VERSION 5.8 ;
BUSBITCHARS "[]" ;
DIVIDERCHAR "/" ;
UNITS
    DATABASE MICRONS 1000 ;
END UNITS

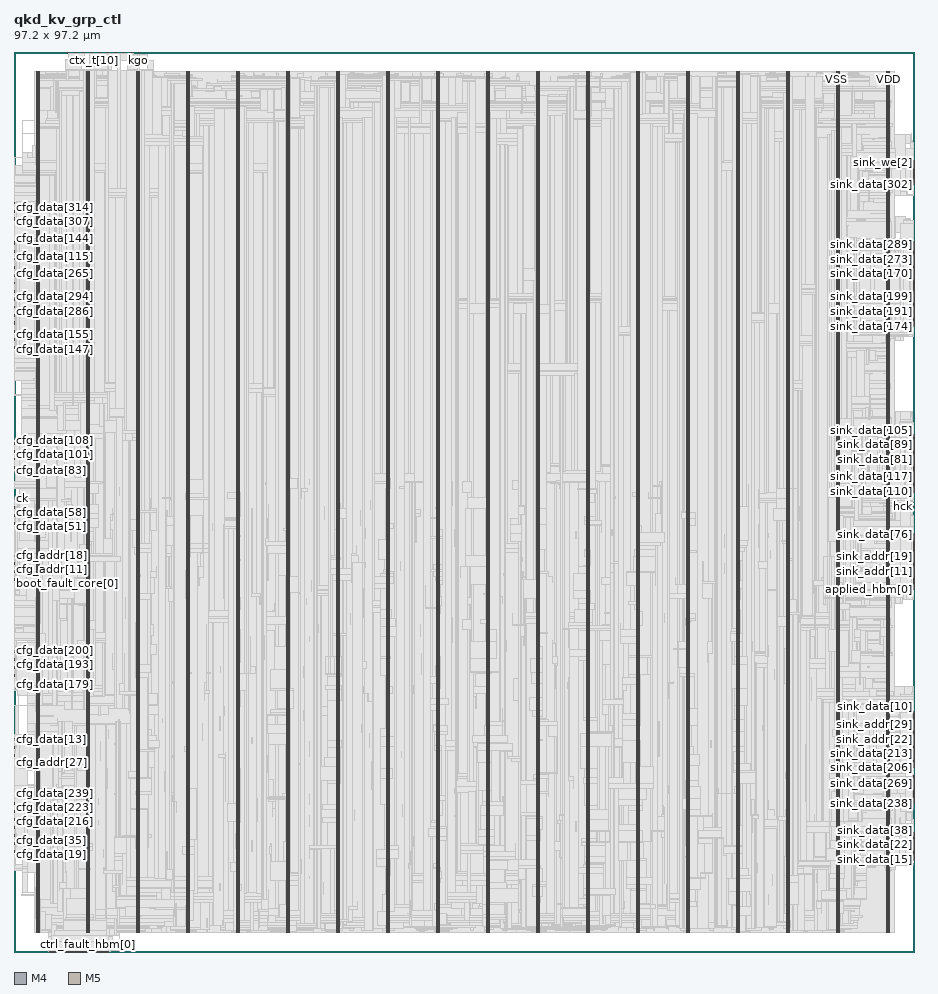
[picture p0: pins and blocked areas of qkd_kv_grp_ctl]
MACRO qkd_kv_grp_ctl
  FOREIGN qkd_kv_grp_ctl 0 0 ;
  CLASS BLOCK ;
  SIZE 97.2 BY 97.2 ;
  PIN applied_hbm[0]
    DIRECTION OUTPUT ;
    USE SIGNAL ;
    PORT
      LAYER M4 ;
        RECT  97.116 39.12 97.2 39.144 ;
    END
  END applied_hbm[0]
  PIN applied_hbm[1]
    DIRECTION OUTPUT ;
    USE SIGNAL ;
    PORT
      LAYER M4 ;
        RECT  97.116 39.216 97.2 39.24 ;
    END
  END applied_hbm[1]
  PIN applied_hbm[2]
    DIRECTION OUTPUT ;
    USE SIGNAL ;
    PORT
      LAYER M4 ;
        RECT  97.116 39.312 97.2 39.336 ;
    END
  END applied_hbm[2]
  PIN applied_hbm[3]
    DIRECTION OUTPUT ;
    USE SIGNAL ;
    PORT
      LAYER M4 ;
        RECT  97.116 39.408 97.2 39.432 ;
    END
  END applied_hbm[3]
  PIN applied_hbm[4]
    DIRECTION OUTPUT ;
    USE SIGNAL ;
    PORT
      LAYER M4 ;
        RECT  97.116 39.504 97.2 39.528 ;
    END
  END applied_hbm[4]
  PIN boot_fault_core[0]
    DIRECTION OUTPUT ;
    USE SIGNAL ;
    PORT
      LAYER M4 ;
        RECT  0 39.792 0.084 39.816 ;
    END
  END boot_fault_core[0]
  PIN boot_fault_core[1]
    DIRECTION OUTPUT ;
    USE SIGNAL ;
    PORT
      LAYER M4 ;
        RECT  0 39.888 0.084 39.912 ;
    END
  END boot_fault_core[1]
  PIN boot_fault_core[2]
    DIRECTION OUTPUT ;
    USE SIGNAL ;
    PORT
      LAYER M4 ;
        RECT  0 39.984 0.084 40.008 ;
    END
  END boot_fault_core[2]
  PIN boot_fault_core[3]
    DIRECTION OUTPUT ;
    USE SIGNAL ;
    PORT
      LAYER M4 ;
        RECT  0 40.08 0.084 40.104 ;
    END
  END boot_fault_core[3]
  PIN boot_fault_core[4]
    DIRECTION OUTPUT ;
    USE SIGNAL ;
    PORT
      LAYER M4 ;
        RECT  0 40.176 0.084 40.2 ;
    END
  END boot_fault_core[4]
  PIN boot_fault_hbm[0]
    DIRECTION OUTPUT ;
    USE SIGNAL ;
    PORT
      LAYER M4 ;
        RECT  97.116 39.6 97.2 39.624 ;
    END
  END boot_fault_hbm[0]
  PIN boot_fault_hbm[1]
    DIRECTION OUTPUT ;
    USE SIGNAL ;
    PORT
      LAYER M4 ;
        RECT  97.116 39.696 97.2 39.72 ;
    END
  END boot_fault_hbm[1]
  PIN boot_fault_hbm[2]
    DIRECTION OUTPUT ;
    USE SIGNAL ;
    PORT
      LAYER M4 ;
        RECT  97.116 39.792 97.2 39.816 ;
    END
  END boot_fault_hbm[2]
  PIN boot_fault_hbm[3]
    DIRECTION OUTPUT ;
    USE SIGNAL ;
    PORT
      LAYER M4 ;
        RECT  97.116 39.888 97.2 39.912 ;
    END
  END boot_fault_hbm[3]
  PIN boot_fault_hbm[4]
    DIRECTION OUTPUT ;
    USE SIGNAL ;
    PORT
      LAYER M4 ;
        RECT  97.116 39.984 97.2 40.008 ;
    END
  END boot_fault_hbm[4]
  PIN cfg_addr[0]
    DIRECTION INPUT ;
    USE SIGNAL ;
    PORT
      LAYER M4 ;
        RECT  0 40.272 0.084 40.296 ;
    END
  END cfg_addr[0]
  PIN cfg_addr[10]
    DIRECTION INPUT ;
    USE SIGNAL ;
    PORT
      LAYER M4 ;
        RECT  0 41.232 0.084 41.256 ;
    END
  END cfg_addr[10]
  PIN cfg_addr[11]
    DIRECTION INPUT ;
    USE SIGNAL ;
    PORT
      LAYER M4 ;
        RECT  0 41.328 0.084 41.352 ;
    END
  END cfg_addr[11]
  PIN cfg_addr[12]
    DIRECTION INPUT ;
    USE SIGNAL ;
    PORT
      LAYER M4 ;
        RECT  0 41.424 0.084 41.448 ;
    END
  END cfg_addr[12]
  PIN cfg_addr[13]
    DIRECTION INPUT ;
    USE SIGNAL ;
    PORT
      LAYER M4 ;
        RECT  0 41.52 0.084 41.544 ;
    END
  END cfg_addr[13]
  PIN cfg_addr[14]
    DIRECTION INPUT ;
    USE SIGNAL ;
    PORT
      LAYER M4 ;
        RECT  0 41.616 0.084 41.64 ;
    END
  END cfg_addr[14]
  PIN cfg_addr[15]
    DIRECTION INPUT ;
    USE SIGNAL ;
    PORT
      LAYER M4 ;
        RECT  0 41.712 0.084 41.736 ;
    END
  END cfg_addr[15]
  PIN cfg_addr[16]
    DIRECTION INPUT ;
    USE SIGNAL ;
    PORT
      LAYER M4 ;
        RECT  0 41.808 0.084 41.832 ;
    END
  END cfg_addr[16]
  PIN cfg_addr[17]
    DIRECTION INPUT ;
    USE SIGNAL ;
    PORT
      LAYER M4 ;
        RECT  0 41.904 0.084 41.928 ;
    END
  END cfg_addr[17]
  PIN cfg_addr[18]
    DIRECTION INPUT ;
    USE SIGNAL ;
    PORT
      LAYER M4 ;
        RECT  0 42 0.084 42.024 ;
    END
  END cfg_addr[18]
  PIN cfg_addr[19]
    DIRECTION INPUT ;
    USE SIGNAL ;
    PORT
      LAYER M4 ;
        RECT  0 42.096 0.084 42.12 ;
    END
  END cfg_addr[19]
  PIN cfg_addr[1]
    DIRECTION INPUT ;
    USE SIGNAL ;
    PORT
      LAYER M4 ;
        RECT  0 40.368 0.084 40.392 ;
    END
  END cfg_addr[1]
  PIN cfg_addr[20]
    DIRECTION INPUT ;
    USE SIGNAL ;
    PORT
      LAYER M4 ;
        RECT  0 42.192 0.084 42.216 ;
    END
  END cfg_addr[20]
  PIN cfg_addr[21]
    DIRECTION INPUT ;
    USE SIGNAL ;
    PORT
      LAYER M4 ;
        RECT  0 42.288 0.084 42.312 ;
    END
  END cfg_addr[21]
  PIN cfg_addr[22]
    DIRECTION INPUT ;
    USE SIGNAL ;
    PORT
      LAYER M4 ;
        RECT  0 42.384 0.084 42.408 ;
    END
  END cfg_addr[22]
  PIN cfg_addr[23]
    DIRECTION INPUT ;
    USE SIGNAL ;
    PORT
      LAYER M4 ;
        RECT  0 42.48 0.084 42.504 ;
    END
  END cfg_addr[23]
  PIN cfg_addr[24]
    DIRECTION INPUT ;
    USE SIGNAL ;
    PORT
      LAYER M4 ;
        RECT  0 42.576 0.084 42.6 ;
    END
  END cfg_addr[24]
  PIN cfg_addr[25]
    DIRECTION INPUT ;
    USE SIGNAL ;
    PORT
      LAYER M4 ;
        RECT  0 42.672 0.084 42.696 ;
    END
  END cfg_addr[25]
  PIN cfg_addr[26]
    DIRECTION INPUT ;
    USE SIGNAL ;
    PORT
      LAYER M4 ;
        RECT  0 42.768 0.084 42.792 ;
    END
  END cfg_addr[26]
  PIN cfg_addr[27]
    DIRECTION INPUT ;
    USE SIGNAL ;
    PORT
      LAYER M4 ;
        RECT  0 20.496 0.084 20.52 ;
    END
  END cfg_addr[27]
  PIN cfg_addr[28]
    DIRECTION INPUT ;
    USE SIGNAL ;
    PORT
      LAYER M4 ;
        RECT  0 20.592 0.084 20.616 ;
    END
  END cfg_addr[28]
  PIN cfg_addr[29]
    DIRECTION INPUT ;
    USE SIGNAL ;
    PORT
      LAYER M4 ;
        RECT  0 20.688 0.084 20.712 ;
    END
  END cfg_addr[29]
  PIN cfg_addr[2]
    DIRECTION INPUT ;
    USE SIGNAL ;
    PORT
      LAYER M4 ;
        RECT  0 40.464 0.084 40.488 ;
    END
  END cfg_addr[2]
  PIN cfg_addr[30]
    DIRECTION INPUT ;
    USE SIGNAL ;
    PORT
      LAYER M4 ;
        RECT  0 20.784 0.084 20.808 ;
    END
  END cfg_addr[30]
  PIN cfg_addr[31]
    DIRECTION INPUT ;
    USE SIGNAL ;
    PORT
      LAYER M4 ;
        RECT  0 20.88 0.084 20.904 ;
    END
  END cfg_addr[31]
  PIN cfg_addr[32]
    DIRECTION INPUT ;
    USE SIGNAL ;
    PORT
      LAYER M4 ;
        RECT  0 20.976 0.084 21 ;
    END
  END cfg_addr[32]
  PIN cfg_addr[33]
    DIRECTION INPUT ;
    USE SIGNAL ;
    PORT
      LAYER M4 ;
        RECT  0 21.072 0.084 21.096 ;
    END
  END cfg_addr[33]
  PIN cfg_addr[34]
    DIRECTION INPUT ;
    USE SIGNAL ;
    PORT
      LAYER M4 ;
        RECT  0 21.168 0.084 21.192 ;
    END
  END cfg_addr[34]
  PIN cfg_addr[35]
    DIRECTION INPUT ;
    USE SIGNAL ;
    PORT
      LAYER M4 ;
        RECT  0 21.264 0.084 21.288 ;
    END
  END cfg_addr[35]
  PIN cfg_addr[36]
    DIRECTION INPUT ;
    USE SIGNAL ;
    PORT
      LAYER M4 ;
        RECT  0 21.36 0.084 21.384 ;
    END
  END cfg_addr[36]
  PIN cfg_addr[37]
    DIRECTION INPUT ;
    USE SIGNAL ;
    PORT
      LAYER M4 ;
        RECT  0 21.456 0.084 21.48 ;
    END
  END cfg_addr[37]
  PIN cfg_addr[38]
    DIRECTION INPUT ;
    USE SIGNAL ;
    PORT
      LAYER M4 ;
        RECT  0 21.552 0.084 21.576 ;
    END
  END cfg_addr[38]
  PIN cfg_addr[39]
    DIRECTION INPUT ;
    USE SIGNAL ;
    PORT
      LAYER M4 ;
        RECT  0 21.648 0.084 21.672 ;
    END
  END cfg_addr[39]
  PIN cfg_addr[3]
    DIRECTION INPUT ;
    USE SIGNAL ;
    PORT
      LAYER M4 ;
        RECT  0 40.56 0.084 40.584 ;
    END
  END cfg_addr[3]
  PIN cfg_addr[4]
    DIRECTION INPUT ;
    USE SIGNAL ;
    PORT
      LAYER M4 ;
        RECT  0 40.656 0.084 40.68 ;
    END
  END cfg_addr[4]
  PIN cfg_addr[5]
    DIRECTION INPUT ;
    USE SIGNAL ;
    PORT
      LAYER M4 ;
        RECT  0 40.752 0.084 40.776 ;
    END
  END cfg_addr[5]
  PIN cfg_addr[6]
    DIRECTION INPUT ;
    USE SIGNAL ;
    PORT
      LAYER M4 ;
        RECT  0 40.848 0.084 40.872 ;
    END
  END cfg_addr[6]
  PIN cfg_addr[7]
    DIRECTION INPUT ;
    USE SIGNAL ;
    PORT
      LAYER M4 ;
        RECT  0 40.944 0.084 40.968 ;
    END
  END cfg_addr[7]
  PIN cfg_addr[8]
    DIRECTION INPUT ;
    USE SIGNAL ;
    PORT
      LAYER M4 ;
        RECT  0 41.04 0.084 41.064 ;
    END
  END cfg_addr[8]
  PIN cfg_addr[9]
    DIRECTION INPUT ;
    USE SIGNAL ;
    PORT
      LAYER M4 ;
        RECT  0 41.136 0.084 41.16 ;
    END
  END cfg_addr[9]
  PIN cfg_data[0]
    DIRECTION INPUT ;
    USE SIGNAL ;
    PORT
      LAYER M4 ;
        RECT  0 21.744 0.084 21.768 ;
    END
  END cfg_data[0]
  PIN cfg_data[100]
    DIRECTION INPUT ;
    USE SIGNAL ;
    PORT
      LAYER M4 ;
        RECT  0 53.616 0.084 53.64 ;
    END
  END cfg_data[100]
  PIN cfg_data[101]
    DIRECTION INPUT ;
    USE SIGNAL ;
    PORT
      LAYER M4 ;
        RECT  0 53.712 0.084 53.736 ;
    END
  END cfg_data[101]
  PIN cfg_data[102]
    DIRECTION INPUT ;
    USE SIGNAL ;
    PORT
      LAYER M4 ;
        RECT  0 53.808 0.084 53.832 ;
    END
  END cfg_data[102]
  PIN cfg_data[103]
    DIRECTION INPUT ;
    USE SIGNAL ;
    PORT
      LAYER M4 ;
        RECT  0 53.904 0.084 53.928 ;
    END
  END cfg_data[103]
  PIN cfg_data[104]
    DIRECTION INPUT ;
    USE SIGNAL ;
    PORT
      LAYER M4 ;
        RECT  0 54 0.084 54.024 ;
    END
  END cfg_data[104]
  PIN cfg_data[105]
    DIRECTION INPUT ;
    USE SIGNAL ;
    PORT
      LAYER M4 ;
        RECT  0 54.096 0.084 54.12 ;
    END
  END cfg_data[105]
  PIN cfg_data[106]
    DIRECTION INPUT ;
    USE SIGNAL ;
    PORT
      LAYER M4 ;
        RECT  0 54.192 0.084 54.216 ;
    END
  END cfg_data[106]
  PIN cfg_data[107]
    DIRECTION INPUT ;
    USE SIGNAL ;
    PORT
      LAYER M4 ;
        RECT  0 54.288 0.084 54.312 ;
    END
  END cfg_data[107]
  PIN cfg_data[108]
    DIRECTION INPUT ;
    USE SIGNAL ;
    PORT
      LAYER M4 ;
        RECT  0 54.384 0.084 54.408 ;
    END
  END cfg_data[108]
  PIN cfg_data[109]
    DIRECTION INPUT ;
    USE SIGNAL ;
    PORT
      LAYER M4 ;
        RECT  0 54.48 0.084 54.504 ;
    END
  END cfg_data[109]
  PIN cfg_data[10]
    DIRECTION INPUT ;
    USE SIGNAL ;
    PORT
      LAYER M4 ;
        RECT  0 22.704 0.084 22.728 ;
    END
  END cfg_data[10]
  PIN cfg_data[110]
    DIRECTION INPUT ;
    USE SIGNAL ;
    PORT
      LAYER M4 ;
        RECT  0 54.576 0.084 54.6 ;
    END
  END cfg_data[110]
  PIN cfg_data[111]
    DIRECTION INPUT ;
    USE SIGNAL ;
    PORT
      LAYER M4 ;
        RECT  0 54.672 0.084 54.696 ;
    END
  END cfg_data[111]
  PIN cfg_data[112]
    DIRECTION INPUT ;
    USE SIGNAL ;
    PORT
      LAYER M4 ;
        RECT  0 54.768 0.084 54.792 ;
    END
  END cfg_data[112]
  PIN cfg_data[113]
    DIRECTION INPUT ;
    USE SIGNAL ;
    PORT
      LAYER M4 ;
        RECT  0 54.864 0.084 54.888 ;
    END
  END cfg_data[113]
  PIN cfg_data[114]
    DIRECTION INPUT ;
    USE SIGNAL ;
    PORT
      LAYER M4 ;
        RECT  0 54.96 0.084 54.984 ;
    END
  END cfg_data[114]
  PIN cfg_data[115]
    DIRECTION INPUT ;
    USE SIGNAL ;
    PORT
      LAYER M4 ;
        RECT  0 74.256 0.084 74.28 ;
    END
  END cfg_data[115]
  PIN cfg_data[116]
    DIRECTION INPUT ;
    USE SIGNAL ;
    PORT
      LAYER M4 ;
        RECT  0 74.352 0.084 74.376 ;
    END
  END cfg_data[116]
  PIN cfg_data[117]
    DIRECTION INPUT ;
    USE SIGNAL ;
    PORT
      LAYER M4 ;
        RECT  0 74.448 0.084 74.472 ;
    END
  END cfg_data[117]
  PIN cfg_data[118]
    DIRECTION INPUT ;
    USE SIGNAL ;
    PORT
      LAYER M4 ;
        RECT  0 74.544 0.084 74.568 ;
    END
  END cfg_data[118]
  PIN cfg_data[119]
    DIRECTION INPUT ;
    USE SIGNAL ;
    PORT
      LAYER M4 ;
        RECT  0 74.64 0.084 74.664 ;
    END
  END cfg_data[119]
  PIN cfg_data[11]
    DIRECTION INPUT ;
    USE SIGNAL ;
    PORT
      LAYER M4 ;
        RECT  0 22.8 0.084 22.824 ;
    END
  END cfg_data[11]
  PIN cfg_data[120]
    DIRECTION INPUT ;
    USE SIGNAL ;
    PORT
      LAYER M4 ;
        RECT  0 74.736 0.084 74.76 ;
    END
  END cfg_data[120]
  PIN cfg_data[121]
    DIRECTION INPUT ;
    USE SIGNAL ;
    PORT
      LAYER M4 ;
        RECT  0 74.832 0.084 74.856 ;
    END
  END cfg_data[121]
  PIN cfg_data[122]
    DIRECTION INPUT ;
    USE SIGNAL ;
    PORT
      LAYER M4 ;
        RECT  0 74.928 0.084 74.952 ;
    END
  END cfg_data[122]
  PIN cfg_data[123]
    DIRECTION INPUT ;
    USE SIGNAL ;
    PORT
      LAYER M4 ;
        RECT  0 75.024 0.084 75.048 ;
    END
  END cfg_data[123]
  PIN cfg_data[124]
    DIRECTION INPUT ;
    USE SIGNAL ;
    PORT
      LAYER M4 ;
        RECT  0 75.12 0.084 75.144 ;
    END
  END cfg_data[124]
  PIN cfg_data[125]
    DIRECTION INPUT ;
    USE SIGNAL ;
    PORT
      LAYER M4 ;
        RECT  0 75.216 0.084 75.24 ;
    END
  END cfg_data[125]
  PIN cfg_data[126]
    DIRECTION INPUT ;
    USE SIGNAL ;
    PORT
      LAYER M4 ;
        RECT  0 75.312 0.084 75.336 ;
    END
  END cfg_data[126]
  PIN cfg_data[127]
    DIRECTION INPUT ;
    USE SIGNAL ;
    PORT
      LAYER M4 ;
        RECT  0 75.408 0.084 75.432 ;
    END
  END cfg_data[127]
  PIN cfg_data[128]
    DIRECTION INPUT ;
    USE SIGNAL ;
    PORT
      LAYER M4 ;
        RECT  0 75.504 0.084 75.528 ;
    END
  END cfg_data[128]
  PIN cfg_data[129]
    DIRECTION INPUT ;
    USE SIGNAL ;
    PORT
      LAYER M4 ;
        RECT  0 75.6 0.084 75.624 ;
    END
  END cfg_data[129]
  PIN cfg_data[12]
    DIRECTION INPUT ;
    USE SIGNAL ;
    PORT
      LAYER M4 ;
        RECT  0 22.896 0.084 22.92 ;
    END
  END cfg_data[12]
  PIN cfg_data[130]
    DIRECTION INPUT ;
    USE SIGNAL ;
    PORT
      LAYER M4 ;
        RECT  0 75.696 0.084 75.72 ;
    END
  END cfg_data[130]
  PIN cfg_data[131]
    DIRECTION INPUT ;
    USE SIGNAL ;
    PORT
      LAYER M4 ;
        RECT  0 75.792 0.084 75.816 ;
    END
  END cfg_data[131]
  PIN cfg_data[132]
    DIRECTION INPUT ;
    USE SIGNAL ;
    PORT
      LAYER M4 ;
        RECT  0 75.888 0.084 75.912 ;
    END
  END cfg_data[132]
  PIN cfg_data[133]
    DIRECTION INPUT ;
    USE SIGNAL ;
    PORT
      LAYER M4 ;
        RECT  0 75.984 0.084 76.008 ;
    END
  END cfg_data[133]
  PIN cfg_data[134]
    DIRECTION INPUT ;
    USE SIGNAL ;
    PORT
      LAYER M4 ;
        RECT  0 76.08 0.084 76.104 ;
    END
  END cfg_data[134]
  PIN cfg_data[135]
    DIRECTION INPUT ;
    USE SIGNAL ;
    PORT
      LAYER M4 ;
        RECT  0 76.176 0.084 76.2 ;
    END
  END cfg_data[135]
  PIN cfg_data[136]
    DIRECTION INPUT ;
    USE SIGNAL ;
    PORT
      LAYER M4 ;
        RECT  0 76.272 0.084 76.296 ;
    END
  END cfg_data[136]
  PIN cfg_data[137]
    DIRECTION INPUT ;
    USE SIGNAL ;
    PORT
      LAYER M4 ;
        RECT  0 76.368 0.084 76.392 ;
    END
  END cfg_data[137]
  PIN cfg_data[138]
    DIRECTION INPUT ;
    USE SIGNAL ;
    PORT
      LAYER M4 ;
        RECT  0 76.464 0.084 76.488 ;
    END
  END cfg_data[138]
  PIN cfg_data[139]
    DIRECTION INPUT ;
    USE SIGNAL ;
    PORT
      LAYER M4 ;
        RECT  0 76.56 0.084 76.584 ;
    END
  END cfg_data[139]
  PIN cfg_data[13]
    DIRECTION INPUT ;
    USE SIGNAL ;
    PORT
      LAYER M4 ;
        RECT  0 22.992 0.084 23.016 ;
    END
  END cfg_data[13]
  PIN cfg_data[140]
    DIRECTION INPUT ;
    USE SIGNAL ;
    PORT
      LAYER M4 ;
        RECT  0 76.656 0.084 76.68 ;
    END
  END cfg_data[140]
  PIN cfg_data[141]
    DIRECTION INPUT ;
    USE SIGNAL ;
    PORT
      LAYER M4 ;
        RECT  0 76.752 0.084 76.776 ;
    END
  END cfg_data[141]
  PIN cfg_data[142]
    DIRECTION INPUT ;
    USE SIGNAL ;
    PORT
      LAYER M4 ;
        RECT  0 76.848 0.084 76.872 ;
    END
  END cfg_data[142]
  PIN cfg_data[143]
    DIRECTION INPUT ;
    USE SIGNAL ;
    PORT
      LAYER M4 ;
        RECT  0 76.944 0.084 76.968 ;
    END
  END cfg_data[143]
  PIN cfg_data[144]
    DIRECTION INPUT ;
    USE SIGNAL ;
    PORT
      LAYER M4 ;
        RECT  0 77.04 0.084 77.064 ;
    END
  END cfg_data[144]
  PIN cfg_data[145]
    DIRECTION INPUT ;
    USE SIGNAL ;
    PORT
      LAYER M4 ;
        RECT  0 77.136 0.084 77.16 ;
    END
  END cfg_data[145]
  PIN cfg_data[146]
    DIRECTION INPUT ;
    USE SIGNAL ;
    PORT
      LAYER M4 ;
        RECT  0 77.232 0.084 77.256 ;
    END
  END cfg_data[146]
  PIN cfg_data[147]
    DIRECTION INPUT ;
    USE SIGNAL ;
    PORT
      LAYER M4 ;
        RECT  0 65.04 0.084 65.064 ;
    END
  END cfg_data[147]
  PIN cfg_data[148]
    DIRECTION INPUT ;
    USE SIGNAL ;
    PORT
      LAYER M4 ;
        RECT  0 65.136 0.084 65.16 ;
    END
  END cfg_data[148]
  PIN cfg_data[149]
    DIRECTION INPUT ;
    USE SIGNAL ;
    PORT
      LAYER M4 ;
        RECT  0 65.232 0.084 65.256 ;
    END
  END cfg_data[149]
  PIN cfg_data[14]
    DIRECTION INPUT ;
    USE SIGNAL ;
    PORT
      LAYER M4 ;
        RECT  0 23.088 0.084 23.112 ;
    END
  END cfg_data[14]
  PIN cfg_data[150]
    DIRECTION INPUT ;
    USE SIGNAL ;
    PORT
      LAYER M4 ;
        RECT  0 65.328 0.084 65.352 ;
    END
  END cfg_data[150]
  PIN cfg_data[151]
    DIRECTION INPUT ;
    USE SIGNAL ;
    PORT
      LAYER M4 ;
        RECT  0 65.424 0.084 65.448 ;
    END
  END cfg_data[151]
  PIN cfg_data[152]
    DIRECTION INPUT ;
    USE SIGNAL ;
    PORT
      LAYER M4 ;
        RECT  0 65.52 0.084 65.544 ;
    END
  END cfg_data[152]
  PIN cfg_data[153]
    DIRECTION INPUT ;
    USE SIGNAL ;
    PORT
      LAYER M4 ;
        RECT  0 65.616 0.084 65.64 ;
    END
  END cfg_data[153]
  PIN cfg_data[154]
    DIRECTION INPUT ;
    USE SIGNAL ;
    PORT
      LAYER M4 ;
        RECT  0 65.712 0.084 65.736 ;
    END
  END cfg_data[154]
  PIN cfg_data[155]
    DIRECTION INPUT ;
    USE SIGNAL ;
    PORT
      LAYER M4 ;
        RECT  0 65.808 0.084 65.832 ;
    END
  END cfg_data[155]
  PIN cfg_data[156]
    DIRECTION INPUT ;
    USE SIGNAL ;
    PORT
      LAYER M4 ;
        RECT  0 65.904 0.084 65.928 ;
    END
  END cfg_data[156]
  PIN cfg_data[157]
    DIRECTION INPUT ;
    USE SIGNAL ;
    PORT
      LAYER M4 ;
        RECT  0 66 0.084 66.024 ;
    END
  END cfg_data[157]
  PIN cfg_data[158]
    DIRECTION INPUT ;
    USE SIGNAL ;
    PORT
      LAYER M4 ;
        RECT  0 66.096 0.084 66.12 ;
    END
  END cfg_data[158]
  PIN cfg_data[159]
    DIRECTION INPUT ;
    USE SIGNAL ;
    PORT
      LAYER M4 ;
        RECT  0 66.192 0.084 66.216 ;
    END
  END cfg_data[159]
  PIN cfg_data[15]
    DIRECTION INPUT ;
    USE SIGNAL ;
    PORT
      LAYER M4 ;
        RECT  0 23.184 0.084 23.208 ;
    END
  END cfg_data[15]
  PIN cfg_data[160]
    DIRECTION INPUT ;
    USE SIGNAL ;
    PORT
      LAYER M4 ;
        RECT  0 66.288 0.084 66.312 ;
    END
  END cfg_data[160]
  PIN cfg_data[161]
    DIRECTION INPUT ;
    USE SIGNAL ;
    PORT
      LAYER M4 ;
        RECT  0 66.384 0.084 66.408 ;
    END
  END cfg_data[161]
  PIN cfg_data[162]
    DIRECTION INPUT ;
    USE SIGNAL ;
    PORT
      LAYER M4 ;
        RECT  0 66.48 0.084 66.504 ;
    END
  END cfg_data[162]
  PIN cfg_data[163]
    DIRECTION INPUT ;
    USE SIGNAL ;
    PORT
      LAYER M4 ;
        RECT  0 66.576 0.084 66.6 ;
    END
  END cfg_data[163]
  PIN cfg_data[164]
    DIRECTION INPUT ;
    USE SIGNAL ;
    PORT
      LAYER M4 ;
        RECT  0 66.672 0.084 66.696 ;
    END
  END cfg_data[164]
  PIN cfg_data[165]
    DIRECTION INPUT ;
    USE SIGNAL ;
    PORT
      LAYER M4 ;
        RECT  0 66.768 0.084 66.792 ;
    END
  END cfg_data[165]
  PIN cfg_data[166]
    DIRECTION INPUT ;
    USE SIGNAL ;
    PORT
      LAYER M4 ;
        RECT  0 66.864 0.084 66.888 ;
    END
  END cfg_data[166]
  PIN cfg_data[167]
    DIRECTION INPUT ;
    USE SIGNAL ;
    PORT
      LAYER M4 ;
        RECT  0 66.96 0.084 66.984 ;
    END
  END cfg_data[167]
  PIN cfg_data[168]
    DIRECTION INPUT ;
    USE SIGNAL ;
    PORT
      LAYER M4 ;
        RECT  0 67.056 0.084 67.08 ;
    END
  END cfg_data[168]
  PIN cfg_data[169]
    DIRECTION INPUT ;
    USE SIGNAL ;
    PORT
      LAYER M4 ;
        RECT  0 67.152 0.084 67.176 ;
    END
  END cfg_data[169]
  PIN cfg_data[16]
    DIRECTION INPUT ;
    USE SIGNAL ;
    PORT
      LAYER M4 ;
        RECT  0 23.28 0.084 23.304 ;
    END
  END cfg_data[16]
  PIN cfg_data[170]
    DIRECTION INPUT ;
    USE SIGNAL ;
    PORT
      LAYER M4 ;
        RECT  0 67.248 0.084 67.272 ;
    END
  END cfg_data[170]
  PIN cfg_data[171]
    DIRECTION INPUT ;
    USE SIGNAL ;
    PORT
      LAYER M4 ;
        RECT  0 67.344 0.084 67.368 ;
    END
  END cfg_data[171]
  PIN cfg_data[172]
    DIRECTION INPUT ;
    USE SIGNAL ;
    PORT
      LAYER M4 ;
        RECT  0 67.44 0.084 67.464 ;
    END
  END cfg_data[172]
  PIN cfg_data[173]
    DIRECTION INPUT ;
    USE SIGNAL ;
    PORT
      LAYER M4 ;
        RECT  0 67.536 0.084 67.56 ;
    END
  END cfg_data[173]
  PIN cfg_data[174]
    DIRECTION INPUT ;
    USE SIGNAL ;
    PORT
      LAYER M4 ;
        RECT  0 67.632 0.084 67.656 ;
    END
  END cfg_data[174]
  PIN cfg_data[175]
    DIRECTION INPUT ;
    USE SIGNAL ;
    PORT
      LAYER M4 ;
        RECT  0 67.728 0.084 67.752 ;
    END
  END cfg_data[175]
  PIN cfg_data[176]
    DIRECTION INPUT ;
    USE SIGNAL ;
    PORT
      LAYER M4 ;
        RECT  0 67.824 0.084 67.848 ;
    END
  END cfg_data[176]
  PIN cfg_data[177]
    DIRECTION INPUT ;
    USE SIGNAL ;
    PORT
      LAYER M4 ;
        RECT  0 67.92 0.084 67.944 ;
    END
  END cfg_data[177]
  PIN cfg_data[178]
    DIRECTION INPUT ;
    USE SIGNAL ;
    PORT
      LAYER M4 ;
        RECT  0 68.016 0.084 68.04 ;
    END
  END cfg_data[178]
  PIN cfg_data[179]
    DIRECTION INPUT ;
    USE SIGNAL ;
    PORT
      LAYER M4 ;
        RECT  0 29.712 0.084 29.736 ;
    END
  END cfg_data[179]
  PIN cfg_data[17]
    DIRECTION INPUT ;
    USE SIGNAL ;
    PORT
      LAYER M4 ;
        RECT  0 23.376 0.084 23.4 ;
    END
  END cfg_data[17]
  PIN cfg_data[180]
    DIRECTION INPUT ;
    USE SIGNAL ;
    PORT
      LAYER M4 ;
        RECT  0 29.808 0.084 29.832 ;
    END
  END cfg_data[180]
  PIN cfg_data[181]
    DIRECTION INPUT ;
    USE SIGNAL ;
    PORT
      LAYER M4 ;
        RECT  0 29.904 0.084 29.928 ;
    END
  END cfg_data[181]
  PIN cfg_data[182]
    DIRECTION INPUT ;
    USE SIGNAL ;
    PORT
      LAYER M4 ;
        RECT  0 30 0.084 30.024 ;
    END
  END cfg_data[182]
  PIN cfg_data[183]
    DIRECTION INPUT ;
    USE SIGNAL ;
    PORT
      LAYER M4 ;
        RECT  0 30.096 0.084 30.12 ;
    END
  END cfg_data[183]
  PIN cfg_data[184]
    DIRECTION INPUT ;
    USE SIGNAL ;
    PORT
      LAYER M4 ;
        RECT  0 30.192 0.084 30.216 ;
    END
  END cfg_data[184]
  PIN cfg_data[185]
    DIRECTION INPUT ;
    USE SIGNAL ;
    PORT
      LAYER M4 ;
        RECT  0 30.288 0.084 30.312 ;
    END
  END cfg_data[185]
  PIN cfg_data[186]
    DIRECTION INPUT ;
    USE SIGNAL ;
    PORT
      LAYER M4 ;
        RECT  0 30.384 0.084 30.408 ;
    END
  END cfg_data[186]
  PIN cfg_data[187]
    DIRECTION INPUT ;
    USE SIGNAL ;
    PORT
      LAYER M4 ;
        RECT  0 30.48 0.084 30.504 ;
    END
  END cfg_data[187]
  PIN cfg_data[188]
    DIRECTION INPUT ;
    USE SIGNAL ;
    PORT
      LAYER M4 ;
        RECT  0 30.576 0.084 30.6 ;
    END
  END cfg_data[188]
  PIN cfg_data[189]
    DIRECTION INPUT ;
    USE SIGNAL ;
    PORT
      LAYER M4 ;
        RECT  0 30.672 0.084 30.696 ;
    END
  END cfg_data[189]
  PIN cfg_data[18]
    DIRECTION INPUT ;
    USE SIGNAL ;
    PORT
      LAYER M4 ;
        RECT  0 23.472 0.084 23.496 ;
    END
  END cfg_data[18]
  PIN cfg_data[190]
    DIRECTION INPUT ;
    USE SIGNAL ;
    PORT
      LAYER M4 ;
        RECT  0 30.768 0.084 30.792 ;
    END
  END cfg_data[190]
  PIN cfg_data[191]
    DIRECTION INPUT ;
    USE SIGNAL ;
    PORT
      LAYER M4 ;
        RECT  0 30.864 0.084 30.888 ;
    END
  END cfg_data[191]
  PIN cfg_data[192]
    DIRECTION INPUT ;
    USE SIGNAL ;
    PORT
      LAYER M4 ;
        RECT  0 30.96 0.084 30.984 ;
    END
  END cfg_data[192]
  PIN cfg_data[193]
    DIRECTION INPUT ;
    USE SIGNAL ;
    PORT
      LAYER M4 ;
        RECT  0 31.056 0.084 31.08 ;
    END
  END cfg_data[193]
  PIN cfg_data[194]
    DIRECTION INPUT ;
    USE SIGNAL ;
    PORT
      LAYER M4 ;
        RECT  0 31.152 0.084 31.176 ;
    END
  END cfg_data[194]
  PIN cfg_data[195]
    DIRECTION INPUT ;
    USE SIGNAL ;
    PORT
      LAYER M4 ;
        RECT  0 31.248 0.084 31.272 ;
    END
  END cfg_data[195]
  PIN cfg_data[196]
    DIRECTION INPUT ;
    USE SIGNAL ;
    PORT
      LAYER M4 ;
        RECT  0 31.344 0.084 31.368 ;
    END
  END cfg_data[196]
  PIN cfg_data[197]
    DIRECTION INPUT ;
    USE SIGNAL ;
    PORT
      LAYER M4 ;
        RECT  0 31.44 0.084 31.464 ;
    END
  END cfg_data[197]
  PIN cfg_data[198]
    DIRECTION INPUT ;
    USE SIGNAL ;
    PORT
      LAYER M4 ;
        RECT  0 31.536 0.084 31.56 ;
    END
  END cfg_data[198]
  PIN cfg_data[199]
    DIRECTION INPUT ;
    USE SIGNAL ;
    PORT
      LAYER M4 ;
        RECT  0 31.632 0.084 31.656 ;
    END
  END cfg_data[199]
  PIN cfg_data[19]
    DIRECTION INPUT ;
    USE SIGNAL ;
    PORT
      LAYER M4 ;
        RECT  0 10.512 0.084 10.536 ;
    END
  END cfg_data[19]
  PIN cfg_data[1]
    DIRECTION INPUT ;
    USE SIGNAL ;
    PORT
      LAYER M4 ;
        RECT  0 21.84 0.084 21.864 ;
    END
  END cfg_data[1]
  PIN cfg_data[200]
    DIRECTION INPUT ;
    USE SIGNAL ;
    PORT
      LAYER M4 ;
        RECT  0 31.728 0.084 31.752 ;
    END
  END cfg_data[200]
  PIN cfg_data[201]
    DIRECTION INPUT ;
    USE SIGNAL ;
    PORT
      LAYER M4 ;
        RECT  0 31.824 0.084 31.848 ;
    END
  END cfg_data[201]
  PIN cfg_data[202]
    DIRECTION INPUT ;
    USE SIGNAL ;
    PORT
      LAYER M4 ;
        RECT  0 31.92 0.084 31.944 ;
    END
  END cfg_data[202]
  PIN cfg_data[203]
    DIRECTION INPUT ;
    USE SIGNAL ;
    PORT
      LAYER M4 ;
        RECT  0 32.016 0.084 32.04 ;
    END
  END cfg_data[203]
  PIN cfg_data[204]
    DIRECTION INPUT ;
    USE SIGNAL ;
    PORT
      LAYER M4 ;
        RECT  0 32.112 0.084 32.136 ;
    END
  END cfg_data[204]
  PIN cfg_data[205]
    DIRECTION INPUT ;
    USE SIGNAL ;
    PORT
      LAYER M4 ;
        RECT  0 32.208 0.084 32.232 ;
    END
  END cfg_data[205]
  PIN cfg_data[206]
    DIRECTION INPUT ;
    USE SIGNAL ;
    PORT
      LAYER M4 ;
        RECT  0 32.304 0.084 32.328 ;
    END
  END cfg_data[206]
  PIN cfg_data[207]
    DIRECTION INPUT ;
    USE SIGNAL ;
    PORT
      LAYER M4 ;
        RECT  0 32.4 0.084 32.424 ;
    END
  END cfg_data[207]
  PIN cfg_data[208]
    DIRECTION INPUT ;
    USE SIGNAL ;
    PORT
      LAYER M4 ;
        RECT  0 32.496 0.084 32.52 ;
    END
  END cfg_data[208]
  PIN cfg_data[209]
    DIRECTION INPUT ;
    USE SIGNAL ;
    PORT
      LAYER M4 ;
        RECT  0 32.592 0.084 32.616 ;
    END
  END cfg_data[209]
  PIN cfg_data[20]
    DIRECTION INPUT ;
    USE SIGNAL ;
    PORT
      LAYER M4 ;
        RECT  0 10.608 0.084 10.632 ;
    END
  END cfg_data[20]
  PIN cfg_data[210]
    DIRECTION INPUT ;
    USE SIGNAL ;
    PORT
      LAYER M4 ;
        RECT  0 32.688 0.084 32.712 ;
    END
  END cfg_data[210]
  PIN cfg_data[211]
    DIRECTION INPUT ;
    USE SIGNAL ;
    PORT
      LAYER M4 ;
        RECT  0 13.584 0.084 13.608 ;
    END
  END cfg_data[211]
  PIN cfg_data[212]
    DIRECTION INPUT ;
    USE SIGNAL ;
    PORT
      LAYER M4 ;
        RECT  0 13.68 0.084 13.704 ;
    END
  END cfg_data[212]
  PIN cfg_data[213]
    DIRECTION INPUT ;
    USE SIGNAL ;
    PORT
      LAYER M4 ;
        RECT  0 13.776 0.084 13.8 ;
    END
  END cfg_data[213]
  PIN cfg_data[214]
    DIRECTION INPUT ;
    USE SIGNAL ;
    PORT
      LAYER M4 ;
        RECT  0 13.872 0.084 13.896 ;
    END
  END cfg_data[214]
  PIN cfg_data[215]
    DIRECTION INPUT ;
    USE SIGNAL ;
    PORT
      LAYER M4 ;
        RECT  0 13.968 0.084 13.992 ;
    END
  END cfg_data[215]
  PIN cfg_data[216]
    DIRECTION INPUT ;
    USE SIGNAL ;
    PORT
      LAYER M4 ;
        RECT  0 14.064 0.084 14.088 ;
    END
  END cfg_data[216]
  PIN cfg_data[217]
    DIRECTION INPUT ;
    USE SIGNAL ;
    PORT
      LAYER M4 ;
        RECT  0 14.16 0.084 14.184 ;
    END
  END cfg_data[217]
  PIN cfg_data[218]
    DIRECTION INPUT ;
    USE SIGNAL ;
    PORT
      LAYER M4 ;
        RECT  0 14.256 0.084 14.28 ;
    END
  END cfg_data[218]
  PIN cfg_data[219]
    DIRECTION INPUT ;
    USE SIGNAL ;
    PORT
      LAYER M4 ;
        RECT  0 14.352 0.084 14.376 ;
    END
  END cfg_data[219]
  PIN cfg_data[21]
    DIRECTION INPUT ;
    USE SIGNAL ;
    PORT
      LAYER M4 ;
        RECT  0 10.704 0.084 10.728 ;
    END
  END cfg_data[21]
  PIN cfg_data[220]
    DIRECTION INPUT ;
    USE SIGNAL ;
    PORT
      LAYER M4 ;
        RECT  0 14.448 0.084 14.472 ;
    END
  END cfg_data[220]
  PIN cfg_data[221]
    DIRECTION INPUT ;
    USE SIGNAL ;
    PORT
      LAYER M4 ;
        RECT  0 14.544 0.084 14.568 ;
    END
  END cfg_data[221]
  PIN cfg_data[222]
    DIRECTION INPUT ;
    USE SIGNAL ;
    PORT
      LAYER M4 ;
        RECT  0 14.64 0.084 14.664 ;
    END
  END cfg_data[222]
  PIN cfg_data[223]
    DIRECTION INPUT ;
    USE SIGNAL ;
    PORT
      LAYER M4 ;
        RECT  0 14.736 0.084 14.76 ;
    END
  END cfg_data[223]
  PIN cfg_data[224]
    DIRECTION INPUT ;
    USE SIGNAL ;
    PORT
      LAYER M4 ;
        RECT  0 14.832 0.084 14.856 ;
    END
  END cfg_data[224]
  PIN cfg_data[225]
    DIRECTION INPUT ;
    USE SIGNAL ;
    PORT
      LAYER M4 ;
        RECT  0 14.928 0.084 14.952 ;
    END
  END cfg_data[225]
  PIN cfg_data[226]
    DIRECTION INPUT ;
    USE SIGNAL ;
    PORT
      LAYER M4 ;
        RECT  0 15.024 0.084 15.048 ;
    END
  END cfg_data[226]
  PIN cfg_data[227]
    DIRECTION INPUT ;
    USE SIGNAL ;
    PORT
      LAYER M4 ;
        RECT  0 15.12 0.084 15.144 ;
    END
  END cfg_data[227]
  PIN cfg_data[228]
    DIRECTION INPUT ;
    USE SIGNAL ;
    PORT
      LAYER M4 ;
        RECT  0 15.216 0.084 15.24 ;
    END
  END cfg_data[228]
  PIN cfg_data[229]
    DIRECTION INPUT ;
    USE SIGNAL ;
    PORT
      LAYER M4 ;
        RECT  0 15.312 0.084 15.336 ;
    END
  END cfg_data[229]
  PIN cfg_data[22]
    DIRECTION INPUT ;
    USE SIGNAL ;
    PORT
      LAYER M4 ;
        RECT  0 10.8 0.084 10.824 ;
    END
  END cfg_data[22]
  PIN cfg_data[230]
    DIRECTION INPUT ;
    USE SIGNAL ;
    PORT
      LAYER M4 ;
        RECT  0 15.408 0.084 15.432 ;
    END
  END cfg_data[230]
  PIN cfg_data[231]
    DIRECTION INPUT ;
    USE SIGNAL ;
    PORT
      LAYER M4 ;
        RECT  0 15.504 0.084 15.528 ;
    END
  END cfg_data[231]
  PIN cfg_data[232]
    DIRECTION INPUT ;
    USE SIGNAL ;
    PORT
      LAYER M4 ;
        RECT  0 15.6 0.084 15.624 ;
    END
  END cfg_data[232]
  PIN cfg_data[233]
    DIRECTION INPUT ;
    USE SIGNAL ;
    PORT
      LAYER M4 ;
        RECT  0 15.696 0.084 15.72 ;
    END
  END cfg_data[233]
  PIN cfg_data[234]
    DIRECTION INPUT ;
    USE SIGNAL ;
    PORT
      LAYER M4 ;
        RECT  0 15.792 0.084 15.816 ;
    END
  END cfg_data[234]
  PIN cfg_data[235]
    DIRECTION INPUT ;
    USE SIGNAL ;
    PORT
      LAYER M4 ;
        RECT  0 15.888 0.084 15.912 ;
    END
  END cfg_data[235]
  PIN cfg_data[236]
    DIRECTION INPUT ;
    USE SIGNAL ;
    PORT
      LAYER M4 ;
        RECT  0 15.984 0.084 16.008 ;
    END
  END cfg_data[236]
  PIN cfg_data[237]
    DIRECTION INPUT ;
    USE SIGNAL ;
    PORT
      LAYER M4 ;
        RECT  0 16.08 0.084 16.104 ;
    END
  END cfg_data[237]
  PIN cfg_data[238]
    DIRECTION INPUT ;
    USE SIGNAL ;
    PORT
      LAYER M4 ;
        RECT  0 16.176 0.084 16.2 ;
    END
  END cfg_data[238]
  PIN cfg_data[239]
    DIRECTION INPUT ;
    USE SIGNAL ;
    PORT
      LAYER M4 ;
        RECT  0 16.272 0.084 16.296 ;
    END
  END cfg_data[239]
  PIN cfg_data[23]
    DIRECTION INPUT ;
    USE SIGNAL ;
    PORT
      LAYER M4 ;
        RECT  0 10.896 0.084 10.92 ;
    END
  END cfg_data[23]
  PIN cfg_data[240]
    DIRECTION INPUT ;
    USE SIGNAL ;
    PORT
      LAYER M4 ;
        RECT  0 16.368 0.084 16.392 ;
    END
  END cfg_data[240]
  PIN cfg_data[241]
    DIRECTION INPUT ;
    USE SIGNAL ;
    PORT
      LAYER M4 ;
        RECT  0 16.464 0.084 16.488 ;
    END
  END cfg_data[241]
  PIN cfg_data[242]
    DIRECTION INPUT ;
    USE SIGNAL ;
    PORT
      LAYER M4 ;
        RECT  0 16.56 0.084 16.584 ;
    END
  END cfg_data[242]
  PIN cfg_data[243]
    DIRECTION INPUT ;
    USE SIGNAL ;
    PORT
      LAYER M4 ;
        RECT  0 71.184 0.084 71.208 ;
    END
  END cfg_data[243]
  PIN cfg_data[244]
    DIRECTION INPUT ;
    USE SIGNAL ;
    PORT
      LAYER M4 ;
        RECT  0 71.28 0.084 71.304 ;
    END
  END cfg_data[244]
  PIN cfg_data[245]
    DIRECTION INPUT ;
    USE SIGNAL ;
    PORT
      LAYER M4 ;
        RECT  0 71.376 0.084 71.4 ;
    END
  END cfg_data[245]
  PIN cfg_data[246]
    DIRECTION INPUT ;
    USE SIGNAL ;
    PORT
      LAYER M4 ;
        RECT  0 71.472 0.084 71.496 ;
    END
  END cfg_data[246]
  PIN cfg_data[247]
    DIRECTION INPUT ;
    USE SIGNAL ;
    PORT
      LAYER M4 ;
        RECT  0 71.568 0.084 71.592 ;
    END
  END cfg_data[247]
  PIN cfg_data[248]
    DIRECTION INPUT ;
    USE SIGNAL ;
    PORT
      LAYER M4 ;
        RECT  0 71.664 0.084 71.688 ;
    END
  END cfg_data[248]
  PIN cfg_data[249]
    DIRECTION INPUT ;
    USE SIGNAL ;
    PORT
      LAYER M4 ;
        RECT  0 71.76 0.084 71.784 ;
    END
  END cfg_data[249]
  PIN cfg_data[24]
    DIRECTION INPUT ;
    USE SIGNAL ;
    PORT
      LAYER M4 ;
        RECT  0 10.992 0.084 11.016 ;
    END
  END cfg_data[24]
  PIN cfg_data[250]
    DIRECTION INPUT ;
    USE SIGNAL ;
    PORT
      LAYER M4 ;
        RECT  0 71.856 0.084 71.88 ;
    END
  END cfg_data[250]
  PIN cfg_data[251]
    DIRECTION INPUT ;
    USE SIGNAL ;
    PORT
      LAYER M4 ;
        RECT  0 71.952 0.084 71.976 ;
    END
  END cfg_data[251]
  PIN cfg_data[252]
    DIRECTION INPUT ;
    USE SIGNAL ;
    PORT
      LAYER M4 ;
        RECT  0 72.048 0.084 72.072 ;
    END
  END cfg_data[252]
  PIN cfg_data[253]
    DIRECTION INPUT ;
    USE SIGNAL ;
    PORT
      LAYER M4 ;
        RECT  0 72.144 0.084 72.168 ;
    END
  END cfg_data[253]
  PIN cfg_data[254]
    DIRECTION INPUT ;
    USE SIGNAL ;
    PORT
      LAYER M4 ;
        RECT  0 72.24 0.084 72.264 ;
    END
  END cfg_data[254]
  PIN cfg_data[255]
    DIRECTION INPUT ;
    USE SIGNAL ;
    PORT
      LAYER M4 ;
        RECT  0 72.336 0.084 72.36 ;
    END
  END cfg_data[255]
  PIN cfg_data[256]
    DIRECTION INPUT ;
    USE SIGNAL ;
    PORT
      LAYER M4 ;
        RECT  0 72.432 0.084 72.456 ;
    END
  END cfg_data[256]
  PIN cfg_data[257]
    DIRECTION INPUT ;
    USE SIGNAL ;
    PORT
      LAYER M4 ;
        RECT  0 72.528 0.084 72.552 ;
    END
  END cfg_data[257]
  PIN cfg_data[258]
    DIRECTION INPUT ;
    USE SIGNAL ;
    PORT
      LAYER M4 ;
        RECT  0 72.624 0.084 72.648 ;
    END
  END cfg_data[258]
  PIN cfg_data[259]
    DIRECTION INPUT ;
    USE SIGNAL ;
    PORT
      LAYER M4 ;
        RECT  0 72.72 0.084 72.744 ;
    END
  END cfg_data[259]
  PIN cfg_data[25]
    DIRECTION INPUT ;
    USE SIGNAL ;
    PORT
      LAYER M4 ;
        RECT  0 11.088 0.084 11.112 ;
    END
  END cfg_data[25]
  PIN cfg_data[260]
    DIRECTION INPUT ;
    USE SIGNAL ;
    PORT
      LAYER M4 ;
        RECT  0 72.816 0.084 72.84 ;
    END
  END cfg_data[260]
  PIN cfg_data[261]
    DIRECTION INPUT ;
    USE SIGNAL ;
    PORT
      LAYER M4 ;
        RECT  0 72.912 0.084 72.936 ;
    END
  END cfg_data[261]
  PIN cfg_data[262]
    DIRECTION INPUT ;
    USE SIGNAL ;
    PORT
      LAYER M4 ;
        RECT  0 73.008 0.084 73.032 ;
    END
  END cfg_data[262]
  PIN cfg_data[263]
    DIRECTION INPUT ;
    USE SIGNAL ;
    PORT
      LAYER M4 ;
        RECT  0 73.104 0.084 73.128 ;
    END
  END cfg_data[263]
  PIN cfg_data[264]
    DIRECTION INPUT ;
    USE SIGNAL ;
    PORT
      LAYER M4 ;
        RECT  0 73.2 0.084 73.224 ;
    END
  END cfg_data[264]
  PIN cfg_data[265]
    DIRECTION INPUT ;
    USE SIGNAL ;
    PORT
      LAYER M4 ;
        RECT  0 73.296 0.084 73.32 ;
    END
  END cfg_data[265]
  PIN cfg_data[266]
    DIRECTION INPUT ;
    USE SIGNAL ;
    PORT
      LAYER M4 ;
        RECT  0 73.392 0.084 73.416 ;
    END
  END cfg_data[266]
  PIN cfg_data[267]
    DIRECTION INPUT ;
    USE SIGNAL ;
    PORT
      LAYER M4 ;
        RECT  0 73.488 0.084 73.512 ;
    END
  END cfg_data[267]
  PIN cfg_data[268]
    DIRECTION INPUT ;
    USE SIGNAL ;
    PORT
      LAYER M4 ;
        RECT  0 73.584 0.084 73.608 ;
    END
  END cfg_data[268]
  PIN cfg_data[269]
    DIRECTION INPUT ;
    USE SIGNAL ;
    PORT
      LAYER M4 ;
        RECT  0 73.68 0.084 73.704 ;
    END
  END cfg_data[269]
  PIN cfg_data[26]
    DIRECTION INPUT ;
    USE SIGNAL ;
    PORT
      LAYER M4 ;
        RECT  0 11.184 0.084 11.208 ;
    END
  END cfg_data[26]
  PIN cfg_data[270]
    DIRECTION INPUT ;
    USE SIGNAL ;
    PORT
      LAYER M4 ;
        RECT  0 73.776 0.084 73.8 ;
    END
  END cfg_data[270]
  PIN cfg_data[271]
    DIRECTION INPUT ;
    USE SIGNAL ;
    PORT
      LAYER M4 ;
        RECT  0 73.872 0.084 73.896 ;
    END
  END cfg_data[271]
  PIN cfg_data[272]
    DIRECTION INPUT ;
    USE SIGNAL ;
    PORT
      LAYER M4 ;
        RECT  0 73.968 0.084 73.992 ;
    END
  END cfg_data[272]
  PIN cfg_data[273]
    DIRECTION INPUT ;
    USE SIGNAL ;
    PORT
      LAYER M4 ;
        RECT  0 74.064 0.084 74.088 ;
    END
  END cfg_data[273]
  PIN cfg_data[274]
    DIRECTION INPUT ;
    USE SIGNAL ;
    PORT
      LAYER M4 ;
        RECT  0 74.16 0.084 74.184 ;
    END
  END cfg_data[274]
  PIN cfg_data[275]
    DIRECTION INPUT ;
    USE SIGNAL ;
    PORT
      LAYER M4 ;
        RECT  0 68.112 0.084 68.136 ;
    END
  END cfg_data[275]
  PIN cfg_data[276]
    DIRECTION INPUT ;
    USE SIGNAL ;
    PORT
      LAYER M4 ;
        RECT  0 68.208 0.084 68.232 ;
    END
  END cfg_data[276]
  PIN cfg_data[277]
    DIRECTION INPUT ;
    USE SIGNAL ;
    PORT
      LAYER M4 ;
        RECT  0 68.304 0.084 68.328 ;
    END
  END cfg_data[277]
  PIN cfg_data[278]
    DIRECTION INPUT ;
    USE SIGNAL ;
    PORT
      LAYER M4 ;
        RECT  0 68.4 0.084 68.424 ;
    END
  END cfg_data[278]
  PIN cfg_data[279]
    DIRECTION INPUT ;
    USE SIGNAL ;
    PORT
      LAYER M4 ;
        RECT  0 68.496 0.084 68.52 ;
    END
  END cfg_data[279]
  PIN cfg_data[27]
    DIRECTION INPUT ;
    USE SIGNAL ;
    PORT
      LAYER M4 ;
        RECT  0 11.28 0.084 11.304 ;
    END
  END cfg_data[27]
  PIN cfg_data[280]
    DIRECTION INPUT ;
    USE SIGNAL ;
    PORT
      LAYER M4 ;
        RECT  0 68.592 0.084 68.616 ;
    END
  END cfg_data[280]
  PIN cfg_data[281]
    DIRECTION INPUT ;
    USE SIGNAL ;
    PORT
      LAYER M4 ;
        RECT  0 68.688 0.084 68.712 ;
    END
  END cfg_data[281]
  PIN cfg_data[282]
    DIRECTION INPUT ;
    USE SIGNAL ;
    PORT
      LAYER M4 ;
        RECT  0 68.784 0.084 68.808 ;
    END
  END cfg_data[282]
  PIN cfg_data[283]
    DIRECTION INPUT ;
    USE SIGNAL ;
    PORT
      LAYER M4 ;
        RECT  0 68.88 0.084 68.904 ;
    END
  END cfg_data[283]
  PIN cfg_data[284]
    DIRECTION INPUT ;
    USE SIGNAL ;
    PORT
      LAYER M4 ;
        RECT  0 68.976 0.084 69 ;
    END
  END cfg_data[284]
  PIN cfg_data[285]
    DIRECTION INPUT ;
    USE SIGNAL ;
    PORT
      LAYER M4 ;
        RECT  0 69.072 0.084 69.096 ;
    END
  END cfg_data[285]
  PIN cfg_data[286]
    DIRECTION INPUT ;
    USE SIGNAL ;
    PORT
      LAYER M4 ;
        RECT  0 69.168 0.084 69.192 ;
    END
  END cfg_data[286]
  PIN cfg_data[287]
    DIRECTION INPUT ;
    USE SIGNAL ;
    PORT
      LAYER M4 ;
        RECT  0 69.264 0.084 69.288 ;
    END
  END cfg_data[287]
  PIN cfg_data[288]
    DIRECTION INPUT ;
    USE SIGNAL ;
    PORT
      LAYER M4 ;
        RECT  0 69.36 0.084 69.384 ;
    END
  END cfg_data[288]
  PIN cfg_data[289]
    DIRECTION INPUT ;
    USE SIGNAL ;
    PORT
      LAYER M4 ;
        RECT  0 69.456 0.084 69.48 ;
    END
  END cfg_data[289]
  PIN cfg_data[28]
    DIRECTION INPUT ;
    USE SIGNAL ;
    PORT
      LAYER M4 ;
        RECT  0 11.376 0.084 11.4 ;
    END
  END cfg_data[28]
  PIN cfg_data[290]
    DIRECTION INPUT ;
    USE SIGNAL ;
    PORT
      LAYER M4 ;
        RECT  0 69.552 0.084 69.576 ;
    END
  END cfg_data[290]
  PIN cfg_data[291]
    DIRECTION INPUT ;
    USE SIGNAL ;
    PORT
      LAYER M4 ;
        RECT  0 69.648 0.084 69.672 ;
    END
  END cfg_data[291]
  PIN cfg_data[292]
    DIRECTION INPUT ;
    USE SIGNAL ;
    PORT
      LAYER M4 ;
        RECT  0 69.744 0.084 69.768 ;
    END
  END cfg_data[292]
  PIN cfg_data[293]
    DIRECTION INPUT ;
    USE SIGNAL ;
    PORT
      LAYER M4 ;
        RECT  0 69.84 0.084 69.864 ;
    END
  END cfg_data[293]
  PIN cfg_data[294]
    DIRECTION INPUT ;
    USE SIGNAL ;
    PORT
      LAYER M4 ;
        RECT  0 69.936 0.084 69.96 ;
    END
  END cfg_data[294]
  PIN cfg_data[295]
    DIRECTION INPUT ;
    USE SIGNAL ;
    PORT
      LAYER M4 ;
        RECT  0 70.032 0.084 70.056 ;
    END
  END cfg_data[295]
  PIN cfg_data[296]
    DIRECTION INPUT ;
    USE SIGNAL ;
    PORT
      LAYER M4 ;
        RECT  0 70.128 0.084 70.152 ;
    END
  END cfg_data[296]
  PIN cfg_data[297]
    DIRECTION INPUT ;
    USE SIGNAL ;
    PORT
      LAYER M4 ;
        RECT  0 70.224 0.084 70.248 ;
    END
  END cfg_data[297]
  PIN cfg_data[298]
    DIRECTION INPUT ;
    USE SIGNAL ;
    PORT
      LAYER M4 ;
        RECT  0 70.32 0.084 70.344 ;
    END
  END cfg_data[298]
  PIN cfg_data[299]
    DIRECTION INPUT ;
    USE SIGNAL ;
    PORT
      LAYER M4 ;
        RECT  0 70.416 0.084 70.44 ;
    END
  END cfg_data[299]
  PIN cfg_data[29]
    DIRECTION INPUT ;
    USE SIGNAL ;
    PORT
      LAYER M4 ;
        RECT  0 11.472 0.084 11.496 ;
    END
  END cfg_data[29]
  PIN cfg_data[2]
    DIRECTION INPUT ;
    USE SIGNAL ;
    PORT
      LAYER M4 ;
        RECT  0 21.936 0.084 21.96 ;
    END
  END cfg_data[2]
  PIN cfg_data[300]
    DIRECTION INPUT ;
    USE SIGNAL ;
    PORT
      LAYER M4 ;
        RECT  0 70.512 0.084 70.536 ;
    END
  END cfg_data[300]
  PIN cfg_data[301]
    DIRECTION INPUT ;
    USE SIGNAL ;
    PORT
      LAYER M4 ;
        RECT  0 70.608 0.084 70.632 ;
    END
  END cfg_data[301]
  PIN cfg_data[302]
    DIRECTION INPUT ;
    USE SIGNAL ;
    PORT
      LAYER M4 ;
        RECT  0 70.704 0.084 70.728 ;
    END
  END cfg_data[302]
  PIN cfg_data[303]
    DIRECTION INPUT ;
    USE SIGNAL ;
    PORT
      LAYER M4 ;
        RECT  0 70.8 0.084 70.824 ;
    END
  END cfg_data[303]
  PIN cfg_data[304]
    DIRECTION INPUT ;
    USE SIGNAL ;
    PORT
      LAYER M4 ;
        RECT  0 70.896 0.084 70.92 ;
    END
  END cfg_data[304]
  PIN cfg_data[305]
    DIRECTION INPUT ;
    USE SIGNAL ;
    PORT
      LAYER M4 ;
        RECT  0 70.992 0.084 71.016 ;
    END
  END cfg_data[305]
  PIN cfg_data[306]
    DIRECTION INPUT ;
    USE SIGNAL ;
    PORT
      LAYER M4 ;
        RECT  0 71.088 0.084 71.112 ;
    END
  END cfg_data[306]
  PIN cfg_data[307]
    DIRECTION INPUT ;
    USE SIGNAL ;
    PORT
      LAYER M4 ;
        RECT  0 78.864 0.084 78.888 ;
    END
  END cfg_data[307]
  PIN cfg_data[308]
    DIRECTION INPUT ;
    USE SIGNAL ;
    PORT
      LAYER M4 ;
        RECT  0 78.96 0.084 78.984 ;
    END
  END cfg_data[308]
  PIN cfg_data[309]
    DIRECTION INPUT ;
    USE SIGNAL ;
    PORT
      LAYER M4 ;
        RECT  0 79.056 0.084 79.08 ;
    END
  END cfg_data[309]
  PIN cfg_data[30]
    DIRECTION INPUT ;
    USE SIGNAL ;
    PORT
      LAYER M4 ;
        RECT  0 11.568 0.084 11.592 ;
    END
  END cfg_data[30]
  PIN cfg_data[310]
    DIRECTION INPUT ;
    USE SIGNAL ;
    PORT
      LAYER M4 ;
        RECT  0 79.152 0.084 79.176 ;
    END
  END cfg_data[310]
  PIN cfg_data[311]
    DIRECTION INPUT ;
    USE SIGNAL ;
    PORT
      LAYER M4 ;
        RECT  0 79.248 0.084 79.272 ;
    END
  END cfg_data[311]
  PIN cfg_data[312]
    DIRECTION INPUT ;
    USE SIGNAL ;
    PORT
      LAYER M4 ;
        RECT  0 79.344 0.084 79.368 ;
    END
  END cfg_data[312]
  PIN cfg_data[313]
    DIRECTION INPUT ;
    USE SIGNAL ;
    PORT
      LAYER M4 ;
        RECT  0 79.44 0.084 79.464 ;
    END
  END cfg_data[313]
  PIN cfg_data[314]
    DIRECTION INPUT ;
    USE SIGNAL ;
    PORT
      LAYER M4 ;
        RECT  0 79.536 0.084 79.56 ;
    END
  END cfg_data[314]
  PIN cfg_data[315]
    DIRECTION INPUT ;
    USE SIGNAL ;
    PORT
      LAYER M4 ;
        RECT  0 79.632 0.084 79.656 ;
    END
  END cfg_data[315]
  PIN cfg_data[316]
    DIRECTION INPUT ;
    USE SIGNAL ;
    PORT
      LAYER M4 ;
        RECT  0 79.728 0.084 79.752 ;
    END
  END cfg_data[316]
  PIN cfg_data[317]
    DIRECTION INPUT ;
    USE SIGNAL ;
    PORT
      LAYER M4 ;
        RECT  0 79.824 0.084 79.848 ;
    END
  END cfg_data[317]
  PIN cfg_data[318]
    DIRECTION INPUT ;
    USE SIGNAL ;
    PORT
      LAYER M4 ;
        RECT  0 79.92 0.084 79.944 ;
    END
  END cfg_data[318]
  PIN cfg_data[319]
    DIRECTION INPUT ;
    USE SIGNAL ;
    PORT
      LAYER M4 ;
        RECT  0 80.016 0.084 80.04 ;
    END
  END cfg_data[319]
  PIN cfg_data[31]
    DIRECTION INPUT ;
    USE SIGNAL ;
    PORT
      LAYER M4 ;
        RECT  0 11.664 0.084 11.688 ;
    END
  END cfg_data[31]
  PIN cfg_data[32]
    DIRECTION INPUT ;
    USE SIGNAL ;
    PORT
      LAYER M4 ;
        RECT  0 11.76 0.084 11.784 ;
    END
  END cfg_data[32]
  PIN cfg_data[33]
    DIRECTION INPUT ;
    USE SIGNAL ;
    PORT
      LAYER M4 ;
        RECT  0 11.856 0.084 11.88 ;
    END
  END cfg_data[33]
  PIN cfg_data[34]
    DIRECTION INPUT ;
    USE SIGNAL ;
    PORT
      LAYER M4 ;
        RECT  0 11.952 0.084 11.976 ;
    END
  END cfg_data[34]
  PIN cfg_data[35]
    DIRECTION INPUT ;
    USE SIGNAL ;
    PORT
      LAYER M4 ;
        RECT  0 12.048 0.084 12.072 ;
    END
  END cfg_data[35]
  PIN cfg_data[36]
    DIRECTION INPUT ;
    USE SIGNAL ;
    PORT
      LAYER M4 ;
        RECT  0 12.144 0.084 12.168 ;
    END
  END cfg_data[36]
  PIN cfg_data[37]
    DIRECTION INPUT ;
    USE SIGNAL ;
    PORT
      LAYER M4 ;
        RECT  0 12.24 0.084 12.264 ;
    END
  END cfg_data[37]
  PIN cfg_data[38]
    DIRECTION INPUT ;
    USE SIGNAL ;
    PORT
      LAYER M4 ;
        RECT  0 12.336 0.084 12.36 ;
    END
  END cfg_data[38]
  PIN cfg_data[39]
    DIRECTION INPUT ;
    USE SIGNAL ;
    PORT
      LAYER M4 ;
        RECT  0 12.432 0.084 12.456 ;
    END
  END cfg_data[39]
  PIN cfg_data[3]
    DIRECTION INPUT ;
    USE SIGNAL ;
    PORT
      LAYER M4 ;
        RECT  0 22.032 0.084 22.056 ;
    END
  END cfg_data[3]
  PIN cfg_data[40]
    DIRECTION INPUT ;
    USE SIGNAL ;
    PORT
      LAYER M4 ;
        RECT  0 12.528 0.084 12.552 ;
    END
  END cfg_data[40]
  PIN cfg_data[41]
    DIRECTION INPUT ;
    USE SIGNAL ;
    PORT
      LAYER M4 ;
        RECT  0 12.624 0.084 12.648 ;
    END
  END cfg_data[41]
  PIN cfg_data[42]
    DIRECTION INPUT ;
    USE SIGNAL ;
    PORT
      LAYER M4 ;
        RECT  0 12.72 0.084 12.744 ;
    END
  END cfg_data[42]
  PIN cfg_data[43]
    DIRECTION INPUT ;
    USE SIGNAL ;
    PORT
      LAYER M4 ;
        RECT  0 12.816 0.084 12.84 ;
    END
  END cfg_data[43]
  PIN cfg_data[44]
    DIRECTION INPUT ;
    USE SIGNAL ;
    PORT
      LAYER M4 ;
        RECT  0 12.912 0.084 12.936 ;
    END
  END cfg_data[44]
  PIN cfg_data[45]
    DIRECTION INPUT ;
    USE SIGNAL ;
    PORT
      LAYER M4 ;
        RECT  0 13.008 0.084 13.032 ;
    END
  END cfg_data[45]
  PIN cfg_data[46]
    DIRECTION INPUT ;
    USE SIGNAL ;
    PORT
      LAYER M4 ;
        RECT  0 13.104 0.084 13.128 ;
    END
  END cfg_data[46]
  PIN cfg_data[47]
    DIRECTION INPUT ;
    USE SIGNAL ;
    PORT
      LAYER M4 ;
        RECT  0 13.2 0.084 13.224 ;
    END
  END cfg_data[47]
  PIN cfg_data[48]
    DIRECTION INPUT ;
    USE SIGNAL ;
    PORT
      LAYER M4 ;
        RECT  0 13.296 0.084 13.32 ;
    END
  END cfg_data[48]
  PIN cfg_data[49]
    DIRECTION INPUT ;
    USE SIGNAL ;
    PORT
      LAYER M4 ;
        RECT  0 13.392 0.084 13.416 ;
    END
  END cfg_data[49]
  PIN cfg_data[4]
    DIRECTION INPUT ;
    USE SIGNAL ;
    PORT
      LAYER M4 ;
        RECT  0 22.128 0.084 22.152 ;
    END
  END cfg_data[4]
  PIN cfg_data[50]
    DIRECTION INPUT ;
    USE SIGNAL ;
    PORT
      LAYER M4 ;
        RECT  0 13.488 0.084 13.512 ;
    END
  END cfg_data[50]
  PIN cfg_data[51]
    DIRECTION INPUT ;
    USE SIGNAL ;
    PORT
      LAYER M4 ;
        RECT  0 45.936 0.084 45.96 ;
    END
  END cfg_data[51]
  PIN cfg_data[52]
    DIRECTION INPUT ;
    USE SIGNAL ;
    PORT
      LAYER M4 ;
        RECT  0 46.032 0.084 46.056 ;
    END
  END cfg_data[52]
  PIN cfg_data[53]
    DIRECTION INPUT ;
    USE SIGNAL ;
    PORT
      LAYER M4 ;
        RECT  0 46.128 0.084 46.152 ;
    END
  END cfg_data[53]
  PIN cfg_data[54]
    DIRECTION INPUT ;
    USE SIGNAL ;
    PORT
      LAYER M4 ;
        RECT  0 46.224 0.084 46.248 ;
    END
  END cfg_data[54]
  PIN cfg_data[55]
    DIRECTION INPUT ;
    USE SIGNAL ;
    PORT
      LAYER M4 ;
        RECT  0 46.32 0.084 46.344 ;
    END
  END cfg_data[55]
  PIN cfg_data[56]
    DIRECTION INPUT ;
    USE SIGNAL ;
    PORT
      LAYER M4 ;
        RECT  0 46.416 0.084 46.44 ;
    END
  END cfg_data[56]
  PIN cfg_data[57]
    DIRECTION INPUT ;
    USE SIGNAL ;
    PORT
      LAYER M4 ;
        RECT  0 46.512 0.084 46.536 ;
    END
  END cfg_data[57]
  PIN cfg_data[58]
    DIRECTION INPUT ;
    USE SIGNAL ;
    PORT
      LAYER M4 ;
        RECT  0 46.608 0.084 46.632 ;
    END
  END cfg_data[58]
  PIN cfg_data[59]
    DIRECTION INPUT ;
    USE SIGNAL ;
    PORT
      LAYER M4 ;
        RECT  0 46.704 0.084 46.728 ;
    END
  END cfg_data[59]
  PIN cfg_data[5]
    DIRECTION INPUT ;
    USE SIGNAL ;
    PORT
      LAYER M4 ;
        RECT  0 22.224 0.084 22.248 ;
    END
  END cfg_data[5]
  PIN cfg_data[60]
    DIRECTION INPUT ;
    USE SIGNAL ;
    PORT
      LAYER M4 ;
        RECT  0 46.8 0.084 46.824 ;
    END
  END cfg_data[60]
  PIN cfg_data[61]
    DIRECTION INPUT ;
    USE SIGNAL ;
    PORT
      LAYER M4 ;
        RECT  0 46.896 0.084 46.92 ;
    END
  END cfg_data[61]
  PIN cfg_data[62]
    DIRECTION INPUT ;
    USE SIGNAL ;
    PORT
      LAYER M4 ;
        RECT  0 46.992 0.084 47.016 ;
    END
  END cfg_data[62]
  PIN cfg_data[63]
    DIRECTION INPUT ;
    USE SIGNAL ;
    PORT
      LAYER M4 ;
        RECT  0 47.088 0.084 47.112 ;
    END
  END cfg_data[63]
  PIN cfg_data[64]
    DIRECTION INPUT ;
    USE SIGNAL ;
    PORT
      LAYER M4 ;
        RECT  0 47.184 0.084 47.208 ;
    END
  END cfg_data[64]
  PIN cfg_data[65]
    DIRECTION INPUT ;
    USE SIGNAL ;
    PORT
      LAYER M4 ;
        RECT  0 47.28 0.084 47.304 ;
    END
  END cfg_data[65]
  PIN cfg_data[66]
    DIRECTION INPUT ;
    USE SIGNAL ;
    PORT
      LAYER M4 ;
        RECT  0 47.376 0.084 47.4 ;
    END
  END cfg_data[66]
  PIN cfg_data[67]
    DIRECTION INPUT ;
    USE SIGNAL ;
    PORT
      LAYER M4 ;
        RECT  0 47.472 0.084 47.496 ;
    END
  END cfg_data[67]
  PIN cfg_data[68]
    DIRECTION INPUT ;
    USE SIGNAL ;
    PORT
      LAYER M4 ;
        RECT  0 47.568 0.084 47.592 ;
    END
  END cfg_data[68]
  PIN cfg_data[69]
    DIRECTION INPUT ;
    USE SIGNAL ;
    PORT
      LAYER M4 ;
        RECT  0 47.664 0.084 47.688 ;
    END
  END cfg_data[69]
  PIN cfg_data[6]
    DIRECTION INPUT ;
    USE SIGNAL ;
    PORT
      LAYER M4 ;
        RECT  0 22.32 0.084 22.344 ;
    END
  END cfg_data[6]
  PIN cfg_data[70]
    DIRECTION INPUT ;
    USE SIGNAL ;
    PORT
      LAYER M4 ;
        RECT  0 47.76 0.084 47.784 ;
    END
  END cfg_data[70]
  PIN cfg_data[71]
    DIRECTION INPUT ;
    USE SIGNAL ;
    PORT
      LAYER M4 ;
        RECT  0 47.856 0.084 47.88 ;
    END
  END cfg_data[71]
  PIN cfg_data[72]
    DIRECTION INPUT ;
    USE SIGNAL ;
    PORT
      LAYER M4 ;
        RECT  0 47.952 0.084 47.976 ;
    END
  END cfg_data[72]
  PIN cfg_data[73]
    DIRECTION INPUT ;
    USE SIGNAL ;
    PORT
      LAYER M4 ;
        RECT  0 48.048 0.084 48.072 ;
    END
  END cfg_data[73]
  PIN cfg_data[74]
    DIRECTION INPUT ;
    USE SIGNAL ;
    PORT
      LAYER M4 ;
        RECT  0 48.144 0.084 48.168 ;
    END
  END cfg_data[74]
  PIN cfg_data[75]
    DIRECTION INPUT ;
    USE SIGNAL ;
    PORT
      LAYER M4 ;
        RECT  0 48.24 0.084 48.264 ;
    END
  END cfg_data[75]
  PIN cfg_data[76]
    DIRECTION INPUT ;
    USE SIGNAL ;
    PORT
      LAYER M4 ;
        RECT  0 48.336 0.084 48.36 ;
    END
  END cfg_data[76]
  PIN cfg_data[77]
    DIRECTION INPUT ;
    USE SIGNAL ;
    PORT
      LAYER M4 ;
        RECT  0 48.432 0.084 48.456 ;
    END
  END cfg_data[77]
  PIN cfg_data[78]
    DIRECTION INPUT ;
    USE SIGNAL ;
    PORT
      LAYER M4 ;
        RECT  0 48.528 0.084 48.552 ;
    END
  END cfg_data[78]
  PIN cfg_data[79]
    DIRECTION INPUT ;
    USE SIGNAL ;
    PORT
      LAYER M4 ;
        RECT  0 48.624 0.084 48.648 ;
    END
  END cfg_data[79]
  PIN cfg_data[7]
    DIRECTION INPUT ;
    USE SIGNAL ;
    PORT
      LAYER M4 ;
        RECT  0 22.416 0.084 22.44 ;
    END
  END cfg_data[7]
  PIN cfg_data[80]
    DIRECTION INPUT ;
    USE SIGNAL ;
    PORT
      LAYER M4 ;
        RECT  0 48.72 0.084 48.744 ;
    END
  END cfg_data[80]
  PIN cfg_data[81]
    DIRECTION INPUT ;
    USE SIGNAL ;
    PORT
      LAYER M4 ;
        RECT  0 48.816 0.084 48.84 ;
    END
  END cfg_data[81]
  PIN cfg_data[82]
    DIRECTION INPUT ;
    USE SIGNAL ;
    PORT
      LAYER M4 ;
        RECT  0 48.912 0.084 48.936 ;
    END
  END cfg_data[82]
  PIN cfg_data[83]
    DIRECTION INPUT ;
    USE SIGNAL ;
    PORT
      LAYER M4 ;
        RECT  0 51.984 0.084 52.008 ;
    END
  END cfg_data[83]
  PIN cfg_data[84]
    DIRECTION INPUT ;
    USE SIGNAL ;
    PORT
      LAYER M4 ;
        RECT  0 52.08 0.084 52.104 ;
    END
  END cfg_data[84]
  PIN cfg_data[85]
    DIRECTION INPUT ;
    USE SIGNAL ;
    PORT
      LAYER M4 ;
        RECT  0 52.176 0.084 52.2 ;
    END
  END cfg_data[85]
  PIN cfg_data[86]
    DIRECTION INPUT ;
    USE SIGNAL ;
    PORT
      LAYER M4 ;
        RECT  0 52.272 0.084 52.296 ;
    END
  END cfg_data[86]
  PIN cfg_data[87]
    DIRECTION INPUT ;
    USE SIGNAL ;
    PORT
      LAYER M4 ;
        RECT  0 52.368 0.084 52.392 ;
    END
  END cfg_data[87]
  PIN cfg_data[88]
    DIRECTION INPUT ;
    USE SIGNAL ;
    PORT
      LAYER M4 ;
        RECT  0 52.464 0.084 52.488 ;
    END
  END cfg_data[88]
  PIN cfg_data[89]
    DIRECTION INPUT ;
    USE SIGNAL ;
    PORT
      LAYER M4 ;
        RECT  0 52.56 0.084 52.584 ;
    END
  END cfg_data[89]
  PIN cfg_data[8]
    DIRECTION INPUT ;
    USE SIGNAL ;
    PORT
      LAYER M4 ;
        RECT  0 22.512 0.084 22.536 ;
    END
  END cfg_data[8]
  PIN cfg_data[90]
    DIRECTION INPUT ;
    USE SIGNAL ;
    PORT
      LAYER M4 ;
        RECT  0 52.656 0.084 52.68 ;
    END
  END cfg_data[90]
  PIN cfg_data[91]
    DIRECTION INPUT ;
    USE SIGNAL ;
    PORT
      LAYER M4 ;
        RECT  0 52.752 0.084 52.776 ;
    END
  END cfg_data[91]
  PIN cfg_data[92]
    DIRECTION INPUT ;
    USE SIGNAL ;
    PORT
      LAYER M4 ;
        RECT  0 52.848 0.084 52.872 ;
    END
  END cfg_data[92]
  PIN cfg_data[93]
    DIRECTION INPUT ;
    USE SIGNAL ;
    PORT
      LAYER M4 ;
        RECT  0 52.944 0.084 52.968 ;
    END
  END cfg_data[93]
  PIN cfg_data[94]
    DIRECTION INPUT ;
    USE SIGNAL ;
    PORT
      LAYER M4 ;
        RECT  0 53.04 0.084 53.064 ;
    END
  END cfg_data[94]
  PIN cfg_data[95]
    DIRECTION INPUT ;
    USE SIGNAL ;
    PORT
      LAYER M4 ;
        RECT  0 53.136 0.084 53.16 ;
    END
  END cfg_data[95]
  PIN cfg_data[96]
    DIRECTION INPUT ;
    USE SIGNAL ;
    PORT
      LAYER M4 ;
        RECT  0 53.232 0.084 53.256 ;
    END
  END cfg_data[96]
  PIN cfg_data[97]
    DIRECTION INPUT ;
    USE SIGNAL ;
    PORT
      LAYER M4 ;
        RECT  0 53.328 0.084 53.352 ;
    END
  END cfg_data[97]
  PIN cfg_data[98]
    DIRECTION INPUT ;
    USE SIGNAL ;
    PORT
      LAYER M4 ;
        RECT  0 53.424 0.084 53.448 ;
    END
  END cfg_data[98]
  PIN cfg_data[99]
    DIRECTION INPUT ;
    USE SIGNAL ;
    PORT
      LAYER M4 ;
        RECT  0 53.52 0.084 53.544 ;
    END
  END cfg_data[99]
  PIN cfg_data[9]
    DIRECTION INPUT ;
    USE SIGNAL ;
    PORT
      LAYER M4 ;
        RECT  0 22.608 0.084 22.632 ;
    END
  END cfg_data[9]
  PIN cfg_last[0]
    DIRECTION INPUT ;
    USE SIGNAL ;
    PORT
      LAYER M4 ;
        RECT  0 80.112 0.084 80.136 ;
    END
  END cfg_last[0]
  PIN cfg_last[1]
    DIRECTION INPUT ;
    USE SIGNAL ;
    PORT
      LAYER M4 ;
        RECT  0 80.208 0.084 80.232 ;
    END
  END cfg_last[1]
  PIN cfg_last[2]
    DIRECTION INPUT ;
    USE SIGNAL ;
    PORT
      LAYER M4 ;
        RECT  0 80.304 0.084 80.328 ;
    END
  END cfg_last[2]
  PIN cfg_last[3]
    DIRECTION INPUT ;
    USE SIGNAL ;
    PORT
      LAYER M4 ;
        RECT  0 80.4 0.084 80.424 ;
    END
  END cfg_last[3]
  PIN cfg_last[4]
    DIRECTION INPUT ;
    USE SIGNAL ;
    PORT
      LAYER M4 ;
        RECT  0 80.496 0.084 80.52 ;
    END
  END cfg_last[4]
  PIN cfg_we[0]
    DIRECTION INPUT ;
    USE SIGNAL ;
    PORT
      LAYER M4 ;
        RECT  0 80.592 0.084 80.616 ;
    END
  END cfg_we[0]
  PIN cfg_we[1]
    DIRECTION INPUT ;
    USE SIGNAL ;
    PORT
      LAYER M4 ;
        RECT  0 80.688 0.084 80.712 ;
    END
  END cfg_we[1]
  PIN cfg_we[2]
    DIRECTION INPUT ;
    USE SIGNAL ;
    PORT
      LAYER M4 ;
        RECT  0 80.784 0.084 80.808 ;
    END
  END cfg_we[2]
  PIN cfg_we[3]
    DIRECTION INPUT ;
    USE SIGNAL ;
    PORT
      LAYER M4 ;
        RECT  0 80.88 0.084 80.904 ;
    END
  END cfg_we[3]
  PIN cfg_we[4]
    DIRECTION INPUT ;
    USE SIGNAL ;
    PORT
      LAYER M4 ;
        RECT  0 80.976 0.084 81 ;
    END
  END cfg_we[4]
  PIN ck
    DIRECTION INPUT ;
    USE SIGNAL ;
    PORT
      LAYER M4 ;
        RECT  0 49.008 0.084 49.032 ;
    END
  END ck
  PIN ctrl_calendar_fault_hbm[0]
    DIRECTION INPUT ;
    USE SIGNAL ;
    PORT
      LAYER M5 ;
        RECT  6.864 0 6.888 0.084 ;
    END
  END ctrl_calendar_fault_hbm[0]
  PIN ctrl_calendar_fault_hbm[1]
    DIRECTION INPUT ;
    USE SIGNAL ;
    PORT
      LAYER M5 ;
        RECT  6.96 0 6.984 0.084 ;
    END
  END ctrl_calendar_fault_hbm[1]
  PIN ctrl_calendar_fault_hbm[2]
    DIRECTION INPUT ;
    USE SIGNAL ;
    PORT
      LAYER M5 ;
        RECT  7.056 0 7.08 0.084 ;
    END
  END ctrl_calendar_fault_hbm[2]
  PIN ctrl_calendar_fault_hbm[3]
    DIRECTION INPUT ;
    USE SIGNAL ;
    PORT
      LAYER M5 ;
        RECT  7.152 0 7.176 0.084 ;
    END
  END ctrl_calendar_fault_hbm[3]
  PIN ctrl_completion_fault_core[0]
    DIRECTION INPUT ;
    USE SIGNAL ;
    PORT
      LAYER M5 ;
        RECT  7.248 0 7.272 0.084 ;
    END
  END ctrl_completion_fault_core[0]
  PIN ctrl_completion_fault_core[1]
    DIRECTION INPUT ;
    USE SIGNAL ;
    PORT
      LAYER M5 ;
        RECT  7.344 0 7.368 0.084 ;
    END
  END ctrl_completion_fault_core[1]
  PIN ctrl_completion_fault_core[2]
    DIRECTION INPUT ;
    USE SIGNAL ;
    PORT
      LAYER M5 ;
        RECT  7.44 0 7.464 0.084 ;
    END
  END ctrl_completion_fault_core[2]
  PIN ctrl_completion_fault_core[3]
    DIRECTION INPUT ;
    USE SIGNAL ;
    PORT
      LAYER M5 ;
        RECT  7.536 0 7.56 0.084 ;
    END
  END ctrl_completion_fault_core[3]
  PIN ctrl_fault_core[0]
    DIRECTION INPUT ;
    USE SIGNAL ;
    PORT
      LAYER M5 ;
        RECT  7.632 0 7.656 0.084 ;
    END
  END ctrl_fault_core[0]
  PIN ctrl_fault_core[1]
    DIRECTION INPUT ;
    USE SIGNAL ;
    PORT
      LAYER M5 ;
        RECT  7.728 0 7.752 0.084 ;
    END
  END ctrl_fault_core[1]
  PIN ctrl_fault_core[2]
    DIRECTION INPUT ;
    USE SIGNAL ;
    PORT
      LAYER M5 ;
        RECT  7.824 0 7.848 0.084 ;
    END
  END ctrl_fault_core[2]
  PIN ctrl_fault_core[3]
    DIRECTION INPUT ;
    USE SIGNAL ;
    PORT
      LAYER M5 ;
        RECT  7.92 0 7.944 0.084 ;
    END
  END ctrl_fault_core[3]
  PIN ctrl_fault_hbm[0]
    DIRECTION INPUT ;
    USE SIGNAL ;
    PORT
      LAYER M5 ;
        RECT  8.016 0 8.04 0.084 ;
    END
  END ctrl_fault_hbm[0]
  PIN ctrl_fault_hbm[1]
    DIRECTION INPUT ;
    USE SIGNAL ;
    PORT
      LAYER M5 ;
        RECT  8.112 0 8.136 0.084 ;
    END
  END ctrl_fault_hbm[1]
  PIN ctrl_fault_hbm[2]
    DIRECTION INPUT ;
    USE SIGNAL ;
    PORT
      LAYER M5 ;
        RECT  8.208 0 8.232 0.084 ;
    END
  END ctrl_fault_hbm[2]
  PIN ctrl_fault_hbm[3]
    DIRECTION INPUT ;
    USE SIGNAL ;
    PORT
      LAYER M5 ;
        RECT  8.304 0 8.328 0.084 ;
    END
  END ctrl_fault_hbm[3]
  PIN ctrl_go
    DIRECTION INPUT ;
    USE SIGNAL ;
    PORT
      LAYER M5 ;
        RECT  7.44 97.116 7.464 97.2 ;
    END
  END ctrl_go
  PIN ctrl_go_h
    DIRECTION OUTPUT ;
    USE SIGNAL ;
    PORT
      LAYER M5 ;
        RECT  7.536 97.116 7.56 97.2 ;
    END
  END ctrl_go_h
  PIN ctrl_idle_core[0]
    DIRECTION INPUT ;
    USE SIGNAL ;
    PORT
      LAYER M5 ;
        RECT  8.4 0 8.424 0.084 ;
    END
  END ctrl_idle_core[0]
  PIN ctrl_idle_core[1]
    DIRECTION INPUT ;
    USE SIGNAL ;
    PORT
      LAYER M5 ;
        RECT  8.496 0 8.52 0.084 ;
    END
  END ctrl_idle_core[1]
  PIN ctrl_idle_core[2]
    DIRECTION INPUT ;
    USE SIGNAL ;
    PORT
      LAYER M5 ;
        RECT  8.592 0 8.616 0.084 ;
    END
  END ctrl_idle_core[2]
  PIN ctrl_idle_core[3]
    DIRECTION INPUT ;
    USE SIGNAL ;
    PORT
      LAYER M5 ;
        RECT  8.688 0 8.712 0.084 ;
    END
  END ctrl_idle_core[3]
  PIN ctrl_idle_hbm[0]
    DIRECTION INPUT ;
    USE SIGNAL ;
    PORT
      LAYER M5 ;
        RECT  8.784 0 8.808 0.084 ;
    END
  END ctrl_idle_hbm[0]
  PIN ctrl_idle_hbm[1]
    DIRECTION INPUT ;
    USE SIGNAL ;
    PORT
      LAYER M5 ;
        RECT  8.88 0 8.904 0.084 ;
    END
  END ctrl_idle_hbm[1]
  PIN ctrl_idle_hbm[2]
    DIRECTION INPUT ;
    USE SIGNAL ;
    PORT
      LAYER M5 ;
        RECT  8.976 0 9 0.084 ;
    END
  END ctrl_idle_hbm[2]
  PIN ctrl_idle_hbm[3]
    DIRECTION INPUT ;
    USE SIGNAL ;
    PORT
      LAYER M5 ;
        RECT  9.072 0 9.096 0.084 ;
    END
  END ctrl_idle_hbm[3]
  PIN ctrl_intake_fault_core[0]
    DIRECTION INPUT ;
    USE SIGNAL ;
    PORT
      LAYER M5 ;
        RECT  9.168 0 9.192 0.084 ;
    END
  END ctrl_intake_fault_core[0]
  PIN ctrl_intake_fault_core[1]
    DIRECTION INPUT ;
    USE SIGNAL ;
    PORT
      LAYER M5 ;
        RECT  9.264 0 9.288 0.084 ;
    END
  END ctrl_intake_fault_core[1]
  PIN ctrl_intake_fault_core[2]
    DIRECTION INPUT ;
    USE SIGNAL ;
    PORT
      LAYER M5 ;
        RECT  9.36 0 9.384 0.084 ;
    END
  END ctrl_intake_fault_core[2]
  PIN ctrl_intake_fault_core[3]
    DIRECTION INPUT ;
    USE SIGNAL ;
    PORT
      LAYER M5 ;
        RECT  9.456 0 9.48 0.084 ;
    END
  END ctrl_intake_fault_core[3]
  PIN ctrl_output_fault_hbm[0]
    DIRECTION INPUT ;
    USE SIGNAL ;
    PORT
      LAYER M5 ;
        RECT  9.552 0 9.576 0.084 ;
    END
  END ctrl_output_fault_hbm[0]
  PIN ctrl_output_fault_hbm[1]
    DIRECTION INPUT ;
    USE SIGNAL ;
    PORT
      LAYER M5 ;
        RECT  9.648 0 9.672 0.084 ;
    END
  END ctrl_output_fault_hbm[1]
  PIN ctrl_output_fault_hbm[2]
    DIRECTION INPUT ;
    USE SIGNAL ;
    PORT
      LAYER M5 ;
        RECT  9.744 0 9.768 0.084 ;
    END
  END ctrl_output_fault_hbm[2]
  PIN ctrl_output_fault_hbm[3]
    DIRECTION INPUT ;
    USE SIGNAL ;
    PORT
      LAYER M5 ;
        RECT  9.84 0 9.864 0.084 ;
    END
  END ctrl_output_fault_hbm[3]
  PIN ctx_t[0]
    DIRECTION INPUT ;
    USE SIGNAL ;
    PORT
      LAYER M5 ;
        RECT  7.632 97.116 7.656 97.2 ;
    END
  END ctx_t[0]
  PIN ctx_t[10]
    DIRECTION INPUT ;
    USE SIGNAL ;
    PORT
      LAYER M5 ;
        RECT  8.592 97.116 8.616 97.2 ;
    END
  END ctx_t[10]
  PIN ctx_t[11]
    DIRECTION INPUT ;
    USE SIGNAL ;
    PORT
      LAYER M5 ;
        RECT  8.688 97.116 8.712 97.2 ;
    END
  END ctx_t[11]
  PIN ctx_t[12]
    DIRECTION INPUT ;
    USE SIGNAL ;
    PORT
      LAYER M5 ;
        RECT  8.784 97.116 8.808 97.2 ;
    END
  END ctx_t[12]
  PIN ctx_t[13]
    DIRECTION INPUT ;
    USE SIGNAL ;
    PORT
      LAYER M5 ;
        RECT  8.88 97.116 8.904 97.2 ;
    END
  END ctx_t[13]
  PIN ctx_t[1]
    DIRECTION INPUT ;
    USE SIGNAL ;
    PORT
      LAYER M5 ;
        RECT  7.728 97.116 7.752 97.2 ;
    END
  END ctx_t[1]
  PIN ctx_t[2]
    DIRECTION INPUT ;
    USE SIGNAL ;
    PORT
      LAYER M5 ;
        RECT  7.824 97.116 7.848 97.2 ;
    END
  END ctx_t[2]
  PIN ctx_t[3]
    DIRECTION INPUT ;
    USE SIGNAL ;
    PORT
      LAYER M5 ;
        RECT  7.92 97.116 7.944 97.2 ;
    END
  END ctx_t[3]
  PIN ctx_t[4]
    DIRECTION INPUT ;
    USE SIGNAL ;
    PORT
      LAYER M5 ;
        RECT  8.016 97.116 8.04 97.2 ;
    END
  END ctx_t[4]
  PIN ctx_t[5]
    DIRECTION INPUT ;
    USE SIGNAL ;
    PORT
      LAYER M5 ;
        RECT  8.112 97.116 8.136 97.2 ;
    END
  END ctx_t[5]
  PIN ctx_t[6]
    DIRECTION INPUT ;
    USE SIGNAL ;
    PORT
      LAYER M5 ;
        RECT  8.208 97.116 8.232 97.2 ;
    END
  END ctx_t[6]
  PIN ctx_t[7]
    DIRECTION INPUT ;
    USE SIGNAL ;
    PORT
      LAYER M5 ;
        RECT  8.304 97.116 8.328 97.2 ;
    END
  END ctx_t[7]
  PIN ctx_t[8]
    DIRECTION INPUT ;
    USE SIGNAL ;
    PORT
      LAYER M5 ;
        RECT  8.4 97.116 8.424 97.2 ;
    END
  END ctx_t[8]
  PIN ctx_t[9]
    DIRECTION INPUT ;
    USE SIGNAL ;
    PORT
      LAYER M5 ;
        RECT  8.496 97.116 8.52 97.2 ;
    END
  END ctx_t[9]
  PIN ctx_t_h[0]
    DIRECTION OUTPUT ;
    USE SIGNAL ;
    PORT
      LAYER M5 ;
        RECT  8.976 97.116 9 97.2 ;
    END
  END ctx_t_h[0]
  PIN ctx_t_h[10]
    DIRECTION OUTPUT ;
    USE SIGNAL ;
    PORT
      LAYER M5 ;
        RECT  9.936 97.116 9.96 97.2 ;
    END
  END ctx_t_h[10]
  PIN ctx_t_h[11]
    DIRECTION OUTPUT ;
    USE SIGNAL ;
    PORT
      LAYER M5 ;
        RECT  10.032 97.116 10.056 97.2 ;
    END
  END ctx_t_h[11]
  PIN ctx_t_h[12]
    DIRECTION OUTPUT ;
    USE SIGNAL ;
    PORT
      LAYER M5 ;
        RECT  10.128 97.116 10.152 97.2 ;
    END
  END ctx_t_h[12]
  PIN ctx_t_h[13]
    DIRECTION OUTPUT ;
    USE SIGNAL ;
    PORT
      LAYER M5 ;
        RECT  10.224 97.116 10.248 97.2 ;
    END
  END ctx_t_h[13]
  PIN ctx_t_h[1]
    DIRECTION OUTPUT ;
    USE SIGNAL ;
    PORT
      LAYER M5 ;
        RECT  9.072 97.116 9.096 97.2 ;
    END
  END ctx_t_h[1]
  PIN ctx_t_h[2]
    DIRECTION OUTPUT ;
    USE SIGNAL ;
    PORT
      LAYER M5 ;
        RECT  9.168 97.116 9.192 97.2 ;
    END
  END ctx_t_h[2]
  PIN ctx_t_h[3]
    DIRECTION OUTPUT ;
    USE SIGNAL ;
    PORT
      LAYER M5 ;
        RECT  9.264 97.116 9.288 97.2 ;
    END
  END ctx_t_h[3]
  PIN ctx_t_h[4]
    DIRECTION OUTPUT ;
    USE SIGNAL ;
    PORT
      LAYER M5 ;
        RECT  9.36 97.116 9.384 97.2 ;
    END
  END ctx_t_h[4]
  PIN ctx_t_h[5]
    DIRECTION OUTPUT ;
    USE SIGNAL ;
    PORT
      LAYER M5 ;
        RECT  9.456 97.116 9.48 97.2 ;
    END
  END ctx_t_h[5]
  PIN ctx_t_h[6]
    DIRECTION OUTPUT ;
    USE SIGNAL ;
    PORT
      LAYER M5 ;
        RECT  9.552 97.116 9.576 97.2 ;
    END
  END ctx_t_h[6]
  PIN ctx_t_h[7]
    DIRECTION OUTPUT ;
    USE SIGNAL ;
    PORT
      LAYER M5 ;
        RECT  9.648 97.116 9.672 97.2 ;
    END
  END ctx_t_h[7]
  PIN ctx_t_h[8]
    DIRECTION OUTPUT ;
    USE SIGNAL ;
    PORT
      LAYER M5 ;
        RECT  9.744 97.116 9.768 97.2 ;
    END
  END ctx_t_h[8]
  PIN ctx_t_h[9]
    DIRECTION OUTPUT ;
    USE SIGNAL ;
    PORT
      LAYER M5 ;
        RECT  9.84 97.116 9.864 97.2 ;
    END
  END ctx_t_h[9]
  PIN drain_fault
    DIRECTION OUTPUT ;
    USE SIGNAL ;
    PORT
      LAYER M5 ;
        RECT  3.792 0 3.816 0.084 ;
    END
  END drain_fault
  PIN drained
    DIRECTION OUTPUT ;
    USE SIGNAL ;
    PORT
      LAYER M5 ;
        RECT  3.888 0 3.912 0.084 ;
    END
  END drained
  PIN epoch[0]
    DIRECTION INPUT ;
    USE SIGNAL ;
    PORT
      LAYER M5 ;
        RECT  10.32 97.116 10.344 97.2 ;
    END
  END epoch[0]
  PIN epoch[10]
    DIRECTION INPUT ;
    USE SIGNAL ;
    PORT
      LAYER M5 ;
        RECT  11.28 97.116 11.304 97.2 ;
    END
  END epoch[10]
  PIN epoch[11]
    DIRECTION INPUT ;
    USE SIGNAL ;
    PORT
      LAYER M5 ;
        RECT  11.376 97.116 11.4 97.2 ;
    END
  END epoch[11]
  PIN epoch[12]
    DIRECTION INPUT ;
    USE SIGNAL ;
    PORT
      LAYER M5 ;
        RECT  11.472 97.116 11.496 97.2 ;
    END
  END epoch[12]
  PIN epoch[13]
    DIRECTION INPUT ;
    USE SIGNAL ;
    PORT
      LAYER M5 ;
        RECT  11.568 97.116 11.592 97.2 ;
    END
  END epoch[13]
  PIN epoch[14]
    DIRECTION INPUT ;
    USE SIGNAL ;
    PORT
      LAYER M5 ;
        RECT  11.664 97.116 11.688 97.2 ;
    END
  END epoch[14]
  PIN epoch[15]
    DIRECTION INPUT ;
    USE SIGNAL ;
    PORT
      LAYER M5 ;
        RECT  11.76 97.116 11.784 97.2 ;
    END
  END epoch[15]
  PIN epoch[1]
    DIRECTION INPUT ;
    USE SIGNAL ;
    PORT
      LAYER M5 ;
        RECT  10.416 97.116 10.44 97.2 ;
    END
  END epoch[1]
  PIN epoch[2]
    DIRECTION INPUT ;
    USE SIGNAL ;
    PORT
      LAYER M5 ;
        RECT  10.512 97.116 10.536 97.2 ;
    END
  END epoch[2]
  PIN epoch[3]
    DIRECTION INPUT ;
    USE SIGNAL ;
    PORT
      LAYER M5 ;
        RECT  10.608 97.116 10.632 97.2 ;
    END
  END epoch[3]
  PIN epoch[4]
    DIRECTION INPUT ;
    USE SIGNAL ;
    PORT
      LAYER M5 ;
        RECT  10.704 97.116 10.728 97.2 ;
    END
  END epoch[4]
  PIN epoch[5]
    DIRECTION INPUT ;
    USE SIGNAL ;
    PORT
      LAYER M5 ;
        RECT  10.8 97.116 10.824 97.2 ;
    END
  END epoch[5]
  PIN epoch[6]
    DIRECTION INPUT ;
    USE SIGNAL ;
    PORT
      LAYER M5 ;
        RECT  10.896 97.116 10.92 97.2 ;
    END
  END epoch[6]
  PIN epoch[7]
    DIRECTION INPUT ;
    USE SIGNAL ;
    PORT
      LAYER M5 ;
        RECT  10.992 97.116 11.016 97.2 ;
    END
  END epoch[7]
  PIN epoch[8]
    DIRECTION INPUT ;
    USE SIGNAL ;
    PORT
      LAYER M5 ;
        RECT  11.088 97.116 11.112 97.2 ;
    END
  END epoch[8]
  PIN epoch[9]
    DIRECTION INPUT ;
    USE SIGNAL ;
    PORT
      LAYER M5 ;
        RECT  11.184 97.116 11.208 97.2 ;
    END
  END epoch[9]
  PIN epoch_h[0]
    DIRECTION OUTPUT ;
    USE SIGNAL ;
    PORT
      LAYER M5 ;
        RECT  11.856 97.116 11.88 97.2 ;
    END
  END epoch_h[0]
  PIN epoch_h[10]
    DIRECTION OUTPUT ;
    USE SIGNAL ;
    PORT
      LAYER M5 ;
        RECT  12.816 97.116 12.84 97.2 ;
    END
  END epoch_h[10]
  PIN epoch_h[11]
    DIRECTION OUTPUT ;
    USE SIGNAL ;
    PORT
      LAYER M5 ;
        RECT  12.912 97.116 12.936 97.2 ;
    END
  END epoch_h[11]
  PIN epoch_h[12]
    DIRECTION OUTPUT ;
    USE SIGNAL ;
    PORT
      LAYER M5 ;
        RECT  13.008 97.116 13.032 97.2 ;
    END
  END epoch_h[12]
  PIN epoch_h[13]
    DIRECTION OUTPUT ;
    USE SIGNAL ;
    PORT
      LAYER M5 ;
        RECT  13.104 97.116 13.128 97.2 ;
    END
  END epoch_h[13]
  PIN epoch_h[14]
    DIRECTION OUTPUT ;
    USE SIGNAL ;
    PORT
      LAYER M5 ;
        RECT  13.2 97.116 13.224 97.2 ;
    END
  END epoch_h[14]
  PIN epoch_h[15]
    DIRECTION OUTPUT ;
    USE SIGNAL ;
    PORT
      LAYER M5 ;
        RECT  13.296 97.116 13.32 97.2 ;
    END
  END epoch_h[15]
  PIN epoch_h[1]
    DIRECTION OUTPUT ;
    USE SIGNAL ;
    PORT
      LAYER M5 ;
        RECT  11.952 97.116 11.976 97.2 ;
    END
  END epoch_h[1]
  PIN epoch_h[2]
    DIRECTION OUTPUT ;
    USE SIGNAL ;
    PORT
      LAYER M5 ;
        RECT  12.048 97.116 12.072 97.2 ;
    END
  END epoch_h[2]
  PIN epoch_h[3]
    DIRECTION OUTPUT ;
    USE SIGNAL ;
    PORT
      LAYER M5 ;
        RECT  12.144 97.116 12.168 97.2 ;
    END
  END epoch_h[3]
  PIN epoch_h[4]
    DIRECTION OUTPUT ;
    USE SIGNAL ;
    PORT
      LAYER M5 ;
        RECT  12.24 97.116 12.264 97.2 ;
    END
  END epoch_h[4]
  PIN epoch_h[5]
    DIRECTION OUTPUT ;
    USE SIGNAL ;
    PORT
      LAYER M5 ;
        RECT  12.336 97.116 12.36 97.2 ;
    END
  END epoch_h[5]
  PIN epoch_h[6]
    DIRECTION OUTPUT ;
    USE SIGNAL ;
    PORT
      LAYER M5 ;
        RECT  12.432 97.116 12.456 97.2 ;
    END
  END epoch_h[6]
  PIN epoch_h[7]
    DIRECTION OUTPUT ;
    USE SIGNAL ;
    PORT
      LAYER M5 ;
        RECT  12.528 97.116 12.552 97.2 ;
    END
  END epoch_h[7]
  PIN epoch_h[8]
    DIRECTION OUTPUT ;
    USE SIGNAL ;
    PORT
      LAYER M5 ;
        RECT  12.624 97.116 12.648 97.2 ;
    END
  END epoch_h[8]
  PIN epoch_h[9]
    DIRECTION OUTPUT ;
    USE SIGNAL ;
    PORT
      LAYER M5 ;
        RECT  12.72 97.116 12.744 97.2 ;
    END
  END epoch_h[9]
  PIN front_fault_go_hbm[0]
    DIRECTION INPUT ;
    USE SIGNAL ;
    PORT
      LAYER M5 ;
        RECT  3.984 0 4.008 0.084 ;
    END
  END front_fault_go_hbm[0]
  PIN front_fault_go_hbm[1]
    DIRECTION INPUT ;
    USE SIGNAL ;
    PORT
      LAYER M5 ;
        RECT  4.08 0 4.104 0.084 ;
    END
  END front_fault_go_hbm[1]
  PIN front_fault_go_hbm[2]
    DIRECTION INPUT ;
    USE SIGNAL ;
    PORT
      LAYER M5 ;
        RECT  4.176 0 4.2 0.084 ;
    END
  END front_fault_go_hbm[2]
  PIN front_fault_go_hbm[3]
    DIRECTION INPUT ;
    USE SIGNAL ;
    PORT
      LAYER M5 ;
        RECT  4.272 0 4.296 0.084 ;
    END
  END front_fault_go_hbm[3]
  PIN front_fault_overflow_hbm[0]
    DIRECTION INPUT ;
    USE SIGNAL ;
    PORT
      LAYER M5 ;
        RECT  4.368 0 4.392 0.084 ;
    END
  END front_fault_overflow_hbm[0]
  PIN front_fault_overflow_hbm[1]
    DIRECTION INPUT ;
    USE SIGNAL ;
    PORT
      LAYER M5 ;
        RECT  4.464 0 4.488 0.084 ;
    END
  END front_fault_overflow_hbm[1]
  PIN front_fault_overflow_hbm[2]
    DIRECTION INPUT ;
    USE SIGNAL ;
    PORT
      LAYER M5 ;
        RECT  4.56 0 4.584 0.084 ;
    END
  END front_fault_overflow_hbm[2]
  PIN front_fault_overflow_hbm[3]
    DIRECTION INPUT ;
    USE SIGNAL ;
    PORT
      LAYER M5 ;
        RECT  4.656 0 4.68 0.084 ;
    END
  END front_fault_overflow_hbm[3]
  PIN front_hold_hbm[0]
    DIRECTION INPUT ;
    USE SIGNAL ;
    PORT
      LAYER M5 ;
        RECT  4.752 0 4.776 0.084 ;
    END
  END front_hold_hbm[0]
  PIN front_hold_hbm[1]
    DIRECTION INPUT ;
    USE SIGNAL ;
    PORT
      LAYER M5 ;
        RECT  4.848 0 4.872 0.084 ;
    END
  END front_hold_hbm[1]
  PIN front_hold_hbm[2]
    DIRECTION INPUT ;
    USE SIGNAL ;
    PORT
      LAYER M5 ;
        RECT  4.944 0 4.968 0.084 ;
    END
  END front_hold_hbm[2]
  PIN front_hold_hbm[3]
    DIRECTION INPUT ;
    USE SIGNAL ;
    PORT
      LAYER M5 ;
        RECT  5.04 0 5.064 0.084 ;
    END
  END front_hold_hbm[3]
  PIN front_idle_hbm[0]
    DIRECTION INPUT ;
    USE SIGNAL ;
    PORT
      LAYER M5 ;
        RECT  5.136 0 5.16 0.084 ;
    END
  END front_idle_hbm[0]
  PIN front_idle_hbm[1]
    DIRECTION INPUT ;
    USE SIGNAL ;
    PORT
      LAYER M5 ;
        RECT  5.232 0 5.256 0.084 ;
    END
  END front_idle_hbm[1]
  PIN front_idle_hbm[2]
    DIRECTION INPUT ;
    USE SIGNAL ;
    PORT
      LAYER M5 ;
        RECT  5.328 0 5.352 0.084 ;
    END
  END front_idle_hbm[2]
  PIN front_idle_hbm[3]
    DIRECTION INPUT ;
    USE SIGNAL ;
    PORT
      LAYER M5 ;
        RECT  5.424 0 5.448 0.084 ;
    END
  END front_idle_hbm[3]
  PIN hck
    DIRECTION INPUT ;
    USE SIGNAL ;
    PORT
      LAYER M4 ;
        RECT  97.116 48.144 97.2 48.168 ;
    END
  END hck
  PIN hrst_n
    DIRECTION INPUT ;
    USE SIGNAL ;
    PORT
      LAYER M4 ;
        RECT  97.116 49.68 97.2 49.704 ;
    END
  END hrst_n
  PIN kgo
    DIRECTION INPUT ;
    USE SIGNAL ;
    PORT
      LAYER M5 ;
        RECT  13.392 97.116 13.416 97.2 ;
    END
  END kgo
  PIN kgo_h
    DIRECTION OUTPUT ;
    USE SIGNAL ;
    PORT
      LAYER M5 ;
        RECT  13.488 97.116 13.512 97.2 ;
    END
  END kgo_h
  PIN layer[0]
    DIRECTION INPUT ;
    USE SIGNAL ;
    PORT
      LAYER M5 ;
        RECT  5.712 97.116 5.736 97.2 ;
    END
  END layer[0]
  PIN layer[1]
    DIRECTION INPUT ;
    USE SIGNAL ;
    PORT
      LAYER M5 ;
        RECT  5.808 97.116 5.832 97.2 ;
    END
  END layer[1]
  PIN layer[2]
    DIRECTION INPUT ;
    USE SIGNAL ;
    PORT
      LAYER M5 ;
        RECT  5.904 97.116 5.928 97.2 ;
    END
  END layer[2]
  PIN layer[3]
    DIRECTION INPUT ;
    USE SIGNAL ;
    PORT
      LAYER M5 ;
        RECT  6 97.116 6.024 97.2 ;
    END
  END layer[3]
  PIN layer[4]
    DIRECTION INPUT ;
    USE SIGNAL ;
    PORT
      LAYER M5 ;
        RECT  6.096 97.116 6.12 97.2 ;
    END
  END layer[4]
  PIN layer[5]
    DIRECTION INPUT ;
    USE SIGNAL ;
    PORT
      LAYER M5 ;
        RECT  6.192 97.116 6.216 97.2 ;
    END
  END layer[5]
  PIN layer_h[0]
    DIRECTION OUTPUT ;
    USE SIGNAL ;
    PORT
      LAYER M5 ;
        RECT  6.288 97.116 6.312 97.2 ;
    END
  END layer_h[0]
  PIN layer_h[1]
    DIRECTION OUTPUT ;
    USE SIGNAL ;
    PORT
      LAYER M5 ;
        RECT  6.384 97.116 6.408 97.2 ;
    END
  END layer_h[1]
  PIN layer_h[2]
    DIRECTION OUTPUT ;
    USE SIGNAL ;
    PORT
      LAYER M5 ;
        RECT  6.48 97.116 6.504 97.2 ;
    END
  END layer_h[2]
  PIN layer_h[3]
    DIRECTION OUTPUT ;
    USE SIGNAL ;
    PORT
      LAYER M5 ;
        RECT  6.576 97.116 6.6 97.2 ;
    END
  END layer_h[3]
  PIN layer_h[4]
    DIRECTION OUTPUT ;
    USE SIGNAL ;
    PORT
      LAYER M5 ;
        RECT  6.672 97.116 6.696 97.2 ;
    END
  END layer_h[4]
  PIN layer_h[5]
    DIRECTION OUTPUT ;
    USE SIGNAL ;
    PORT
      LAYER M5 ;
        RECT  6.768 97.116 6.792 97.2 ;
    END
  END layer_h[5]
  PIN ph_fault_core
    DIRECTION OUTPUT ;
    USE SIGNAL ;
    PORT
      LAYER M5 ;
        RECT  6.864 97.116 6.888 97.2 ;
    END
  END ph_fault_core
  PIN ph_fault_hbm
    DIRECTION OUTPUT ;
    USE SIGNAL ;
    PORT
      LAYER M5 ;
        RECT  6.96 97.116 6.984 97.2 ;
    END
  END ph_fault_hbm
  PIN ph_idle_core
    DIRECTION OUTPUT ;
    USE SIGNAL ;
    PORT
      LAYER M5 ;
        RECT  7.056 97.116 7.08 97.2 ;
    END
  END ph_idle_core
  PIN ph_idle_hbm
    DIRECTION OUTPUT ;
    USE SIGNAL ;
    PORT
      LAYER M5 ;
        RECT  7.152 97.116 7.176 97.2 ;
    END
  END ph_idle_hbm
  PIN ring_fault_core[0]
    DIRECTION INPUT ;
    USE SIGNAL ;
    PORT
      LAYER M5 ;
        RECT  5.52 0 5.544 0.084 ;
    END
  END ring_fault_core[0]
  PIN ring_fault_core[1]
    DIRECTION INPUT ;
    USE SIGNAL ;
    PORT
      LAYER M5 ;
        RECT  5.616 0 5.64 0.084 ;
    END
  END ring_fault_core[1]
  PIN ring_fault_core[2]
    DIRECTION INPUT ;
    USE SIGNAL ;
    PORT
      LAYER M5 ;
        RECT  5.712 0 5.736 0.084 ;
    END
  END ring_fault_core[2]
  PIN ring_fault_core[3]
    DIRECTION INPUT ;
    USE SIGNAL ;
    PORT
      LAYER M5 ;
        RECT  5.808 0 5.832 0.084 ;
    END
  END ring_fault_core[3]
  PIN ring_fault_hbm[0]
    DIRECTION INPUT ;
    USE SIGNAL ;
    PORT
      LAYER M5 ;
        RECT  5.904 0 5.928 0.084 ;
    END
  END ring_fault_hbm[0]
  PIN ring_fault_hbm[1]
    DIRECTION INPUT ;
    USE SIGNAL ;
    PORT
      LAYER M5 ;
        RECT  6 0 6.024 0.084 ;
    END
  END ring_fault_hbm[1]
  PIN ring_fault_hbm[2]
    DIRECTION INPUT ;
    USE SIGNAL ;
    PORT
      LAYER M5 ;
        RECT  6.096 0 6.12 0.084 ;
    END
  END ring_fault_hbm[2]
  PIN ring_fault_hbm[3]
    DIRECTION INPUT ;
    USE SIGNAL ;
    PORT
      LAYER M5 ;
        RECT  6.192 0 6.216 0.084 ;
    END
  END ring_fault_hbm[3]
  PIN ring_idle_core[0]
    DIRECTION INPUT ;
    USE SIGNAL ;
    PORT
      LAYER M5 ;
        RECT  6.288 0 6.312 0.084 ;
    END
  END ring_idle_core[0]
  PIN ring_idle_core[1]
    DIRECTION INPUT ;
    USE SIGNAL ;
    PORT
      LAYER M5 ;
        RECT  6.384 0 6.408 0.084 ;
    END
  END ring_idle_core[1]
  PIN ring_idle_core[2]
    DIRECTION INPUT ;
    USE SIGNAL ;
    PORT
      LAYER M5 ;
        RECT  6.48 0 6.504 0.084 ;
    END
  END ring_idle_core[2]
  PIN ring_idle_core[3]
    DIRECTION INPUT ;
    USE SIGNAL ;
    PORT
      LAYER M5 ;
        RECT  6.576 0 6.6 0.084 ;
    END
  END ring_idle_core[3]
  PIN ring_idle_hbm[0]
    DIRECTION INPUT ;
    USE SIGNAL ;
    PORT
      LAYER M5 ;
        RECT  6.672 0 6.696 0.084 ;
    END
  END ring_idle_hbm[0]
  PIN ring_idle_hbm[1]
    DIRECTION INPUT ;
    USE SIGNAL ;
    PORT
      LAYER M5 ;
        RECT  6.768 0 6.792 0.084 ;
    END
  END ring_idle_hbm[1]
  PIN ring_idle_hbm[2]
    DIRECTION INPUT ;
    USE SIGNAL ;
    PORT
      LAYER M5 ;
        RECT  9.936 0 9.96 0.084 ;
    END
  END ring_idle_hbm[2]
  PIN ring_idle_hbm[3]
    DIRECTION INPUT ;
    USE SIGNAL ;
    PORT
      LAYER M5 ;
        RECT  10.032 0 10.056 0.084 ;
    END
  END ring_idle_hbm[3]
  PIN rst_n
    DIRECTION INPUT ;
    USE SIGNAL ;
    PORT
      LAYER M4 ;
        RECT  0 50.352 0.084 50.376 ;
    END
  END rst_n
  PIN sink_addr[0]
    DIRECTION OUTPUT ;
    USE SIGNAL ;
    PORT
      LAYER M4 ;
        RECT  97.116 40.08 97.2 40.104 ;
    END
  END sink_addr[0]
  PIN sink_addr[10]
    DIRECTION OUTPUT ;
    USE SIGNAL ;
    PORT
      LAYER M4 ;
        RECT  97.116 41.04 97.2 41.064 ;
    END
  END sink_addr[10]
  PIN sink_addr[11]
    DIRECTION OUTPUT ;
    USE SIGNAL ;
    PORT
      LAYER M4 ;
        RECT  97.116 41.136 97.2 41.16 ;
    END
  END sink_addr[11]
  PIN sink_addr[12]
    DIRECTION OUTPUT ;
    USE SIGNAL ;
    PORT
      LAYER M4 ;
        RECT  97.116 41.232 97.2 41.256 ;
    END
  END sink_addr[12]
  PIN sink_addr[13]
    DIRECTION OUTPUT ;
    USE SIGNAL ;
    PORT
      LAYER M4 ;
        RECT  97.116 41.328 97.2 41.352 ;
    END
  END sink_addr[13]
  PIN sink_addr[14]
    DIRECTION OUTPUT ;
    USE SIGNAL ;
    PORT
      LAYER M4 ;
        RECT  97.116 41.424 97.2 41.448 ;
    END
  END sink_addr[14]
  PIN sink_addr[15]
    DIRECTION OUTPUT ;
    USE SIGNAL ;
    PORT
      LAYER M4 ;
        RECT  97.116 41.52 97.2 41.544 ;
    END
  END sink_addr[15]
  PIN sink_addr[16]
    DIRECTION OUTPUT ;
    USE SIGNAL ;
    PORT
      LAYER M4 ;
        RECT  97.116 41.616 97.2 41.64 ;
    END
  END sink_addr[16]
  PIN sink_addr[17]
    DIRECTION OUTPUT ;
    USE SIGNAL ;
    PORT
      LAYER M4 ;
        RECT  97.116 41.712 97.2 41.736 ;
    END
  END sink_addr[17]
  PIN sink_addr[18]
    DIRECTION OUTPUT ;
    USE SIGNAL ;
    PORT
      LAYER M4 ;
        RECT  97.116 41.808 97.2 41.832 ;
    END
  END sink_addr[18]
  PIN sink_addr[19]
    DIRECTION OUTPUT ;
    USE SIGNAL ;
    PORT
      LAYER M4 ;
        RECT  97.116 41.904 97.2 41.928 ;
    END
  END sink_addr[19]
  PIN sink_addr[1]
    DIRECTION OUTPUT ;
    USE SIGNAL ;
    PORT
      LAYER M4 ;
        RECT  97.116 40.176 97.2 40.2 ;
    END
  END sink_addr[1]
  PIN sink_addr[20]
    DIRECTION OUTPUT ;
    USE SIGNAL ;
    PORT
      LAYER M4 ;
        RECT  97.116 42 97.2 42.024 ;
    END
  END sink_addr[20]
  PIN sink_addr[21]
    DIRECTION OUTPUT ;
    USE SIGNAL ;
    PORT
      LAYER M4 ;
        RECT  97.116 42.096 97.2 42.12 ;
    END
  END sink_addr[21]
  PIN sink_addr[22]
    DIRECTION OUTPUT ;
    USE SIGNAL ;
    PORT
      LAYER M4 ;
        RECT  97.116 22.992 97.2 23.016 ;
    END
  END sink_addr[22]
  PIN sink_addr[23]
    DIRECTION OUTPUT ;
    USE SIGNAL ;
    PORT
      LAYER M4 ;
        RECT  97.116 23.088 97.2 23.112 ;
    END
  END sink_addr[23]
  PIN sink_addr[24]
    DIRECTION OUTPUT ;
    USE SIGNAL ;
    PORT
      LAYER M4 ;
        RECT  97.116 23.184 97.2 23.208 ;
    END
  END sink_addr[24]
  PIN sink_addr[25]
    DIRECTION OUTPUT ;
    USE SIGNAL ;
    PORT
      LAYER M4 ;
        RECT  97.116 23.28 97.2 23.304 ;
    END
  END sink_addr[25]
  PIN sink_addr[26]
    DIRECTION OUTPUT ;
    USE SIGNAL ;
    PORT
      LAYER M4 ;
        RECT  97.116 23.376 97.2 23.4 ;
    END
  END sink_addr[26]
  PIN sink_addr[27]
    DIRECTION OUTPUT ;
    USE SIGNAL ;
    PORT
      LAYER M4 ;
        RECT  97.116 23.472 97.2 23.496 ;
    END
  END sink_addr[27]
  PIN sink_addr[28]
    DIRECTION OUTPUT ;
    USE SIGNAL ;
    PORT
      LAYER M4 ;
        RECT  97.116 23.568 97.2 23.592 ;
    END
  END sink_addr[28]
  PIN sink_addr[29]
    DIRECTION OUTPUT ;
    USE SIGNAL ;
    PORT
      LAYER M4 ;
        RECT  97.116 23.664 97.2 23.688 ;
    END
  END sink_addr[29]
  PIN sink_addr[2]
    DIRECTION OUTPUT ;
    USE SIGNAL ;
    PORT
      LAYER M4 ;
        RECT  97.116 40.272 97.2 40.296 ;
    END
  END sink_addr[2]
  PIN sink_addr[30]
    DIRECTION OUTPUT ;
    USE SIGNAL ;
    PORT
      LAYER M4 ;
        RECT  97.116 23.76 97.2 23.784 ;
    END
  END sink_addr[30]
  PIN sink_addr[31]
    DIRECTION OUTPUT ;
    USE SIGNAL ;
    PORT
      LAYER M4 ;
        RECT  97.116 23.856 97.2 23.88 ;
    END
  END sink_addr[31]
  PIN sink_addr[32]
    DIRECTION OUTPUT ;
    USE SIGNAL ;
    PORT
      LAYER M4 ;
        RECT  97.116 23.952 97.2 23.976 ;
    END
  END sink_addr[32]
  PIN sink_addr[33]
    DIRECTION OUTPUT ;
    USE SIGNAL ;
    PORT
      LAYER M4 ;
        RECT  97.116 24.048 97.2 24.072 ;
    END
  END sink_addr[33]
  PIN sink_addr[34]
    DIRECTION OUTPUT ;
    USE SIGNAL ;
    PORT
      LAYER M4 ;
        RECT  97.116 24.144 97.2 24.168 ;
    END
  END sink_addr[34]
  PIN sink_addr[35]
    DIRECTION OUTPUT ;
    USE SIGNAL ;
    PORT
      LAYER M4 ;
        RECT  97.116 24.24 97.2 24.264 ;
    END
  END sink_addr[35]
  PIN sink_addr[36]
    DIRECTION OUTPUT ;
    USE SIGNAL ;
    PORT
      LAYER M4 ;
        RECT  97.116 24.336 97.2 24.36 ;
    END
  END sink_addr[36]
  PIN sink_addr[37]
    DIRECTION OUTPUT ;
    USE SIGNAL ;
    PORT
      LAYER M4 ;
        RECT  97.116 24.432 97.2 24.456 ;
    END
  END sink_addr[37]
  PIN sink_addr[38]
    DIRECTION OUTPUT ;
    USE SIGNAL ;
    PORT
      LAYER M4 ;
        RECT  97.116 24.528 97.2 24.552 ;
    END
  END sink_addr[38]
  PIN sink_addr[39]
    DIRECTION OUTPUT ;
    USE SIGNAL ;
    PORT
      LAYER M4 ;
        RECT  97.116 24.624 97.2 24.648 ;
    END
  END sink_addr[39]
  PIN sink_addr[3]
    DIRECTION OUTPUT ;
    USE SIGNAL ;
    PORT
      LAYER M4 ;
        RECT  97.116 40.368 97.2 40.392 ;
    END
  END sink_addr[3]
  PIN sink_addr[4]
    DIRECTION OUTPUT ;
    USE SIGNAL ;
    PORT
      LAYER M4 ;
        RECT  97.116 40.464 97.2 40.488 ;
    END
  END sink_addr[4]
  PIN sink_addr[5]
    DIRECTION OUTPUT ;
    USE SIGNAL ;
    PORT
      LAYER M4 ;
        RECT  97.116 40.56 97.2 40.584 ;
    END
  END sink_addr[5]
  PIN sink_addr[6]
    DIRECTION OUTPUT ;
    USE SIGNAL ;
    PORT
      LAYER M4 ;
        RECT  97.116 40.656 97.2 40.68 ;
    END
  END sink_addr[6]
  PIN sink_addr[7]
    DIRECTION OUTPUT ;
    USE SIGNAL ;
    PORT
      LAYER M4 ;
        RECT  97.116 40.752 97.2 40.776 ;
    END
  END sink_addr[7]
  PIN sink_addr[8]
    DIRECTION OUTPUT ;
    USE SIGNAL ;
    PORT
      LAYER M4 ;
        RECT  97.116 40.848 97.2 40.872 ;
    END
  END sink_addr[8]
  PIN sink_addr[9]
    DIRECTION OUTPUT ;
    USE SIGNAL ;
    PORT
      LAYER M4 ;
        RECT  97.116 40.944 97.2 40.968 ;
    END
  END sink_addr[9]
  PIN sink_data[0]
    DIRECTION OUTPUT ;
    USE SIGNAL ;
    PORT
      LAYER M4 ;
        RECT  97.116 24.72 97.2 24.744 ;
    END
  END sink_data[0]
  PIN sink_data[100]
    DIRECTION OUTPUT ;
    USE SIGNAL ;
    PORT
      LAYER M4 ;
        RECT  97.116 54.96 97.2 54.984 ;
    END
  END sink_data[100]
  PIN sink_data[101]
    DIRECTION OUTPUT ;
    USE SIGNAL ;
    PORT
      LAYER M4 ;
        RECT  97.116 55.056 97.2 55.08 ;
    END
  END sink_data[101]
  PIN sink_data[102]
    DIRECTION OUTPUT ;
    USE SIGNAL ;
    PORT
      LAYER M4 ;
        RECT  97.116 55.152 97.2 55.176 ;
    END
  END sink_data[102]
  PIN sink_data[103]
    DIRECTION OUTPUT ;
    USE SIGNAL ;
    PORT
      LAYER M4 ;
        RECT  97.116 55.248 97.2 55.272 ;
    END
  END sink_data[103]
  PIN sink_data[104]
    DIRECTION OUTPUT ;
    USE SIGNAL ;
    PORT
      LAYER M4 ;
        RECT  97.116 55.344 97.2 55.368 ;
    END
  END sink_data[104]
  PIN sink_data[105]
    DIRECTION OUTPUT ;
    USE SIGNAL ;
    PORT
      LAYER M4 ;
        RECT  97.116 55.44 97.2 55.464 ;
    END
  END sink_data[105]
  PIN sink_data[106]
    DIRECTION OUTPUT ;
    USE SIGNAL ;
    PORT
      LAYER M4 ;
        RECT  97.116 55.536 97.2 55.56 ;
    END
  END sink_data[106]
  PIN sink_data[107]
    DIRECTION OUTPUT ;
    USE SIGNAL ;
    PORT
      LAYER M4 ;
        RECT  97.116 55.632 97.2 55.656 ;
    END
  END sink_data[107]
  PIN sink_data[108]
    DIRECTION OUTPUT ;
    USE SIGNAL ;
    PORT
      LAYER M4 ;
        RECT  97.116 55.728 97.2 55.752 ;
    END
  END sink_data[108]
  PIN sink_data[109]
    DIRECTION OUTPUT ;
    USE SIGNAL ;
    PORT
      LAYER M4 ;
        RECT  97.116 55.824 97.2 55.848 ;
    END
  END sink_data[109]
  PIN sink_data[10]
    DIRECTION OUTPUT ;
    USE SIGNAL ;
    PORT
      LAYER M4 ;
        RECT  97.116 25.68 97.2 25.704 ;
    END
  END sink_data[10]
  PIN sink_data[110]
    DIRECTION OUTPUT ;
    USE SIGNAL ;
    PORT
      LAYER M4 ;
        RECT  97.116 49.776 97.2 49.8 ;
    END
  END sink_data[110]
  PIN sink_data[111]
    DIRECTION OUTPUT ;
    USE SIGNAL ;
    PORT
      LAYER M4 ;
        RECT  97.116 49.872 97.2 49.896 ;
    END
  END sink_data[111]
  PIN sink_data[112]
    DIRECTION OUTPUT ;
    USE SIGNAL ;
    PORT
      LAYER M4 ;
        RECT  97.116 49.968 97.2 49.992 ;
    END
  END sink_data[112]
  PIN sink_data[113]
    DIRECTION OUTPUT ;
    USE SIGNAL ;
    PORT
      LAYER M4 ;
        RECT  97.116 50.064 97.2 50.088 ;
    END
  END sink_data[113]
  PIN sink_data[114]
    DIRECTION OUTPUT ;
    USE SIGNAL ;
    PORT
      LAYER M4 ;
        RECT  97.116 50.16 97.2 50.184 ;
    END
  END sink_data[114]
  PIN sink_data[115]
    DIRECTION OUTPUT ;
    USE SIGNAL ;
    PORT
      LAYER M4 ;
        RECT  97.116 50.256 97.2 50.28 ;
    END
  END sink_data[115]
  PIN sink_data[116]
    DIRECTION OUTPUT ;
    USE SIGNAL ;
    PORT
      LAYER M4 ;
        RECT  97.116 50.352 97.2 50.376 ;
    END
  END sink_data[116]
  PIN sink_data[117]
    DIRECTION OUTPUT ;
    USE SIGNAL ;
    PORT
      LAYER M4 ;
        RECT  97.116 50.448 97.2 50.472 ;
    END
  END sink_data[117]
  PIN sink_data[118]
    DIRECTION OUTPUT ;
    USE SIGNAL ;
    PORT
      LAYER M4 ;
        RECT  97.116 50.544 97.2 50.568 ;
    END
  END sink_data[118]
  PIN sink_data[119]
    DIRECTION OUTPUT ;
    USE SIGNAL ;
    PORT
      LAYER M4 ;
        RECT  97.116 50.64 97.2 50.664 ;
    END
  END sink_data[119]
  PIN sink_data[11]
    DIRECTION OUTPUT ;
    USE SIGNAL ;
    PORT
      LAYER M4 ;
        RECT  97.116 25.776 97.2 25.8 ;
    END
  END sink_data[11]
  PIN sink_data[120]
    DIRECTION OUTPUT ;
    USE SIGNAL ;
    PORT
      LAYER M4 ;
        RECT  97.116 50.736 97.2 50.76 ;
    END
  END sink_data[120]
  PIN sink_data[121]
    DIRECTION OUTPUT ;
    USE SIGNAL ;
    PORT
      LAYER M4 ;
        RECT  97.116 50.832 97.2 50.856 ;
    END
  END sink_data[121]
  PIN sink_data[122]
    DIRECTION OUTPUT ;
    USE SIGNAL ;
    PORT
      LAYER M4 ;
        RECT  97.116 50.928 97.2 50.952 ;
    END
  END sink_data[122]
  PIN sink_data[123]
    DIRECTION OUTPUT ;
    USE SIGNAL ;
    PORT
      LAYER M4 ;
        RECT  97.116 51.024 97.2 51.048 ;
    END
  END sink_data[123]
  PIN sink_data[124]
    DIRECTION OUTPUT ;
    USE SIGNAL ;
    PORT
      LAYER M4 ;
        RECT  97.116 51.12 97.2 51.144 ;
    END
  END sink_data[124]
  PIN sink_data[125]
    DIRECTION OUTPUT ;
    USE SIGNAL ;
    PORT
      LAYER M4 ;
        RECT  97.116 51.216 97.2 51.24 ;
    END
  END sink_data[125]
  PIN sink_data[126]
    DIRECTION OUTPUT ;
    USE SIGNAL ;
    PORT
      LAYER M4 ;
        RECT  97.116 51.312 97.2 51.336 ;
    END
  END sink_data[126]
  PIN sink_data[127]
    DIRECTION OUTPUT ;
    USE SIGNAL ;
    PORT
      LAYER M4 ;
        RECT  97.116 51.408 97.2 51.432 ;
    END
  END sink_data[127]
  PIN sink_data[128]
    DIRECTION OUTPUT ;
    USE SIGNAL ;
    PORT
      LAYER M4 ;
        RECT  97.116 51.504 97.2 51.528 ;
    END
  END sink_data[128]
  PIN sink_data[129]
    DIRECTION OUTPUT ;
    USE SIGNAL ;
    PORT
      LAYER M4 ;
        RECT  97.116 51.6 97.2 51.624 ;
    END
  END sink_data[129]
  PIN sink_data[12]
    DIRECTION OUTPUT ;
    USE SIGNAL ;
    PORT
      LAYER M4 ;
        RECT  97.116 25.872 97.2 25.896 ;
    END
  END sink_data[12]
  PIN sink_data[130]
    DIRECTION OUTPUT ;
    USE SIGNAL ;
    PORT
      LAYER M4 ;
        RECT  97.116 51.696 97.2 51.72 ;
    END
  END sink_data[130]
  PIN sink_data[131]
    DIRECTION OUTPUT ;
    USE SIGNAL ;
    PORT
      LAYER M4 ;
        RECT  97.116 51.792 97.2 51.816 ;
    END
  END sink_data[131]
  PIN sink_data[132]
    DIRECTION OUTPUT ;
    USE SIGNAL ;
    PORT
      LAYER M4 ;
        RECT  97.116 51.888 97.2 51.912 ;
    END
  END sink_data[132]
  PIN sink_data[133]
    DIRECTION OUTPUT ;
    USE SIGNAL ;
    PORT
      LAYER M4 ;
        RECT  97.116 51.984 97.2 52.008 ;
    END
  END sink_data[133]
  PIN sink_data[134]
    DIRECTION OUTPUT ;
    USE SIGNAL ;
    PORT
      LAYER M4 ;
        RECT  97.116 52.08 97.2 52.104 ;
    END
  END sink_data[134]
  PIN sink_data[135]
    DIRECTION OUTPUT ;
    USE SIGNAL ;
    PORT
      LAYER M4 ;
        RECT  97.116 52.176 97.2 52.2 ;
    END
  END sink_data[135]
  PIN sink_data[136]
    DIRECTION OUTPUT ;
    USE SIGNAL ;
    PORT
      LAYER M4 ;
        RECT  97.116 52.272 97.2 52.296 ;
    END
  END sink_data[136]
  PIN sink_data[137]
    DIRECTION OUTPUT ;
    USE SIGNAL ;
    PORT
      LAYER M4 ;
        RECT  97.116 52.368 97.2 52.392 ;
    END
  END sink_data[137]
  PIN sink_data[138]
    DIRECTION OUTPUT ;
    USE SIGNAL ;
    PORT
      LAYER M4 ;
        RECT  97.116 52.464 97.2 52.488 ;
    END
  END sink_data[138]
  PIN sink_data[139]
    DIRECTION OUTPUT ;
    USE SIGNAL ;
    PORT
      LAYER M4 ;
        RECT  97.116 52.56 97.2 52.584 ;
    END
  END sink_data[139]
  PIN sink_data[13]
    DIRECTION OUTPUT ;
    USE SIGNAL ;
    PORT
      LAYER M4 ;
        RECT  97.116 25.968 97.2 25.992 ;
    END
  END sink_data[13]
  PIN sink_data[140]
    DIRECTION OUTPUT ;
    USE SIGNAL ;
    PORT
      LAYER M4 ;
        RECT  97.116 52.656 97.2 52.68 ;
    END
  END sink_data[140]
  PIN sink_data[141]
    DIRECTION OUTPUT ;
    USE SIGNAL ;
    PORT
      LAYER M4 ;
        RECT  97.116 52.752 97.2 52.776 ;
    END
  END sink_data[141]
  PIN sink_data[142]
    DIRECTION OUTPUT ;
    USE SIGNAL ;
    PORT
      LAYER M4 ;
        RECT  97.116 70.608 97.2 70.632 ;
    END
  END sink_data[142]
  PIN sink_data[143]
    DIRECTION OUTPUT ;
    USE SIGNAL ;
    PORT
      LAYER M4 ;
        RECT  97.116 70.704 97.2 70.728 ;
    END
  END sink_data[143]
  PIN sink_data[144]
    DIRECTION OUTPUT ;
    USE SIGNAL ;
    PORT
      LAYER M4 ;
        RECT  97.116 70.8 97.2 70.824 ;
    END
  END sink_data[144]
  PIN sink_data[145]
    DIRECTION OUTPUT ;
    USE SIGNAL ;
    PORT
      LAYER M4 ;
        RECT  97.116 70.896 97.2 70.92 ;
    END
  END sink_data[145]
  PIN sink_data[146]
    DIRECTION OUTPUT ;
    USE SIGNAL ;
    PORT
      LAYER M4 ;
        RECT  97.116 70.992 97.2 71.016 ;
    END
  END sink_data[146]
  PIN sink_data[147]
    DIRECTION OUTPUT ;
    USE SIGNAL ;
    PORT
      LAYER M4 ;
        RECT  97.116 71.088 97.2 71.112 ;
    END
  END sink_data[147]
  PIN sink_data[148]
    DIRECTION OUTPUT ;
    USE SIGNAL ;
    PORT
      LAYER M4 ;
        RECT  97.116 71.184 97.2 71.208 ;
    END
  END sink_data[148]
  PIN sink_data[149]
    DIRECTION OUTPUT ;
    USE SIGNAL ;
    PORT
      LAYER M4 ;
        RECT  97.116 71.28 97.2 71.304 ;
    END
  END sink_data[149]
  PIN sink_data[14]
    DIRECTION OUTPUT ;
    USE SIGNAL ;
    PORT
      LAYER M4 ;
        RECT  97.116 9.936 97.2 9.96 ;
    END
  END sink_data[14]
  PIN sink_data[150]
    DIRECTION OUTPUT ;
    USE SIGNAL ;
    PORT
      LAYER M4 ;
        RECT  97.116 71.376 97.2 71.4 ;
    END
  END sink_data[150]
  PIN sink_data[151]
    DIRECTION OUTPUT ;
    USE SIGNAL ;
    PORT
      LAYER M4 ;
        RECT  97.116 71.472 97.2 71.496 ;
    END
  END sink_data[151]
  PIN sink_data[152]
    DIRECTION OUTPUT ;
    USE SIGNAL ;
    PORT
      LAYER M4 ;
        RECT  97.116 71.568 97.2 71.592 ;
    END
  END sink_data[152]
  PIN sink_data[153]
    DIRECTION OUTPUT ;
    USE SIGNAL ;
    PORT
      LAYER M4 ;
        RECT  97.116 71.664 97.2 71.688 ;
    END
  END sink_data[153]
  PIN sink_data[154]
    DIRECTION OUTPUT ;
    USE SIGNAL ;
    PORT
      LAYER M4 ;
        RECT  97.116 71.76 97.2 71.784 ;
    END
  END sink_data[154]
  PIN sink_data[155]
    DIRECTION OUTPUT ;
    USE SIGNAL ;
    PORT
      LAYER M4 ;
        RECT  97.116 71.856 97.2 71.88 ;
    END
  END sink_data[155]
  PIN sink_data[156]
    DIRECTION OUTPUT ;
    USE SIGNAL ;
    PORT
      LAYER M4 ;
        RECT  97.116 71.952 97.2 71.976 ;
    END
  END sink_data[156]
  PIN sink_data[157]
    DIRECTION OUTPUT ;
    USE SIGNAL ;
    PORT
      LAYER M4 ;
        RECT  97.116 72.048 97.2 72.072 ;
    END
  END sink_data[157]
  PIN sink_data[158]
    DIRECTION OUTPUT ;
    USE SIGNAL ;
    PORT
      LAYER M4 ;
        RECT  97.116 72.144 97.2 72.168 ;
    END
  END sink_data[158]
  PIN sink_data[159]
    DIRECTION OUTPUT ;
    USE SIGNAL ;
    PORT
      LAYER M4 ;
        RECT  97.116 72.24 97.2 72.264 ;
    END
  END sink_data[159]
  PIN sink_data[15]
    DIRECTION OUTPUT ;
    USE SIGNAL ;
    PORT
      LAYER M4 ;
        RECT  97.116 10.032 97.2 10.056 ;
    END
  END sink_data[15]
  PIN sink_data[160]
    DIRECTION OUTPUT ;
    USE SIGNAL ;
    PORT
      LAYER M4 ;
        RECT  97.116 72.336 97.2 72.36 ;
    END
  END sink_data[160]
  PIN sink_data[161]
    DIRECTION OUTPUT ;
    USE SIGNAL ;
    PORT
      LAYER M4 ;
        RECT  97.116 72.432 97.2 72.456 ;
    END
  END sink_data[161]
  PIN sink_data[162]
    DIRECTION OUTPUT ;
    USE SIGNAL ;
    PORT
      LAYER M4 ;
        RECT  97.116 72.528 97.2 72.552 ;
    END
  END sink_data[162]
  PIN sink_data[163]
    DIRECTION OUTPUT ;
    USE SIGNAL ;
    PORT
      LAYER M4 ;
        RECT  97.116 72.624 97.2 72.648 ;
    END
  END sink_data[163]
  PIN sink_data[164]
    DIRECTION OUTPUT ;
    USE SIGNAL ;
    PORT
      LAYER M4 ;
        RECT  97.116 72.72 97.2 72.744 ;
    END
  END sink_data[164]
  PIN sink_data[165]
    DIRECTION OUTPUT ;
    USE SIGNAL ;
    PORT
      LAYER M4 ;
        RECT  97.116 72.816 97.2 72.84 ;
    END
  END sink_data[165]
  PIN sink_data[166]
    DIRECTION OUTPUT ;
    USE SIGNAL ;
    PORT
      LAYER M4 ;
        RECT  97.116 72.912 97.2 72.936 ;
    END
  END sink_data[166]
  PIN sink_data[167]
    DIRECTION OUTPUT ;
    USE SIGNAL ;
    PORT
      LAYER M4 ;
        RECT  97.116 73.008 97.2 73.032 ;
    END
  END sink_data[167]
  PIN sink_data[168]
    DIRECTION OUTPUT ;
    USE SIGNAL ;
    PORT
      LAYER M4 ;
        RECT  97.116 73.104 97.2 73.128 ;
    END
  END sink_data[168]
  PIN sink_data[169]
    DIRECTION OUTPUT ;
    USE SIGNAL ;
    PORT
      LAYER M4 ;
        RECT  97.116 73.2 97.2 73.224 ;
    END
  END sink_data[169]
  PIN sink_data[16]
    DIRECTION OUTPUT ;
    USE SIGNAL ;
    PORT
      LAYER M4 ;
        RECT  97.116 10.128 97.2 10.152 ;
    END
  END sink_data[16]
  PIN sink_data[170]
    DIRECTION OUTPUT ;
    USE SIGNAL ;
    PORT
      LAYER M4 ;
        RECT  97.116 73.296 97.2 73.32 ;
    END
  END sink_data[170]
  PIN sink_data[171]
    DIRECTION OUTPUT ;
    USE SIGNAL ;
    PORT
      LAYER M4 ;
        RECT  97.116 73.392 97.2 73.416 ;
    END
  END sink_data[171]
  PIN sink_data[172]
    DIRECTION OUTPUT ;
    USE SIGNAL ;
    PORT
      LAYER M4 ;
        RECT  97.116 73.488 97.2 73.512 ;
    END
  END sink_data[172]
  PIN sink_data[173]
    DIRECTION OUTPUT ;
    USE SIGNAL ;
    PORT
      LAYER M4 ;
        RECT  97.116 73.584 97.2 73.608 ;
    END
  END sink_data[173]
  PIN sink_data[174]
    DIRECTION OUTPUT ;
    USE SIGNAL ;
    PORT
      LAYER M4 ;
        RECT  97.116 67.536 97.2 67.56 ;
    END
  END sink_data[174]
  PIN sink_data[175]
    DIRECTION OUTPUT ;
    USE SIGNAL ;
    PORT
      LAYER M4 ;
        RECT  97.116 67.632 97.2 67.656 ;
    END
  END sink_data[175]
  PIN sink_data[176]
    DIRECTION OUTPUT ;
    USE SIGNAL ;
    PORT
      LAYER M4 ;
        RECT  97.116 67.728 97.2 67.752 ;
    END
  END sink_data[176]
  PIN sink_data[177]
    DIRECTION OUTPUT ;
    USE SIGNAL ;
    PORT
      LAYER M4 ;
        RECT  97.116 67.824 97.2 67.848 ;
    END
  END sink_data[177]
  PIN sink_data[178]
    DIRECTION OUTPUT ;
    USE SIGNAL ;
    PORT
      LAYER M4 ;
        RECT  97.116 67.92 97.2 67.944 ;
    END
  END sink_data[178]
  PIN sink_data[179]
    DIRECTION OUTPUT ;
    USE SIGNAL ;
    PORT
      LAYER M4 ;
        RECT  97.116 68.016 97.2 68.04 ;
    END
  END sink_data[179]
  PIN sink_data[17]
    DIRECTION OUTPUT ;
    USE SIGNAL ;
    PORT
      LAYER M4 ;
        RECT  97.116 10.224 97.2 10.248 ;
    END
  END sink_data[17]
  PIN sink_data[180]
    DIRECTION OUTPUT ;
    USE SIGNAL ;
    PORT
      LAYER M4 ;
        RECT  97.116 68.112 97.2 68.136 ;
    END
  END sink_data[180]
  PIN sink_data[181]
    DIRECTION OUTPUT ;
    USE SIGNAL ;
    PORT
      LAYER M4 ;
        RECT  97.116 68.208 97.2 68.232 ;
    END
  END sink_data[181]
  PIN sink_data[182]
    DIRECTION OUTPUT ;
    USE SIGNAL ;
    PORT
      LAYER M4 ;
        RECT  97.116 68.304 97.2 68.328 ;
    END
  END sink_data[182]
  PIN sink_data[183]
    DIRECTION OUTPUT ;
    USE SIGNAL ;
    PORT
      LAYER M4 ;
        RECT  97.116 68.4 97.2 68.424 ;
    END
  END sink_data[183]
  PIN sink_data[184]
    DIRECTION OUTPUT ;
    USE SIGNAL ;
    PORT
      LAYER M4 ;
        RECT  97.116 68.496 97.2 68.52 ;
    END
  END sink_data[184]
  PIN sink_data[185]
    DIRECTION OUTPUT ;
    USE SIGNAL ;
    PORT
      LAYER M4 ;
        RECT  97.116 68.592 97.2 68.616 ;
    END
  END sink_data[185]
  PIN sink_data[186]
    DIRECTION OUTPUT ;
    USE SIGNAL ;
    PORT
      LAYER M4 ;
        RECT  97.116 68.688 97.2 68.712 ;
    END
  END sink_data[186]
  PIN sink_data[187]
    DIRECTION OUTPUT ;
    USE SIGNAL ;
    PORT
      LAYER M4 ;
        RECT  97.116 68.784 97.2 68.808 ;
    END
  END sink_data[187]
  PIN sink_data[188]
    DIRECTION OUTPUT ;
    USE SIGNAL ;
    PORT
      LAYER M4 ;
        RECT  97.116 68.88 97.2 68.904 ;
    END
  END sink_data[188]
  PIN sink_data[189]
    DIRECTION OUTPUT ;
    USE SIGNAL ;
    PORT
      LAYER M4 ;
        RECT  97.116 68.976 97.2 69 ;
    END
  END sink_data[189]
  PIN sink_data[18]
    DIRECTION OUTPUT ;
    USE SIGNAL ;
    PORT
      LAYER M4 ;
        RECT  97.116 10.32 97.2 10.344 ;
    END
  END sink_data[18]
  PIN sink_data[190]
    DIRECTION OUTPUT ;
    USE SIGNAL ;
    PORT
      LAYER M4 ;
        RECT  97.116 69.072 97.2 69.096 ;
    END
  END sink_data[190]
  PIN sink_data[191]
    DIRECTION OUTPUT ;
    USE SIGNAL ;
    PORT
      LAYER M4 ;
        RECT  97.116 69.168 97.2 69.192 ;
    END
  END sink_data[191]
  PIN sink_data[192]
    DIRECTION OUTPUT ;
    USE SIGNAL ;
    PORT
      LAYER M4 ;
        RECT  97.116 69.264 97.2 69.288 ;
    END
  END sink_data[192]
  PIN sink_data[193]
    DIRECTION OUTPUT ;
    USE SIGNAL ;
    PORT
      LAYER M4 ;
        RECT  97.116 69.36 97.2 69.384 ;
    END
  END sink_data[193]
  PIN sink_data[194]
    DIRECTION OUTPUT ;
    USE SIGNAL ;
    PORT
      LAYER M4 ;
        RECT  97.116 69.456 97.2 69.48 ;
    END
  END sink_data[194]
  PIN sink_data[195]
    DIRECTION OUTPUT ;
    USE SIGNAL ;
    PORT
      LAYER M4 ;
        RECT  97.116 69.552 97.2 69.576 ;
    END
  END sink_data[195]
  PIN sink_data[196]
    DIRECTION OUTPUT ;
    USE SIGNAL ;
    PORT
      LAYER M4 ;
        RECT  97.116 69.648 97.2 69.672 ;
    END
  END sink_data[196]
  PIN sink_data[197]
    DIRECTION OUTPUT ;
    USE SIGNAL ;
    PORT
      LAYER M4 ;
        RECT  97.116 69.744 97.2 69.768 ;
    END
  END sink_data[197]
  PIN sink_data[198]
    DIRECTION OUTPUT ;
    USE SIGNAL ;
    PORT
      LAYER M4 ;
        RECT  97.116 69.84 97.2 69.864 ;
    END
  END sink_data[198]
  PIN sink_data[199]
    DIRECTION OUTPUT ;
    USE SIGNAL ;
    PORT
      LAYER M4 ;
        RECT  97.116 69.936 97.2 69.96 ;
    END
  END sink_data[199]
  PIN sink_data[19]
    DIRECTION OUTPUT ;
    USE SIGNAL ;
    PORT
      LAYER M4 ;
        RECT  97.116 10.416 97.2 10.44 ;
    END
  END sink_data[19]
  PIN sink_data[1]
    DIRECTION OUTPUT ;
    USE SIGNAL ;
    PORT
      LAYER M4 ;
        RECT  97.116 24.816 97.2 24.84 ;
    END
  END sink_data[1]
  PIN sink_data[200]
    DIRECTION OUTPUT ;
    USE SIGNAL ;
    PORT
      LAYER M4 ;
        RECT  97.116 70.032 97.2 70.056 ;
    END
  END sink_data[200]
  PIN sink_data[201]
    DIRECTION OUTPUT ;
    USE SIGNAL ;
    PORT
      LAYER M4 ;
        RECT  97.116 70.128 97.2 70.152 ;
    END
  END sink_data[201]
  PIN sink_data[202]
    DIRECTION OUTPUT ;
    USE SIGNAL ;
    PORT
      LAYER M4 ;
        RECT  97.116 70.224 97.2 70.248 ;
    END
  END sink_data[202]
  PIN sink_data[203]
    DIRECTION OUTPUT ;
    USE SIGNAL ;
    PORT
      LAYER M4 ;
        RECT  97.116 70.32 97.2 70.344 ;
    END
  END sink_data[203]
  PIN sink_data[204]
    DIRECTION OUTPUT ;
    USE SIGNAL ;
    PORT
      LAYER M4 ;
        RECT  97.116 70.416 97.2 70.44 ;
    END
  END sink_data[204]
  PIN sink_data[205]
    DIRECTION OUTPUT ;
    USE SIGNAL ;
    PORT
      LAYER M4 ;
        RECT  97.116 70.512 97.2 70.536 ;
    END
  END sink_data[205]
  PIN sink_data[206]
    DIRECTION OUTPUT ;
    USE SIGNAL ;
    PORT
      LAYER M4 ;
        RECT  97.116 19.92 97.2 19.944 ;
    END
  END sink_data[206]
  PIN sink_data[207]
    DIRECTION OUTPUT ;
    USE SIGNAL ;
    PORT
      LAYER M4 ;
        RECT  97.116 20.016 97.2 20.04 ;
    END
  END sink_data[207]
  PIN sink_data[208]
    DIRECTION OUTPUT ;
    USE SIGNAL ;
    PORT
      LAYER M4 ;
        RECT  97.116 20.112 97.2 20.136 ;
    END
  END sink_data[208]
  PIN sink_data[209]
    DIRECTION OUTPUT ;
    USE SIGNAL ;
    PORT
      LAYER M4 ;
        RECT  97.116 20.208 97.2 20.232 ;
    END
  END sink_data[209]
  PIN sink_data[20]
    DIRECTION OUTPUT ;
    USE SIGNAL ;
    PORT
      LAYER M4 ;
        RECT  97.116 10.512 97.2 10.536 ;
    END
  END sink_data[20]
  PIN sink_data[210]
    DIRECTION OUTPUT ;
    USE SIGNAL ;
    PORT
      LAYER M4 ;
        RECT  97.116 20.304 97.2 20.328 ;
    END
  END sink_data[210]
  PIN sink_data[211]
    DIRECTION OUTPUT ;
    USE SIGNAL ;
    PORT
      LAYER M4 ;
        RECT  97.116 20.4 97.2 20.424 ;
    END
  END sink_data[211]
  PIN sink_data[212]
    DIRECTION OUTPUT ;
    USE SIGNAL ;
    PORT
      LAYER M4 ;
        RECT  97.116 20.496 97.2 20.52 ;
    END
  END sink_data[212]
  PIN sink_data[213]
    DIRECTION OUTPUT ;
    USE SIGNAL ;
    PORT
      LAYER M4 ;
        RECT  97.116 20.592 97.2 20.616 ;
    END
  END sink_data[213]
  PIN sink_data[214]
    DIRECTION OUTPUT ;
    USE SIGNAL ;
    PORT
      LAYER M4 ;
        RECT  97.116 20.688 97.2 20.712 ;
    END
  END sink_data[214]
  PIN sink_data[215]
    DIRECTION OUTPUT ;
    USE SIGNAL ;
    PORT
      LAYER M4 ;
        RECT  97.116 20.784 97.2 20.808 ;
    END
  END sink_data[215]
  PIN sink_data[216]
    DIRECTION OUTPUT ;
    USE SIGNAL ;
    PORT
      LAYER M4 ;
        RECT  97.116 20.88 97.2 20.904 ;
    END
  END sink_data[216]
  PIN sink_data[217]
    DIRECTION OUTPUT ;
    USE SIGNAL ;
    PORT
      LAYER M4 ;
        RECT  97.116 20.976 97.2 21 ;
    END
  END sink_data[217]
  PIN sink_data[218]
    DIRECTION OUTPUT ;
    USE SIGNAL ;
    PORT
      LAYER M4 ;
        RECT  97.116 21.072 97.2 21.096 ;
    END
  END sink_data[218]
  PIN sink_data[219]
    DIRECTION OUTPUT ;
    USE SIGNAL ;
    PORT
      LAYER M4 ;
        RECT  97.116 21.168 97.2 21.192 ;
    END
  END sink_data[219]
  PIN sink_data[21]
    DIRECTION OUTPUT ;
    USE SIGNAL ;
    PORT
      LAYER M4 ;
        RECT  97.116 10.608 97.2 10.632 ;
    END
  END sink_data[21]
  PIN sink_data[220]
    DIRECTION OUTPUT ;
    USE SIGNAL ;
    PORT
      LAYER M4 ;
        RECT  97.116 21.264 97.2 21.288 ;
    END
  END sink_data[220]
  PIN sink_data[221]
    DIRECTION OUTPUT ;
    USE SIGNAL ;
    PORT
      LAYER M4 ;
        RECT  97.116 21.36 97.2 21.384 ;
    END
  END sink_data[221]
  PIN sink_data[222]
    DIRECTION OUTPUT ;
    USE SIGNAL ;
    PORT
      LAYER M4 ;
        RECT  97.116 21.456 97.2 21.48 ;
    END
  END sink_data[222]
  PIN sink_data[223]
    DIRECTION OUTPUT ;
    USE SIGNAL ;
    PORT
      LAYER M4 ;
        RECT  97.116 21.552 97.2 21.576 ;
    END
  END sink_data[223]
  PIN sink_data[224]
    DIRECTION OUTPUT ;
    USE SIGNAL ;
    PORT
      LAYER M4 ;
        RECT  97.116 21.648 97.2 21.672 ;
    END
  END sink_data[224]
  PIN sink_data[225]
    DIRECTION OUTPUT ;
    USE SIGNAL ;
    PORT
      LAYER M4 ;
        RECT  97.116 21.744 97.2 21.768 ;
    END
  END sink_data[225]
  PIN sink_data[226]
    DIRECTION OUTPUT ;
    USE SIGNAL ;
    PORT
      LAYER M4 ;
        RECT  97.116 21.84 97.2 21.864 ;
    END
  END sink_data[226]
  PIN sink_data[227]
    DIRECTION OUTPUT ;
    USE SIGNAL ;
    PORT
      LAYER M4 ;
        RECT  97.116 21.936 97.2 21.96 ;
    END
  END sink_data[227]
  PIN sink_data[228]
    DIRECTION OUTPUT ;
    USE SIGNAL ;
    PORT
      LAYER M4 ;
        RECT  97.116 22.032 97.2 22.056 ;
    END
  END sink_data[228]
  PIN sink_data[229]
    DIRECTION OUTPUT ;
    USE SIGNAL ;
    PORT
      LAYER M4 ;
        RECT  97.116 22.128 97.2 22.152 ;
    END
  END sink_data[229]
  PIN sink_data[22]
    DIRECTION OUTPUT ;
    USE SIGNAL ;
    PORT
      LAYER M4 ;
        RECT  97.116 10.704 97.2 10.728 ;
    END
  END sink_data[22]
  PIN sink_data[230]
    DIRECTION OUTPUT ;
    USE SIGNAL ;
    PORT
      LAYER M4 ;
        RECT  97.116 22.224 97.2 22.248 ;
    END
  END sink_data[230]
  PIN sink_data[231]
    DIRECTION OUTPUT ;
    USE SIGNAL ;
    PORT
      LAYER M4 ;
        RECT  97.116 22.32 97.2 22.344 ;
    END
  END sink_data[231]
  PIN sink_data[232]
    DIRECTION OUTPUT ;
    USE SIGNAL ;
    PORT
      LAYER M4 ;
        RECT  97.116 22.416 97.2 22.44 ;
    END
  END sink_data[232]
  PIN sink_data[233]
    DIRECTION OUTPUT ;
    USE SIGNAL ;
    PORT
      LAYER M4 ;
        RECT  97.116 22.512 97.2 22.536 ;
    END
  END sink_data[233]
  PIN sink_data[234]
    DIRECTION OUTPUT ;
    USE SIGNAL ;
    PORT
      LAYER M4 ;
        RECT  97.116 22.608 97.2 22.632 ;
    END
  END sink_data[234]
  PIN sink_data[235]
    DIRECTION OUTPUT ;
    USE SIGNAL ;
    PORT
      LAYER M4 ;
        RECT  97.116 22.704 97.2 22.728 ;
    END
  END sink_data[235]
  PIN sink_data[236]
    DIRECTION OUTPUT ;
    USE SIGNAL ;
    PORT
      LAYER M4 ;
        RECT  97.116 22.8 97.2 22.824 ;
    END
  END sink_data[236]
  PIN sink_data[237]
    DIRECTION OUTPUT ;
    USE SIGNAL ;
    PORT
      LAYER M4 ;
        RECT  97.116 22.896 97.2 22.92 ;
    END
  END sink_data[237]
  PIN sink_data[238]
    DIRECTION OUTPUT ;
    USE SIGNAL ;
    PORT
      LAYER M4 ;
        RECT  97.116 16.08 97.2 16.104 ;
    END
  END sink_data[238]
  PIN sink_data[239]
    DIRECTION OUTPUT ;
    USE SIGNAL ;
    PORT
      LAYER M4 ;
        RECT  97.116 16.176 97.2 16.2 ;
    END
  END sink_data[239]
  PIN sink_data[23]
    DIRECTION OUTPUT ;
    USE SIGNAL ;
    PORT
      LAYER M4 ;
        RECT  97.116 10.8 97.2 10.824 ;
    END
  END sink_data[23]
  PIN sink_data[240]
    DIRECTION OUTPUT ;
    USE SIGNAL ;
    PORT
      LAYER M4 ;
        RECT  97.116 16.272 97.2 16.296 ;
    END
  END sink_data[240]
  PIN sink_data[241]
    DIRECTION OUTPUT ;
    USE SIGNAL ;
    PORT
      LAYER M4 ;
        RECT  97.116 16.368 97.2 16.392 ;
    END
  END sink_data[241]
  PIN sink_data[242]
    DIRECTION OUTPUT ;
    USE SIGNAL ;
    PORT
      LAYER M4 ;
        RECT  97.116 16.464 97.2 16.488 ;
    END
  END sink_data[242]
  PIN sink_data[243]
    DIRECTION OUTPUT ;
    USE SIGNAL ;
    PORT
      LAYER M4 ;
        RECT  97.116 16.56 97.2 16.584 ;
    END
  END sink_data[243]
  PIN sink_data[244]
    DIRECTION OUTPUT ;
    USE SIGNAL ;
    PORT
      LAYER M4 ;
        RECT  97.116 16.656 97.2 16.68 ;
    END
  END sink_data[244]
  PIN sink_data[245]
    DIRECTION OUTPUT ;
    USE SIGNAL ;
    PORT
      LAYER M4 ;
        RECT  97.116 16.752 97.2 16.776 ;
    END
  END sink_data[245]
  PIN sink_data[246]
    DIRECTION OUTPUT ;
    USE SIGNAL ;
    PORT
      LAYER M4 ;
        RECT  97.116 16.848 97.2 16.872 ;
    END
  END sink_data[246]
  PIN sink_data[247]
    DIRECTION OUTPUT ;
    USE SIGNAL ;
    PORT
      LAYER M4 ;
        RECT  97.116 16.944 97.2 16.968 ;
    END
  END sink_data[247]
  PIN sink_data[248]
    DIRECTION OUTPUT ;
    USE SIGNAL ;
    PORT
      LAYER M4 ;
        RECT  97.116 17.04 97.2 17.064 ;
    END
  END sink_data[248]
  PIN sink_data[249]
    DIRECTION OUTPUT ;
    USE SIGNAL ;
    PORT
      LAYER M4 ;
        RECT  97.116 17.136 97.2 17.16 ;
    END
  END sink_data[249]
  PIN sink_data[24]
    DIRECTION OUTPUT ;
    USE SIGNAL ;
    PORT
      LAYER M4 ;
        RECT  97.116 10.896 97.2 10.92 ;
    END
  END sink_data[24]
  PIN sink_data[250]
    DIRECTION OUTPUT ;
    USE SIGNAL ;
    PORT
      LAYER M4 ;
        RECT  97.116 17.232 97.2 17.256 ;
    END
  END sink_data[250]
  PIN sink_data[251]
    DIRECTION OUTPUT ;
    USE SIGNAL ;
    PORT
      LAYER M4 ;
        RECT  97.116 17.328 97.2 17.352 ;
    END
  END sink_data[251]
  PIN sink_data[252]
    DIRECTION OUTPUT ;
    USE SIGNAL ;
    PORT
      LAYER M4 ;
        RECT  97.116 17.424 97.2 17.448 ;
    END
  END sink_data[252]
  PIN sink_data[253]
    DIRECTION OUTPUT ;
    USE SIGNAL ;
    PORT
      LAYER M4 ;
        RECT  97.116 17.52 97.2 17.544 ;
    END
  END sink_data[253]
  PIN sink_data[254]
    DIRECTION OUTPUT ;
    USE SIGNAL ;
    PORT
      LAYER M4 ;
        RECT  97.116 17.616 97.2 17.64 ;
    END
  END sink_data[254]
  PIN sink_data[255]
    DIRECTION OUTPUT ;
    USE SIGNAL ;
    PORT
      LAYER M4 ;
        RECT  97.116 17.712 97.2 17.736 ;
    END
  END sink_data[255]
  PIN sink_data[256]
    DIRECTION OUTPUT ;
    USE SIGNAL ;
    PORT
      LAYER M4 ;
        RECT  97.116 17.808 97.2 17.832 ;
    END
  END sink_data[256]
  PIN sink_data[257]
    DIRECTION OUTPUT ;
    USE SIGNAL ;
    PORT
      LAYER M4 ;
        RECT  97.116 17.904 97.2 17.928 ;
    END
  END sink_data[257]
  PIN sink_data[258]
    DIRECTION OUTPUT ;
    USE SIGNAL ;
    PORT
      LAYER M4 ;
        RECT  97.116 18 97.2 18.024 ;
    END
  END sink_data[258]
  PIN sink_data[259]
    DIRECTION OUTPUT ;
    USE SIGNAL ;
    PORT
      LAYER M4 ;
        RECT  97.116 18.096 97.2 18.12 ;
    END
  END sink_data[259]
  PIN sink_data[25]
    DIRECTION OUTPUT ;
    USE SIGNAL ;
    PORT
      LAYER M4 ;
        RECT  97.116 10.992 97.2 11.016 ;
    END
  END sink_data[25]
  PIN sink_data[260]
    DIRECTION OUTPUT ;
    USE SIGNAL ;
    PORT
      LAYER M4 ;
        RECT  97.116 18.192 97.2 18.216 ;
    END
  END sink_data[260]
  PIN sink_data[261]
    DIRECTION OUTPUT ;
    USE SIGNAL ;
    PORT
      LAYER M4 ;
        RECT  97.116 18.288 97.2 18.312 ;
    END
  END sink_data[261]
  PIN sink_data[262]
    DIRECTION OUTPUT ;
    USE SIGNAL ;
    PORT
      LAYER M4 ;
        RECT  97.116 18.384 97.2 18.408 ;
    END
  END sink_data[262]
  PIN sink_data[263]
    DIRECTION OUTPUT ;
    USE SIGNAL ;
    PORT
      LAYER M4 ;
        RECT  97.116 18.48 97.2 18.504 ;
    END
  END sink_data[263]
  PIN sink_data[264]
    DIRECTION OUTPUT ;
    USE SIGNAL ;
    PORT
      LAYER M4 ;
        RECT  97.116 18.576 97.2 18.6 ;
    END
  END sink_data[264]
  PIN sink_data[265]
    DIRECTION OUTPUT ;
    USE SIGNAL ;
    PORT
      LAYER M4 ;
        RECT  97.116 18.672 97.2 18.696 ;
    END
  END sink_data[265]
  PIN sink_data[266]
    DIRECTION OUTPUT ;
    USE SIGNAL ;
    PORT
      LAYER M4 ;
        RECT  97.116 18.768 97.2 18.792 ;
    END
  END sink_data[266]
  PIN sink_data[267]
    DIRECTION OUTPUT ;
    USE SIGNAL ;
    PORT
      LAYER M4 ;
        RECT  97.116 18.864 97.2 18.888 ;
    END
  END sink_data[267]
  PIN sink_data[268]
    DIRECTION OUTPUT ;
    USE SIGNAL ;
    PORT
      LAYER M4 ;
        RECT  97.116 18.96 97.2 18.984 ;
    END
  END sink_data[268]
  PIN sink_data[269]
    DIRECTION OUTPUT ;
    USE SIGNAL ;
    PORT
      LAYER M4 ;
        RECT  97.116 19.056 97.2 19.08 ;
    END
  END sink_data[269]
  PIN sink_data[26]
    DIRECTION OUTPUT ;
    USE SIGNAL ;
    PORT
      LAYER M4 ;
        RECT  97.116 11.088 97.2 11.112 ;
    END
  END sink_data[26]
  PIN sink_data[270]
    DIRECTION OUTPUT ;
    USE SIGNAL ;
    PORT
      LAYER M4 ;
        RECT  97.116 73.68 97.2 73.704 ;
    END
  END sink_data[270]
  PIN sink_data[271]
    DIRECTION OUTPUT ;
    USE SIGNAL ;
    PORT
      LAYER M4 ;
        RECT  97.116 73.776 97.2 73.8 ;
    END
  END sink_data[271]
  PIN sink_data[272]
    DIRECTION OUTPUT ;
    USE SIGNAL ;
    PORT
      LAYER M4 ;
        RECT  97.116 73.872 97.2 73.896 ;
    END
  END sink_data[272]
  PIN sink_data[273]
    DIRECTION OUTPUT ;
    USE SIGNAL ;
    PORT
      LAYER M4 ;
        RECT  97.116 73.968 97.2 73.992 ;
    END
  END sink_data[273]
  PIN sink_data[274]
    DIRECTION OUTPUT ;
    USE SIGNAL ;
    PORT
      LAYER M4 ;
        RECT  97.116 74.064 97.2 74.088 ;
    END
  END sink_data[274]
  PIN sink_data[275]
    DIRECTION OUTPUT ;
    USE SIGNAL ;
    PORT
      LAYER M4 ;
        RECT  97.116 74.16 97.2 74.184 ;
    END
  END sink_data[275]
  PIN sink_data[276]
    DIRECTION OUTPUT ;
    USE SIGNAL ;
    PORT
      LAYER M4 ;
        RECT  97.116 74.256 97.2 74.28 ;
    END
  END sink_data[276]
  PIN sink_data[277]
    DIRECTION OUTPUT ;
    USE SIGNAL ;
    PORT
      LAYER M4 ;
        RECT  97.116 74.352 97.2 74.376 ;
    END
  END sink_data[277]
  PIN sink_data[278]
    DIRECTION OUTPUT ;
    USE SIGNAL ;
    PORT
      LAYER M4 ;
        RECT  97.116 74.448 97.2 74.472 ;
    END
  END sink_data[278]
  PIN sink_data[279]
    DIRECTION OUTPUT ;
    USE SIGNAL ;
    PORT
      LAYER M4 ;
        RECT  97.116 74.544 97.2 74.568 ;
    END
  END sink_data[279]
  PIN sink_data[27]
    DIRECTION OUTPUT ;
    USE SIGNAL ;
    PORT
      LAYER M4 ;
        RECT  97.116 11.184 97.2 11.208 ;
    END
  END sink_data[27]
  PIN sink_data[280]
    DIRECTION OUTPUT ;
    USE SIGNAL ;
    PORT
      LAYER M4 ;
        RECT  97.116 74.64 97.2 74.664 ;
    END
  END sink_data[280]
  PIN sink_data[281]
    DIRECTION OUTPUT ;
    USE SIGNAL ;
    PORT
      LAYER M4 ;
        RECT  97.116 74.736 97.2 74.76 ;
    END
  END sink_data[281]
  PIN sink_data[282]
    DIRECTION OUTPUT ;
    USE SIGNAL ;
    PORT
      LAYER M4 ;
        RECT  97.116 74.832 97.2 74.856 ;
    END
  END sink_data[282]
  PIN sink_data[283]
    DIRECTION OUTPUT ;
    USE SIGNAL ;
    PORT
      LAYER M4 ;
        RECT  97.116 74.928 97.2 74.952 ;
    END
  END sink_data[283]
  PIN sink_data[284]
    DIRECTION OUTPUT ;
    USE SIGNAL ;
    PORT
      LAYER M4 ;
        RECT  97.116 75.024 97.2 75.048 ;
    END
  END sink_data[284]
  PIN sink_data[285]
    DIRECTION OUTPUT ;
    USE SIGNAL ;
    PORT
      LAYER M4 ;
        RECT  97.116 75.12 97.2 75.144 ;
    END
  END sink_data[285]
  PIN sink_data[286]
    DIRECTION OUTPUT ;
    USE SIGNAL ;
    PORT
      LAYER M4 ;
        RECT  97.116 75.216 97.2 75.24 ;
    END
  END sink_data[286]
  PIN sink_data[287]
    DIRECTION OUTPUT ;
    USE SIGNAL ;
    PORT
      LAYER M4 ;
        RECT  97.116 75.312 97.2 75.336 ;
    END
  END sink_data[287]
  PIN sink_data[288]
    DIRECTION OUTPUT ;
    USE SIGNAL ;
    PORT
      LAYER M4 ;
        RECT  97.116 75.408 97.2 75.432 ;
    END
  END sink_data[288]
  PIN sink_data[289]
    DIRECTION OUTPUT ;
    USE SIGNAL ;
    PORT
      LAYER M4 ;
        RECT  97.116 75.504 97.2 75.528 ;
    END
  END sink_data[289]
  PIN sink_data[28]
    DIRECTION OUTPUT ;
    USE SIGNAL ;
    PORT
      LAYER M4 ;
        RECT  97.116 11.28 97.2 11.304 ;
    END
  END sink_data[28]
  PIN sink_data[290]
    DIRECTION OUTPUT ;
    USE SIGNAL ;
    PORT
      LAYER M4 ;
        RECT  97.116 75.6 97.2 75.624 ;
    END
  END sink_data[290]
  PIN sink_data[291]
    DIRECTION OUTPUT ;
    USE SIGNAL ;
    PORT
      LAYER M4 ;
        RECT  97.116 75.696 97.2 75.72 ;
    END
  END sink_data[291]
  PIN sink_data[292]
    DIRECTION OUTPUT ;
    USE SIGNAL ;
    PORT
      LAYER M4 ;
        RECT  97.116 75.792 97.2 75.816 ;
    END
  END sink_data[292]
  PIN sink_data[293]
    DIRECTION OUTPUT ;
    USE SIGNAL ;
    PORT
      LAYER M4 ;
        RECT  97.116 75.888 97.2 75.912 ;
    END
  END sink_data[293]
  PIN sink_data[294]
    DIRECTION OUTPUT ;
    USE SIGNAL ;
    PORT
      LAYER M4 ;
        RECT  97.116 75.984 97.2 76.008 ;
    END
  END sink_data[294]
  PIN sink_data[295]
    DIRECTION OUTPUT ;
    USE SIGNAL ;
    PORT
      LAYER M4 ;
        RECT  97.116 76.08 97.2 76.104 ;
    END
  END sink_data[295]
  PIN sink_data[296]
    DIRECTION OUTPUT ;
    USE SIGNAL ;
    PORT
      LAYER M4 ;
        RECT  97.116 76.176 97.2 76.2 ;
    END
  END sink_data[296]
  PIN sink_data[297]
    DIRECTION OUTPUT ;
    USE SIGNAL ;
    PORT
      LAYER M4 ;
        RECT  97.116 76.272 97.2 76.296 ;
    END
  END sink_data[297]
  PIN sink_data[298]
    DIRECTION OUTPUT ;
    USE SIGNAL ;
    PORT
      LAYER M4 ;
        RECT  97.116 76.368 97.2 76.392 ;
    END
  END sink_data[298]
  PIN sink_data[299]
    DIRECTION OUTPUT ;
    USE SIGNAL ;
    PORT
      LAYER M4 ;
        RECT  97.116 76.464 97.2 76.488 ;
    END
  END sink_data[299]
  PIN sink_data[29]
    DIRECTION OUTPUT ;
    USE SIGNAL ;
    PORT
      LAYER M4 ;
        RECT  97.116 11.376 97.2 11.4 ;
    END
  END sink_data[29]
  PIN sink_data[2]
    DIRECTION OUTPUT ;
    USE SIGNAL ;
    PORT
      LAYER M4 ;
        RECT  97.116 24.912 97.2 24.936 ;
    END
  END sink_data[2]
  PIN sink_data[300]
    DIRECTION OUTPUT ;
    USE SIGNAL ;
    PORT
      LAYER M4 ;
        RECT  97.116 76.56 97.2 76.584 ;
    END
  END sink_data[300]
  PIN sink_data[301]
    DIRECTION OUTPUT ;
    USE SIGNAL ;
    PORT
      LAYER M4 ;
        RECT  97.116 76.656 97.2 76.68 ;
    END
  END sink_data[301]
  PIN sink_data[302]
    DIRECTION OUTPUT ;
    USE SIGNAL ;
    PORT
      LAYER M4 ;
        RECT  97.116 82.896 97.2 82.92 ;
    END
  END sink_data[302]
  PIN sink_data[303]
    DIRECTION OUTPUT ;
    USE SIGNAL ;
    PORT
      LAYER M4 ;
        RECT  97.116 82.992 97.2 83.016 ;
    END
  END sink_data[303]
  PIN sink_data[304]
    DIRECTION OUTPUT ;
    USE SIGNAL ;
    PORT
      LAYER M4 ;
        RECT  97.116 83.088 97.2 83.112 ;
    END
  END sink_data[304]
  PIN sink_data[305]
    DIRECTION OUTPUT ;
    USE SIGNAL ;
    PORT
      LAYER M4 ;
        RECT  97.116 83.184 97.2 83.208 ;
    END
  END sink_data[305]
  PIN sink_data[306]
    DIRECTION OUTPUT ;
    USE SIGNAL ;
    PORT
      LAYER M4 ;
        RECT  97.116 83.28 97.2 83.304 ;
    END
  END sink_data[306]
  PIN sink_data[307]
    DIRECTION OUTPUT ;
    USE SIGNAL ;
    PORT
      LAYER M4 ;
        RECT  97.116 83.376 97.2 83.4 ;
    END
  END sink_data[307]
  PIN sink_data[308]
    DIRECTION OUTPUT ;
    USE SIGNAL ;
    PORT
      LAYER M4 ;
        RECT  97.116 83.472 97.2 83.496 ;
    END
  END sink_data[308]
  PIN sink_data[309]
    DIRECTION OUTPUT ;
    USE SIGNAL ;
    PORT
      LAYER M4 ;
        RECT  97.116 83.568 97.2 83.592 ;
    END
  END sink_data[309]
  PIN sink_data[30]
    DIRECTION OUTPUT ;
    USE SIGNAL ;
    PORT
      LAYER M4 ;
        RECT  97.116 11.472 97.2 11.496 ;
    END
  END sink_data[30]
  PIN sink_data[310]
    DIRECTION OUTPUT ;
    USE SIGNAL ;
    PORT
      LAYER M4 ;
        RECT  97.116 83.664 97.2 83.688 ;
    END
  END sink_data[310]
  PIN sink_data[311]
    DIRECTION OUTPUT ;
    USE SIGNAL ;
    PORT
      LAYER M4 ;
        RECT  97.116 83.76 97.2 83.784 ;
    END
  END sink_data[311]
  PIN sink_data[312]
    DIRECTION OUTPUT ;
    USE SIGNAL ;
    PORT
      LAYER M4 ;
        RECT  97.116 83.856 97.2 83.88 ;
    END
  END sink_data[312]
  PIN sink_data[313]
    DIRECTION OUTPUT ;
    USE SIGNAL ;
    PORT
      LAYER M4 ;
        RECT  97.116 83.952 97.2 83.976 ;
    END
  END sink_data[313]
  PIN sink_data[314]
    DIRECTION OUTPUT ;
    USE SIGNAL ;
    PORT
      LAYER M4 ;
        RECT  97.116 84.048 97.2 84.072 ;
    END
  END sink_data[314]
  PIN sink_data[315]
    DIRECTION OUTPUT ;
    USE SIGNAL ;
    PORT
      LAYER M4 ;
        RECT  97.116 84.144 97.2 84.168 ;
    END
  END sink_data[315]
  PIN sink_data[316]
    DIRECTION OUTPUT ;
    USE SIGNAL ;
    PORT
      LAYER M4 ;
        RECT  97.116 84.24 97.2 84.264 ;
    END
  END sink_data[316]
  PIN sink_data[317]
    DIRECTION OUTPUT ;
    USE SIGNAL ;
    PORT
      LAYER M4 ;
        RECT  97.116 84.336 97.2 84.36 ;
    END
  END sink_data[317]
  PIN sink_data[318]
    DIRECTION OUTPUT ;
    USE SIGNAL ;
    PORT
      LAYER M4 ;
        RECT  97.116 84.432 97.2 84.456 ;
    END
  END sink_data[318]
  PIN sink_data[319]
    DIRECTION OUTPUT ;
    USE SIGNAL ;
    PORT
      LAYER M4 ;
        RECT  97.116 84.528 97.2 84.552 ;
    END
  END sink_data[319]
  PIN sink_data[31]
    DIRECTION OUTPUT ;
    USE SIGNAL ;
    PORT
      LAYER M4 ;
        RECT  97.116 11.568 97.2 11.592 ;
    END
  END sink_data[31]
  PIN sink_data[32]
    DIRECTION OUTPUT ;
    USE SIGNAL ;
    PORT
      LAYER M4 ;
        RECT  97.116 11.664 97.2 11.688 ;
    END
  END sink_data[32]
  PIN sink_data[33]
    DIRECTION OUTPUT ;
    USE SIGNAL ;
    PORT
      LAYER M4 ;
        RECT  97.116 11.76 97.2 11.784 ;
    END
  END sink_data[33]
  PIN sink_data[34]
    DIRECTION OUTPUT ;
    USE SIGNAL ;
    PORT
      LAYER M4 ;
        RECT  97.116 11.856 97.2 11.88 ;
    END
  END sink_data[34]
  PIN sink_data[35]
    DIRECTION OUTPUT ;
    USE SIGNAL ;
    PORT
      LAYER M4 ;
        RECT  97.116 11.952 97.2 11.976 ;
    END
  END sink_data[35]
  PIN sink_data[36]
    DIRECTION OUTPUT ;
    USE SIGNAL ;
    PORT
      LAYER M4 ;
        RECT  97.116 12.048 97.2 12.072 ;
    END
  END sink_data[36]
  PIN sink_data[37]
    DIRECTION OUTPUT ;
    USE SIGNAL ;
    PORT
      LAYER M4 ;
        RECT  97.116 12.144 97.2 12.168 ;
    END
  END sink_data[37]
  PIN sink_data[38]
    DIRECTION OUTPUT ;
    USE SIGNAL ;
    PORT
      LAYER M4 ;
        RECT  97.116 12.24 97.2 12.264 ;
    END
  END sink_data[38]
  PIN sink_data[39]
    DIRECTION OUTPUT ;
    USE SIGNAL ;
    PORT
      LAYER M4 ;
        RECT  97.116 12.336 97.2 12.36 ;
    END
  END sink_data[39]
  PIN sink_data[3]
    DIRECTION OUTPUT ;
    USE SIGNAL ;
    PORT
      LAYER M4 ;
        RECT  97.116 25.008 97.2 25.032 ;
    END
  END sink_data[3]
  PIN sink_data[40]
    DIRECTION OUTPUT ;
    USE SIGNAL ;
    PORT
      LAYER M4 ;
        RECT  97.116 12.432 97.2 12.456 ;
    END
  END sink_data[40]
  PIN sink_data[41]
    DIRECTION OUTPUT ;
    USE SIGNAL ;
    PORT
      LAYER M4 ;
        RECT  97.116 12.528 97.2 12.552 ;
    END
  END sink_data[41]
  PIN sink_data[42]
    DIRECTION OUTPUT ;
    USE SIGNAL ;
    PORT
      LAYER M4 ;
        RECT  97.116 12.624 97.2 12.648 ;
    END
  END sink_data[42]
  PIN sink_data[43]
    DIRECTION OUTPUT ;
    USE SIGNAL ;
    PORT
      LAYER M4 ;
        RECT  97.116 12.72 97.2 12.744 ;
    END
  END sink_data[43]
  PIN sink_data[44]
    DIRECTION OUTPUT ;
    USE SIGNAL ;
    PORT
      LAYER M4 ;
        RECT  97.116 12.816 97.2 12.84 ;
    END
  END sink_data[44]
  PIN sink_data[45]
    DIRECTION OUTPUT ;
    USE SIGNAL ;
    PORT
      LAYER M4 ;
        RECT  97.116 12.912 97.2 12.936 ;
    END
  END sink_data[45]
  PIN sink_data[46]
    DIRECTION OUTPUT ;
    USE SIGNAL ;
    PORT
      LAYER M4 ;
        RECT  97.116 42.192 97.2 42.216 ;
    END
  END sink_data[46]
  PIN sink_data[47]
    DIRECTION OUTPUT ;
    USE SIGNAL ;
    PORT
      LAYER M4 ;
        RECT  97.116 42.288 97.2 42.312 ;
    END
  END sink_data[47]
  PIN sink_data[48]
    DIRECTION OUTPUT ;
    USE SIGNAL ;
    PORT
      LAYER M4 ;
        RECT  97.116 42.384 97.2 42.408 ;
    END
  END sink_data[48]
  PIN sink_data[49]
    DIRECTION OUTPUT ;
    USE SIGNAL ;
    PORT
      LAYER M4 ;
        RECT  97.116 42.48 97.2 42.504 ;
    END
  END sink_data[49]
  PIN sink_data[4]
    DIRECTION OUTPUT ;
    USE SIGNAL ;
    PORT
      LAYER M4 ;
        RECT  97.116 25.104 97.2 25.128 ;
    END
  END sink_data[4]
  PIN sink_data[50]
    DIRECTION OUTPUT ;
    USE SIGNAL ;
    PORT
      LAYER M4 ;
        RECT  97.116 42.576 97.2 42.6 ;
    END
  END sink_data[50]
  PIN sink_data[51]
    DIRECTION OUTPUT ;
    USE SIGNAL ;
    PORT
      LAYER M4 ;
        RECT  97.116 42.672 97.2 42.696 ;
    END
  END sink_data[51]
  PIN sink_data[52]
    DIRECTION OUTPUT ;
    USE SIGNAL ;
    PORT
      LAYER M4 ;
        RECT  97.116 42.768 97.2 42.792 ;
    END
  END sink_data[52]
  PIN sink_data[53]
    DIRECTION OUTPUT ;
    USE SIGNAL ;
    PORT
      LAYER M4 ;
        RECT  97.116 42.864 97.2 42.888 ;
    END
  END sink_data[53]
  PIN sink_data[54]
    DIRECTION OUTPUT ;
    USE SIGNAL ;
    PORT
      LAYER M4 ;
        RECT  97.116 42.96 97.2 42.984 ;
    END
  END sink_data[54]
  PIN sink_data[55]
    DIRECTION OUTPUT ;
    USE SIGNAL ;
    PORT
      LAYER M4 ;
        RECT  97.116 43.056 97.2 43.08 ;
    END
  END sink_data[55]
  PIN sink_data[56]
    DIRECTION OUTPUT ;
    USE SIGNAL ;
    PORT
      LAYER M4 ;
        RECT  97.116 43.152 97.2 43.176 ;
    END
  END sink_data[56]
  PIN sink_data[57]
    DIRECTION OUTPUT ;
    USE SIGNAL ;
    PORT
      LAYER M4 ;
        RECT  97.116 43.248 97.2 43.272 ;
    END
  END sink_data[57]
  PIN sink_data[58]
    DIRECTION OUTPUT ;
    USE SIGNAL ;
    PORT
      LAYER M4 ;
        RECT  97.116 43.344 97.2 43.368 ;
    END
  END sink_data[58]
  PIN sink_data[59]
    DIRECTION OUTPUT ;
    USE SIGNAL ;
    PORT
      LAYER M4 ;
        RECT  97.116 43.44 97.2 43.464 ;
    END
  END sink_data[59]
  PIN sink_data[5]
    DIRECTION OUTPUT ;
    USE SIGNAL ;
    PORT
      LAYER M4 ;
        RECT  97.116 25.2 97.2 25.224 ;
    END
  END sink_data[5]
  PIN sink_data[60]
    DIRECTION OUTPUT ;
    USE SIGNAL ;
    PORT
      LAYER M4 ;
        RECT  97.116 43.536 97.2 43.56 ;
    END
  END sink_data[60]
  PIN sink_data[61]
    DIRECTION OUTPUT ;
    USE SIGNAL ;
    PORT
      LAYER M4 ;
        RECT  97.116 43.632 97.2 43.656 ;
    END
  END sink_data[61]
  PIN sink_data[62]
    DIRECTION OUTPUT ;
    USE SIGNAL ;
    PORT
      LAYER M4 ;
        RECT  97.116 43.728 97.2 43.752 ;
    END
  END sink_data[62]
  PIN sink_data[63]
    DIRECTION OUTPUT ;
    USE SIGNAL ;
    PORT
      LAYER M4 ;
        RECT  97.116 43.824 97.2 43.848 ;
    END
  END sink_data[63]
  PIN sink_data[64]
    DIRECTION OUTPUT ;
    USE SIGNAL ;
    PORT
      LAYER M4 ;
        RECT  97.116 43.92 97.2 43.944 ;
    END
  END sink_data[64]
  PIN sink_data[65]
    DIRECTION OUTPUT ;
    USE SIGNAL ;
    PORT
      LAYER M4 ;
        RECT  97.116 44.016 97.2 44.04 ;
    END
  END sink_data[65]
  PIN sink_data[66]
    DIRECTION OUTPUT ;
    USE SIGNAL ;
    PORT
      LAYER M4 ;
        RECT  97.116 44.112 97.2 44.136 ;
    END
  END sink_data[66]
  PIN sink_data[67]
    DIRECTION OUTPUT ;
    USE SIGNAL ;
    PORT
      LAYER M4 ;
        RECT  97.116 44.208 97.2 44.232 ;
    END
  END sink_data[67]
  PIN sink_data[68]
    DIRECTION OUTPUT ;
    USE SIGNAL ;
    PORT
      LAYER M4 ;
        RECT  97.116 44.304 97.2 44.328 ;
    END
  END sink_data[68]
  PIN sink_data[69]
    DIRECTION OUTPUT ;
    USE SIGNAL ;
    PORT
      LAYER M4 ;
        RECT  97.116 44.4 97.2 44.424 ;
    END
  END sink_data[69]
  PIN sink_data[6]
    DIRECTION OUTPUT ;
    USE SIGNAL ;
    PORT
      LAYER M4 ;
        RECT  97.116 25.296 97.2 25.32 ;
    END
  END sink_data[6]
  PIN sink_data[70]
    DIRECTION OUTPUT ;
    USE SIGNAL ;
    PORT
      LAYER M4 ;
        RECT  97.116 44.496 97.2 44.52 ;
    END
  END sink_data[70]
  PIN sink_data[71]
    DIRECTION OUTPUT ;
    USE SIGNAL ;
    PORT
      LAYER M4 ;
        RECT  97.116 44.592 97.2 44.616 ;
    END
  END sink_data[71]
  PIN sink_data[72]
    DIRECTION OUTPUT ;
    USE SIGNAL ;
    PORT
      LAYER M4 ;
        RECT  97.116 44.688 97.2 44.712 ;
    END
  END sink_data[72]
  PIN sink_data[73]
    DIRECTION OUTPUT ;
    USE SIGNAL ;
    PORT
      LAYER M4 ;
        RECT  97.116 44.784 97.2 44.808 ;
    END
  END sink_data[73]
  PIN sink_data[74]
    DIRECTION OUTPUT ;
    USE SIGNAL ;
    PORT
      LAYER M4 ;
        RECT  97.116 44.88 97.2 44.904 ;
    END
  END sink_data[74]
  PIN sink_data[75]
    DIRECTION OUTPUT ;
    USE SIGNAL ;
    PORT
      LAYER M4 ;
        RECT  97.116 44.976 97.2 45 ;
    END
  END sink_data[75]
  PIN sink_data[76]
    DIRECTION OUTPUT ;
    USE SIGNAL ;
    PORT
      LAYER M4 ;
        RECT  97.116 45.072 97.2 45.096 ;
    END
  END sink_data[76]
  PIN sink_data[77]
    DIRECTION OUTPUT ;
    USE SIGNAL ;
    PORT
      LAYER M4 ;
        RECT  97.116 45.168 97.2 45.192 ;
    END
  END sink_data[77]
  PIN sink_data[78]
    DIRECTION OUTPUT ;
    USE SIGNAL ;
    PORT
      LAYER M4 ;
        RECT  97.116 52.848 97.2 52.872 ;
    END
  END sink_data[78]
  PIN sink_data[79]
    DIRECTION OUTPUT ;
    USE SIGNAL ;
    PORT
      LAYER M4 ;
        RECT  97.116 52.944 97.2 52.968 ;
    END
  END sink_data[79]
  PIN sink_data[7]
    DIRECTION OUTPUT ;
    USE SIGNAL ;
    PORT
      LAYER M4 ;
        RECT  97.116 25.392 97.2 25.416 ;
    END
  END sink_data[7]
  PIN sink_data[80]
    DIRECTION OUTPUT ;
    USE SIGNAL ;
    PORT
      LAYER M4 ;
        RECT  97.116 53.04 97.2 53.064 ;
    END
  END sink_data[80]
  PIN sink_data[81]
    DIRECTION OUTPUT ;
    USE SIGNAL ;
    PORT
      LAYER M4 ;
        RECT  97.116 53.136 97.2 53.16 ;
    END
  END sink_data[81]
  PIN sink_data[82]
    DIRECTION OUTPUT ;
    USE SIGNAL ;
    PORT
      LAYER M4 ;
        RECT  97.116 53.232 97.2 53.256 ;
    END
  END sink_data[82]
  PIN sink_data[83]
    DIRECTION OUTPUT ;
    USE SIGNAL ;
    PORT
      LAYER M4 ;
        RECT  97.116 53.328 97.2 53.352 ;
    END
  END sink_data[83]
  PIN sink_data[84]
    DIRECTION OUTPUT ;
    USE SIGNAL ;
    PORT
      LAYER M4 ;
        RECT  97.116 53.424 97.2 53.448 ;
    END
  END sink_data[84]
  PIN sink_data[85]
    DIRECTION OUTPUT ;
    USE SIGNAL ;
    PORT
      LAYER M4 ;
        RECT  97.116 53.52 97.2 53.544 ;
    END
  END sink_data[85]
  PIN sink_data[86]
    DIRECTION OUTPUT ;
    USE SIGNAL ;
    PORT
      LAYER M4 ;
        RECT  97.116 53.616 97.2 53.64 ;
    END
  END sink_data[86]
  PIN sink_data[87]
    DIRECTION OUTPUT ;
    USE SIGNAL ;
    PORT
      LAYER M4 ;
        RECT  97.116 53.712 97.2 53.736 ;
    END
  END sink_data[87]
  PIN sink_data[88]
    DIRECTION OUTPUT ;
    USE SIGNAL ;
    PORT
      LAYER M4 ;
        RECT  97.116 53.808 97.2 53.832 ;
    END
  END sink_data[88]
  PIN sink_data[89]
    DIRECTION OUTPUT ;
    USE SIGNAL ;
    PORT
      LAYER M4 ;
        RECT  97.116 53.904 97.2 53.928 ;
    END
  END sink_data[89]
  PIN sink_data[8]
    DIRECTION OUTPUT ;
    USE SIGNAL ;
    PORT
      LAYER M4 ;
        RECT  97.116 25.488 97.2 25.512 ;
    END
  END sink_data[8]
  PIN sink_data[90]
    DIRECTION OUTPUT ;
    USE SIGNAL ;
    PORT
      LAYER M4 ;
        RECT  97.116 54 97.2 54.024 ;
    END
  END sink_data[90]
  PIN sink_data[91]
    DIRECTION OUTPUT ;
    USE SIGNAL ;
    PORT
      LAYER M4 ;
        RECT  97.116 54.096 97.2 54.12 ;
    END
  END sink_data[91]
  PIN sink_data[92]
    DIRECTION OUTPUT ;
    USE SIGNAL ;
    PORT
      LAYER M4 ;
        RECT  97.116 54.192 97.2 54.216 ;
    END
  END sink_data[92]
  PIN sink_data[93]
    DIRECTION OUTPUT ;
    USE SIGNAL ;
    PORT
      LAYER M4 ;
        RECT  97.116 54.288 97.2 54.312 ;
    END
  END sink_data[93]
  PIN sink_data[94]
    DIRECTION OUTPUT ;
    USE SIGNAL ;
    PORT
      LAYER M4 ;
        RECT  97.116 54.384 97.2 54.408 ;
    END
  END sink_data[94]
  PIN sink_data[95]
    DIRECTION OUTPUT ;
    USE SIGNAL ;
    PORT
      LAYER M4 ;
        RECT  97.116 54.48 97.2 54.504 ;
    END
  END sink_data[95]
  PIN sink_data[96]
    DIRECTION OUTPUT ;
    USE SIGNAL ;
    PORT
      LAYER M4 ;
        RECT  97.116 54.576 97.2 54.6 ;
    END
  END sink_data[96]
  PIN sink_data[97]
    DIRECTION OUTPUT ;
    USE SIGNAL ;
    PORT
      LAYER M4 ;
        RECT  97.116 54.672 97.2 54.696 ;
    END
  END sink_data[97]
  PIN sink_data[98]
    DIRECTION OUTPUT ;
    USE SIGNAL ;
    PORT
      LAYER M4 ;
        RECT  97.116 54.768 97.2 54.792 ;
    END
  END sink_data[98]
  PIN sink_data[99]
    DIRECTION OUTPUT ;
    USE SIGNAL ;
    PORT
      LAYER M4 ;
        RECT  97.116 54.864 97.2 54.888 ;
    END
  END sink_data[99]
  PIN sink_data[9]
    DIRECTION OUTPUT ;
    USE SIGNAL ;
    PORT
      LAYER M4 ;
        RECT  97.116 25.584 97.2 25.608 ;
    END
  END sink_data[9]
  PIN sink_seal[0]
    DIRECTION OUTPUT ;
    USE SIGNAL ;
    PORT
      LAYER M4 ;
        RECT  97.116 84.624 97.2 84.648 ;
    END
  END sink_seal[0]
  PIN sink_seal[1]
    DIRECTION OUTPUT ;
    USE SIGNAL ;
    PORT
      LAYER M4 ;
        RECT  97.116 84.72 97.2 84.744 ;
    END
  END sink_seal[1]
  PIN sink_seal[2]
    DIRECTION OUTPUT ;
    USE SIGNAL ;
    PORT
      LAYER M4 ;
        RECT  97.116 84.816 97.2 84.84 ;
    END
  END sink_seal[2]
  PIN sink_seal[3]
    DIRECTION OUTPUT ;
    USE SIGNAL ;
    PORT
      LAYER M4 ;
        RECT  97.116 84.912 97.2 84.936 ;
    END
  END sink_seal[3]
  PIN sink_seal[4]
    DIRECTION OUTPUT ;
    USE SIGNAL ;
    PORT
      LAYER M4 ;
        RECT  97.116 85.008 97.2 85.032 ;
    END
  END sink_seal[4]
  PIN sink_we[0]
    DIRECTION OUTPUT ;
    USE SIGNAL ;
    PORT
      LAYER M4 ;
        RECT  97.116 85.104 97.2 85.128 ;
    END
  END sink_we[0]
  PIN sink_we[1]
    DIRECTION OUTPUT ;
    USE SIGNAL ;
    PORT
      LAYER M4 ;
        RECT  97.116 85.2 97.2 85.224 ;
    END
  END sink_we[1]
  PIN sink_we[2]
    DIRECTION OUTPUT ;
    USE SIGNAL ;
    PORT
      LAYER M4 ;
        RECT  97.116 85.296 97.2 85.32 ;
    END
  END sink_we[2]
  PIN sink_we[3]
    DIRECTION OUTPUT ;
    USE SIGNAL ;
    PORT
      LAYER M4 ;
        RECT  97.116 85.392 97.2 85.416 ;
    END
  END sink_we[3]
  PIN sink_we[4]
    DIRECTION OUTPUT ;
    USE SIGNAL ;
    PORT
      LAYER M4 ;
        RECT  97.116 85.488 97.2 85.512 ;
    END
  END sink_we[4]
  PIN upstream_fault
    DIRECTION INPUT ;
    USE SIGNAL ;
    PORT
      LAYER M5 ;
        RECT  10.128 0 10.152 0.084 ;
    END
  END upstream_fault
  PIN upstream_quiet
    DIRECTION INPUT ;
    USE SIGNAL ;
    PORT
      LAYER M5 ;
        RECT  10.224 0 10.248 0.084 ;
    END
  END upstream_quiet
  PIN vgo
    DIRECTION INPUT ;
    USE SIGNAL ;
    PORT
      LAYER M5 ;
        RECT  7.248 97.116 7.272 97.2 ;
    END
  END vgo
  PIN vgo_h
    DIRECTION OUTPUT ;
    USE SIGNAL ;
    PORT
      LAYER M5 ;
        RECT  7.344 97.116 7.368 97.2 ;
    END
  END vgo_h
  PIN VDD
    DIRECTION INOUT ;
    USE POWER ;
    PORT
      LAYER M5 ;
        RECT  94.392 2.151 94.512 95.049 ;
        RECT  88.992 2.151 89.112 95.049 ;
        RECT  83.592 2.151 83.712 95.049 ;
        RECT  78.192 2.151 78.312 95.049 ;
        RECT  72.792 2.151 72.912 95.049 ;
        RECT  67.392 2.151 67.512 95.049 ;
        RECT  61.992 2.151 62.112 95.049 ;
        RECT  56.592 2.151 56.712 95.049 ;
        RECT  51.192 2.151 51.312 95.049 ;
        RECT  45.792 2.151 45.912 95.049 ;
        RECT  40.392 2.151 40.512 95.049 ;
        RECT  34.992 2.151 35.112 95.049 ;
        RECT  29.592 2.151 29.712 95.049 ;
        RECT  24.192 2.151 24.312 95.049 ;
        RECT  18.792 2.151 18.912 95.049 ;
        RECT  13.392 2.151 13.512 95.049 ;
        RECT  7.992 2.151 8.112 95.049 ;
        RECT  2.592 2.151 2.712 95.049 ;
    END
  END VDD
  PIN VSS
    DIRECTION INOUT ;
    USE GROUND ;
    PORT
      LAYER M5 ;
        RECT  94.2 2.137 94.32 95.063 ;
        RECT  88.8 2.137 88.92 95.063 ;
        RECT  83.4 2.137 83.52 95.063 ;
        RECT  78 2.137 78.12 95.063 ;
        RECT  72.6 2.137 72.72 95.063 ;
        RECT  67.2 2.137 67.32 95.063 ;
        RECT  61.8 2.137 61.92 95.063 ;
        RECT  56.4 2.137 56.52 95.063 ;
        RECT  51 2.137 51.12 95.063 ;
        RECT  45.6 2.137 45.72 95.063 ;
        RECT  40.2 2.137 40.32 95.063 ;
        RECT  34.8 2.137 34.92 95.063 ;
        RECT  29.4 2.137 29.52 95.063 ;
        RECT  24 2.137 24.12 95.063 ;
        RECT  18.6 2.137 18.72 95.063 ;
        RECT  13.2 2.137 13.32 95.063 ;
        RECT  7.8 2.137 7.92 95.063 ;
        RECT  2.4 2.137 2.52 95.063 ;
    END
  END VSS
  OBS
    LAYER RVTN ;
     RECT  2.16 2.16 95.04 2.295 ;
     RECT  2.16 2.565 95.04 2.835 ;
     RECT  2.16 3.105 95.04 3.375 ;
     RECT  2.16 3.645 95.04 3.915 ;
     RECT  2.16 4.185 95.04 4.455 ;
     RECT  2.16 4.725 95.04 4.995 ;
     RECT  2.16 5.265 95.04 5.535 ;
     RECT  2.16 5.805 95.04 6.075 ;
     RECT  2.16 6.345 95.04 6.615 ;
     RECT  2.16 6.885 95.04 7.155 ;
     RECT  2.16 7.425 95.04 7.695 ;
     RECT  2.16 7.965 95.04 8.235 ;
     RECT  2.16 8.505 95.04 8.775 ;
     RECT  2.16 9.045 95.04 9.315 ;
     RECT  2.16 9.585 95.04 9.855 ;
     RECT  2.16 10.125 95.04 10.395 ;
     RECT  2.16 10.665 95.04 10.935 ;
     RECT  2.16 11.205 95.04 11.475 ;
     RECT  2.16 11.745 95.04 12.015 ;
     RECT  2.16 12.285 95.04 12.555 ;
     RECT  2.16 12.825 95.04 13.095 ;
     RECT  2.16 13.365 95.04 13.635 ;
     RECT  2.16 13.905 95.04 14.175 ;
     RECT  2.16 14.445 95.04 14.715 ;
     RECT  2.16 14.985 95.04 15.255 ;
     RECT  2.16 15.525 95.04 15.795 ;
     RECT  2.16 16.065 95.04 16.335 ;
     RECT  2.16 16.605 95.04 16.875 ;
     RECT  2.16 17.145 95.04 17.415 ;
     RECT  2.16 17.685 95.04 17.955 ;
     RECT  2.16 18.225 95.04 18.495 ;
     RECT  2.16 18.765 95.04 19.035 ;
     RECT  2.16 19.305 95.04 19.575 ;
     RECT  2.16 19.845 95.04 20.115 ;
     RECT  2.16 20.385 95.04 20.655 ;
     RECT  2.16 20.925 95.04 21.195 ;
     RECT  2.16 21.465 95.04 21.735 ;
     RECT  2.16 22.005 95.04 22.275 ;
     RECT  2.16 22.545 95.04 22.815 ;
     RECT  2.16 23.085 95.04 23.355 ;
     RECT  2.16 23.625 95.04 23.895 ;
     RECT  2.16 24.165 95.04 24.435 ;
     RECT  2.16 24.705 95.04 24.975 ;
     RECT  2.16 25.245 95.04 25.515 ;
     RECT  2.16 25.785 95.04 26.055 ;
     RECT  2.16 26.325 95.04 26.595 ;
     RECT  2.16 26.865 95.04 27.135 ;
     RECT  2.16 27.405 95.04 27.675 ;
     RECT  2.16 27.945 95.04 28.215 ;
     RECT  2.16 28.485 95.04 28.755 ;
     RECT  2.16 29.025 95.04 29.295 ;
     RECT  2.16 29.565 95.04 29.835 ;
     RECT  2.16 30.105 95.04 30.375 ;
     RECT  2.16 30.645 95.04 30.915 ;
     RECT  2.16 31.185 95.04 31.455 ;
     RECT  2.16 31.725 95.04 31.995 ;
     RECT  2.16 32.265 95.04 32.535 ;
     RECT  2.16 32.805 95.04 33.075 ;
     RECT  2.16 33.345 95.04 33.615 ;
     RECT  2.16 33.885 95.04 34.155 ;
     RECT  2.16 34.425 95.04 34.695 ;
     RECT  2.16 34.965 95.04 35.235 ;
     RECT  2.16 35.505 95.04 35.775 ;
     RECT  2.16 36.045 95.04 36.315 ;
     RECT  2.16 36.585 95.04 36.855 ;
     RECT  2.16 37.125 95.04 37.395 ;
     RECT  2.16 37.665 95.04 37.935 ;
     RECT  2.16 38.205 95.04 38.475 ;
     RECT  2.16 38.745 95.04 39.015 ;
     RECT  2.16 39.285 95.04 39.555 ;
     RECT  2.16 39.825 95.04 40.095 ;
     RECT  2.16 40.365 95.04 40.635 ;
     RECT  2.16 40.905 95.04 41.175 ;
     RECT  2.16 41.445 95.04 41.715 ;
     RECT  2.16 41.985 95.04 42.255 ;
     RECT  2.16 42.525 95.04 42.795 ;
     RECT  2.16 43.065 95.04 43.335 ;
     RECT  2.16 43.605 95.04 43.875 ;
     RECT  2.16 44.145 95.04 44.415 ;
     RECT  2.16 44.685 95.04 44.955 ;
     RECT  2.16 45.225 95.04 45.495 ;
     RECT  2.16 45.765 95.04 46.035 ;
     RECT  2.16 46.305 95.04 46.575 ;
     RECT  2.16 46.845 95.04 47.115 ;
     RECT  2.16 47.385 95.04 47.655 ;
     RECT  2.16 47.925 95.04 48.195 ;
     RECT  2.16 48.465 95.04 48.735 ;
     RECT  2.16 49.005 95.04 49.275 ;
     RECT  2.16 49.545 95.04 49.815 ;
     RECT  2.16 50.085 95.04 50.355 ;
     RECT  2.16 50.625 95.04 50.895 ;
     RECT  2.16 51.165 95.04 51.435 ;
     RECT  2.16 51.705 95.04 51.975 ;
     RECT  2.16 52.245 95.04 52.515 ;
     RECT  2.16 52.785 95.04 53.055 ;
     RECT  2.16 53.325 95.04 53.595 ;
     RECT  2.16 53.865 95.04 54.135 ;
     RECT  2.16 54.405 95.04 54.675 ;
     RECT  2.16 54.945 95.04 55.215 ;
     RECT  2.16 55.485 95.04 55.755 ;
     RECT  2.16 56.025 95.04 56.295 ;
     RECT  2.16 56.565 95.04 56.835 ;
     RECT  2.16 57.105 95.04 57.375 ;
     RECT  2.16 57.645 95.04 57.915 ;
     RECT  2.16 58.185 95.04 58.455 ;
     RECT  2.16 58.725 95.04 58.995 ;
     RECT  2.16 59.265 95.04 59.535 ;
     RECT  2.16 59.805 95.04 60.075 ;
     RECT  2.16 60.345 95.04 60.615 ;
     RECT  2.16 60.885 95.04 61.155 ;
     RECT  2.16 61.425 95.04 61.695 ;
     RECT  2.16 61.965 95.04 62.235 ;
     RECT  2.16 62.505 95.04 62.775 ;
     RECT  2.16 63.045 95.04 63.315 ;
     RECT  2.16 63.585 95.04 63.855 ;
     RECT  2.16 64.125 95.04 64.395 ;
     RECT  2.16 64.665 95.04 64.935 ;
     RECT  2.16 65.205 95.04 65.475 ;
     RECT  2.16 65.745 95.04 66.015 ;
     RECT  2.16 66.285 95.04 66.555 ;
     RECT  2.16 66.825 95.04 67.095 ;
     RECT  2.16 67.365 95.04 67.635 ;
     RECT  2.16 67.905 95.04 68.175 ;
     RECT  2.16 68.445 95.04 68.715 ;
     RECT  2.16 68.985 95.04 69.255 ;
     RECT  2.16 69.525 95.04 69.795 ;
     RECT  2.16 70.065 95.04 70.335 ;
     RECT  2.16 70.605 95.04 70.875 ;
     RECT  2.16 71.145 95.04 71.415 ;
     RECT  2.16 71.685 95.04 71.955 ;
     RECT  2.16 72.225 95.04 72.495 ;
     RECT  2.16 72.765 95.04 73.035 ;
     RECT  2.16 73.305 95.04 73.575 ;
     RECT  2.16 73.845 95.04 74.115 ;
     RECT  2.16 74.385 95.04 74.655 ;
     RECT  2.16 74.925 95.04 75.195 ;
     RECT  2.16 75.465 95.04 75.735 ;
     RECT  2.16 76.005 95.04 76.275 ;
     RECT  2.16 76.545 95.04 76.815 ;
     RECT  2.16 77.085 95.04 77.355 ;
     RECT  2.16 77.625 95.04 77.895 ;
     RECT  2.16 78.165 95.04 78.435 ;
     RECT  2.16 78.705 95.04 78.975 ;
     RECT  2.16 79.245 95.04 79.515 ;
     RECT  2.16 79.785 95.04 80.055 ;
     RECT  2.16 80.325 95.04 80.595 ;
     RECT  2.16 80.865 95.04 81.135 ;
     RECT  2.16 81.405 95.04 81.675 ;
     RECT  2.16 81.945 95.04 82.215 ;
     RECT  2.16 82.485 95.04 82.755 ;
     RECT  2.16 83.025 95.04 83.295 ;
     RECT  2.16 83.565 95.04 83.835 ;
     RECT  2.16 84.105 95.04 84.375 ;
     RECT  2.16 84.645 95.04 84.915 ;
     RECT  2.16 85.185 95.04 85.455 ;
     RECT  2.16 85.725 95.04 85.995 ;
     RECT  2.16 86.265 95.04 86.535 ;
     RECT  2.16 86.805 95.04 87.075 ;
     RECT  2.16 87.345 95.04 87.615 ;
     RECT  2.16 87.885 95.04 88.155 ;
     RECT  2.16 88.425 95.04 88.695 ;
     RECT  2.16 88.965 95.04 89.235 ;
     RECT  2.16 89.505 95.04 89.775 ;
     RECT  2.16 90.045 95.04 90.315 ;
     RECT  2.16 90.585 95.04 90.855 ;
     RECT  2.16 91.125 95.04 91.395 ;
     RECT  2.16 91.665 95.04 91.935 ;
     RECT  2.16 92.205 95.04 92.475 ;
     RECT  2.16 92.745 95.04 93.015 ;
     RECT  2.16 93.285 95.04 93.555 ;
     RECT  2.16 93.825 95.04 94.095 ;
     RECT  2.16 94.365 95.04 94.635 ;
     RECT  2.16 94.905 95.04 95.04 ;
    LAYER RVTP ;
     RECT  2.16 2.295 95.04 2.565 ;
     RECT  2.16 2.835 95.04 3.105 ;
     RECT  2.16 3.375 95.04 3.645 ;
     RECT  2.16 3.915 95.04 4.185 ;
     RECT  2.16 4.455 95.04 4.725 ;
     RECT  2.16 4.995 95.04 5.265 ;
     RECT  2.16 5.535 95.04 5.805 ;
     RECT  2.16 6.075 95.04 6.345 ;
     RECT  2.16 6.615 95.04 6.885 ;
     RECT  2.16 7.155 95.04 7.425 ;
     RECT  2.16 7.695 95.04 7.965 ;
     RECT  2.16 8.235 95.04 8.505 ;
     RECT  2.16 8.775 95.04 9.045 ;
     RECT  2.16 9.315 95.04 9.585 ;
     RECT  2.16 9.855 95.04 10.125 ;
     RECT  2.16 10.395 95.04 10.665 ;
     RECT  2.16 10.935 95.04 11.205 ;
     RECT  2.16 11.475 95.04 11.745 ;
     RECT  2.16 12.015 95.04 12.285 ;
     RECT  2.16 12.555 95.04 12.825 ;
     RECT  2.16 13.095 95.04 13.365 ;
     RECT  2.16 13.635 95.04 13.905 ;
     RECT  2.16 14.175 95.04 14.445 ;
     RECT  2.16 14.715 95.04 14.985 ;
     RECT  2.16 15.255 95.04 15.525 ;
     RECT  2.16 15.795 95.04 16.065 ;
     RECT  2.16 16.335 95.04 16.605 ;
     RECT  2.16 16.875 95.04 17.145 ;
     RECT  2.16 17.415 95.04 17.685 ;
     RECT  2.16 17.955 95.04 18.225 ;
     RECT  2.16 18.495 95.04 18.765 ;
     RECT  2.16 19.035 95.04 19.305 ;
     RECT  2.16 19.575 95.04 19.845 ;
     RECT  2.16 20.115 95.04 20.385 ;
     RECT  2.16 20.655 95.04 20.925 ;
     RECT  2.16 21.195 95.04 21.465 ;
     RECT  2.16 21.735 95.04 22.005 ;
     RECT  2.16 22.275 95.04 22.545 ;
     RECT  2.16 22.815 95.04 23.085 ;
     RECT  2.16 23.355 95.04 23.625 ;
     RECT  2.16 23.895 95.04 24.165 ;
     RECT  2.16 24.435 95.04 24.705 ;
     RECT  2.16 24.975 95.04 25.245 ;
     RECT  2.16 25.515 95.04 25.785 ;
     RECT  2.16 26.055 95.04 26.325 ;
     RECT  2.16 26.595 95.04 26.865 ;
     RECT  2.16 27.135 95.04 27.405 ;
     RECT  2.16 27.675 95.04 27.945 ;
     RECT  2.16 28.215 95.04 28.485 ;
     RECT  2.16 28.755 95.04 29.025 ;
     RECT  2.16 29.295 95.04 29.565 ;
     RECT  2.16 29.835 95.04 30.105 ;
     RECT  2.16 30.375 95.04 30.645 ;
     RECT  2.16 30.915 95.04 31.185 ;
     RECT  2.16 31.455 95.04 31.725 ;
     RECT  2.16 31.995 95.04 32.265 ;
     RECT  2.16 32.535 95.04 32.805 ;
     RECT  2.16 33.075 95.04 33.345 ;
     RECT  2.16 33.615 95.04 33.885 ;
     RECT  2.16 34.155 95.04 34.425 ;
     RECT  2.16 34.695 95.04 34.965 ;
     RECT  2.16 35.235 95.04 35.505 ;
     RECT  2.16 35.775 95.04 36.045 ;
     RECT  2.16 36.315 95.04 36.585 ;
     RECT  2.16 36.855 95.04 37.125 ;
     RECT  2.16 37.395 95.04 37.665 ;
     RECT  2.16 37.935 95.04 38.205 ;
     RECT  2.16 38.475 95.04 38.745 ;
     RECT  2.16 39.015 95.04 39.285 ;
     RECT  2.16 39.555 95.04 39.825 ;
     RECT  2.16 40.095 95.04 40.365 ;
     RECT  2.16 40.635 95.04 40.905 ;
     RECT  2.16 41.175 95.04 41.445 ;
     RECT  2.16 41.715 95.04 41.985 ;
     RECT  2.16 42.255 95.04 42.525 ;
     RECT  2.16 42.795 95.04 43.065 ;
     RECT  2.16 43.335 95.04 43.605 ;
     RECT  2.16 43.875 95.04 44.145 ;
     RECT  2.16 44.415 95.04 44.685 ;
     RECT  2.16 44.955 95.04 45.225 ;
     RECT  2.16 45.495 95.04 45.765 ;
     RECT  2.16 46.035 95.04 46.305 ;
     RECT  2.16 46.575 95.04 46.845 ;
     RECT  2.16 47.115 95.04 47.385 ;
     RECT  2.16 47.655 95.04 47.925 ;
     RECT  2.16 48.195 95.04 48.465 ;
     RECT  2.16 48.735 95.04 49.005 ;
     RECT  2.16 49.275 95.04 49.545 ;
     RECT  2.16 49.815 95.04 50.085 ;
     RECT  2.16 50.355 95.04 50.625 ;
     RECT  2.16 50.895 95.04 51.165 ;
     RECT  2.16 51.435 95.04 51.705 ;
     RECT  2.16 51.975 95.04 52.245 ;
     RECT  2.16 52.515 95.04 52.785 ;
     RECT  2.16 53.055 95.04 53.325 ;
     RECT  2.16 53.595 95.04 53.865 ;
     RECT  2.16 54.135 95.04 54.405 ;
     RECT  2.16 54.675 95.04 54.945 ;
     RECT  2.16 55.215 95.04 55.485 ;
     RECT  2.16 55.755 95.04 56.025 ;
     RECT  2.16 56.295 95.04 56.565 ;
     RECT  2.16 56.835 95.04 57.105 ;
     RECT  2.16 57.375 95.04 57.645 ;
     RECT  2.16 57.915 95.04 58.185 ;
     RECT  2.16 58.455 95.04 58.725 ;
     RECT  2.16 58.995 95.04 59.265 ;
     RECT  2.16 59.535 95.04 59.805 ;
     RECT  2.16 60.075 95.04 60.345 ;
     RECT  2.16 60.615 95.04 60.885 ;
     RECT  2.16 61.155 95.04 61.425 ;
     RECT  2.16 61.695 95.04 61.965 ;
     RECT  2.16 62.235 95.04 62.505 ;
     RECT  2.16 62.775 95.04 63.045 ;
     RECT  2.16 63.315 95.04 63.585 ;
     RECT  2.16 63.855 95.04 64.125 ;
     RECT  2.16 64.395 95.04 64.665 ;
     RECT  2.16 64.935 95.04 65.205 ;
     RECT  2.16 65.475 95.04 65.745 ;
     RECT  2.16 66.015 95.04 66.285 ;
     RECT  2.16 66.555 95.04 66.825 ;
     RECT  2.16 67.095 95.04 67.365 ;
     RECT  2.16 67.635 95.04 67.905 ;
     RECT  2.16 68.175 95.04 68.445 ;
     RECT  2.16 68.715 95.04 68.985 ;
     RECT  2.16 69.255 95.04 69.525 ;
     RECT  2.16 69.795 95.04 70.065 ;
     RECT  2.16 70.335 95.04 70.605 ;
     RECT  2.16 70.875 95.04 71.145 ;
     RECT  2.16 71.415 95.04 71.685 ;
     RECT  2.16 71.955 95.04 72.225 ;
     RECT  2.16 72.495 95.04 72.765 ;
     RECT  2.16 73.035 95.04 73.305 ;
     RECT  2.16 73.575 95.04 73.845 ;
     RECT  2.16 74.115 95.04 74.385 ;
     RECT  2.16 74.655 95.04 74.925 ;
     RECT  2.16 75.195 95.04 75.465 ;
     RECT  2.16 75.735 95.04 76.005 ;
     RECT  2.16 76.275 95.04 76.545 ;
     RECT  2.16 76.815 95.04 77.085 ;
     RECT  2.16 77.355 95.04 77.625 ;
     RECT  2.16 77.895 95.04 78.165 ;
     RECT  2.16 78.435 95.04 78.705 ;
     RECT  2.16 78.975 95.04 79.245 ;
     RECT  2.16 79.515 95.04 79.785 ;
     RECT  2.16 80.055 95.04 80.325 ;
     RECT  2.16 80.595 95.04 80.865 ;
     RECT  2.16 81.135 95.04 81.405 ;
     RECT  2.16 81.675 95.04 81.945 ;
     RECT  2.16 82.215 95.04 82.485 ;
     RECT  2.16 82.755 95.04 83.025 ;
     RECT  2.16 83.295 95.04 83.565 ;
     RECT  2.16 83.835 95.04 84.105 ;
     RECT  2.16 84.375 95.04 84.645 ;
     RECT  2.16 84.915 95.04 85.185 ;
     RECT  2.16 85.455 95.04 85.725 ;
     RECT  2.16 85.995 95.04 86.265 ;
     RECT  2.16 86.535 95.04 86.805 ;
     RECT  2.16 87.075 95.04 87.345 ;
     RECT  2.16 87.615 95.04 87.885 ;
     RECT  2.16 88.155 95.04 88.425 ;
     RECT  2.16 88.695 95.04 88.965 ;
     RECT  2.16 89.235 95.04 89.505 ;
     RECT  2.16 89.775 95.04 90.045 ;
     RECT  2.16 90.315 95.04 90.585 ;
     RECT  2.16 90.855 95.04 91.125 ;
     RECT  2.16 91.395 95.04 91.665 ;
     RECT  2.16 91.935 95.04 92.205 ;
     RECT  2.16 92.475 95.04 92.745 ;
     RECT  2.16 93.015 95.04 93.285 ;
     RECT  2.16 93.555 95.04 93.825 ;
     RECT  2.16 94.095 95.04 94.365 ;
     RECT  2.16 94.635 95.04 94.905 ;
    LAYER M1 ;
     RECT  2.16 2.151 95.04 95.049 ;
    LAYER M2 ;
     RECT  0.031 16.236 0.067 16.254 ;
     RECT  0.031 30.186 0.067 30.204 ;
     RECT  0.031 35.316 0.067 35.334 ;
     RECT  0.067 8.856 0.103 8.874 ;
     RECT  0.067 16.236 0.103 16.398 ;
     RECT  0.031 68.571 0.103 69.084 ;
     RECT  0.067 71.928 0.103 71.946 ;
     RECT  0.031 41.076 0.131 41.094 ;
     RECT  0.031 50.751 0.131 50.769 ;
     RECT  0.031 72.81 0.131 72.909 ;
     RECT  0.103 15.336 0.139 15.354 ;
     RECT  0.103 16.146 0.139 16.398 ;
     RECT  0.103 38.646 0.139 38.664 ;
     RECT  0.031 62.784 0.139 62.802 ;
     RECT  0.103 75.708 0.139 75.798 ;
     RECT  0.103 84.924 0.139 84.942 ;
     RECT  0.067 30.006 0.167 30.204 ;
     RECT  0.067 46.701 0.167 46.719 ;
     RECT  0.103 71.226 0.167 71.946 ;
     RECT  0.139 22.212 0.175 22.23 ;
     RECT  0.103 67.266 0.175 67.284 ;
     RECT  0.103 74.556 0.175 74.574 ;
     RECT  0.139 75.708 0.175 76.5 ;
     RECT  0.139 84.456 0.175 84.942 ;
     RECT  0.139 15.336 0.203 16.398 ;
     RECT  0.103 65.916 0.203 66.006 ;
     RECT  0.175 21.816 0.211 22.23 ;
     RECT  0.103 32.931 0.211 32.949 ;
     RECT  0.175 74.556 0.211 74.646 ;
     RECT  0.175 75.636 0.211 76.5 ;
     RECT  0.067 23.364 0.239 23.382 ;
     RECT  0.175 67.266 0.239 67.32 ;
     RECT  0.103 68.148 0.239 69.282 ;
     RECT  0.167 71.226 0.239 71.784 ;
     RECT  0.211 14.841 0.247 14.859 ;
     RECT  0.211 21.438 0.275 22.23 ;
     RECT  0.167 30.186 0.283 30.204 ;
     RECT  0.247 14.148 0.311 14.859 ;
     RECT  0.103 18.81 0.311 18.828 ;
     RECT  0.275 21.438 0.311 21.456 ;
     RECT  0.211 32.931 0.311 33.03 ;
     RECT  0.139 62.712 0.311 62.802 ;
     RECT  0.211 75.636 0.311 76.77 ;
     RECT  0.283 30.186 0.347 30.87 ;
     RECT  0.311 62.712 0.347 62.73 ;
     RECT  0.139 42.498 0.355 42.516 ;
     RECT  0.139 78.174 0.355 78.192 ;
     RECT  0.347 30.852 0.383 30.87 ;
     RECT  0.067 73.782 0.391 73.8 ;
     RECT  0.211 74.556 0.391 74.754 ;
     RECT  0.211 81.486 0.391 81.504 ;
     RECT  0.311 75.636 0.419 76.5 ;
     RECT  0.031 28.296 0.427 28.314 ;
     RECT  0.355 77.634 0.427 78.192 ;
     RECT  0.139 79.29 0.427 79.308 ;
     RECT  0.239 68.22 0.455 69.012 ;
     RECT  0.067 12.906 0.463 12.924 ;
     RECT  0.391 69.768 0.491 69.786 ;
     RECT  0.463 12.906 0.499 13.194 ;
     RECT  0.419 75.636 0.527 76.194 ;
     RECT  0.499 11.178 0.535 11.196 ;
     RECT  0.131 72.846 0.535 72.909 ;
     RECT  0.391 73.782 0.535 74.754 ;
     RECT  0.527 75.636 0.535 75.924 ;
     RECT  0.355 42.498 0.607 42.894 ;
     RECT  0.607 42.03 0.707 42.894 ;
     RECT  0.139 38.646 0.859 39.312 ;
     RECT  0.823 33.696 0.931 33.714 ;
     RECT  0.859 45.774 0.931 45.792 ;
     RECT  0.103 18.036 0.967 18.054 ;
     RECT  0.067 60.156 1.003 60.174 ;
     RECT  0.239 71.766 1.039 71.784 ;
     RECT  0.535 72.846 1.039 75.924 ;
     RECT  0.535 10.17 1.075 11.196 ;
     RECT  0.239 67.302 1.075 67.32 ;
     RECT  0.391 81.45 1.075 81.504 ;
     RECT  0.931 45.774 1.111 45.864 ;
     RECT  0.535 46.656 1.111 46.674 ;
     RECT  0.499 50.904 1.111 51.462 ;
     RECT  0.535 52.758 1.111 52.776 ;
     RECT  1.039 71.766 1.139 75.924 ;
     RECT  1.111 50.904 1.211 52.776 ;
     RECT  1.003 60.156 1.435 60.714 ;
     RECT  0.031 61.74 1.435 61.758 ;
     RECT  1.003 57.996 1.471 58.014 ;
     RECT  0.427 27.756 1.507 28.314 ;
     RECT  0.067 35.316 1.543 36.414 ;
     RECT  1.471 57.69 1.543 58.014 ;
     RECT  0.499 44.496 1.651 44.514 ;
     RECT  1.111 45.774 1.651 46.674 ;
     RECT  0.823 43.65 1.687 43.668 ;
     RECT  1.651 44.496 1.687 46.674 ;
     RECT  0.203 65.916 1.687 65.934 ;
     RECT  1.075 10.17 1.723 11.466 ;
     RECT  0.499 12.33 1.723 13.194 ;
     RECT  0.275 22.212 1.723 22.23 ;
     RECT  1.039 59.274 1.975 59.292 ;
     RECT  0.859 6.156 2.16 6.174 ;
     RECT  0.103 8.856 2.16 9.414 ;
     RECT  1.723 10.17 2.16 13.194 ;
     RECT  0.311 14.148 2.16 14.166 ;
     RECT  0.203 16.074 2.16 16.398 ;
     RECT  0.967 17.766 2.16 18.054 ;
     RECT  0.211 19.656 2.16 19.674 ;
     RECT  1.723 21.51 2.16 22.23 ;
     RECT  1.507 27.612 2.16 28.314 ;
     RECT  2.047 29.106 2.16 29.124 ;
     RECT  0.535 30.996 2.16 31.014 ;
     RECT  0.535 32.274 2.16 32.292 ;
     RECT  0.931 33.696 2.16 34.254 ;
     RECT  1.543 35.316 2.16 37.116 ;
     RECT  0.859 38.556 2.16 39.312 ;
     RECT  1.039 41.49 2.16 41.544 ;
     RECT  0.707 42.498 2.16 42.894 ;
     RECT  1.687 43.65 2.16 46.674 ;
     RECT  0.103 48.006 2.16 48.024 ;
     RECT  2.047 49.896 2.16 49.914 ;
     RECT  1.211 50.904 2.16 51.534 ;
     RECT  1.211 52.596 2.16 52.776 ;
     RECT  0.571 54.216 2.16 54.234 ;
     RECT  2.083 56.34 2.16 56.358 ;
     RECT  1.543 57.15 2.16 58.014 ;
     RECT  1.975 59.076 2.16 59.292 ;
     RECT  1.435 60.156 2.16 61.758 ;
     RECT  0.967 62.586 2.16 62.604 ;
     RECT  1.615 63.396 2.16 63.414 ;
     RECT  1.687 65.916 2.16 66.114 ;
     RECT  1.075 67.176 2.16 67.32 ;
     RECT  0.455 68.22 2.16 68.67 ;
     RECT  1.139 71.766 2.16 71.784 ;
     RECT  1.139 72.846 2.16 75.924 ;
     RECT  1.651 76.824 2.16 76.842 ;
     RECT  0.427 77.634 2.16 79.308 ;
     RECT  0.283 80.406 2.16 80.424 ;
     RECT  1.075 81.45 2.16 81.594 ;
     RECT  0.247 82.764 2.16 82.782 ;
     RECT  0.175 83.916 2.16 84.942 ;
     RECT  0.067 85.806 2.16 85.824 ;
     RECT  0.895 89.784 2.16 89.802 ;
     RECT  2.16 2.151 4.675 95.049 ;
     RECT  4.675 2.151 5.351 95.094 ;
     RECT  5.827 1.152 6.331 1.17 ;
     RECT  6.331 1.152 6.431 1.242 ;
     RECT  6.431 1.152 6.647 1.17 ;
     RECT  5.351 2.151 7.627 95.049 ;
     RECT  7.627 2.151 7.871 95.13 ;
     RECT  7.871 2.151 7.987 95.049 ;
     RECT  7.987 1.728 8.735 95.049 ;
     RECT  8.735 2.151 10.579 95.049 ;
     RECT  10.579 2.106 11.399 95.049 ;
     RECT  11.399 2.151 14.863 95.049 ;
     RECT  14.863 2.151 16.439 95.094 ;
     RECT  16.439 2.151 95.04 95.049 ;
     RECT  95.04 8.946 95.171 11.034 ;
     RECT  95.04 66.096 95.171 79.434 ;
     RECT  95.171 8.946 95.207 10.422 ;
     RECT  95.04 12.456 95.243 18.018 ;
     RECT  95.04 37.602 95.243 58.374 ;
     RECT  95.243 40.878 95.747 58.374 ;
     RECT  95.243 37.602 95.783 40.122 ;
     RECT  95.747 40.878 95.783 44.244 ;
     RECT  95.747 45.036 95.783 54.324 ;
     RECT  95.171 66.096 95.783 76.77 ;
     RECT  95.207 9.396 95.891 10.422 ;
     RECT  95.783 37.602 95.927 39.816 ;
     RECT  95.783 41.796 95.963 44.244 ;
     RECT  95.783 66.096 96.035 69.786 ;
     RECT  96.035 66.186 96.107 69.786 ;
     RECT  95.04 23.364 96.143 28.674 ;
     RECT  95.04 84.042 96.251 88.344 ;
     RECT  95.243 12.456 96.287 17.946 ;
     RECT  95.963 41.796 96.287 43.362 ;
     RECT  95.783 70.542 96.287 76.77 ;
     RECT  96.251 85.536 96.287 88.344 ;
     RECT  96.287 12.996 96.323 13.284 ;
     RECT  95.04 18.936 96.323 21.528 ;
     RECT  96.143 23.364 96.323 26.586 ;
     RECT  96.287 41.796 96.323 42.984 ;
     RECT  95.783 48.402 96.323 54.324 ;
     RECT  96.287 72.396 96.323 76.77 ;
     RECT  95.171 77.706 96.323 79.434 ;
     RECT  96.251 84.042 96.323 84.564 ;
     RECT  96.287 85.536 96.323 86.454 ;
     RECT  96.287 14.256 96.359 17.946 ;
     RECT  96.323 19.512 96.359 21.528 ;
     RECT  96.323 41.796 96.359 42.624 ;
     RECT  96.323 48.438 96.359 51.966 ;
     RECT  96.323 53.064 96.359 53.388 ;
     RECT  96.107 66.456 96.359 69.786 ;
     RECT  96.323 73.278 96.359 76.77 ;
     RECT  96.359 14.256 96.395 17.406 ;
     RECT  96.359 20.934 96.395 21.528 ;
     RECT  96.359 48.438 96.395 51.696 ;
     RECT  95.927 38.106 96.431 39.816 ;
     RECT  95.04 81.756 96.431 83.124 ;
     RECT  96.395 48.636 96.467 50.994 ;
     RECT  96.359 66.456 96.467 69.516 ;
     RECT  96.431 81.756 96.467 82.206 ;
     RECT  95.891 9.396 96.539 10.224 ;
     RECT  96.467 66.456 96.539 68.976 ;
     RECT  96.539 66.456 96.611 67.356 ;
     RECT  96.539 68.184 96.647 68.976 ;
     RECT  95.783 45.036 96.827 47.646 ;
     RECT  96.359 75.438 96.827 76.77 ;
     RECT  96.323 77.706 96.827 79.164 ;
     RECT  96.287 87.354 96.827 88.344 ;
     RECT  95.747 55.224 96.835 58.374 ;
     RECT  96.323 85.536 96.863 86.256 ;
     RECT  96.827 87.426 96.899 88.344 ;
     RECT  96.323 13.104 96.935 13.284 ;
     RECT  96.827 75.438 96.935 76.608 ;
     RECT  96.323 25.02 96.971 26.586 ;
     RECT  96.827 45.036 96.971 47.574 ;
     RECT  96.835 54.612 96.971 58.374 ;
     RECT  96.647 68.382 96.971 68.976 ;
     RECT  96.359 73.278 96.971 74.646 ;
     RECT  96.935 75.438 96.971 76.464 ;
     RECT  96.899 87.426 96.971 88.074 ;
     RECT  96.143 27.414 97.007 28.674 ;
     RECT  96.971 46.62 97.007 47.574 ;
     RECT  96.971 56.538 97.007 58.374 ;
     RECT  96.971 74.466 97.007 74.646 ;
     RECT  96.935 13.266 97.043 13.284 ;
     RECT  96.395 14.256 97.043 17.1 ;
     RECT  96.323 23.364 97.043 24.264 ;
     RECT  96.971 25.02 97.043 25.776 ;
     RECT  97.007 27.414 97.043 27.432 ;
     RECT  95.963 44.226 97.043 44.244 ;
     RECT  97.007 46.62 97.043 47.214 ;
     RECT  96.467 49.788 97.043 50.994 ;
     RECT  96.359 53.37 97.043 53.388 ;
     RECT  97.007 58.086 97.043 58.374 ;
     RECT  96.971 75.438 97.043 75.654 ;
     RECT  96.971 87.426 97.043 87.642 ;
     RECT  97.043 23.598 97.051 24.264 ;
     RECT  97.043 25.02 97.051 25.038 ;
     RECT  96.431 39.636 97.051 39.816 ;
     RECT  95.783 40.878 97.051 40.896 ;
     RECT  96.539 9.396 97.079 9.684 ;
     RECT  97.043 14.256 97.079 14.976 ;
     RECT  97.043 16.074 97.079 17.1 ;
     RECT  96.359 19.512 97.079 19.944 ;
     RECT  97.051 23.598 97.079 25.038 ;
     RECT  96.431 38.106 97.079 38.574 ;
     RECT  96.971 45.126 97.079 45.594 ;
     RECT  97.043 46.62 97.079 47.178 ;
     RECT  96.971 54.612 97.079 55.548 ;
     RECT  97.043 58.356 97.079 58.374 ;
     RECT  96.611 66.456 97.079 67.194 ;
     RECT  96.971 73.278 97.079 73.638 ;
     RECT  97.007 74.466 97.079 74.484 ;
     RECT  96.827 77.706 97.079 79.002 ;
     RECT  96.863 86.238 97.079 86.256 ;
     RECT  97.051 39.636 97.087 40.896 ;
     RECT  96.287 70.542 97.087 71.406 ;
     RECT  97.079 9.666 97.115 9.684 ;
     RECT  97.079 14.256 97.115 14.274 ;
     RECT  97.079 16.416 97.115 16.866 ;
     RECT  97.079 19.548 97.115 19.944 ;
     RECT  96.395 20.934 97.115 21.456 ;
     RECT  95.04 22.554 97.115 22.572 ;
     RECT  97.079 24.642 97.115 25.038 ;
     RECT  96.971 26.568 97.115 26.586 ;
     RECT  97.087 39.636 97.115 41.13 ;
     RECT  96.359 42.606 97.115 42.624 ;
     RECT  97.079 45.576 97.115 45.594 ;
     RECT  96.467 48.636 97.115 48.834 ;
     RECT  97.043 50.526 97.115 50.994 ;
     RECT  97.079 54.612 97.115 55.314 ;
     RECT  97.007 56.538 97.115 57.204 ;
     RECT  97.087 70.542 97.115 71.874 ;
     RECT  97.043 75.636 97.115 75.654 ;
     RECT  97.079 77.904 97.115 79.002 ;
     RECT  96.431 83.106 97.115 83.124 ;
     RECT  97.043 87.426 97.115 87.444 ;
     RECT  97.007 28.386 97.151 28.674 ;
     RECT  97.079 38.106 97.151 38.394 ;
     RECT  97.115 40.176 97.151 40.194 ;
     RECT  97.115 50.526 97.151 50.814 ;
     RECT  97.115 24.642 97.187 24.66 ;
     RECT  97.151 28.386 97.187 28.404 ;
     RECT  97.151 38.106 97.187 38.124 ;
     RECT  97.115 41.112 97.187 41.13 ;
     RECT  97.051 43.542 97.187 43.56 ;
     RECT  97.079 47.16 97.187 47.178 ;
     RECT  97.115 48.636 97.187 48.654 ;
     RECT  97.087 52.146 97.187 52.164 ;
     RECT  97.115 54.612 97.187 54.63 ;
     RECT  97.115 57.186 97.187 57.204 ;
     RECT  97.079 66.456 97.187 66.474 ;
     RECT  96.971 68.382 97.187 68.4 ;
     RECT  97.115 70.542 97.187 70.56 ;
     RECT  97.115 71.856 97.187 71.874 ;
     RECT  97.079 73.512 97.187 73.53 ;
     RECT  96.971 76.446 97.187 76.464 ;
     RECT  96.467 81.756 97.187 81.774 ;
     RECT  97.087 83.916 97.187 83.934 ;
    LAYER M3 ;
     RECT  5.364 0.091 5.382 0.139 ;
     RECT  6.552 0.091 6.57 0.139 ;
     RECT  8.208 0.091 8.694 0.139 ;
     RECT  10.404 0.091 10.422 0.139 ;
     RECT  10.26 0.139 10.422 0.235 ;
     RECT  10.26 0.235 10.674 0.523 ;
     RECT  5.148 0.139 5.382 0.571 ;
     RECT  6.336 0.139 6.57 0.571 ;
     RECT  5.148 0.571 6.858 0.619 ;
     RECT  3.744 0.091 4.158 1.723 ;
     RECT  5.148 0.619 6.966 1.723 ;
     RECT  7.992 0.139 8.91 1.723 ;
     RECT  9.792 0.523 10.674 1.723 ;
     RECT  7.992 1.723 10.674 1.771 ;
     RECT  11.412 0.187 11.43 1.771 ;
     RECT  3.744 1.723 7.218 2.143 ;
     RECT  7.956 1.771 11.43 2.143 ;
     RECT  2.415 2.143 2.505 2.191 ;
     RECT  3.744 2.143 11.43 2.191 ;
     RECT  13.215 2.143 13.305 2.191 ;
     RECT  18.615 2.143 18.705 2.191 ;
     RECT  51.015 2.143 51.105 2.191 ;
     RECT  78.015 2.143 78.105 2.191 ;
     RECT  20.736 2.191 20.754 2.227 ;
     RECT  24.015 2.143 24.105 2.227 ;
     RECT  28.224 2.191 28.242 2.227 ;
     RECT  46.8 2.191 46.818 2.227 ;
     RECT  56.415 2.143 56.505 2.227 ;
     RECT  85.644 2.191 85.662 2.227 ;
     RECT  88.815 2.143 88.905 2.227 ;
     RECT  27.684 2.227 28.242 2.251 ;
     RECT  29.415 2.143 29.505 2.251 ;
     RECT  79.488 2.191 79.506 2.251 ;
     RECT  3.744 2.191 11.718 2.263 ;
     RECT  13.215 2.191 14.238 2.263 ;
     RECT  17.46 2.227 17.478 2.263 ;
     RECT  18.216 2.191 18.705 2.263 ;
     RECT  19.728 2.227 19.746 2.263 ;
     RECT  33.624 2.227 33.642 2.263 ;
     RECT  34.815 2.143 34.905 2.263 ;
     RECT  44.352 2.251 44.37 2.263 ;
     RECT  45.615 2.143 45.705 2.263 ;
     RECT  46.8 2.227 46.854 2.263 ;
     RECT  53.028 2.227 53.046 2.263 ;
     RECT  72.615 2.143 72.705 2.263 ;
     RECT  88.815 2.227 89.514 2.263 ;
     RECT  23.436 2.227 24.105 2.293 ;
     RECT  2.415 2.191 2.826 2.299 ;
     RECT  3.744 2.263 14.238 2.299 ;
     RECT  23.184 2.293 24.105 2.299 ;
     RECT  27.684 2.251 29.505 2.299 ;
     RECT  33.624 2.263 34.905 2.299 ;
     RECT  40.215 2.143 40.305 2.299 ;
     RECT  43.74 2.263 44.37 2.299 ;
     RECT  53.028 2.263 53.118 2.299 ;
     RECT  55.872 2.227 57.546 2.299 ;
     RECT  59.94 2.227 59.958 2.299 ;
     RECT  72.144 2.263 72.705 2.299 ;
     RECT  79.02 2.251 79.506 2.299 ;
     RECT  87.264 2.191 87.282 2.299 ;
     RECT  32.292 2.263 32.31 2.335 ;
     RECT  33.156 2.299 34.974 2.335 ;
     RECT  40.176 2.299 40.734 2.335 ;
     RECT  45.36 2.263 46.998 2.335 ;
     RECT  50.832 2.191 51.105 2.335 ;
     RECT  52.704 2.299 53.118 2.335 ;
     RECT  59.688 2.299 60.318 2.335 ;
     RECT  61.815 2.143 61.905 2.335 ;
     RECT  67.215 2.143 67.305 2.335 ;
     RECT  68.256 2.191 68.274 2.335 ;
     RECT  72.072 2.299 72.705 2.335 ;
     RECT  85.284 2.227 85.662 2.335 ;
     RECT  37.548 2.299 37.566 2.347 ;
     RECT  85.032 2.335 85.662 2.347 ;
     RECT  87.264 2.299 87.714 2.347 ;
     RECT  17.46 2.263 19.746 2.371 ;
     RECT  22.248 2.299 24.105 2.371 ;
     RECT  25.092 2.227 25.578 2.371 ;
     RECT  30.276 2.227 30.294 2.371 ;
     RECT  31.248 2.299 31.266 2.371 ;
     RECT  32.292 2.335 32.382 2.371 ;
     RECT  37.548 2.347 37.602 2.371 ;
     RECT  38.772 2.335 38.862 2.371 ;
     RECT  39.744 2.335 40.734 2.371 ;
     RECT  43.416 2.299 44.37 2.371 ;
     RECT  49.284 2.299 49.302 2.371 ;
     RECT  59.436 2.335 61.905 2.371 ;
     RECT  63.684 2.299 63.702 2.371 ;
     RECT  69.048 2.299 69.066 2.371 ;
     RECT  72.072 2.335 73.098 2.371 ;
     RECT  75.528 2.227 75.546 2.371 ;
     RECT  79.02 2.299 80.118 2.371 ;
     RECT  84.348 2.347 85.662 2.371 ;
     RECT  87.264 2.347 87.75 2.371 ;
     RECT  88.815 2.263 89.658 2.371 ;
     RECT  27.252 2.299 29.505 2.413 ;
     RECT  30.276 2.371 32.382 2.413 ;
     RECT  77.904 2.191 78.105 2.413 ;
     RECT  83.415 2.143 83.505 2.413 ;
     RECT  84.348 2.371 86.346 2.413 ;
     RECT  94.215 2.143 94.305 2.413 ;
     RECT  16.92 2.371 19.746 2.443 ;
     RECT  20.736 2.227 20.862 2.443 ;
     RECT  22.248 2.371 26.19 2.461 ;
     RECT  43.416 2.371 44.622 2.461 ;
     RECT  45.36 2.335 47.034 2.461 ;
     RECT  50.832 2.335 51.39 2.461 ;
     RECT  52.704 2.335 53.298 2.461 ;
     RECT  54.216 2.371 54.234 2.461 ;
     RECT  55.296 2.299 57.546 2.461 ;
     RECT  58.464 2.371 62.622 2.461 ;
     RECT  63.432 2.371 63.882 2.461 ;
     RECT  77.904 2.413 78.297 2.461 ;
     RECT  81.576 2.371 81.594 2.461 ;
     RECT  87.264 2.371 89.658 2.461 ;
     RECT  27.252 2.413 32.382 2.491 ;
     RECT  33.156 2.335 35.514 2.491 ;
     RECT  36.252 2.371 36.702 2.491 ;
     RECT  52.704 2.461 64.098 2.491 ;
     RECT  87.264 2.461 90.486 2.491 ;
     RECT  2.415 2.299 14.238 2.497 ;
     RECT  43.416 2.461 47.322 2.497 ;
     RECT  75.06 2.371 75.546 2.497 ;
     RECT  81.576 2.461 82.026 2.497 ;
     RECT  87.192 2.491 90.486 2.497 ;
     RECT  70.632 2.371 70.65 2.533 ;
     RECT  83.415 2.413 86.346 2.533 ;
     RECT  87.192 2.497 91.062 2.533 ;
     RECT  27.252 2.491 36.702 2.569 ;
     RECT  67.215 2.335 68.274 2.569 ;
     RECT  69.048 2.371 69.21 2.569 ;
     RECT  71.964 2.371 73.098 2.569 ;
     RECT  81.504 2.497 82.026 2.569 ;
     RECT  2.415 2.497 14.886 2.582 ;
     RECT  15.948 2.371 15.966 2.582 ;
     RECT  37.548 2.371 38.862 2.582 ;
     RECT  39.744 2.371 41.058 2.582 ;
     RECT  67.215 2.569 69.21 2.587 ;
     RECT  71.964 2.569 73.314 2.587 ;
     RECT  22.248 2.461 26.442 2.605 ;
     RECT  27.252 2.569 36.738 2.605 ;
     RECT  49.284 2.371 49.662 2.605 ;
     RECT  50.832 2.461 51.75 2.605 ;
     RECT  52.524 2.491 64.098 2.605 ;
     RECT  66.096 2.371 66.114 2.605 ;
     RECT  70.488 2.533 70.65 2.605 ;
     RECT  71.892 2.587 73.314 2.605 ;
     RECT  79.02 2.371 80.73 2.605 ;
     RECT  81.504 2.569 82.062 2.605 ;
     RECT  22.248 2.605 36.738 2.635 ;
     RECT  37.548 2.582 41.058 2.635 ;
     RECT  2.415 2.582 15.966 2.641 ;
     RECT  22.248 2.635 41.058 2.641 ;
     RECT  42.084 2.488 42.102 2.641 ;
     RECT  43.236 2.497 47.862 2.641 ;
     RECT  49.284 2.605 49.842 2.641 ;
     RECT  65.232 2.335 65.25 2.641 ;
     RECT  66.06 2.605 66.114 2.641 ;
     RECT  66.96 2.587 69.21 2.641 ;
     RECT  70.2 2.605 70.65 2.641 ;
     RECT  71.532 2.605 73.422 2.641 ;
     RECT  74.988 2.497 75.69 2.641 ;
     RECT  76.5 2.497 76.518 2.641 ;
     RECT  77.472 2.461 78.297 2.641 ;
     RECT  50.796 2.605 64.386 2.725 ;
     RECT  65.232 2.641 70.65 2.725 ;
     RECT  16.92 2.443 21.114 2.731 ;
     RECT  50.796 2.725 70.65 2.731 ;
     RECT  71.532 2.641 73.926 2.731 ;
     RECT  74.988 2.641 78.297 2.731 ;
     RECT  79.02 2.605 82.386 2.731 ;
     RECT  2.415 2.641 16.074 2.758 ;
     RECT  16.812 2.731 21.114 2.758 ;
     RECT  50.796 2.731 73.926 2.767 ;
     RECT  50.58 2.767 73.926 2.803 ;
     RECT  22.248 2.641 49.842 2.827 ;
     RECT  50.58 2.803 73.998 2.827 ;
     RECT  74.988 2.731 82.386 2.827 ;
     RECT  22.248 2.827 82.386 2.875 ;
     RECT  83.124 2.533 91.062 2.875 ;
     RECT  2.415 2.758 21.114 2.911 ;
     RECT  21.852 2.875 91.062 2.911 ;
     RECT  2.415 2.911 91.062 3.173 ;
     RECT  28.188 3.173 91.062 3.415 ;
     RECT  2.415 3.173 27.378 3.649 ;
     RECT  28.188 3.415 91.242 3.721 ;
     RECT  2.34 3.649 27.378 3.919 ;
     RECT  28.188 3.721 91.602 3.919 ;
     RECT  2.34 3.919 91.602 3.965 ;
     RECT  49.212 3.965 91.602 3.983 ;
     RECT  49.212 3.983 91.278 4.691 ;
     RECT  2.34 3.965 48.33 4.801 ;
     RECT  49.212 4.691 49.23 4.801 ;
     RECT  50.184 4.691 91.278 4.891 ;
     RECT  50.184 4.891 91.422 4.955 ;
     RECT  60.516 4.955 91.422 5.027 ;
     RECT  2.34 4.801 49.23 5.701 ;
     RECT  50.22 4.955 59.778 5.701 ;
     RECT  60.588 5.027 91.422 5.701 ;
     RECT  60.588 5.701 92.07 5.741 ;
     RECT  2.34 5.701 59.778 5.995 ;
     RECT  0.864 6.151 0.882 6.379 ;
     RECT  2.34 5.995 59.85 6.845 ;
     RECT  2.34 6.845 48.474 6.917 ;
     RECT  49.212 6.845 59.85 6.961 ;
     RECT  60.66 5.741 92.07 6.961 ;
     RECT  2.376 6.917 48.474 7.675 ;
     RECT  49.212 6.961 92.07 7.675 ;
     RECT  2.376 7.675 92.07 8.267 ;
     RECT  2.415 8.267 92.07 8.435 ;
     RECT  94.215 2.413 94.497 8.671 ;
     RECT  94.215 8.671 94.626 8.815 ;
     RECT  94.068 8.815 94.626 8.851 ;
     RECT  94.068 8.851 94.806 8.941 ;
     RECT  0.072 8.851 0.09 9.019 ;
     RECT  0.864 6.379 1.422 9.067 ;
     RECT  2.415 8.435 85.266 9.067 ;
     RECT  86.184 8.435 92.07 9.085 ;
     RECT  94.068 8.941 95.202 9.085 ;
     RECT  86.184 9.085 92.646 9.121 ;
     RECT  0.864 9.067 85.266 9.211 ;
     RECT  86.184 9.121 93.006 9.211 ;
     RECT  0.864 9.211 93.006 9.239 ;
     RECT  3.852 9.239 93.006 9.355 ;
     RECT  94.032 9.085 95.202 9.355 ;
     RECT  0.036 9.019 0.09 9.391 ;
     RECT  97.056 9.391 97.074 9.661 ;
     RECT  3.852 9.355 95.202 9.751 ;
     RECT  3.852 9.751 95.778 9.851 ;
     RECT  3.996 9.851 95.778 9.895 ;
     RECT  97.056 9.661 97.11 9.895 ;
     RECT  0.036 9.391 0.126 10.165 ;
     RECT  0.864 9.239 2.934 10.165 ;
     RECT  3.996 9.895 97.11 10.253 ;
     RECT  3.996 10.253 97.074 10.445 ;
     RECT  0.036 10.165 2.934 11.011 ;
     RECT  3.996 10.445 96.534 11.011 ;
     RECT  0.036 11.011 96.534 11.501 ;
     RECT  0.036 11.501 96.318 11.789 ;
     RECT  0.036 11.789 94.806 11.939 ;
     RECT  97.092 12.139 97.11 12.235 ;
     RECT  95.688 11.789 96.318 12.331 ;
     RECT  97.056 12.235 97.11 12.331 ;
     RECT  95.688 12.331 97.11 12.523 ;
     RECT  0.036 11.939 94.734 12.749 ;
     RECT  0.036 12.749 94.698 13.531 ;
     RECT  95.652 12.523 97.11 13.829 ;
     RECT  96.948 13.829 97.11 14.279 ;
     RECT  95.652 13.829 95.742 14.369 ;
     RECT  0.036 13.531 94.734 14.405 ;
     RECT  95.724 14.369 95.742 14.477 ;
     RECT  96.948 14.279 97.074 14.981 ;
     RECT  96.948 14.981 97.038 15.061 ;
     RECT  96.336 15.061 97.038 15.223 ;
     RECT  0.036 14.405 94.698 15.295 ;
     RECT  0.036 15.295 94.842 15.533 ;
     RECT  2.376 15.533 94.842 15.601 ;
     RECT  0.036 15.533 1.458 15.629 ;
     RECT  2.376 15.601 94.914 15.719 ;
     RECT  0.036 15.629 1.134 15.725 ;
     RECT  95.76 15.223 97.038 16.069 ;
     RECT  2.415 15.719 94.914 16.141 ;
     RECT  95.76 16.069 97.074 16.141 ;
     RECT  0.036 15.725 0.99 16.259 ;
     RECT  2.415 16.141 97.074 16.411 ;
     RECT  2.415 16.411 97.11 16.973 ;
     RECT  96.264 16.973 97.11 17.453 ;
     RECT  2.415 16.973 95.454 17.879 ;
     RECT  96.264 17.453 97.074 17.933 ;
     RECT  0.072 16.259 0.99 17.995 ;
     RECT  96.3 17.933 97.074 18.571 ;
     RECT  2.415 17.879 40.59 18.697 ;
     RECT  41.328 17.879 95.454 18.697 ;
     RECT  96.3 18.571 97.11 18.859 ;
     RECT  96.264 18.859 97.11 18.959 ;
     RECT  2.415 18.697 95.454 19.003 ;
     RECT  96.264 18.959 96.282 19.003 ;
     RECT  2.415 19.003 96.282 19.229 ;
     RECT  2.415 19.229 95.814 20.011 ;
     RECT  97.02 18.959 97.11 20.011 ;
     RECT  2.415 20.011 97.11 20.093 ;
     RECT  2.415 20.093 96.354 20.429 ;
     RECT  2.415 20.429 95.202 20.461 ;
     RECT  96.3 20.429 96.354 21.115 ;
     RECT  97.092 20.093 97.11 21.115 ;
     RECT  0.072 17.995 1.422 21.163 ;
     RECT  2.304 20.461 95.202 21.355 ;
     RECT  96.3 21.115 97.11 21.355 ;
     RECT  2.304 21.355 97.11 21.461 ;
     RECT  0.072 21.163 1.458 21.505 ;
     RECT  2.304 21.461 95.454 21.505 ;
     RECT  96.336 21.461 97.11 21.773 ;
     RECT  96.372 21.773 97.11 22.157 ;
     RECT  0.072 21.505 95.454 22.199 ;
     RECT  96.912 22.157 97.11 22.577 ;
     RECT  95.436 22.199 95.454 22.987 ;
     RECT  0.072 22.199 94.698 23.021 ;
     RECT  0.072 23.021 85.086 23.117 ;
     RECT  85.86 23.021 94.698 23.161 ;
     RECT  95.436 22.987 95.742 23.161 ;
     RECT  85.86 23.161 95.742 23.179 ;
     RECT  96.912 22.577 97.074 23.179 ;
     RECT  1.404 23.117 85.086 23.213 ;
     RECT  0.072 23.117 0.45 23.387 ;
     RECT  85.86 23.179 97.074 23.755 ;
     RECT  1.44 23.213 85.086 23.863 ;
     RECT  85.86 23.755 97.11 23.863 ;
     RECT  1.44 23.863 97.11 24.637 ;
     RECT  0.108 23.387 0.45 26.621 ;
     RECT  1.44 24.637 97.182 26.825 ;
     RECT  42.444 26.825 97.182 27.293 ;
     RECT  48.456 27.293 97.182 27.599 ;
     RECT  93.096 27.599 94.95 27.671 ;
     RECT  1.44 26.825 41.526 27.679 ;
     RECT  1.44 27.679 41.67 27.751 ;
     RECT  42.444 27.293 47.718 27.751 ;
     RECT  0.432 26.621 0.45 27.779 ;
     RECT  95.688 27.599 97.182 27.779 ;
     RECT  95.688 27.779 95.706 27.869 ;
     RECT  96.912 27.779 97.182 28.013 ;
     RECT  96.984 28.013 97.182 28.049 ;
     RECT  93.132 27.671 94.95 28.139 ;
     RECT  1.44 27.751 47.718 28.183 ;
     RECT  48.456 27.599 92.358 28.183 ;
     RECT  93.132 28.139 94.59 28.211 ;
     RECT  97.128 28.049 97.182 28.409 ;
     RECT  1.44 28.183 92.358 28.411 ;
     RECT  93.132 28.211 94.554 28.411 ;
     RECT  97.128 28.409 97.146 28.679 ;
     RECT  0.036 28.291 0.054 28.747 ;
     RECT  1.44 28.411 94.554 29.065 ;
     RECT  1.44 29.065 94.59 29.219 ;
     RECT  0.036 28.747 0.306 29.563 ;
     RECT  0.036 29.563 0.45 30.209 ;
     RECT  1.44 29.219 94.497 30.283 ;
     RECT  0.072 30.209 0.45 30.991 ;
     RECT  1.404 30.283 94.497 31.189 ;
     RECT  0.072 30.991 0.558 31.435 ;
     RECT  0.072 31.435 0.666 31.565 ;
     RECT  1.404 31.189 94.554 32.071 ;
     RECT  1.404 32.071 94.914 32.261 ;
     RECT  50.04 32.261 94.914 32.297 ;
     RECT  50.076 32.297 94.914 32.333 ;
     RECT  50.076 32.333 94.626 32.477 ;
     RECT  0.072 31.565 0.594 32.525 ;
     RECT  0.072 32.525 0.558 32.717 ;
     RECT  1.404 32.261 49.266 32.765 ;
     RECT  43.92 32.765 49.266 33.277 ;
     RECT  43.92 33.277 49.41 33.313 ;
     RECT  50.184 32.477 94.626 33.313 ;
     RECT  1.404 32.765 43.182 33.655 ;
     RECT  43.92 33.313 94.626 33.655 ;
     RECT  0.072 32.717 0.306 33.691 ;
     RECT  1.404 33.655 94.626 33.691 ;
     RECT  0.072 33.691 94.626 33.809 ;
     RECT  54.504 33.809 94.626 34.231 ;
     RECT  0.072 33.809 53.766 34.771 ;
     RECT  54.504 34.231 94.662 34.771 ;
     RECT  0.072 34.771 94.662 35.041 ;
     RECT  0.072 35.041 94.914 35.231 ;
     RECT  0.072 35.231 94.626 35.311 ;
     RECT  0.036 35.311 94.626 35.339 ;
     RECT  7.815 35.339 94.626 35.969 ;
     RECT  7.815 35.969 94.59 36.211 ;
     RECT  0.036 35.339 7.038 36.283 ;
     RECT  7.776 36.211 94.59 36.283 ;
     RECT  0.036 36.283 94.59 37.201 ;
     RECT  0.036 37.201 94.734 37.373 ;
     RECT  92.34 37.373 94.734 37.975 ;
     RECT  0.036 37.373 91.53 38.003 ;
     RECT  7.452 38.003 91.53 38.107 ;
     RECT  92.34 37.975 94.806 38.107 ;
     RECT  7.452 38.107 94.806 38.129 ;
     RECT  95.904 37.597 95.922 38.173 ;
     RECT  7.524 38.129 94.806 38.281 ;
     RECT  95.904 38.173 96.066 38.281 ;
     RECT  97.164 38.101 97.182 38.371 ;
     RECT  97.128 38.371 97.182 38.551 ;
     RECT  7.524 38.281 96.066 38.713 ;
     RECT  97.056 38.551 97.182 38.713 ;
     RECT  0.036 38.003 6.714 39.091 ;
     RECT  7.524 38.713 97.182 39.091 ;
     RECT  0.036 39.091 97.182 39.119 ;
     RECT  0.036 39.119 56.79 39.865 ;
     RECT  57.708 39.119 97.182 39.865 ;
     RECT  0.036 39.865 97.182 41.099 ;
     RECT  0.072 41.099 97.182 41.135 ;
     RECT  0.072 41.135 97.11 41.165 ;
     RECT  0.072 41.165 96.39 41.357 ;
     RECT  0.072 41.357 96.354 41.453 ;
     RECT  0.072 41.453 95.166 41.549 ;
     RECT  0.072 41.549 94.77 42.029 ;
     RECT  96.228 41.453 96.354 42.475 ;
     RECT  96.012 42.475 96.354 42.571 ;
     RECT  97.092 42.187 97.11 42.629 ;
     RECT  0.072 42.029 94.734 43.051 ;
     RECT  95.472 42.571 96.354 43.051 ;
     RECT  0.072 43.051 96.354 43.528 ;
     RECT  97.092 43.435 97.11 43.528 ;
     RECT  0.072 43.528 97.11 43.537 ;
     RECT  0.072 43.537 97.182 45.959 ;
     RECT  0.072 45.959 95.742 46.571 ;
     RECT  0.072 46.571 95.202 46.679 ;
     RECT  0.072 46.679 94.914 46.732 ;
     RECT  0.108 46.732 94.914 46.829 ;
     RECT  0.18 46.829 94.914 47.039 ;
     RECT  96.804 45.959 97.182 47.183 ;
     RECT  96.804 47.183 97.038 47.219 ;
     RECT  0.18 47.039 94.878 47.309 ;
     RECT  0.18 47.309 94.77 47.489 ;
     RECT  0.18 47.489 94.626 47.579 ;
     RECT  96.804 47.219 97.002 47.579 ;
     RECT  96.804 47.579 96.822 47.651 ;
     RECT  0.18 47.579 92.502 47.851 ;
     RECT  0.108 47.851 92.502 48.029 ;
     RECT  93.924 47.579 94.626 48.235 ;
     RECT  93.924 48.235 94.734 48.271 ;
     RECT  95.76 48.163 95.778 48.271 ;
     RECT  93.924 48.271 95.778 48.397 ;
     RECT  93.456 48.397 96.318 48.433 ;
     RECT  0.36 48.029 92.502 48.541 ;
     RECT  93.456 48.433 96.39 48.541 ;
     RECT  0.36 48.541 96.39 48.763 ;
     RECT  0.144 48.763 96.39 48.811 ;
     RECT  97.164 48.631 97.182 48.811 ;
     RECT  0.144 48.811 97.182 48.941 ;
     RECT  0.576 48.941 97.182 50.107 ;
     RECT  0.036 50.107 97.182 50.774 ;
     RECT  0.108 50.774 97.182 51.665 ;
     RECT  64.368 51.665 97.182 51.917 ;
     RECT  64.368 51.917 95.454 52.013 ;
     RECT  96.3 51.917 97.182 52.169 ;
     RECT  96.3 52.169 97.11 52.205 ;
     RECT  0.108 51.665 63.558 52.483 ;
     RECT  64.368 52.013 94.95 52.483 ;
     RECT  0.108 52.483 94.95 52.493 ;
     RECT  96.3 52.205 97.074 52.843 ;
     RECT  96.264 52.843 97.074 52.861 ;
     RECT  0.144 52.493 94.95 52.889 ;
     RECT  96.228 52.861 97.074 53.035 ;
     RECT  0.144 52.889 60.174 53.117 ;
     RECT  95.724 53.035 97.074 53.131 ;
     RECT  0.18 53.117 60.174 53.405 ;
     RECT  60.948 52.889 94.95 53.699 ;
     RECT  60.948 53.699 94.806 53.789 ;
     RECT  0.54 53.405 60.174 54.031 ;
     RECT  60.948 53.789 94.59 54.031 ;
     RECT  0.54 54.031 94.59 54.139 ;
     RECT  95.724 53.131 97.11 54.607 ;
     RECT  0.144 54.139 94.59 54.763 ;
     RECT  0.108 54.763 94.59 54.905 ;
     RECT  12.816 54.905 94.59 55.021 ;
     RECT  95.724 54.607 97.182 55.243 ;
     RECT  0.108 54.905 12.042 55.277 ;
     RECT  95.688 55.243 97.182 55.339 ;
     RECT  12.816 55.021 94.77 55.525 ;
     RECT  95.652 55.339 97.182 55.531 ;
     RECT  0.828 55.277 12.042 55.957 ;
     RECT  12.816 55.525 94.806 55.957 ;
     RECT  95.616 55.531 97.182 56.939 ;
     RECT  95.652 56.939 97.182 57.209 ;
     RECT  95.652 57.209 97.074 57.299 ;
     RECT  95.724 57.299 97.074 57.479 ;
     RECT  0.828 55.957 94.806 57.569 ;
     RECT  95.724 57.479 95.742 57.569 ;
     RECT  0.828 57.569 94.77 57.749 ;
     RECT  96.804 57.479 97.074 57.839 ;
     RECT  0.828 57.749 94.698 57.875 ;
     RECT  97.02 57.839 97.074 58.109 ;
     RECT  97.056 58.109 97.074 58.379 ;
     RECT  0.828 57.875 94.497 58.649 ;
     RECT  0.828 58.649 8.586 58.685 ;
     RECT  9.36 58.649 94.497 59.099 ;
     RECT  9.504 59.099 94.497 59.189 ;
     RECT  0.828 58.685 8.097 59.611 ;
     RECT  0.828 59.611 8.73 59.881 ;
     RECT  9.504 59.189 58.698 59.881 ;
     RECT  0.828 59.881 58.698 60.241 ;
     RECT  59.508 59.189 94.497 60.241 ;
     RECT  0.828 60.241 94.497 60.889 ;
     RECT  0.828 60.889 94.662 61.349 ;
     RECT  0.072 60.151 0.09 61.723 ;
     RECT  0.828 61.349 94.554 61.723 ;
     RECT  0.072 61.723 94.554 61.735 ;
     RECT  0.036 61.735 94.554 62.699 ;
     RECT  0.036 62.699 94.497 62.807 ;
     RECT  0.072 62.807 94.497 63.661 ;
     RECT  0.072 63.661 94.554 64.049 ;
     RECT  0.072 64.049 94.497 64.867 ;
     RECT  0.072 64.867 94.554 65.201 ;
     RECT  49.968 65.201 94.554 65.273 ;
     RECT  49.968 65.273 94.497 65.705 ;
     RECT  49.968 65.705 92.79 65.741 ;
     RECT  93.564 65.705 94.497 65.741 ;
     RECT  93.636 65.741 94.497 65.813 ;
     RECT  49.968 65.741 92.718 65.939 ;
     RECT  0.072 65.201 49.122 65.983 ;
     RECT  49.968 65.939 52.182 65.983 ;
     RECT  94.068 65.813 94.497 66.055 ;
     RECT  96.012 66.091 96.03 66.181 ;
     RECT  94.068 66.055 94.698 66.253 ;
     RECT  94.068 66.253 94.986 66.523 ;
     RECT  96.012 66.181 96.102 66.523 ;
     RECT  52.956 65.939 92.718 66.631 ;
     RECT  94.068 66.523 96.102 66.631 ;
     RECT  52.956 66.631 96.354 66.721 ;
     RECT  97.164 66.451 97.182 66.721 ;
     RECT  0.072 65.983 52.182 66.865 ;
     RECT  52.956 66.721 97.182 66.865 ;
     RECT  0.072 66.865 97.182 67.949 ;
     RECT  96.084 67.949 97.182 68.141 ;
     RECT  0.072 67.949 95.238 68.243 ;
     RECT  96.336 68.141 97.182 68.405 ;
     RECT  96.336 68.405 97.11 68.429 ;
     RECT  0.072 68.243 53.946 68.566 ;
     RECT  96.336 68.429 97.038 68.621 ;
     RECT  0.036 68.566 53.946 68.989 ;
     RECT  54.72 68.243 95.238 68.989 ;
     RECT  0.036 68.989 95.238 70.027 ;
     RECT  96.336 68.621 96.966 70.027 ;
     RECT  0.036 70.027 96.966 70.315 ;
     RECT  0.036 70.315 97.002 70.411 ;
     RECT  0.036 70.411 97.038 70.507 ;
     RECT  0.036 70.507 97.074 70.537 ;
     RECT  0.036 70.537 97.182 70.829 ;
     RECT  0.036 70.829 95.202 71.213 ;
     RECT  96.3 70.829 97.182 71.357 ;
     RECT  0.036 71.213 94.914 71.597 ;
     RECT  0.036 71.597 94.734 71.609 ;
     RECT  96.3 71.357 96.318 71.659 ;
     RECT  96.264 71.659 96.318 71.755 ;
     RECT  97.092 71.357 97.182 71.879 ;
     RECT  96.228 71.755 96.318 71.887 ;
     RECT  0.036 71.609 94.698 72.427 ;
     RECT  95.796 71.887 96.318 72.427 ;
     RECT  95.724 72.427 96.318 72.811 ;
     RECT  97.092 71.879 97.11 72.811 ;
     RECT  95.724 72.811 97.11 73.387 ;
     RECT  95.652 73.387 97.11 73.507 ;
     RECT  95.652 73.507 97.182 73.867 ;
     RECT  0.036 72.427 94.734 73.885 ;
     RECT  0.036 73.885 94.77 74.309 ;
     RECT  95.58 73.867 97.182 74.347 ;
     RECT  0.036 74.309 94.734 74.621 ;
     RECT  0.036 74.621 94.698 75.775 ;
     RECT  95.472 74.347 97.182 75.775 ;
     RECT  0.036 75.775 97.182 75.929 ;
     RECT  95.688 75.929 97.182 76.469 ;
     RECT  0.036 75.929 94.842 76.651 ;
     RECT  95.688 76.469 97.11 76.651 ;
     RECT  0.036 76.651 97.11 77.081 ;
     RECT  95.688 77.081 97.11 78.629 ;
     RECT  0.036 77.081 94.734 78.935 ;
     RECT  96.012 78.629 97.11 79.007 ;
     RECT  96.012 79.007 96.822 79.079 ;
     RECT  96.3 79.079 96.822 79.169 ;
     RECT  0.036 78.935 94.698 79.205 ;
     RECT  96.3 79.169 96.318 79.439 ;
     RECT  0.036 79.205 94.497 80.093 ;
     RECT  0.072 80.093 94.497 81.751 ;
     RECT  0.072 81.751 94.662 81.985 ;
     RECT  0.072 81.985 94.734 82.021 ;
     RECT  95.76 81.841 95.778 82.111 ;
     RECT  95.76 82.111 95.814 82.147 ;
     RECT  95.76 82.147 95.886 82.183 ;
     RECT  97.164 81.751 97.182 82.183 ;
     RECT  0.072 82.021 94.914 82.715 ;
     RECT  0.072 82.715 11.61 82.787 ;
     RECT  95.76 82.183 97.182 82.925 ;
     RECT  12.384 82.715 94.914 83.021 ;
     RECT  0.072 82.787 11.502 83.129 ;
     RECT  95.796 82.925 97.182 83.309 ;
     RECT  95.832 83.309 97.182 83.597 ;
     RECT  95.832 83.597 96.318 83.789 ;
     RECT  0.072 83.129 11.43 83.875 ;
     RECT  0.072 83.875 11.502 83.911 ;
     RECT  12.384 83.021 94.842 83.911 ;
     RECT  0.072 83.911 94.842 83.939 ;
     RECT  97.092 83.597 97.182 83.939 ;
     RECT  0.9 83.939 94.842 84.139 ;
     RECT  0.9 84.139 95.202 84.371 ;
     RECT  0.072 83.939 0.162 84.479 ;
     RECT  91.98 84.371 95.202 84.613 ;
     RECT  91.98 84.613 95.238 84.653 ;
     RECT  97.092 83.939 97.11 84.715 ;
     RECT  96.228 83.789 96.318 84.811 ;
     RECT  97.056 84.715 97.11 84.811 ;
     RECT  0.072 84.479 0.126 84.947 ;
     RECT  96.228 84.811 97.11 85.109 ;
     RECT  0.9 84.371 91.242 85.261 ;
     RECT  91.98 84.653 95.202 85.261 ;
     RECT  0.072 84.947 0.09 85.829 ;
     RECT  0.9 85.261 95.202 86.333 ;
     RECT  96.264 85.109 97.11 86.765 ;
     RECT  1.98 86.333 95.202 86.801 ;
     RECT  1.98 86.801 94.734 87.149 ;
     RECT  96.804 86.765 97.11 87.377 ;
     RECT  96.876 87.377 97.11 87.449 ;
     RECT  2.412 87.149 94.734 87.575 ;
     RECT  96.876 87.449 97.038 87.647 ;
     RECT  2.412 87.575 94.662 87.869 ;
     RECT  96.876 87.647 96.966 88.079 ;
     RECT  96.876 88.079 96.894 88.349 ;
     RECT  0.9 86.333 0.954 88.445 ;
     RECT  2.415 87.869 94.662 89.005 ;
     RECT  2.415 89.005 94.698 89.131 ;
     RECT  2.415 89.131 94.842 89.429 ;
     RECT  3.42 89.429 94.698 89.465 ;
     RECT  0.9 88.445 0.918 89.807 ;
     RECT  3.42 89.465 94.497 89.843 ;
     RECT  3.492 89.843 94.497 90.005 ;
     RECT  3.6 90.005 94.497 90.895 ;
     RECT  3.42 90.895 94.497 91.201 ;
     RECT  2.415 89.429 2.697 91.471 ;
     RECT  3.42 91.201 94.662 91.471 ;
     RECT  2.415 91.471 94.662 91.597 ;
     RECT  2.376 91.597 94.662 91.741 ;
     RECT  2.376 91.741 94.77 91.895 ;
     RECT  56.268 91.895 94.77 91.967 ;
     RECT  2.376 91.895 55.35 92.129 ;
     RECT  56.268 91.967 94.497 93.019 ;
     RECT  2.376 92.129 55.278 93.047 ;
     RECT  2.415 93.047 55.278 93.209 ;
     RECT  56.196 93.019 94.497 93.245 ;
     RECT  2.415 93.209 19.854 93.353 ;
     RECT  56.196 93.245 93.042 93.479 ;
     RECT  56.196 93.479 92.43 93.515 ;
     RECT  20.808 93.209 55.278 93.589 ;
     RECT  20.808 93.589 55.638 93.749 ;
     RECT  20.808 93.749 21.078 93.893 ;
     RECT  21.96 93.749 55.638 94.019 ;
     RECT  56.376 93.515 92.43 94.019 ;
     RECT  21.96 94.019 55.278 94.055 ;
     RECT  56.376 94.019 57.186 94.055 ;
     RECT  58.716 94.019 92.43 94.061 ;
     RECT  73.692 94.061 92.43 94.091 ;
     RECT  23.472 94.055 54.594 94.163 ;
     RECT  2.415 93.353 19.818 94.171 ;
     RECT  21.96 94.055 21.978 94.199 ;
     RECT  2.415 94.171 20.394 94.289 ;
     RECT  2.415 94.289 19.818 94.325 ;
     RECT  32.904 94.163 53.55 94.325 ;
     RECT  58.716 94.061 72.897 94.349 ;
     RECT  23.472 94.163 32.13 94.397 ;
     RECT  52.524 94.325 53.55 94.433 ;
     RECT  64.368 94.349 72.897 94.433 ;
     RECT  73.692 94.091 92.394 94.445 ;
     RECT  2.415 94.325 19.674 94.469 ;
     RECT  30.6 94.397 32.13 94.469 ;
     RECT  32.904 94.325 51.714 94.469 ;
     RECT  52.524 94.433 53.118 94.469 ;
     RECT  58.716 94.349 63.594 94.493 ;
     RECT  2.415 94.469 19.314 94.559 ;
     RECT  23.472 94.397 29.862 94.559 ;
     RECT  32.004 94.469 32.13 94.559 ;
     RECT  33.084 94.469 51.714 94.559 ;
     RECT  52.704 94.469 53.118 94.559 ;
     RECT  54.288 94.163 54.594 94.559 ;
     RECT  57.96 94.019 57.978 94.559 ;
     RECT  58.716 94.493 63.522 94.559 ;
     RECT  64.548 94.433 72.897 94.559 ;
     RECT  73.728 94.445 92.394 94.559 ;
     RECT  69.408 94.559 72.897 94.589 ;
     RECT  85.032 94.559 92.286 94.589 ;
     RECT  29.415 94.559 29.79 94.595 ;
     RECT  32.004 94.559 32.022 94.595 ;
     RECT  34.815 94.559 37.926 94.595 ;
     RECT  38.7 94.559 42.03 94.595 ;
     RECT  42.984 94.559 43.146 94.595 ;
     RECT  44.784 94.559 49.374 94.595 ;
     RECT  59.832 94.559 63.522 94.595 ;
     RECT  64.548 94.559 68.454 94.595 ;
     RECT  69.444 94.589 72.897 94.595 ;
     RECT  73.728 94.559 74.682 94.595 ;
     RECT  75.924 94.559 83.97 94.595 ;
     RECT  85.032 94.589 85.842 94.595 ;
     RECT  86.616 94.589 92.286 94.595 ;
     RECT  2.415 94.559 15.354 94.631 ;
     RECT  16.236 94.559 19.314 94.631 ;
     RECT  23.472 94.559 25.074 94.631 ;
     RECT  25.848 94.559 27.018 94.631 ;
     RECT  47.808 94.595 49.374 94.631 ;
     RECT  54.288 94.559 54.486 94.631 ;
     RECT  59.832 94.595 62.406 94.631 ;
     RECT  65.052 94.595 68.382 94.631 ;
     RECT  73.764 94.595 73.782 94.631 ;
     RECT  75.924 94.595 83.826 94.631 ;
     RECT  23.472 94.631 24.93 94.637 ;
     RECT  38.7 94.595 41.526 94.637 ;
     RECT  88.308 94.595 91.89 94.667 ;
     RECT  60.408 94.631 62.406 94.685 ;
     RECT  78.015 94.631 83.697 94.685 ;
     RECT  75.924 94.631 77.166 94.703 ;
     RECT  34.815 94.595 35.19 94.733 ;
     RECT  36.108 94.595 37.926 94.733 ;
     RECT  18.612 94.631 19.314 94.739 ;
     RECT  26.82 94.631 27.018 94.739 ;
     RECT  65.772 94.631 68.382 94.739 ;
     RECT  88.308 94.667 91.314 94.781 ;
     RECT  2.415 94.631 15.174 94.787 ;
     RECT  18.612 94.739 18.897 94.787 ;
     RECT  34.815 94.733 35.097 94.787 ;
     RECT  38.772 94.637 41.526 94.787 ;
     RECT  56.415 94.055 56.697 94.787 ;
     RECT  65.772 94.739 68.238 94.787 ;
     RECT  70.236 94.595 72.897 94.787 ;
     RECT  81.18 94.685 83.697 94.787 ;
     RECT  88.308 94.781 89.097 94.787 ;
     RECT  94.215 93.245 94.497 94.787 ;
     RECT  16.236 94.631 17.874 94.829 ;
     RECT  18.612 94.787 18.705 94.829 ;
     RECT  24.015 94.637 24.93 94.829 ;
     RECT  26.856 94.739 27.018 94.829 ;
     RECT  30.6 94.469 31.23 94.829 ;
     RECT  36.108 94.733 37.782 94.829 ;
     RECT  38.772 94.787 40.305 94.829 ;
     RECT  41.076 94.787 41.526 94.829 ;
     RECT  42.984 94.595 43.074 94.829 ;
     RECT  47.808 94.631 48.582 94.829 ;
     RECT  49.356 94.631 49.374 94.829 ;
     RECT  50.76 94.559 51.714 94.829 ;
     RECT  54.36 94.631 54.486 94.829 ;
     RECT  60.408 94.685 61.002 94.829 ;
     RECT  63.324 94.595 63.522 94.829 ;
     RECT  65.772 94.787 67.305 94.829 ;
     RECT  69.444 94.595 69.462 94.829 ;
     RECT  70.236 94.787 72.705 94.829 ;
     RECT  78.015 94.685 80.406 94.829 ;
     RECT  81.18 94.787 83.505 94.829 ;
     RECT  85.68 94.595 85.842 94.829 ;
     RECT  86.616 94.595 87.462 94.829 ;
     RECT  88.308 94.787 88.974 94.829 ;
     RECT  90.144 94.781 91.314 94.829 ;
     RECT  3.384 94.787 15.174 94.865 ;
     RECT  17.604 94.829 17.874 94.865 ;
     RECT  24.015 94.829 24.39 94.865 ;
     RECT  25.848 94.631 26.01 94.865 ;
     RECT  26.856 94.829 26.874 94.865 ;
     RECT  28.368 94.559 28.602 94.865 ;
     RECT  29.415 94.595 29.754 94.865 ;
     RECT  33.66 94.559 33.858 94.865 ;
     RECT  36.108 94.829 36.81 94.865 ;
     RECT  43.884 94.559 44.046 94.865 ;
     RECT  45.36 94.595 46.422 94.865 ;
     RECT  47.808 94.829 48.222 94.865 ;
     RECT  50.76 94.829 51.105 94.865 ;
     RECT  53.028 94.559 53.118 94.865 ;
     RECT  54.36 94.829 54.378 94.865 ;
     RECT  60.408 94.829 60.426 94.865 ;
     RECT  63.324 94.829 63.342 94.865 ;
     RECT  81.54 94.829 83.505 94.865 ;
     RECT  85.68 94.829 85.698 94.865 ;
     RECT  17.604 94.865 17.622 94.901 ;
     RECT  37.764 94.829 37.782 94.901 ;
     RECT  38.844 94.829 40.305 94.901 ;
     RECT  43.056 94.829 43.074 94.901 ;
     RECT  75.924 94.703 76.986 94.901 ;
     RECT  86.652 94.829 87.462 94.901 ;
     RECT  25.848 94.865 25.866 94.937 ;
     RECT  28.368 94.865 28.386 94.937 ;
     RECT  33.66 94.865 33.678 94.937 ;
     RECT  43.884 94.865 43.902 94.937 ;
     RECT  53.028 94.865 53.046 94.937 ;
     RECT  75.924 94.901 76.95 94.937 ;
     RECT  81.54 94.865 82.278 94.937 ;
     RECT  90.144 94.829 91.242 94.937 ;
     RECT  31.212 94.829 31.23 94.973 ;
     RECT  36.324 94.865 36.81 94.973 ;
     RECT  39.348 94.901 40.305 94.973 ;
     RECT  48.204 94.865 48.222 94.973 ;
     RECT  61.815 94.685 62.406 94.973 ;
     RECT  68.184 94.787 68.238 94.973 ;
     RECT  81.54 94.937 81.558 94.973 ;
     RECT  86.652 94.901 87.354 94.973 ;
     RECT  88.308 94.829 88.905 94.973 ;
     RECT  90.144 94.937 90.666 94.973 ;
     RECT  3.384 94.865 3.402 95.009 ;
     RECT  45.615 94.865 46.206 95.009 ;
     RECT  66.528 94.829 67.305 95.009 ;
     RECT  68.22 94.973 68.238 95.009 ;
     RECT  75.924 94.937 75.942 95.009 ;
     RECT  86.652 94.973 86.67 95.009 ;
     RECT  90.144 94.973 90.162 95.009 ;
     RECT  2.415 94.787 2.505 95.057 ;
     RECT  18.615 94.829 18.705 95.057 ;
     RECT  24.015 94.865 24.105 95.057 ;
     RECT  29.415 94.865 29.505 95.057 ;
     RECT  34.815 94.787 34.905 95.057 ;
     RECT  40.215 94.973 40.305 95.057 ;
     RECT  45.615 95.009 45.705 95.057 ;
     RECT  51.015 94.865 51.105 95.057 ;
     RECT  56.415 94.787 56.505 95.057 ;
     RECT  61.815 94.973 61.905 95.057 ;
     RECT  67.215 95.009 67.305 95.057 ;
     RECT  72.615 94.829 72.705 95.057 ;
     RECT  78.015 94.829 78.105 95.057 ;
     RECT  83.415 94.865 83.505 95.057 ;
     RECT  88.815 94.973 88.905 95.057 ;
     RECT  94.215 94.787 94.305 95.057 ;
     RECT  4.68 94.865 15.102 95.099 ;
     RECT  16.416 94.829 16.434 95.099 ;
     RECT  5.58 95.099 15.102 95.165 ;
     RECT  5.58 95.165 10.494 95.261 ;
     RECT  12.24 95.165 15.102 95.309 ;
     RECT  12.24 95.309 13.59 95.741 ;
     RECT  11.232 95.165 11.466 95.789 ;
     RECT  12.24 95.741 13.014 96.317 ;
     RECT  14.4 95.309 15.102 96.317 ;
     RECT  5.58 95.261 7.29 96.365 ;
     RECT  11.268 95.789 11.466 96.365 ;
     RECT  12.24 96.317 12.834 96.365 ;
     RECT  14.4 96.317 14.418 96.941 ;
     RECT  5.94 96.365 7.29 96.989 ;
     RECT  12.384 96.365 12.834 96.989 ;
     RECT  8.136 95.261 10.494 97.037 ;
     RECT  5.94 96.989 7.254 97.085 ;
     RECT  8.136 97.037 10.062 97.085 ;
     RECT  11.448 96.365 11.466 97.085 ;
     RECT  12.384 96.989 12.402 97.085 ;
    LAYER M4 ;
     RECT  0.025 50.112 0.06 50.136 ;
     RECT  0.025 80.064 0.06 80.088 ;
     RECT  0.06 29.712 0.097 32.712 ;
     RECT  0.06 50.112 0.097 50.376 ;
     RECT  0.06 51.984 0.097 54.984 ;
     RECT  0.097 34.944 0.169 34.968 ;
     RECT  0.06 65.04 0.172 77.256 ;
     RECT  0.172 64.992 0.173 77.256 ;
     RECT  0.097 29.712 0.205 32.856 ;
     RECT  0.173 64.992 0.209 77.064 ;
     RECT  0.06 39.792 0.229 42.792 ;
     RECT  0.205 29.712 0.241 33.144 ;
     RECT  0.241 29.712 0.277 33.384 ;
     RECT  0.06 78.864 0.277 81 ;
     RECT  0.277 78.864 0.313 81.096 ;
     RECT  0.209 64.992 0.317 76.968 ;
     RECT  0.06 45.936 0.515 49.032 ;
     RECT  0.06 20.496 0.565 23.496 ;
     RECT  0.133 38.544 0.565 38.568 ;
     RECT  0.229 39.792 0.565 43.08 ;
     RECT  0.097 51.984 0.565 55.272 ;
     RECT  0.317 64.992 0.565 76.872 ;
     RECT  0.515 45.936 0.601 48.84 ;
     RECT  0.601 44.976 0.605 48.84 ;
     RECT  0.605 44.976 0.637 48.792 ;
     RECT  0.025 9.024 0.889 9.048 ;
     RECT  0.169 34.464 0.997 34.968 ;
     RECT  0.06 10.512 1.141 16.584 ;
     RECT  0.565 38.544 1.393 43.08 ;
     RECT  0.889 8.544 1.429 9.048 ;
     RECT  1.141 10.416 1.429 16.584 ;
     RECT  1.429 85.776 1.501 85.8 ;
     RECT  1.501 85.776 1.969 86.328 ;
     RECT  0.133 61.728 2.149 61.752 ;
     RECT  0.565 64.608 2.221 76.872 ;
     RECT  0.637 44.448 2.252 48.792 ;
     RECT  0.097 26.592 2.293 26.616 ;
     RECT  2.149 61.728 2.293 61.992 ;
     RECT  0.241 63.072 2.293 63.096 ;
     RECT  0.313 83.04 2.293 83.064 ;
     RECT  1.969 85.776 2.293 87.144 ;
     RECT  1.393 6.384 2.329 6.408 ;
     RECT  0.313 78.672 2.365 81.096 ;
     RECT  2.293 85.104 2.401 87.144 ;
     RECT  0.925 88.416 2.401 88.44 ;
     RECT  2.329 6 2.408 6.408 ;
     RECT  1.429 8.544 2.408 16.584 ;
     RECT  1.393 18 2.408 18.024 ;
     RECT  0.565 19.872 2.408 23.496 ;
     RECT  2.293 24.624 2.408 24.648 ;
     RECT  2.293 26.016 2.408 26.616 ;
     RECT  2.293 27.696 2.408 27.72 ;
     RECT  0.277 28.752 2.408 33.384 ;
     RECT  0.997 34.464 2.408 35.208 ;
     RECT  2.329 36.24 2.408 36.264 ;
     RECT  1.393 37.968 2.408 43.08 ;
     RECT  2.252 44.352 2.408 48.792 ;
     RECT  0.097 50.112 2.408 50.472 ;
     RECT  0.565 51.696 2.408 55.272 ;
     RECT  1.573 58.992 2.408 59.016 ;
     RECT  2.293 60.864 2.408 63.096 ;
     RECT  2.221 64.368 2.408 76.872 ;
     RECT  2.365 78.672 2.408 81.144 ;
     RECT  2.293 83.04 2.408 83.784 ;
     RECT  2.401 85.104 2.408 88.44 ;
     RECT  2.408 2.148 2.512 95.052 ;
     RECT  2.512 2.256 2.704 94.782 ;
     RECT  2.704 2.256 2.819 4.392 ;
     RECT  2.704 26.592 3.089 43.08 ;
     RECT  2.819 2.448 3.413 4.392 ;
     RECT  2.704 50.016 3.485 55.272 ;
     RECT  3.089 27.888 3.769 43.08 ;
     RECT  2.704 44.4 3.769 48.792 ;
     RECT  2.704 58.992 3.805 83.832 ;
     RECT  3.769 1.152 3.853 1.176 ;
     RECT  2.704 90.912 3.913 93.24 ;
     RECT  2.704 5.664 3.949 16.584 ;
     RECT  3.413 2.448 4.025 4.008 ;
     RECT  4.025 2.448 4.069 2.952 ;
     RECT  3.089 26.592 4.165 26.76 ;
     RECT  3.769 27.888 4.165 48.792 ;
     RECT  4.025 3.984 4.169 4.008 ;
     RECT  3.949 5.232 4.172 16.584 ;
     RECT  2.704 17.664 4.172 23.352 ;
     RECT  3.913 90.912 4.213 93.48 ;
     RECT  4.172 5.232 4.259 23.352 ;
     RECT  4.213 90.912 4.3 94.296 ;
     RECT  2.704 25.488 4.313 25.512 ;
     RECT  3.805 58.512 4.385 83.832 ;
     RECT  4.385 60.432 4.453 83.832 ;
     RECT  4.3 90.912 4.489 94.104 ;
     RECT  4.453 60.432 4.561 84.408 ;
     RECT  2.704 85.44 4.561 88.92 ;
     RECT  4.069 1.728 4.565 2.952 ;
     RECT  4.165 26.592 4.601 48.792 ;
     RECT  4.601 39.312 4.633 48.792 ;
     RECT  3.485 50.112 4.633 55.272 ;
     RECT  4.385 58.512 4.633 59.016 ;
     RECT  4.489 90.672 4.633 94.104 ;
     RECT  3.913 24.48 4.652 24.504 ;
     RECT  4.633 58.128 4.693 59.016 ;
     RECT  4.693 56.4 4.705 59.016 ;
     RECT  4.601 26.592 4.709 38.136 ;
     RECT  4.652 24.48 4.739 25.176 ;
     RECT  4.259 5.232 4.741 16.584 ;
     RECT  4.633 90.624 4.741 94.104 ;
     RECT  4.633 39.312 4.745 55.272 ;
     RECT  4.259 17.76 4.813 23.352 ;
     RECT  4.739 24.48 4.813 24.936 ;
     RECT  4.741 90.048 4.817 94.104 ;
     RECT  4.565 1.728 4.883 2.28 ;
     RECT  4.561 60.432 4.921 88.92 ;
     RECT  4.817 90.048 4.921 93.048 ;
     RECT  4.883 1.728 5.075 1.848 ;
     RECT  3.733 0.096 5.093 0.12 ;
     RECT  4.921 60.432 5.105 93.048 ;
     RECT  4.813 17.76 5.123 24.936 ;
     RECT  5.123 19.152 5.249 24.936 ;
     RECT  4.741 4.368 5.269 16.584 ;
     RECT  5.269 4.368 5.281 16.632 ;
     RECT  5.123 17.76 5.281 18.024 ;
     RECT  5.281 4.368 5.317 18.024 ;
     RECT  4.705 56.352 5.389 59.016 ;
     RECT  5.249 19.44 5.429 24.936 ;
     RECT  4.745 39.36 5.429 55.272 ;
     RECT  4.709 26.592 5.497 27.096 ;
     RECT  5.389 56.352 5.573 59.352 ;
     RECT  5.573 56.352 5.603 58.008 ;
     RECT  5.093 0.096 5.605 0.168 ;
     RECT  5.429 51.696 5.641 55.272 ;
     RECT  5.603 56.352 5.641 56.376 ;
     RECT  5.105 60.432 5.653 92.52 ;
     RECT  5.075 1.728 5.681 1.752 ;
     RECT  4.817 94.08 5.713 94.104 ;
     RECT  5.701 95.136 5.713 95.16 ;
     RECT  4.709 28.128 5.821 38.136 ;
     RECT  5.569 96.336 5.885 96.36 ;
     RECT  5.713 94.08 5.897 95.16 ;
     RECT  5.497 26.208 6.188 27.096 ;
     RECT  5.821 28.128 6.188 38.184 ;
     RECT  6.188 26.208 6.275 38.184 ;
     RECT  5.429 19.632 6.329 24.936 ;
     RECT  5.573 58.992 6.332 59.352 ;
     RECT  5.653 60.384 6.332 92.52 ;
     RECT  6.332 58.992 6.419 92.52 ;
     RECT  6.275 28.08 6.473 38.184 ;
     RECT  5.605 0.096 6.565 0.6 ;
     RECT  5.641 51.696 6.565 56.376 ;
     RECT  5.317 3.408 6.577 18.024 ;
     RECT  6.329 19.632 6.577 24.504 ;
     RECT  6.565 0.096 6.581 0.696 ;
     RECT  6.577 3.408 6.757 24.504 ;
     RECT  6.757 2.928 6.797 24.504 ;
     RECT  5.429 39.36 6.853 50.136 ;
     RECT  6.581 0.576 6.913 0.696 ;
     RECT  5.603 57.36 7.009 58.008 ;
     RECT  6.419 58.992 7.009 59.352 ;
     RECT  6.913 0.576 7.021 0.648 ;
     RECT  6.797 2.928 7.045 3.48 ;
     RECT  6.419 60.384 7.081 92.52 ;
     RECT  5.897 94.512 7.117 95.16 ;
     RECT  6.565 51.216 7.225 56.376 ;
     RECT  7.009 57.36 7.225 59.352 ;
     RECT  6.853 39.072 7.513 50.136 ;
     RECT  7.081 60.384 7.525 92.952 ;
     RECT  7.117 94.08 7.525 95.16 ;
     RECT  6.275 26.208 7.549 27.096 ;
     RECT  6.473 28.08 7.549 37.992 ;
     RECT  7.549 26.208 7.585 37.992 ;
     RECT  7.513 38.976 7.585 50.136 ;
     RECT  5.885 96.336 7.667 97.08 ;
     RECT  7.525 60.384 7.765 95.16 ;
     RECT  7.045 1.728 7.808 1.752 ;
     RECT  7.045 2.736 7.808 3.48 ;
     RECT  6.797 4.512 7.808 24.504 ;
     RECT  7.585 26.208 7.808 50.136 ;
     RECT  7.225 51.216 7.808 59.352 ;
     RECT  7.765 60.384 7.808 95.256 ;
     RECT  7.808 1.728 7.955 95.256 ;
     RECT  7.955 1.728 7.985 95.208 ;
     RECT  7.717 0.096 8.101 0.168 ;
     RECT  7.985 1.728 8.104 95.16 ;
     RECT  8.101 0.096 8.243 0.312 ;
     RECT  8.243 0.096 8.339 0.216 ;
     RECT  8.104 27.648 8.597 55.464 ;
     RECT  8.104 60.384 8.705 95.16 ;
     RECT  7.667 97.056 8.732 97.08 ;
     RECT  8.705 85.2 8.741 95.16 ;
     RECT  8.104 1.728 8.813 24.552 ;
     RECT  8.597 28.752 8.849 55.464 ;
     RECT  8.741 92.304 8.921 95.16 ;
     RECT  8.104 25.68 9.097 26.616 ;
     RECT  8.104 57.024 9.241 59.208 ;
     RECT  9.097 25.584 9.389 26.616 ;
     RECT  8.921 94.656 9.529 95.16 ;
     RECT  8.597 27.648 9.601 27.672 ;
     RECT  8.849 28.752 9.601 33.384 ;
     RECT  8.813 1.728 9.605 3.432 ;
     RECT  8.849 34.464 9.637 55.464 ;
     RECT  9.241 56.784 9.637 59.208 ;
     RECT  9.601 27.648 9.749 33.384 ;
     RECT  9.637 34.464 9.779 59.208 ;
     RECT  8.339 0.096 9.781 0.168 ;
     RECT  8.705 60.384 9.785 84.216 ;
     RECT  9.779 34.464 9.821 56.28 ;
     RECT  9.749 27.84 9.836 33.384 ;
     RECT  9.821 34.464 9.836 56.136 ;
     RECT  9.781 0.096 9.875 0.552 ;
     RECT  9.785 61.488 9.889 84.216 ;
     RECT  8.741 85.2 9.889 91.176 ;
     RECT  8.813 4.56 9.925 24.552 ;
     RECT  9.925 3.6 10.009 24.552 ;
     RECT  8.732 96.336 10.073 97.08 ;
     RECT  9.529 94.656 10.117 95.208 ;
     RECT  10.073 96.336 10.117 97.032 ;
     RECT  9.779 57.456 10.124 59.208 ;
     RECT  9.785 60.384 10.124 60.504 ;
     RECT  8.921 92.304 10.133 93.624 ;
     RECT  10.117 94.656 10.133 97.032 ;
     RECT  9.889 61.488 10.177 91.176 ;
     RECT  10.133 92.304 10.177 97.032 ;
     RECT  9.389 25.68 10.217 26.616 ;
     RECT  10.177 61.488 10.217 97.032 ;
     RECT  10.217 61.488 10.253 95.208 ;
     RECT  9.605 1.728 10.297 2.52 ;
     RECT  10.124 57.456 10.325 60.504 ;
     RECT  9.875 0.096 10.433 0.264 ;
     RECT  10.433 0.192 10.685 0.264 ;
     RECT  10.217 26.256 10.825 26.616 ;
     RECT  9.836 27.84 10.825 56.136 ;
     RECT  10.297 1.776 10.897 2.52 ;
     RECT  10.009 3.6 10.897 3.624 ;
     RECT  10.325 58.752 10.933 60.504 ;
     RECT  10.253 61.488 10.933 81.48 ;
     RECT  10.009 4.656 10.969 24.552 ;
     RECT  10.825 26.256 11.029 56.136 ;
     RECT  10.325 57.456 11.029 57.768 ;
     RECT  10.969 4.656 11.045 24.936 ;
     RECT  10.897 1.776 11.117 3.624 ;
     RECT  10.217 96.336 11.173 97.032 ;
     RECT  11.117 2.496 11.221 3.624 ;
     RECT  11.045 4.656 11.221 4.68 ;
     RECT  10.253 82.464 11.221 95.208 ;
     RECT  11.173 96.336 11.221 97.08 ;
     RECT  11.045 5.952 11.293 24.936 ;
     RECT  11.221 2.496 11.341 4.68 ;
     RECT  11.293 5.952 11.405 25.08 ;
     RECT  10.685 0.192 11.441 0.216 ;
     RECT  11.405 5.952 11.477 24.936 ;
     RECT  11.221 82.464 11.507 97.08 ;
     RECT  11.477 5.952 11.513 24.696 ;
     RECT  11.029 26.256 11.729 57.768 ;
     RECT  11.729 56.352 11.977 57.768 ;
     RECT  10.933 58.752 11.977 81.48 ;
     RECT  11.341 3.84 12.049 4.68 ;
     RECT  11.513 6.096 12.125 24.696 ;
     RECT  11.977 56.352 12.157 81.48 ;
     RECT  11.507 82.464 12.157 95.16 ;
     RECT  11.729 26.256 12.409 55.272 ;
     RECT  11.507 96.336 12.413 97.08 ;
     RECT  12.409 26.112 12.445 55.272 ;
     RECT  12.413 96.336 12.517 97.032 ;
     RECT  12.125 8.064 12.553 24.696 ;
     RECT  12.445 25.776 12.553 55.272 ;
     RECT  12.517 96.288 12.947 97.032 ;
     RECT  12.157 56.352 13.189 95.16 ;
     RECT  11.341 2.496 13.208 2.52 ;
     RECT  12.049 3.84 13.208 4.872 ;
     RECT  12.125 6.096 13.208 7.08 ;
     RECT  12.553 8.064 13.208 55.272 ;
     RECT  13.189 56.352 13.208 95.208 ;
     RECT  13.208 2.148 13.285 95.208 ;
     RECT  12.947 96.288 13.285 96.936 ;
     RECT  13.285 2.148 13.312 96.936 ;
     RECT  13.312 2.418 13.504 96.936 ;
     RECT  13.504 44.16 13.601 96.936 ;
     RECT  13.504 3.84 13.745 3.864 ;
     RECT  13.601 44.16 13.745 95.304 ;
     RECT  13.745 44.16 14.069 95.208 ;
     RECT  13.504 8.016 14.393 43.128 ;
     RECT  13.601 96.288 14.429 96.936 ;
     RECT  14.069 44.16 14.609 87.144 ;
     RECT  13.504 2.832 14.677 2.856 ;
     RECT  14.393 26.592 14.857 43.128 ;
     RECT  14.609 44.16 14.857 81.48 ;
     RECT  14.069 88.32 14.969 95.208 ;
     RECT  14.429 96.288 15.113 96.312 ;
     RECT  14.677 4.704 15.217 4.728 ;
     RECT  14.393 8.016 15.217 25.608 ;
     RECT  15.217 4.56 15.257 4.728 ;
     RECT  13.504 6.096 15.361 6.408 ;
     RECT  14.677 2.592 15.473 2.856 ;
     RECT  15.217 7.968 15.613 25.608 ;
     RECT  14.857 26.592 15.613 81.48 ;
     RECT  15.613 7.968 15.649 81.48 ;
     RECT  14.609 82.464 15.649 87.144 ;
     RECT  15.361 5.712 15.973 6.408 ;
     RECT  14.969 88.32 15.977 94.488 ;
     RECT  15.977 88.32 16.009 90.312 ;
     RECT  15.473 2.784 16.261 2.856 ;
     RECT  15.649 7.968 16.369 87.144 ;
     RECT  15.977 91.296 16.553 94.488 ;
     RECT  16.369 7.824 16.801 87.144 ;
     RECT  16.009 88.224 16.801 90.312 ;
     RECT  16.553 91.296 16.913 94.104 ;
     RECT  15.973 5.712 16.949 6.84 ;
     RECT  16.949 6.384 17.017 6.84 ;
     RECT  16.801 7.824 17.017 90.312 ;
     RECT  17.017 6.384 17.053 90.312 ;
     RECT  16.913 91.296 17.053 93.816 ;
     RECT  17.053 6.384 17.237 93.816 ;
     RECT  16.261 2.784 17.276 3.288 ;
     RECT  15.257 4.56 17.276 4.584 ;
     RECT  17.237 88.224 17.309 93.816 ;
     RECT  17.237 6.384 17.363 87.144 ;
     RECT  17.276 2.784 17.449 4.584 ;
     RECT  17.449 2.784 17.561 5.256 ;
     RECT  17.309 88.224 18.205 88.776 ;
     RECT  17.561 2.784 18.529 4.584 ;
     RECT  18.529 2.784 18.608 5.064 ;
     RECT  17.363 6.384 18.608 6.888 ;
     RECT  17.363 8.208 18.608 87.144 ;
     RECT  18.205 88.128 18.608 88.776 ;
     RECT  17.309 89.856 18.608 93.816 ;
     RECT  18.608 2.148 18.712 95.052 ;
     RECT  18.712 2.418 18.904 94.782 ;
     RECT  18.904 2.64 18.965 43.176 ;
     RECT  18.904 44.16 18.965 87.144 ;
     RECT  18.904 92.4 19.132 94.104 ;
     RECT  19.132 92.4 19.325 93.528 ;
     RECT  19.325 92.4 19.433 92.424 ;
     RECT  18.904 88.128 19.469 91.32 ;
     RECT  19.325 93.504 19.613 93.528 ;
     RECT  19.469 88.128 19.667 90.6 ;
     RECT  18.965 6.288 19.829 43.176 ;
     RECT  19.667 88.128 20.081 90.552 ;
     RECT  18.965 2.64 20.149 5.304 ;
     RECT  18.965 44.16 20.401 84.12 ;
     RECT  18.965 85.2 20.401 87.144 ;
     RECT  20.401 44.16 20.473 87.144 ;
     RECT  20.081 88.128 20.473 89.304 ;
     RECT  19.829 8.112 21.049 43.176 ;
     RECT  20.473 44.16 21.049 89.304 ;
     RECT  21.049 8.112 21.053 89.304 ;
     RECT  19.829 6.384 21.121 6.84 ;
     RECT  20.149 2.448 21.125 5.304 ;
     RECT  21.053 36.768 21.125 89.304 ;
     RECT  21.125 2.832 21.445 5.304 ;
     RECT  21.121 6.384 21.481 6.888 ;
     RECT  21.053 8.112 21.481 35.592 ;
     RECT  21.445 2.832 21.589 5.4 ;
     RECT  21.481 6.384 21.589 35.592 ;
     RECT  20.725 92.928 21.589 92.952 ;
     RECT  21.125 36.912 21.625 89.304 ;
     RECT  20.081 90.528 21.625 90.552 ;
     RECT  20.041 91.728 21.635 91.752 ;
     RECT  21.589 92.928 21.673 93.48 ;
     RECT  21.625 36.912 21.697 90.552 ;
     RECT  21.673 93.024 22.421 93.48 ;
     RECT  21.589 2.832 22.637 35.592 ;
     RECT  21.697 36.912 22.691 91.128 ;
     RECT  22.421 93.024 22.849 93.048 ;
     RECT  22.637 2.832 22.885 3.192 ;
     RECT  22.849 92.448 22.993 93.048 ;
     RECT  22.637 4.464 23.209 35.592 ;
     RECT  22.691 36.912 23.209 45.72 ;
     RECT  22.885 2.304 23.677 3.192 ;
     RECT  23.209 4.464 23.677 45.72 ;
     RECT  23.677 2.304 24.008 45.72 ;
     RECT  22.691 46.896 24.008 91.128 ;
     RECT  22.993 92.112 24.008 93.048 ;
     RECT  23.461 94.608 24.008 94.632 ;
     RECT  24.008 2.148 24.112 95.052 ;
     RECT  24.112 2.304 24.304 94.782 ;
     RECT  24.304 94.32 24.401 94.632 ;
     RECT  24.304 92.448 24.653 92.472 ;
     RECT  24.304 3.408 24.941 91.368 ;
     RECT  24.941 6.336 25.085 91.368 ;
     RECT  25.085 6.336 25.157 89.544 ;
     RECT  25.085 90.912 25.157 91.368 ;
     RECT  25.157 6.384 25.337 89.544 ;
     RECT  24.304 2.304 25.549 2.328 ;
     RECT  24.941 3.408 25.549 5.304 ;
     RECT  25.513 92.928 25.621 92.952 ;
     RECT  25.549 2.304 25.877 5.304 ;
     RECT  25.337 61.44 25.913 89.544 ;
     RECT  25.337 6.384 26.161 60.408 ;
     RECT  25.877 4.416 26.341 5.304 ;
     RECT  25.877 2.304 26.381 3.432 ;
     RECT  25.621 92.304 26.521 92.952 ;
     RECT  25.157 90.912 26.665 91.128 ;
     RECT  26.521 92.304 26.665 93.096 ;
     RECT  26.341 4.416 26.725 5.352 ;
     RECT  26.161 6.336 26.725 60.408 ;
     RECT  26.725 4.416 26.881 60.408 ;
     RECT  25.913 61.44 26.881 84.168 ;
     RECT  26.881 4.416 26.921 84.168 ;
     RECT  26.921 4.416 27.317 59.976 ;
     RECT  26.381 2.304 27.349 2.856 ;
     RECT  26.921 60.96 27.349 84.168 ;
     RECT  25.913 85.2 27.349 89.544 ;
     RECT  27.349 2.304 27.389 3.432 ;
     RECT  26.665 90.912 27.421 93.096 ;
     RECT  27.389 3.408 27.539 3.432 ;
     RECT  27.349 60.96 28.076 89.544 ;
     RECT  27.421 90.624 28.076 93.096 ;
     RECT  28.076 60.96 28.163 93.096 ;
     RECT  27.317 4.656 28.213 59.976 ;
     RECT  28.163 60.96 28.213 89.736 ;
     RECT  28.213 4.656 28.604 89.736 ;
     RECT  28.163 91.008 28.861 93.096 ;
     RECT  28.604 3.696 29.365 89.736 ;
     RECT  28.861 91.008 29.365 93.336 ;
     RECT  27.673 2.256 29.408 2.28 ;
     RECT  29.365 3.696 29.408 93.336 ;
     RECT  24.401 94.32 29.408 94.344 ;
     RECT  29.408 2.148 29.512 95.052 ;
     RECT  29.512 2.256 29.704 94.782 ;
     RECT  29.704 8.544 29.837 94.68 ;
     RECT  29.837 90.144 29.843 94.68 ;
     RECT  29.704 2.256 30.515 3.432 ;
     RECT  29.704 4.512 30.769 7.224 ;
     RECT  29.837 8.544 30.769 88.92 ;
     RECT  29.843 90.144 30.881 94.392 ;
     RECT  30.881 91.44 30.917 94.392 ;
     RECT  30.917 91.44 30.953 94.2 ;
     RECT  30.515 3.072 30.985 3.432 ;
     RECT  30.769 4.512 30.985 88.92 ;
     RECT  30.881 90.144 30.985 90.36 ;
     RECT  30.953 91.44 31.313 91.704 ;
     RECT  30.985 3.072 31.345 88.92 ;
     RECT  30.985 90.048 31.345 90.36 ;
     RECT  30.953 92.928 31.385 94.2 ;
     RECT  31.385 92.928 31.997 94.104 ;
     RECT  31.345 3.072 32.389 90.36 ;
     RECT  31.313 91.44 32.461 91.656 ;
     RECT  31.997 92.928 32.461 93.624 ;
     RECT  32.389 3.072 32.497 90.456 ;
     RECT  32.461 91.44 32.497 93.624 ;
     RECT  32.497 3.072 32.641 93.624 ;
     RECT  32.641 2.496 32.825 93.624 ;
     RECT  32.825 39.552 32.969 93.624 ;
     RECT  32.825 2.496 33.113 38.52 ;
     RECT  33.113 4.128 33.257 38.52 ;
     RECT  33.113 2.496 33.541 3.096 ;
     RECT  33.541 2.4 33.589 3.096 ;
     RECT  33.589 2.256 33.676 3.096 ;
     RECT  33.257 26.544 34.009 38.52 ;
     RECT  32.969 39.552 34.009 93.336 ;
     RECT  33.257 4.128 34.225 25.56 ;
     RECT  34.009 26.544 34.225 93.336 ;
     RECT  34.225 4.128 34.657 93.336 ;
     RECT  33.676 2.4 34.808 3.096 ;
     RECT  34.657 4.128 34.808 94.056 ;
     RECT  34.808 2.148 34.912 95.052 ;
     RECT  34.912 2.418 35.104 94.782 ;
     RECT  35.104 2.496 35.453 90.12 ;
     RECT  35.453 2.496 35.633 89.64 ;
     RECT  35.104 91.2 35.777 94.728 ;
     RECT  35.633 2.976 35.921 89.64 ;
     RECT  35.777 93.216 36.029 94.728 ;
     RECT  36.029 93.216 36.101 93.384 ;
     RECT  35.777 91.2 36.281 92.184 ;
     RECT  36.281 91.2 36.385 91.704 ;
     RECT  35.921 3.312 36.569 89.64 ;
     RECT  36.385 91.152 36.677 91.704 ;
     RECT  36.677 91.2 37.249 91.704 ;
     RECT  36.101 93.264 37.537 93.384 ;
     RECT  37.249 2.64 37.573 2.664 ;
     RECT  36.569 3.696 37.609 89.64 ;
     RECT  37.573 2.352 37.861 2.664 ;
     RECT  37.609 3.696 37.861 90.168 ;
     RECT  37.537 93.264 37.901 93.48 ;
     RECT  36.029 94.704 38.684 94.728 ;
     RECT  37.861 2.352 38.693 90.168 ;
     RECT  38.693 37.92 38.725 90.168 ;
     RECT  37.249 91.2 38.725 91.752 ;
     RECT  38.684 94.512 38.771 94.728 ;
     RECT  38.771 94.608 38.837 94.632 ;
     RECT  38.693 2.352 38.873 36.648 ;
     RECT  38.725 37.92 38.981 91.752 ;
     RECT  37.901 93.312 39.193 93.48 ;
     RECT  38.981 51.648 39.589 91.752 ;
     RECT  39.193 92.928 39.589 93.48 ;
     RECT  39.589 51.648 39.805 93.48 ;
     RECT  39.797 94.656 39.805 94.68 ;
     RECT  38.873 2.592 40.093 36.648 ;
     RECT  40.093 2.592 40.208 36.888 ;
     RECT  38.981 37.92 40.208 50.616 ;
     RECT  39.805 51.648 40.208 94.68 ;
     RECT  40.208 2.148 40.312 95.052 ;
     RECT  40.312 2.418 40.504 94.782 ;
     RECT  40.504 4.416 41.141 94.104 ;
     RECT  41.141 5.184 41.357 90.12 ;
     RECT  41.141 91.104 41.753 94.104 ;
     RECT  41.753 91.824 41.825 94.104 ;
     RECT  40.504 2.496 42.113 3.144 ;
     RECT  41.357 5.184 42.185 88.44 ;
     RECT  42.185 51.696 42.577 88.44 ;
     RECT  41.357 89.664 42.577 90.12 ;
     RECT  42.113 2.736 42.721 3.144 ;
     RECT  42.541 4.128 42.721 4.152 ;
     RECT  42.721 2.736 42.757 4.152 ;
     RECT  42.185 5.184 42.757 50.664 ;
     RECT  41.825 91.824 42.757 93.864 ;
     RECT  42.577 51.696 42.833 90.12 ;
     RECT  42.757 91.728 42.833 93.864 ;
     RECT  42.757 2.736 42.905 50.664 ;
     RECT  42.905 4.512 43.085 50.664 ;
     RECT  43.085 8.496 43.225 50.664 ;
     RECT  42.833 51.696 43.225 88.44 ;
     RECT  42.833 89.424 43.801 90.12 ;
     RECT  42.833 91.728 43.801 93.528 ;
     RECT  43.801 89.424 43.837 93.528 ;
     RECT  43.837 89.424 44.057 94.344 ;
     RECT  44.057 91.92 44.129 94.344 ;
     RECT  43.085 4.512 44.269 7.464 ;
     RECT  43.225 8.496 44.269 88.44 ;
     RECT  42.905 2.736 44.293 3.384 ;
     RECT  44.293 2.256 44.381 3.384 ;
     RECT  44.269 4.512 44.989 88.44 ;
     RECT  44.057 89.424 44.989 90.84 ;
     RECT  44.129 91.92 45.133 94.296 ;
     RECT  44.381 2.736 45.241 3.384 ;
     RECT  44.989 4.512 45.241 90.84 ;
     RECT  45.241 2.736 45.608 90.84 ;
     RECT  45.133 91.872 45.608 94.296 ;
     RECT  45.608 2.148 45.712 95.052 ;
     RECT  45.712 2.418 45.904 94.782 ;
     RECT  45.904 3.024 46.001 89.736 ;
     RECT  46.001 5.184 46.577 89.736 ;
     RECT  46.001 3.024 46.793 4.104 ;
     RECT  46.793 3.024 46.865 3.384 ;
     RECT  46.577 5.184 46.865 21.768 ;
     RECT  45.904 91.632 46.897 94.44 ;
     RECT  46.865 3.024 47.153 3.048 ;
     RECT  46.577 22.8 47.221 89.736 ;
     RECT  46.865 5.184 47.257 5.352 ;
     RECT  46.865 6.384 47.657 21.768 ;
     RECT  47.657 8.448 47.725 21.768 ;
     RECT  47.221 22.8 47.725 90.168 ;
     RECT  46.897 91.44 47.729 94.44 ;
     RECT  47.725 8.448 47.801 90.168 ;
     RECT  47.801 8.448 47.891 17.208 ;
     RECT  47.801 18.528 47.891 90.168 ;
     RECT  47.891 89.424 47.941 90.168 ;
     RECT  47.891 18.528 47.945 88.44 ;
     RECT  47.945 19.248 48.017 88.44 ;
     RECT  47.891 8.688 48.233 17.208 ;
     RECT  47.729 91.632 48.485 94.44 ;
     RECT  48.409 3.408 48.625 3.432 ;
     RECT  47.257 4.656 48.625 5.352 ;
     RECT  48.017 70.56 48.949 88.44 ;
     RECT  47.941 89.424 48.949 90.648 ;
     RECT  48.485 91.632 48.949 94.008 ;
     RECT  47.657 6.384 48.985 7.224 ;
     RECT  48.017 19.248 48.985 69.528 ;
     RECT  48.949 70.56 48.985 94.008 ;
     RECT  48.985 6.384 49.021 7.704 ;
     RECT  48.233 8.688 49.021 10.68 ;
     RECT  48.985 19.2 49.021 94.008 ;
     RECT  48.233 11.712 49.093 17.208 ;
     RECT  48.625 3.408 49.165 5.352 ;
     RECT  49.021 18.384 49.187 94.008 ;
     RECT  49.165 2.832 49.205 5.352 ;
     RECT  49.205 3.936 49.313 5.352 ;
     RECT  49.021 6.384 49.313 10.68 ;
     RECT  49.313 4.656 49.565 5.352 ;
     RECT  49.187 18.384 49.673 69 ;
     RECT  49.093 11.712 49.813 17.304 ;
     RECT  49.187 70.08 49.817 94.008 ;
     RECT  49.817 89.472 49.885 94.008 ;
     RECT  49.565 5.28 49.921 5.352 ;
     RECT  49.313 6.384 49.921 7.224 ;
     RECT  49.813 11.712 49.921 17.4 ;
     RECT  49.673 18.384 49.921 22.056 ;
     RECT  49.921 11.712 50.197 22.056 ;
     RECT  49.205 2.832 50.569 2.856 ;
     RECT  49.921 5.28 50.605 7.224 ;
     RECT  50.569 2.784 50.629 2.856 ;
     RECT  49.313 8.448 50.677 10.68 ;
     RECT  50.197 11.664 50.677 22.056 ;
     RECT  49.673 23.136 50.869 69 ;
     RECT  49.817 70.08 50.869 88.488 ;
     RECT  50.869 23.136 50.893 88.488 ;
     RECT  49.885 89.472 50.893 94.296 ;
     RECT  50.629 2.784 51.008 3.768 ;
     RECT  50.605 5.136 51.008 7.224 ;
     RECT  50.677 8.448 51.008 22.056 ;
     RECT  50.893 23.136 51.008 94.296 ;
     RECT  51.008 2.148 51.112 95.052 ;
     RECT  51.112 2.418 51.304 94.782 ;
     RECT  51.304 70.608 51.509 90.648 ;
     RECT  51.304 91.968 51.905 93.624 ;
     RECT  51.905 91.968 52.013 93 ;
     RECT  51.509 70.608 52.085 90.024 ;
     RECT  51.304 3.12 52.412 69.576 ;
     RECT  52.085 70.608 52.412 87.192 ;
     RECT  52.412 3.12 52.513 87.192 ;
     RECT  52.085 88.368 52.589 90.024 ;
     RECT  52.513 2.496 52.945 87.192 ;
     RECT  52.013 92.16 53.053 93 ;
     RECT  52.945 2.352 53.057 87.192 ;
     RECT  53.057 2.352 53.129 43.128 ;
     RECT  52.589 88.416 53.197 90.024 ;
     RECT  53.197 88.416 53.201 90.888 ;
     RECT  53.129 2.352 53.237 7.464 ;
     RECT  53.057 44.16 53.273 87.192 ;
     RECT  53.237 2.352 53.309 7.32 ;
     RECT  53.273 44.16 53.309 87.144 ;
     RECT  53.309 63.6 53.453 87.144 ;
     RECT  53.201 90 53.561 90.888 ;
     RECT  53.309 2.496 53.777 7.32 ;
     RECT  53.453 63.6 53.957 70.104 ;
     RECT  53.453 71.136 54.349 87.144 ;
     RECT  53.201 88.416 54.349 88.92 ;
     RECT  53.777 3.072 54.469 7.32 ;
     RECT  53.129 8.784 54.469 43.128 ;
     RECT  53.309 44.16 54.469 62.52 ;
     RECT  54.469 3.072 54.493 7.368 ;
     RECT  54.493 3.072 54.529 7.464 ;
     RECT  54.469 8.784 54.529 62.52 ;
     RECT  54.529 3.072 54.673 62.52 ;
     RECT  53.957 63.6 54.673 69 ;
     RECT  53.561 90.864 54.673 90.888 ;
     RECT  54.673 3.072 54.757 69 ;
     RECT  54.673 90.576 54.853 90.888 ;
     RECT  53.053 92.16 54.853 93.48 ;
     RECT  54.349 71.136 54.889 88.92 ;
     RECT  54.853 90.576 54.893 93.624 ;
     RECT  54.893 90.576 54.899 92.424 ;
     RECT  54.899 90.624 54.94 92.376 ;
     RECT  54.889 71.136 54.995 89.304 ;
     RECT  54.757 2.688 55.217 69 ;
     RECT  55.217 36.624 55.321 69 ;
     RECT  53.957 70.08 55.321 70.104 ;
     RECT  55.217 2.688 55.325 35.496 ;
     RECT  55.321 36.624 56.077 70.104 ;
     RECT  54.995 71.136 56.077 72.552 ;
     RECT  54.995 73.824 56.185 89.304 ;
     RECT  54.94 90.624 56.185 90.648 ;
     RECT  56.077 36.624 56.293 72.552 ;
     RECT  56.185 73.584 56.293 89.304 ;
     RECT  54.94 92.352 56.293 92.376 ;
     RECT  55.325 2.736 56.408 35.496 ;
     RECT  56.293 36.624 56.408 89.304 ;
     RECT  56.185 90.336 56.408 90.648 ;
     RECT  56.293 91.872 56.408 92.376 ;
     RECT  54.893 93.6 56.408 93.624 ;
     RECT  56.408 2.148 56.512 95.052 ;
     RECT  56.512 2.418 56.704 94.782 ;
     RECT  56.704 2.736 57.017 3.048 ;
     RECT  56.704 4.176 57.557 62.232 ;
     RECT  56.704 69.984 57.665 92.472 ;
     RECT  57.017 2.784 57.733 3.048 ;
     RECT  57.665 92.448 57.733 92.472 ;
     RECT  56.704 63.6 57.829 69 ;
     RECT  57.665 69.984 57.829 90.36 ;
     RECT  57.557 51.744 57.923 62.232 ;
     RECT  57.829 63.6 57.985 90.36 ;
     RECT  57.733 2.784 58.061 3.096 ;
     RECT  57.923 52.8 58.201 62.232 ;
     RECT  58.061 2.976 58.345 3.096 ;
     RECT  57.557 4.176 58.345 50.76 ;
     RECT  57.985 63.552 58.385 90.36 ;
     RECT  58.345 2.976 58.597 50.76 ;
     RECT  58.201 52.8 58.885 62.28 ;
     RECT  57.733 92.448 58.957 92.568 ;
     RECT  58.597 2.976 59.029 50.952 ;
     RECT  58.885 51.936 59.029 62.28 ;
     RECT  59.029 2.976 59.033 62.28 ;
     RECT  59.033 2.976 59.065 3.768 ;
     RECT  58.385 70.416 59.209 90.36 ;
     RECT  59.033 4.8 59.213 62.28 ;
     RECT  59.065 2.688 59.267 3.768 ;
     RECT  59.267 3.024 59.321 3.768 ;
     RECT  59.213 51.888 59.357 62.28 ;
     RECT  59.213 4.8 59.465 50.76 ;
     RECT  58.385 63.552 59.533 69.336 ;
     RECT  59.209 70.416 59.533 90.552 ;
     RECT  59.357 51.936 59.573 62.28 ;
     RECT  59.533 63.552 59.677 90.552 ;
     RECT  58.957 92.4 59.677 92.568 ;
     RECT  59.321 3.024 59.753 3.096 ;
     RECT  59.677 63.552 59.785 92.568 ;
     RECT  59.465 4.8 60.005 50.712 ;
     RECT  59.785 63.552 60.037 93 ;
     RECT  60.037 63.552 60.145 93.336 ;
     RECT  59.573 51.984 60.257 62.28 ;
     RECT  59.753 3.024 60.289 3.048 ;
     RECT  60.145 63.552 60.401 93.432 ;
     RECT  60.257 52.032 60.541 62.28 ;
     RECT  60.401 90.912 60.62 93.432 ;
     RECT  60.397 94.656 60.62 94.68 ;
     RECT  60.289 2.784 60.689 3.048 ;
     RECT  60.62 90.912 60.707 94.68 ;
     RECT  60.541 52.032 60.901 62.52 ;
     RECT  60.401 63.552 60.901 89.88 ;
     RECT  60.005 4.8 60.973 35.592 ;
     RECT  60.005 36.624 60.973 50.712 ;
     RECT  60.689 2.88 61.261 3.048 ;
     RECT  60.707 90.912 61.765 93.432 ;
     RECT  61.261 2.88 61.808 3.384 ;
     RECT  60.973 4.8 61.808 50.712 ;
     RECT  60.901 52.032 61.808 89.88 ;
     RECT  61.765 90.912 61.808 93.528 ;
     RECT  60.707 94.56 61.808 94.68 ;
     RECT  61.808 2.148 61.912 95.052 ;
     RECT  61.912 2.418 62.104 94.782 ;
     RECT  62.104 71.136 62.165 94.584 ;
     RECT  62.165 71.136 62.291 93.336 ;
     RECT  62.291 90.288 62.345 93.336 ;
     RECT  62.345 90.912 62.381 93.336 ;
     RECT  62.165 94.32 62.705 94.584 ;
     RECT  62.104 4.368 62.813 70.104 ;
     RECT  62.813 4.368 63.065 50.952 ;
     RECT  62.104 2.832 63.241 3.384 ;
     RECT  63.065 4.368 63.241 50.808 ;
     RECT  62.381 92.832 63.253 93.336 ;
     RECT  62.705 94.32 63.253 94.488 ;
     RECT  63.253 92.832 63.34 94.488 ;
     RECT  62.813 51.936 63.353 70.104 ;
     RECT  63.353 52.608 63.421 70.104 ;
     RECT  62.291 71.136 63.421 89.208 ;
     RECT  62.381 90.912 63.421 91.704 ;
     RECT  63.421 52.608 63.497 91.704 ;
     RECT  63.34 94.32 63.605 94.488 ;
     RECT  63.241 2.832 63.857 50.808 ;
     RECT  63.497 91.152 63.932 91.704 ;
     RECT  63.34 92.832 63.932 93.24 ;
     RECT  63.857 2.928 64.403 50.808 ;
     RECT  64.403 4.128 64.429 50.808 ;
     RECT  63.497 52.608 64.429 89.976 ;
     RECT  64.429 4.128 64.789 89.976 ;
     RECT  63.932 91.152 64.789 93.24 ;
     RECT  64.789 4.128 64.829 93.24 ;
     RECT  64.403 2.928 64.861 3.144 ;
     RECT  64.861 2.832 64.933 3.144 ;
     RECT  63.605 94.32 64.973 94.344 ;
     RECT  64.829 23.088 65.297 93.24 ;
     RECT  64.933 2.736 65.437 3.144 ;
     RECT  64.829 4.128 65.437 22.056 ;
     RECT  65.437 2.736 65.557 22.056 ;
     RECT  65.297 67.584 65.581 93.24 ;
     RECT  65.557 2.64 65.603 22.056 ;
     RECT  65.603 4.176 65.833 22.056 ;
     RECT  65.297 23.088 65.833 66.552 ;
     RECT  65.581 67.584 66.301 94.056 ;
     RECT  66.301 67.536 66.517 94.056 ;
     RECT  65.833 4.176 66.589 66.552 ;
     RECT  66.517 67.536 66.589 94.968 ;
     RECT  65.603 2.64 66.949 3.192 ;
     RECT  66.949 2.592 67.208 3.192 ;
     RECT  66.589 4.176 67.208 94.968 ;
     RECT  67.208 2.148 67.312 95.052 ;
     RECT  67.312 2.418 67.504 94.968 ;
     RECT  67.504 2.592 67.745 3.48 ;
     RECT  67.504 90.48 67.889 94.968 ;
     RECT  67.889 90.528 68.213 94.968 ;
     RECT  68.213 90.528 68.249 94.2 ;
     RECT  68.249 90.528 68.609 91.896 ;
     RECT  68.609 90.528 68.723 91.8 ;
     RECT  67.745 2.784 68.725 3.48 ;
     RECT  67.504 4.656 68.725 89.496 ;
     RECT  68.725 2.784 68.969 89.496 ;
     RECT  68.249 92.88 69.397 94.2 ;
     RECT  68.969 2.784 69.509 89.208 ;
     RECT  69.397 92.88 69.865 94.584 ;
     RECT  69.509 5.136 70.013 89.208 ;
     RECT  68.723 90.528 70.189 91.32 ;
     RECT  69.865 92.736 70.189 94.584 ;
     RECT  70.189 90.528 70.265 94.584 ;
     RECT  70.013 70.8 70.301 89.208 ;
     RECT  69.509 2.784 70.364 3.96 ;
     RECT  70.364 2.688 70.373 3.96 ;
     RECT  70.373 2.688 70.451 3.48 ;
     RECT  70.013 5.136 70.621 69.336 ;
     RECT  70.301 88.368 70.697 89.208 ;
     RECT  70.697 88.416 70.729 89.208 ;
     RECT  70.265 90.528 70.729 94.104 ;
     RECT  70.621 4.512 70.805 69.336 ;
     RECT  70.729 88.416 70.805 94.104 ;
     RECT  70.805 88.416 71.129 91.032 ;
     RECT  71.129 88.416 71.273 90.6 ;
     RECT  70.451 2.88 71.413 3.48 ;
     RECT  70.805 4.512 71.413 5.352 ;
     RECT  70.301 70.8 71.449 87.384 ;
     RECT  70.805 6.336 71.629 69.336 ;
     RECT  71.449 70.656 71.629 87.384 ;
     RECT  70.805 92.208 71.701 94.104 ;
     RECT  71.413 2.88 71.881 5.352 ;
     RECT  71.629 6.336 71.881 87.384 ;
     RECT  71.881 2.592 72.241 87.384 ;
     RECT  71.273 88.416 72.241 89.496 ;
     RECT  72.241 2.592 72.349 89.496 ;
     RECT  71.273 90.528 72.349 90.6 ;
     RECT  72.349 2.592 72.373 90.6 ;
     RECT  72.373 2.592 72.608 90.984 ;
     RECT  71.701 92.208 72.608 94.68 ;
     RECT  72.608 2.148 72.712 95.052 ;
     RECT  72.712 2.418 72.904 94.782 ;
     RECT  72.904 91.632 73.139 94.68 ;
     RECT  72.904 2.592 73.811 90.552 ;
     RECT  73.139 91.632 74.077 94.536 ;
     RECT  74.077 91.152 74.089 94.536 ;
     RECT  73.811 2.592 74.972 90.12 ;
     RECT  74.972 2.544 75.059 90.12 ;
     RECT  74.089 93.408 75.409 94.536 ;
     RECT  74.089 91.152 75.445 92.28 ;
     RECT  75.409 93.312 75.445 94.536 ;
     RECT  75.059 2.592 75.683 90.12 ;
     RECT  75.683 2.832 75.733 90.12 ;
     RECT  75.445 91.152 75.733 94.536 ;
     RECT  75.733 2.832 75.845 94.536 ;
     RECT  75.845 2.832 75.953 94.44 ;
     RECT  75.953 2.832 76.444 93.336 ;
     RECT  76.444 85.344 76.601 93.336 ;
     RECT  75.953 94.416 76.921 94.44 ;
     RECT  76.444 2.832 76.981 84.36 ;
     RECT  76.981 2.688 77.497 84.36 ;
     RECT  77.497 2.688 77.569 84.456 ;
     RECT  76.601 85.488 77.569 93.336 ;
     RECT  77.569 2.688 78.008 93.336 ;
     RECT  76.921 94.416 78.008 94.488 ;
     RECT  78.008 2.148 78.112 95.052 ;
     RECT  78.112 2.256 78.304 94.782 ;
     RECT  78.304 2.256 78.689 94.728 ;
     RECT  78.689 2.256 79.084 89.448 ;
     RECT  78.689 90.624 79.553 94.728 ;
     RECT  79.084 2.544 79.667 89.448 ;
     RECT  79.667 2.544 80.021 67.944 ;
     RECT  80.021 2.544 80.093 31.224 ;
     RECT  80.093 2.688 80.165 31.224 ;
     RECT  79.667 69.024 80.341 89.448 ;
     RECT  79.553 90.624 80.341 94.584 ;
     RECT  80.341 69.024 80.521 94.584 ;
     RECT  80.021 32.448 80.525 67.944 ;
     RECT  80.521 69.024 80.675 94.68 ;
     RECT  80.675 69.024 80.771 92.376 ;
     RECT  80.165 2.688 80.957 30.744 ;
     RECT  80.957 2.736 81.029 30.744 ;
     RECT  80.771 69.024 81.029 91.224 ;
     RECT  80.525 49.488 81.061 67.944 ;
     RECT  81.029 69.024 81.061 91.08 ;
     RECT  80.525 32.448 81.133 48.504 ;
     RECT  81.061 49.488 81.245 91.08 ;
     RECT  80.675 93.984 81.317 94.68 ;
     RECT  81.029 14.352 81.349 30.744 ;
     RECT  81.133 31.872 81.349 48.504 ;
     RECT  81.245 49.584 81.533 91.08 ;
     RECT  81.317 93.984 81.605 94.152 ;
     RECT  80.771 92.256 81.889 92.376 ;
     RECT  81.533 70.032 82.145 91.08 ;
     RECT  81.349 14.352 82.309 48.504 ;
     RECT  81.533 49.584 82.309 69 ;
     RECT  81.029 2.736 82.397 13.32 ;
     RECT  82.397 3.312 82.46 13.32 ;
     RECT  82.309 14.352 82.46 69 ;
     RECT  81.605 94.128 82.465 94.152 ;
     RECT  82.465 94.128 82.537 94.44 ;
     RECT  82.46 3.312 82.717 69 ;
     RECT  82.145 70.032 82.717 87.576 ;
     RECT  82.717 3.312 83.149 87.576 ;
     RECT  82.145 88.656 83.149 91.08 ;
     RECT  81.889 92.256 83.149 92.808 ;
     RECT  83.149 3.312 83.408 92.808 ;
     RECT  82.537 94.128 83.408 94.584 ;
     RECT  83.408 2.148 83.512 95.052 ;
     RECT  83.512 2.352 83.704 94.782 ;
     RECT  83.704 2.352 84.089 94.584 ;
     RECT  84.089 2.352 84.197 90.936 ;
     RECT  84.197 2.352 84.593 60.6 ;
     RECT  84.593 9.6 84.701 60.6 ;
     RECT  84.197 61.776 84.845 90.936 ;
     RECT  84.701 9.888 84.989 60.6 ;
     RECT  84.989 36.048 85.025 60.6 ;
     RECT  84.845 66.576 85.025 90.936 ;
     RECT  85.025 36.384 85.196 60.6 ;
     RECT  84.845 61.776 85.196 65.544 ;
     RECT  84.593 2.352 85.349 8.424 ;
     RECT  85.025 72.048 85.489 90.936 ;
     RECT  84.089 92.064 85.489 94.584 ;
     RECT  84.989 9.888 85.601 34.728 ;
     RECT  85.601 14.112 85.925 34.728 ;
     RECT  85.925 31.728 86.053 34.728 ;
     RECT  85.349 4.464 86.209 8.424 ;
     RECT  85.196 36.384 86.245 65.544 ;
     RECT  85.025 66.576 86.245 70.968 ;
     RECT  85.601 9.888 86.321 12.936 ;
     RECT  86.209 4.464 86.389 8.904 ;
     RECT  86.321 10.32 86.429 12.936 ;
     RECT  86.245 36.384 86.465 70.968 ;
     RECT  85.489 72.048 86.465 94.584 ;
     RECT  85.349 2.352 86.497 3.432 ;
     RECT  86.389 4.464 86.497 8.952 ;
     RECT  86.465 36.48 86.545 70.968 ;
     RECT  86.545 36.624 86.569 70.968 ;
     RECT  86.465 72.048 86.569 91.176 ;
     RECT  85.925 14.112 86.645 30.6 ;
     RECT  86.569 36.624 86.681 91.176 ;
     RECT  86.053 31.728 86.749 34.824 ;
     RECT  86.497 2.352 86.789 8.952 ;
     RECT  86.681 89.52 86.861 91.176 ;
     RECT  86.681 36.624 86.897 87.96 ;
     RECT  86.861 90.672 87.185 91.176 ;
     RECT  86.645 14.112 87.257 27.384 ;
     RECT  87.257 14.112 87.293 27.288 ;
     RECT  86.465 92.208 87.329 94.584 ;
     RECT  86.861 89.52 87.365 89.544 ;
     RECT  87.329 92.208 87.365 92.904 ;
     RECT  87.293 14.112 87.401 27.24 ;
     RECT  87.185 91.152 87.433 91.176 ;
     RECT  87.365 92.208 87.433 92.712 ;
     RECT  87.433 91.152 87.437 92.712 ;
     RECT  86.429 10.32 87.644 12.888 ;
     RECT  86.645 28.512 87.649 30.6 ;
     RECT  87.649 28.416 87.685 30.6 ;
     RECT  86.749 31.728 87.685 35.064 ;
     RECT  87.644 9.936 87.731 12.888 ;
     RECT  86.789 2.352 87.761 8.904 ;
     RECT  86.897 36.624 87.901 87.912 ;
     RECT  87.761 2.4 87.973 8.904 ;
     RECT  87.685 28.416 88.045 35.064 ;
     RECT  87.901 36.624 88.045 88.296 ;
     RECT  87.731 10.32 88.117 12.888 ;
     RECT  87.401 14.112 88.117 26.904 ;
     RECT  88.045 28.416 88.297 88.296 ;
     RECT  87.329 94.08 88.369 94.584 ;
     RECT  88.117 10.32 88.585 26.904 ;
     RECT  88.309 89.952 88.621 89.976 ;
     RECT  87.437 91.68 88.621 92.712 ;
     RECT  88.585 10.32 88.657 27.192 ;
     RECT  88.297 28.416 88.657 88.776 ;
     RECT  87.973 2.4 88.808 9.288 ;
     RECT  88.657 10.32 88.808 88.776 ;
     RECT  88.621 89.952 88.808 92.712 ;
     RECT  88.369 94.08 88.808 94.68 ;
     RECT  88.808 2.148 88.912 95.052 ;
     RECT  88.912 2.418 89.104 94.782 ;
     RECT  89.104 2.88 89.309 5.688 ;
     RECT  89.104 57.6 89.417 89.064 ;
     RECT  89.309 2.88 89.453 4.488 ;
     RECT  89.104 14.112 89.489 29.64 ;
     RECT  89.489 14.112 89.525 27.912 ;
     RECT  89.104 35.76 89.561 47.112 ;
     RECT  89.309 5.52 89.603 5.688 ;
     RECT  89.561 35.76 89.849 46.92 ;
     RECT  89.417 57.6 89.885 86.04 ;
     RECT  89.603 5.664 89.957 5.688 ;
     RECT  89.885 65.952 89.957 86.04 ;
     RECT  89.885 57.6 89.993 64.824 ;
     RECT  89.957 65.952 90.029 78.504 ;
     RECT  89.957 79.488 90.029 86.04 ;
     RECT  89.104 94.464 90.083 94.776 ;
     RECT  89.453 3.12 90.101 4.488 ;
     RECT  89.104 30.864 90.101 34.728 ;
     RECT  90.029 78.48 90.137 78.504 ;
     RECT  89.525 14.112 90.173 27.192 ;
     RECT  89.849 35.76 90.227 37.656 ;
     RECT  90.101 31.248 90.277 34.728 ;
     RECT  90.227 35.76 90.277 36.12 ;
     RECT  90.227 37.344 90.353 37.656 ;
     RECT  89.849 38.64 90.353 46.92 ;
     RECT  90.029 80.064 90.353 86.04 ;
     RECT  90.101 3.12 90.371 4.44 ;
     RECT  90.083 94.464 90.389 94.632 ;
     RECT  89.104 6.816 90.421 13.032 ;
     RECT  89.104 48.144 90.421 56.568 ;
     RECT  89.993 57.6 90.421 64.248 ;
     RECT  90.421 48.144 90.425 64.248 ;
     RECT  90.425 59.52 90.461 64.248 ;
     RECT  89.104 90.336 90.461 92.952 ;
     RECT  89.417 87.36 90.493 89.064 ;
     RECT  90.277 31.248 90.515 36.12 ;
     RECT  90.353 85.92 90.517 86.04 ;
     RECT  90.493 87.36 90.517 89.448 ;
     RECT  90.461 90.528 90.524 92.952 ;
     RECT  90.425 48.144 90.601 53.592 ;
     RECT  90.524 90.528 90.611 93.528 ;
     RECT  90.421 5.808 90.641 13.032 ;
     RECT  90.029 65.952 90.641 77.16 ;
     RECT  90.371 3.12 90.677 3.432 ;
     RECT  90.425 54.576 90.677 58.536 ;
     RECT  90.389 94.608 90.677 94.632 ;
     RECT  90.353 38.784 90.7 46.92 ;
     RECT  90.677 3.12 90.713 3.144 ;
     RECT  90.173 15.456 90.713 27.192 ;
     RECT  90.7 46.608 90.745 46.92 ;
     RECT  90.601 48 90.745 53.592 ;
     RECT  90.641 67.392 90.749 77.16 ;
     RECT  90.611 90.528 90.749 92.952 ;
     RECT  90.371 4.416 90.785 4.44 ;
     RECT  90.713 15.456 90.785 18.984 ;
     RECT  90.713 20.16 90.785 27.192 ;
     RECT  90.641 6.24 90.821 13.032 ;
     RECT  90.785 21.168 90.821 27.192 ;
     RECT  90.749 70.704 90.821 77.16 ;
     RECT  89.489 28.944 90.853 29.64 ;
     RECT  90.821 7.2 90.857 13.032 ;
     RECT  90.7 38.784 90.929 45.576 ;
     RECT  90.749 67.392 90.965 69.336 ;
     RECT  90.517 85.92 90.965 89.448 ;
     RECT  90.785 15.456 91.001 16.104 ;
     RECT  90.821 21.168 91.001 26.76 ;
     RECT  90.965 85.92 91.001 88.344 ;
     RECT  90.461 60 91.033 64.248 ;
     RECT  90.677 54.576 91.037 56.52 ;
     RECT  90.821 70.8 91.037 77.16 ;
     RECT  90.515 31.68 91.043 36.12 ;
     RECT  91.001 15.456 91.073 16.056 ;
     RECT  90.785 17.136 91.073 18.984 ;
     RECT  91.043 31.68 91.073 35.928 ;
     RECT  90.857 7.2 91.109 7.608 ;
     RECT  91.073 18.768 91.109 18.984 ;
     RECT  90.785 20.16 91.109 20.184 ;
     RECT  90.353 80.064 91.109 84.888 ;
     RECT  90.173 14.112 91.141 14.232 ;
     RECT  91.073 15.456 91.141 15.864 ;
     RECT  91.001 21.168 91.145 24.744 ;
     RECT  90.929 41.184 91.145 45.576 ;
     RECT  90.749 90.528 91.181 90.888 ;
     RECT  91.141 14.112 91.253 15.864 ;
     RECT  91.145 41.184 91.253 45.384 ;
     RECT  90.745 46.608 91.253 53.592 ;
     RECT  91.037 54.576 91.253 56.04 ;
     RECT  91.109 80.064 91.253 84.408 ;
     RECT  91.109 7.584 91.289 7.608 ;
     RECT  91.037 70.8 91.325 76.824 ;
     RECT  91.253 80.064 91.325 84.36 ;
     RECT  91.109 18.768 91.361 18.84 ;
     RECT  90.929 38.784 91.361 39.816 ;
     RECT  91.325 71.184 91.361 76.824 ;
     RECT  90.353 37.344 91.393 37.368 ;
     RECT  90.857 9.12 91.397 13.032 ;
     RECT  91.361 38.784 91.397 38.808 ;
     RECT  91.253 41.952 91.397 45.384 ;
     RECT  90.965 67.536 91.397 69.336 ;
     RECT  90.965 89.376 91.397 89.448 ;
     RECT  91.001 26.016 91.433 26.76 ;
     RECT  91.073 31.68 91.433 34.776 ;
     RECT  91.397 42.144 91.433 45.384 ;
     RECT  91.253 14.112 91.505 15.576 ;
     RECT  91.433 42.144 91.505 45 ;
     RECT  91.001 86.592 91.505 88.344 ;
     RECT  91.253 47.28 91.537 53.592 ;
     RECT  91.253 54.576 91.537 55.848 ;
     RECT  91.505 42.144 91.541 43.848 ;
     RECT  91.397 11.328 91.577 13.032 ;
     RECT  91.397 67.536 91.577 67.752 ;
     RECT  90.677 57.696 91.609 58.536 ;
     RECT  91.505 86.592 91.613 87.288 ;
     RECT  91.361 39.792 91.649 39.816 ;
     RECT  91.537 47.28 91.66 55.848 ;
     RECT  91.325 82.272 91.667 84.36 ;
     RECT  91.505 88.272 91.667 88.344 ;
     RECT  90.749 92.064 91.667 92.952 ;
     RECT  91.505 14.112 91.685 15.096 ;
     RECT  91.577 67.536 91.685 67.704 ;
     RECT  91.361 18.768 91.721 18.792 ;
     RECT  90.853 28.128 91.721 29.64 ;
     RECT  91.181 90.576 91.721 90.888 ;
     RECT  91.397 9.12 91.757 9.864 ;
     RECT  91.073 35.904 91.757 35.928 ;
     RECT  91.613 86.592 91.757 87.096 ;
     RECT  91.073 17.136 91.789 17.784 ;
     RECT  91.577 12.48 91.793 13.032 ;
     RECT  91.789 17.04 91.793 17.784 ;
     RECT  91.325 80.064 91.793 81.048 ;
     RECT  91.393 37.2 91.813 37.368 ;
     RECT  91.033 60 91.865 64.92 ;
     RECT  91.793 80.976 91.865 81.048 ;
     RECT  91.813 37.2 91.9 38.136 ;
     RECT  91.433 26.688 91.901 26.76 ;
     RECT  91.757 9.84 91.937 9.864 ;
     RECT  90.641 65.952 91.937 65.976 ;
     RECT  90.961 79.056 91.937 79.08 ;
     RECT  91.721 28.416 91.973 29.64 ;
     RECT  91.609 57.696 92.005 58.68 ;
     RECT  91.397 68.736 92.005 69.336 ;
     RECT  91.433 32.448 92.009 34.776 ;
     RECT  91.66 49.536 92.009 55.848 ;
     RECT  91.397 89.376 92.009 89.4 ;
     RECT  91.865 63.504 92.041 64.92 ;
     RECT  91.361 76.8 92.041 76.824 ;
     RECT  91.9 37.2 92.045 37.368 ;
     RECT  92.009 49.536 92.045 49.56 ;
     RECT  91.685 15.072 92.117 15.096 ;
     RECT  91.685 67.536 92.117 67.56 ;
     RECT  92.009 32.448 92.153 34.632 ;
     RECT  92.009 50.832 92.225 55.848 ;
     RECT  91.757 87.072 92.225 87.096 ;
     RECT  92.225 51.216 92.243 55.848 ;
     RECT  91.667 82.272 92.261 84.312 ;
     RECT  91.865 81.024 92.293 81.048 ;
     RECT  92.261 82.272 92.293 82.824 ;
     RECT  92.041 63.504 92.297 65.016 ;
     RECT  92.005 57.696 92.329 58.776 ;
     RECT  92.293 81.024 92.333 82.824 ;
     RECT  91.145 21.168 92.365 24.504 ;
     RECT  91.721 90.576 92.365 90.6 ;
     RECT  92.149 30.768 92.369 30.792 ;
     RECT  92.243 51.456 92.369 55.848 ;
     RECT  92.297 63.84 92.369 65.016 ;
     RECT  91.667 88.272 92.369 88.296 ;
     RECT  92.329 57.552 92.396 58.776 ;
     RECT  91.865 60 92.396 62.472 ;
     RECT  91.901 26.688 92.405 26.712 ;
     RECT  92.396 57.552 92.405 62.472 ;
     RECT  92.005 68.736 92.405 69.48 ;
     RECT  92.041 76.8 92.405 76.92 ;
     RECT  92.333 81.024 92.405 82.296 ;
     RECT  91.793 13.008 92.441 13.032 ;
     RECT  92.405 62.4 92.477 62.472 ;
     RECT  92.405 57.552 92.483 60.168 ;
     RECT  92.483 59.712 92.513 60.168 ;
     RECT  91.577 11.328 92.545 11.4 ;
     RECT  91.541 42.144 92.549 43.32 ;
     RECT  91.361 71.184 92.549 75.816 ;
     RECT  91.66 47.28 92.621 48.168 ;
     RECT  92.153 32.448 92.657 32.664 ;
     RECT  92.483 57.792 92.693 58.44 ;
     RECT  92.261 84.288 92.729 84.312 ;
     RECT  91.973 28.416 92.765 29.592 ;
     RECT  92.477 62.448 92.765 62.472 ;
     RECT  92.405 68.88 92.801 69.48 ;
     RECT  92.077 20.064 92.833 20.088 ;
     RECT  92.365 21.12 92.833 24.504 ;
     RECT  92.765 29.136 92.837 29.592 ;
     RECT  91.793 17.04 92.869 17.064 ;
     RECT  92.405 81.024 92.869 81.432 ;
     RECT  91.505 44.976 92.941 45 ;
     RECT  92.549 71.184 92.941 75.432 ;
     RECT  92.405 76.8 92.945 76.824 ;
     RECT  92.689 87.792 92.945 87.816 ;
     RECT  92.365 90.048 92.977 90.6 ;
     RECT  92.185 91.872 92.977 91.896 ;
     RECT  92.837 29.376 92.981 29.592 ;
     RECT  92.369 63.84 93.053 64.968 ;
     RECT  92.869 18.336 93.085 18.36 ;
     RECT  92.549 42.144 93.157 42.744 ;
     RECT  92.941 44.112 93.161 45 ;
     RECT  92.833 20.064 93.193 24.504 ;
     RECT  92.369 51.456 93.233 55.704 ;
     RECT  93.053 63.84 93.233 64.392 ;
     RECT  92.153 33.792 93.481 34.632 ;
     RECT  93.233 51.456 93.481 55.464 ;
     RECT  93.481 33.264 93.541 34.632 ;
     RECT  92.797 35.856 93.541 35.88 ;
     RECT  92.869 17.04 93.589 17.112 ;
     RECT  92.725 31.92 93.661 31.944 ;
     RECT  93.589 17.04 93.769 17.16 ;
     RECT  93.481 50.832 93.805 55.464 ;
     RECT  93.769 16.848 93.877 17.16 ;
     RECT  93.085 18.288 93.877 18.36 ;
     RECT  92.801 69.456 93.913 69.48 ;
     RECT  93.481 10.128 94.021 10.152 ;
     RECT  92.545 11.136 94.021 11.4 ;
     RECT  93.157 41.808 94.165 42.744 ;
     RECT  93.161 44.112 94.201 44.376 ;
     RECT  94.021 10.128 94.208 11.4 ;
     RECT  93.877 16.848 94.208 18.36 ;
     RECT  93.193 20.064 94.208 25.032 ;
     RECT  92.981 29.568 94.208 29.592 ;
     RECT  93.661 31.872 94.208 31.944 ;
     RECT  93.541 33.264 94.208 35.88 ;
     RECT  92.045 37.2 94.208 37.224 ;
     RECT  94.165 41.424 94.208 42.744 ;
     RECT  94.201 44.112 94.208 44.424 ;
     RECT  92.621 48.144 94.208 48.168 ;
     RECT  93.805 50.544 94.208 55.464 ;
     RECT  92.513 59.712 94.208 59.736 ;
     RECT  93.913 62.448 94.208 62.472 ;
     RECT  93.233 64.368 94.208 64.392 ;
     RECT  94.057 66.72 94.208 66.84 ;
     RECT  93.913 68.928 94.208 69.48 ;
     RECT  92.941 70.992 94.208 75.432 ;
     RECT  92.473 79.776 94.208 79.8 ;
     RECT  92.869 80.928 94.208 81.432 ;
     RECT  93.337 87.936 94.208 87.96 ;
     RECT  92.977 90.048 94.208 91.896 ;
     RECT  91.667 92.928 94.208 92.952 ;
     RECT  94.208 2.148 94.312 95.052 ;
     RECT  94.312 2.418 94.504 94.782 ;
     RECT  94.504 34.08 94.529 34.104 ;
     RECT  94.504 73.824 94.601 76.68 ;
     RECT  94.504 16.176 94.637 18.792 ;
     RECT  94.504 67.296 94.637 69.48 ;
     RECT  94.637 67.44 94.745 69.48 ;
     RECT  94.504 82.272 94.781 84.648 ;
     RECT  94.504 24.816 95.533 25.416 ;
     RECT  94.504 20.064 95.605 23.4 ;
     RECT  95.533 24.816 95.605 25.608 ;
     RECT  94.504 9.936 95.641 11.784 ;
     RECT  94.504 70.704 95.641 72.744 ;
     RECT  94.601 73.824 95.641 74.952 ;
     RECT  94.504 39.696 95.713 45 ;
     RECT  94.504 53.28 95.713 55.56 ;
     RECT  94.745 69.072 95.713 69.48 ;
     RECT  95.641 70.704 95.713 74.952 ;
     RECT  94.601 76.08 95.713 76.68 ;
     RECT  94.637 16.176 95.749 17.16 ;
     RECT  95.605 20.064 95.749 25.896 ;
     RECT  95.713 39.696 95.749 45.096 ;
     RECT  94.781 82.992 95.749 84.648 ;
     RECT  94.745 67.44 96.073 68.04 ;
     RECT  95.713 69.072 96.073 76.68 ;
     RECT  94.504 49.776 96.217 52.008 ;
     RECT  95.713 53.04 96.217 55.56 ;
     RECT  95.641 9.936 96.253 12.552 ;
     RECT  95.749 16.08 96.253 17.16 ;
     RECT  94.637 18.192 96.253 18.792 ;
     RECT  95.749 82.896 96.289 84.648 ;
     RECT  96.217 49.776 96.325 55.56 ;
     RECT  96.073 67.44 96.721 76.68 ;
     RECT  96.289 82.896 96.793 85.416 ;
     RECT  96.721 67.44 96.833 76.92 ;
     RECT  95.749 39.12 96.937 45.096 ;
     RECT  96.325 49.68 96.973 55.56 ;
     RECT  96.253 16.08 97.009 18.888 ;
     RECT  95.749 19.92 97.009 25.896 ;
     RECT  97.009 16.08 97.045 25.992 ;
     RECT  96.833 67.44 97.121 76.68 ;
     RECT  97.045 16.08 97.157 26.232 ;
     RECT  96.253 9.936 97.164 12.936 ;
     RECT  97.157 16.08 97.164 25.992 ;
     RECT  96.937 39.12 97.164 45.192 ;
     RECT  94.504 48.144 97.164 48.168 ;
     RECT  96.973 49.68 97.164 55.848 ;
     RECT  97.121 67.536 97.164 76.68 ;
     RECT  96.793 82.896 97.164 85.512 ;
    LAYER M5 ;
     RECT  3.792 0.016 10.248 1.187 ;
     RECT  4.08 1.187 10.248 1.763 ;
     RECT  2.4 2.137 2.52 2.151 ;
     RECT  13.2 2.137 13.32 2.151 ;
     RECT  18.6 2.137 18.72 2.151 ;
     RECT  24 2.137 24.12 2.151 ;
     RECT  29.4 2.137 29.52 2.151 ;
     RECT  34.8 2.137 34.92 2.151 ;
     RECT  40.2 2.137 40.32 2.151 ;
     RECT  45.6 2.137 45.72 2.151 ;
     RECT  51 2.137 51.12 2.151 ;
     RECT  56.4 2.137 56.52 2.151 ;
     RECT  61.8 2.137 61.92 2.151 ;
     RECT  67.2 2.137 67.32 2.151 ;
     RECT  72.6 2.137 72.72 2.151 ;
     RECT  78 2.137 78.12 2.151 ;
     RECT  83.4 2.137 83.52 2.151 ;
     RECT  88.8 2.137 88.92 2.151 ;
     RECT  94.2 2.137 94.32 2.151 ;
     RECT  2.4 2.151 2.712 2.245 ;
     RECT  29.4 2.151 29.712 2.245 ;
     RECT  78 2.151 78.312 2.245 ;
     RECT  4.368 1.763 9.96 2.291 ;
     RECT  75.024 2.533 75.048 2.581 ;
     RECT  83.4 2.151 83.712 2.677 ;
     RECT  40.2 2.151 40.512 2.821 ;
     RECT  44.304 2.245 44.328 2.867 ;
     RECT  34.8 2.151 35.112 2.869 ;
     RECT  11.28 2.485 11.304 2.915 ;
     RECT  29.4 2.245 30.504 2.915 ;
     RECT  33.6 2.245 33.624 2.915 ;
     RECT  45.6 2.151 45.912 3.013 ;
     RECT  75.024 2.581 75.672 3.157 ;
     RECT  75.024 3.157 75.816 3.203 ;
     RECT  34.8 2.869 35.208 3.301 ;
     RECT  52.896 3.109 52.92 3.301 ;
     RECT  70.416 2.677 70.44 3.347 ;
     RECT  18.6 2.151 18.912 3.397 ;
     RECT  5.328 2.291 9.96 3.443 ;
     RECT  22.464 2.869 22.488 3.443 ;
     RECT  76.992 2.677 77.016 3.443 ;
     RECT  83.4 2.677 83.832 3.443 ;
     RECT  5.424 3.443 8.616 3.491 ;
     RECT  34.8 3.301 36.12 3.539 ;
     RECT  51 2.151 51.312 3.541 ;
     RECT  52.896 3.301 53.064 3.541 ;
     RECT  20.832 2.629 20.856 3.587 ;
     RECT  5.52 3.491 8.616 3.683 ;
     RECT  29.4 2.915 29.712 3.685 ;
     RECT  51 3.541 53.064 3.733 ;
     RECT  2.4 2.245 2.808 3.925 ;
     RECT  78 2.245 79.032 3.925 ;
     RECT  90.336 3.397 90.36 3.971 ;
     RECT  63.6 3.109 63.624 3.973 ;
     RECT  5.712 3.683 8.616 4.019 ;
     RECT  50.64 3.733 53.064 4.019 ;
     RECT  75.792 3.203 75.816 4.019 ;
     RECT  9.936 3.443 9.96 4.115 ;
     RECT  45.6 3.013 46.68 4.115 ;
     RECT  83.4 3.443 83.712 4.117 ;
     RECT  88.8 2.151 89.112 4.165 ;
     RECT  2.4 3.925 2.856 4.211 ;
     RECT  54.768 2.677 54.792 4.309 ;
     RECT  39.264 2.821 40.512 4.403 ;
     RECT  26.448 2.677 26.472 4.405 ;
     RECT  27.504 3.397 27.528 4.405 ;
     RECT  54.576 4.309 54.792 4.453 ;
     RECT  34.8 3.539 35.112 4.501 ;
     RECT  45.6 4.115 45.912 4.501 ;
     RECT  36.096 3.539 36.12 4.597 ;
     RECT  26.448 4.405 27.528 4.643 ;
     RECT  54.48 4.453 54.792 4.643 ;
     RECT  65.568 2.629 65.592 4.645 ;
     RECT  68.736 3.925 68.76 4.645 ;
     RECT  65.568 4.645 65.976 4.691 ;
     RECT  87.168 4.117 87.192 4.693 ;
     RECT  72.6 2.151 72.912 4.885 ;
     RECT  36.096 4.597 37.08 4.931 ;
     RECT  78 3.925 79.656 4.931 ;
     RECT  61.8 2.151 62.112 4.933 ;
     RECT  78 4.931 78.312 5.029 ;
     RECT  61.488 4.933 62.112 5.077 ;
     RECT  67.2 2.151 67.512 5.077 ;
     RECT  68.736 4.645 69.288 5.077 ;
     RECT  77.52 5.029 78.312 5.077 ;
     RECT  83.184 4.117 83.712 5.077 ;
     RECT  28.656 3.685 29.712 5.123 ;
     RECT  50.64 4.019 52.92 5.171 ;
     RECT  67.2 5.077 69.288 5.171 ;
     RECT  59.232 2.677 59.256 5.173 ;
     RECT  45.36 4.501 45.912 5.219 ;
     RECT  58.56 5.173 59.256 5.219 ;
     RECT  67.2 5.171 68.76 5.219 ;
     RECT  51 5.171 52.92 5.365 ;
     RECT  54.48 4.643 54.504 5.365 ;
     RECT  56.4 2.151 56.712 5.365 ;
     RECT  37.056 4.931 37.08 5.459 ;
     RECT  65.952 4.691 65.976 5.459 ;
     RECT  72.6 4.885 73.752 5.459 ;
     RECT  86.64 4.693 87.192 5.461 ;
     RECT  88.8 4.165 89.592 5.461 ;
     RECT  86.64 5.461 89.592 5.555 ;
     RECT  42.768 3.733 42.792 5.603 ;
     RECT  87.168 5.555 89.592 5.653 ;
     RECT  26.736 4.643 27.528 5.699 ;
     RECT  2.4 4.211 2.808 5.747 ;
     RECT  5.712 4.019 8.112 5.747 ;
     RECT  61.008 5.077 62.112 5.747 ;
     RECT  56.4 5.365 56.808 5.989 ;
     RECT  56.016 5.989 56.808 6.037 ;
     RECT  61.488 5.747 62.112 6.133 ;
     RECT  63.6 3.973 64.392 6.133 ;
     RECT  39.84 4.403 40.512 6.179 ;
     RECT  81.456 5.077 81.48 6.179 ;
     RECT  61.488 6.133 64.392 6.181 ;
     RECT  79.488 4.931 79.656 6.229 ;
     RECT  70.464 5.173 70.488 6.277 ;
     RECT  10.944 5.221 10.968 6.517 ;
     RECT  77.184 5.077 78.312 6.517 ;
     RECT  79.392 6.229 79.656 6.517 ;
     RECT  58.56 5.219 58.584 6.563 ;
     RECT  67.2 5.219 68.328 6.613 ;
     RECT  87.168 5.653 89.928 6.659 ;
     RECT  18.6 3.397 19.416 6.661 ;
     RECT  24 2.151 24.312 6.661 ;
     RECT  72.6 5.459 73.56 6.709 ;
     RECT  27.504 5.699 27.528 6.803 ;
     RECT  4.896 6.661 4.92 6.805 ;
     RECT  6.144 5.747 8.112 6.805 ;
     RECT  66.672 6.613 68.328 6.805 ;
     RECT  61.488 6.181 64.968 6.851 ;
     RECT  4.896 6.805 8.112 6.899 ;
     RECT  43.008 6.133 43.032 6.899 ;
     RECT  51 5.365 54.504 6.899 ;
     RECT  64.944 6.851 64.968 6.899 ;
     RECT  88.032 6.659 89.928 6.899 ;
     RECT  10.656 6.517 10.968 6.997 ;
     RECT  70.416 6.277 70.488 7.043 ;
     RECT  56.016 6.037 57.048 7.093 ;
     RECT  10.656 6.997 11.4 7.187 ;
     RECT  24 6.661 24.6 7.283 ;
     RECT  66.192 6.805 68.328 7.285 ;
     RECT  56.016 7.093 57.48 7.331 ;
     RECT  70.416 7.043 70.44 7.331 ;
     RECT  22.224 6.661 22.248 7.379 ;
     RECT  54.48 6.899 54.504 7.379 ;
     RECT  4.896 6.899 5.688 7.475 ;
     RECT  33.408 6.229 33.432 7.475 ;
     RECT  51 6.899 53.208 7.475 ;
     RECT  83.184 5.077 84.696 7.475 ;
     RECT  45.6 5.219 45.912 7.477 ;
     RECT  56.4 7.331 57.48 7.619 ;
     RECT  29.4 5.123 29.712 7.765 ;
     RECT  17.328 3.829 17.352 7.813 ;
     RECT  16.512 7.813 17.352 7.859 ;
     RECT  54.528 7.429 54.552 7.861 ;
     RECT  77.184 6.517 79.656 7.909 ;
     RECT  76.944 7.909 79.656 7.955 ;
     RECT  45.6 7.477 46.104 7.957 ;
     RECT  72.6 6.709 74.136 7.957 ;
     RECT  88.032 6.899 89.592 7.957 ;
     RECT  72.6 7.957 74.664 8.003 ;
     RECT  66.192 7.285 69 8.099 ;
     RECT  31.92 7.957 31.944 8.195 ;
     RECT  78 7.955 79.656 8.243 ;
     RECT  83.232 7.475 84.696 8.243 ;
     RECT  40.2 6.179 40.512 8.293 ;
     RECT  81.888 7.189 81.912 8.339 ;
     RECT  86.64 7.525 86.664 8.435 ;
     RECT  10.656 7.187 10.68 8.437 ;
     RECT  11.712 7.237 11.736 8.437 ;
     RECT  74.112 8.003 74.664 8.437 ;
     RECT  40.2 8.293 40.632 8.485 ;
     RECT  61.488 6.851 63.624 8.485 ;
     RECT  88.032 7.957 89.736 8.531 ;
     RECT  74.112 8.437 75.432 8.627 ;
     RECT  5.664 7.475 5.688 8.629 ;
     RECT  5.568 8.629 5.688 8.675 ;
     RECT  26.208 7.861 26.232 8.675 ;
     RECT  45.6 7.957 46.152 8.723 ;
     RECT  24 7.283 24.312 8.725 ;
     RECT  9.696 8.437 11.736 8.771 ;
     RECT  16.512 7.859 17.112 8.867 ;
     RECT  6.912 6.899 8.112 8.917 ;
     RECT  51 7.475 52.92 8.917 ;
     RECT  45.6 8.723 46.104 8.965 ;
     RECT  54.528 7.861 55.272 8.965 ;
     RECT  56.4 7.619 57.048 8.965 ;
     RECT  54.528 8.965 57.048 9.011 ;
     RECT  78 8.243 79.272 9.011 ;
     RECT  6.912 8.917 8.232 9.059 ;
     RECT  60.96 8.485 63.624 9.107 ;
     RECT  9.696 8.771 9.72 9.155 ;
     RECT  45.312 8.965 46.104 9.155 ;
     RECT  40.08 8.485 40.632 9.205 ;
     RECT  54.528 9.011 56.808 9.347 ;
     RECT  61.488 9.107 63.624 9.491 ;
     RECT  42.576 9.013 42.6 9.493 ;
     RECT  42.576 9.493 42.792 9.539 ;
     RECT  45.312 9.155 45.912 9.539 ;
     RECT  61.632 9.491 63.624 9.541 ;
     RECT  80.256 8.533 80.28 9.541 ;
     RECT  80.16 9.541 80.28 9.587 ;
     RECT  61.632 9.541 63.864 9.637 ;
     RECT  23.376 8.725 24.312 9.683 ;
     RECT  27.744 7.765 29.712 9.731 ;
     RECT  10.848 8.771 11.736 9.829 ;
     RECT  66.192 8.099 68.328 9.829 ;
     RECT  65.328 9.829 68.328 9.875 ;
     RECT  51 8.917 53.304 9.925 ;
     RECT  88.176 8.531 89.736 9.925 ;
     RECT  51 9.925 53.4 9.973 ;
     RECT  54.528 9.347 56.712 9.973 ;
     RECT  31.008 8.485 31.032 10.019 ;
     RECT  51 9.973 56.712 10.019 ;
     RECT  67.2 9.875 68.328 10.067 ;
     RECT  39.168 9.205 40.632 10.069 ;
     RECT  5.568 8.675 5.592 10.165 ;
     RECT  72.6 8.003 72.912 10.165 ;
     RECT  59.088 10.069 59.112 10.211 ;
     RECT  10.8 9.829 11.736 10.307 ;
     RECT  47.856 8.437 47.88 10.307 ;
     RECT  61.632 9.637 63.912 10.307 ;
     RECT  80.16 9.587 80.184 10.355 ;
     RECT  83.232 8.243 83.712 10.355 ;
     RECT  51 10.019 54.168 10.357 ;
     RECT  72.48 10.165 72.912 10.357 ;
     RECT  76.944 7.955 76.968 10.405 ;
     RECT  5.568 10.165 5.64 10.453 ;
     RECT  6.912 9.059 8.112 10.453 ;
     RECT  18.6 6.661 19.464 10.501 ;
     RECT  27.744 9.731 27.768 10.501 ;
     RECT  10.896 10.307 11.736 10.597 ;
     RECT  76.608 10.405 76.968 10.597 ;
     RECT  78 9.011 78.648 10.597 ;
     RECT  16.512 8.867 16.536 10.883 ;
     RECT  42.768 9.539 42.792 10.883 ;
     RECT  50.736 10.357 54.168 10.883 ;
     RECT  33.12 10.789 33.144 10.933 ;
     RECT  5.568 10.453 8.112 10.981 ;
     RECT  58.944 10.213 58.968 10.981 ;
     RECT  9.648 10.213 9.672 11.027 ;
     RECT  39.168 10.069 41.496 11.027 ;
     RECT  31.92 10.069 31.944 11.029 ;
     RECT  33.072 10.933 33.144 11.029 ;
     RECT  13.2 2.151 13.512 11.125 ;
     RECT  87.696 9.925 89.736 11.171 ;
     RECT  24 9.683 24.312 11.173 ;
     RECT  31.92 11.029 33.144 11.173 ;
     RECT  34.608 4.501 35.112 11.173 ;
     RECT  27.552 10.501 27.768 11.363 ;
     RECT  76.608 10.597 78.648 11.365 ;
     RECT  5.568 10.981 8.472 11.411 ;
     RECT  18.144 10.501 19.464 11.411 ;
     RECT  0.144 10.741 0.168 11.413 ;
     RECT  31.92 11.173 35.112 11.459 ;
     RECT  39.984 11.027 41.496 11.459 ;
     RECT  50.736 10.883 52.92 11.459 ;
     RECT  76.608 11.365 78.696 11.459 ;
     RECT  61.632 10.307 63.864 11.461 ;
     RECT  52.896 11.459 52.92 11.507 ;
     RECT  72.432 10.357 72.912 11.555 ;
     RECT  50.736 11.459 51.864 11.653 ;
     RECT  7.392 11.411 8.472 11.699 ;
     RECT  27.744 11.363 27.768 11.699 ;
     RECT  54.144 10.883 54.168 11.699 ;
     RECT  74.592 8.627 75.432 11.701 ;
     RECT  61.296 11.461 63.864 11.845 ;
     RECT  65.328 9.875 66.216 11.845 ;
     RECT  67.2 10.067 67.944 11.845 ;
     RECT  58.32 10.981 58.968 11.891 ;
     RECT  61.296 11.845 64.296 11.939 ;
     RECT  0.144 11.413 0.264 11.941 ;
     RECT  65.328 11.845 67.944 11.941 ;
     RECT  29.088 9.731 29.712 11.987 ;
     RECT  65.328 11.941 68.856 11.987 ;
     RECT  45.6 9.539 45.912 11.989 ;
     RECT  55.344 10.019 56.712 11.989 ;
     RECT  5.568 11.411 5.592 12.035 ;
     RECT  25.68 10.837 25.704 12.035 ;
     RECT  88.176 11.171 89.736 12.035 ;
     RECT  7.392 11.699 8.112 12.131 ;
     RECT  18.6 11.411 19.464 12.133 ;
     RECT  37.632 8.485 37.656 12.227 ;
     RECT  61.296 11.939 62.856 12.227 ;
     RECT  73.92 11.701 75.432 12.277 ;
     RECT  76.608 11.459 76.632 12.277 ;
     RECT  73.92 12.277 76.632 12.323 ;
     RECT  10.896 10.597 12.12 12.325 ;
     RECT  13.104 11.125 13.512 12.325 ;
     RECT  14.544 11.317 14.568 12.325 ;
     RECT  0.144 11.941 0.408 12.371 ;
     RECT  70.272 7.429 70.296 12.373 ;
     RECT  10.896 12.325 13.512 12.467 ;
     RECT  43.104 11.413 43.128 12.467 ;
     RECT  29.4 11.987 29.712 12.517 ;
     RECT  45.6 11.989 46.728 12.517 ;
     RECT  50.208 11.653 51.864 12.517 ;
     RECT  55.344 11.989 56.808 12.563 ;
     RECT  11.712 12.467 13.512 12.611 ;
     RECT  14.544 12.325 14.808 12.707 ;
     RECT  0.144 12.371 0.312 12.755 ;
     RECT  23.904 11.173 24.312 12.851 ;
     RECT  61.8 12.227 62.856 13.045 ;
     RECT  63.84 11.939 64.296 13.045 ;
     RECT  68.832 11.987 68.856 13.045 ;
     RECT  69.936 12.373 70.296 13.045 ;
     RECT  65.328 11.987 67.848 13.091 ;
     RECT  29.4 12.517 29.832 13.139 ;
     RECT  32.784 11.459 32.808 13.139 ;
     RECT  61.8 13.045 64.296 13.139 ;
     RECT  68.832 13.045 70.296 13.139 ;
     RECT  73.92 12.323 76.392 13.139 ;
     RECT  50.16 12.517 51.864 13.235 ;
     RECT  56.4 12.563 56.808 13.237 ;
     RECT  44.784 12.517 46.728 13.331 ;
     RECT  0.144 12.755 0.168 13.379 ;
     RECT  74.496 13.139 76.392 13.427 ;
     RECT  45.024 13.331 46.728 13.523 ;
     RECT  88.272 12.035 89.736 13.525 ;
     RECT  78 11.459 78.696 13.619 ;
     RECT  65.328 13.091 67.512 13.811 ;
     RECT  58.944 11.891 58.968 13.909 ;
     RECT  45.024 13.523 45.912 13.955 ;
     RECT  33.888 11.459 35.112 13.957 ;
     RECT  24 12.851 24.312 14.005 ;
     RECT  60.672 13.045 60.696 14.099 ;
     RECT  7.8 12.131 8.112 14.101 ;
     RECT  24 14.005 24.456 14.101 ;
     RECT  88.128 13.525 89.736 14.147 ;
     RECT  9.12 13.717 9.144 14.195 ;
     RECT  45.12 13.955 45.912 14.195 ;
     RECT  58.704 13.909 58.968 14.195 ;
     RECT  58.896 14.195 58.968 14.197 ;
     RECT  83.28 10.355 83.712 14.197 ;
     RECT  2.4 5.747 2.712 14.245 ;
     RECT  61.8 13.139 64.248 14.291 ;
     RECT  55.344 12.563 55.368 14.389 ;
     RECT  56.4 13.237 57.048 14.389 ;
     RECT  79.776 12.901 79.8 14.389 ;
     RECT  33.264 13.957 35.112 14.533 ;
     RECT  74.496 13.427 75.432 14.581 ;
     RECT  55.344 14.389 57.048 14.627 ;
     RECT  2.4 14.245 3.48 14.675 ;
     RECT  69.456 13.139 70.296 14.675 ;
     RECT  82.512 14.197 83.712 14.675 ;
     RECT  72.48 11.555 72.912 14.677 ;
     RECT  74.112 14.581 75.432 14.677 ;
     RECT  31.872 13.573 31.896 14.723 ;
     RECT  72.48 14.677 75.432 14.723 ;
     RECT  79.776 14.389 80.376 14.725 ;
     RECT  47.616 14.629 47.64 14.771 ;
     RECT  45.6 14.195 45.912 14.773 ;
     RECT  50.4 13.235 51.864 14.773 ;
     RECT  55.344 14.627 56.712 14.773 ;
     RECT  58.896 14.197 59.256 14.773 ;
     RECT  58.896 14.773 59.496 14.819 ;
     RECT  59.232 14.819 59.496 14.867 ;
     RECT  69.936 14.675 70.296 14.867 ;
     RECT  79.488 14.725 80.376 14.867 ;
     RECT  86.4 14.197 86.424 14.867 ;
     RECT  16.32 13.573 16.344 14.915 ;
     RECT  75.408 14.723 75.432 14.915 ;
     RECT  7.152 14.101 8.112 15.107 ;
     RECT  54.72 14.773 56.712 15.107 ;
     RECT  66.384 13.811 67.512 15.301 ;
     RECT  12.528 12.611 13.512 15.349 ;
     RECT  14.544 12.707 14.568 15.349 ;
     RECT  72.48 14.723 74.184 15.349 ;
     RECT  82.128 14.773 82.152 15.349 ;
     RECT  33.168 14.533 35.112 15.395 ;
     RECT  61.8 14.291 64.2 15.395 ;
     RECT  36.72 14.245 36.744 15.443 ;
     RECT  81.456 15.349 82.152 15.443 ;
     RECT  83.28 14.675 83.712 15.443 ;
     RECT  27.936 14.677 27.96 15.445 ;
     RECT  5.856 13.285 5.88 15.539 ;
     RECT  12.528 15.349 14.568 15.539 ;
     RECT  59.472 14.867 59.496 15.539 ;
     RECT  70.128 14.867 70.296 15.587 ;
     RECT  50.4 14.773 52.824 15.779 ;
     RECT  70.128 15.587 70.152 15.779 ;
     RECT  61.8 15.395 63.048 15.829 ;
     RECT  65.328 13.811 65.352 15.829 ;
     RECT  66.384 15.301 67.848 15.829 ;
     RECT  33.264 15.395 35.112 15.923 ;
     RECT  41.952 14.677 41.976 15.971 ;
     RECT  39.984 11.459 40.512 15.973 ;
     RECT  2.4 14.675 3.192 16.019 ;
     RECT  23.04 14.101 24.456 16.019 ;
     RECT  88.272 14.147 89.544 16.019 ;
     RECT  50.592 15.779 52.824 16.259 ;
     RECT  17.568 15.061 17.592 16.261 ;
     RECT  27.936 15.445 28.248 16.261 ;
     RECT  17.136 16.261 17.592 16.307 ;
     RECT  81.456 15.443 81.48 16.403 ;
     RECT  45.6 14.773 46.248 16.405 ;
     RECT  27.504 16.261 28.248 16.453 ;
     RECT  29.4 13.139 29.712 16.453 ;
     RECT  4.224 15.973 4.248 16.501 ;
     RECT  5.28 16.453 5.304 16.501 ;
     RECT  7.8 15.107 8.112 16.501 ;
     RECT  65.328 15.829 67.848 16.501 ;
     RECT  79.488 14.867 79.512 16.501 ;
     RECT  9.12 15.973 9.144 16.547 ;
     RECT  26.256 14.101 26.28 16.547 ;
     RECT  72.24 15.349 74.184 16.547 ;
     RECT  27.504 16.453 29.712 16.597 ;
     RECT  4.224 16.501 5.304 16.643 ;
     RECT  52.8 16.259 52.824 16.693 ;
     RECT  27.312 16.597 29.712 16.739 ;
     RECT  27.504 16.739 29.712 16.835 ;
     RECT  52.8 16.693 53.016 16.835 ;
     RECT  45.6 16.405 46.584 16.931 ;
     RECT  17.136 16.307 17.208 16.933 ;
     RECT  13.2 15.539 14.568 17.029 ;
     RECT  29.04 16.835 29.712 17.075 ;
     RECT  31.872 15.877 31.896 17.075 ;
     RECT  56.4 15.107 56.712 17.077 ;
     RECT  57.696 16.789 57.72 17.077 ;
     RECT  76.896 16.981 76.92 17.077 ;
     RECT  78 13.619 78.504 17.077 ;
     RECT  6.864 16.501 8.112 17.123 ;
     RECT  76.032 17.077 78.504 17.123 ;
     RECT  10.848 17.029 10.872 17.171 ;
     RECT  17.04 16.933 17.208 17.219 ;
     RECT  4.224 16.643 4.584 17.315 ;
     RECT  88.272 16.019 89.112 17.315 ;
     RECT  13.104 17.029 14.856 17.363 ;
     RECT  56.4 17.077 57.72 17.363 ;
     RECT  50.592 16.259 51.528 17.413 ;
     RECT  64.176 15.395 64.2 17.605 ;
     RECT  65.328 16.501 68.328 17.605 ;
     RECT  47.52 17.077 47.544 17.651 ;
     RECT  2.4 16.019 2.712 17.653 ;
     RECT  18.6 12.133 19.704 17.699 ;
     RECT  76.032 17.123 76.056 17.699 ;
     RECT  24 16.019 24.456 17.701 ;
     RECT  72.48 16.547 74.184 17.891 ;
     RECT  77.808 17.123 78.504 17.891 ;
     RECT  70.656 17.077 70.68 17.939 ;
     RECT  54.72 15.107 55.368 18.037 ;
     RECT  56.4 17.363 56.712 18.037 ;
     RECT  4.56 17.315 4.584 18.085 ;
     RECT  4.56 18.085 4.824 18.131 ;
     RECT  64.176 17.605 69.048 18.179 ;
     RECT  61.584 15.829 63.048 18.181 ;
     RECT  78 17.891 78.504 18.181 ;
     RECT  79.488 16.501 80.088 18.181 ;
     RECT  33.888 15.923 35.112 18.229 ;
     RECT  60.384 17.605 60.408 18.469 ;
     RECT  54.72 18.037 56.712 18.515 ;
     RECT  72.48 17.891 73.896 18.515 ;
     RECT  33.888 18.229 35.208 18.565 ;
     RECT  27.504 16.835 28.056 18.611 ;
     RECT  39.6 15.973 40.512 18.709 ;
     RECT  56.064 18.515 56.712 18.709 ;
     RECT  57.696 17.363 57.72 18.709 ;
     RECT  83.4 15.443 83.712 18.709 ;
     RECT  4.8 18.131 4.824 18.757 ;
     RECT  13.2 17.363 14.856 18.757 ;
     RECT  88.8 17.315 89.112 18.757 ;
     RECT  12.336 18.757 14.856 18.803 ;
     RECT  61.536 18.181 63.048 18.851 ;
     RECT  64.176 18.179 65.784 18.851 ;
     RECT  59.904 18.469 60.408 18.947 ;
     RECT  56.064 18.709 57.72 19.139 ;
     RECT  88.08 18.757 89.112 19.235 ;
     RECT  56.4 19.139 57.72 19.285 ;
     RECT  78 18.181 80.088 19.333 ;
     RECT  56.4 19.285 58.68 19.379 ;
     RECT  83.28 18.709 83.712 19.379 ;
     RECT  27.504 18.611 27.528 19.381 ;
     RECT  57.696 19.379 58.68 19.427 ;
     RECT  2.4 17.653 2.904 19.475 ;
     RECT  4.8 18.757 5.112 19.475 ;
     RECT  16.224 17.365 16.248 19.475 ;
     RECT  12.336 18.803 13.512 19.523 ;
     RECT  77.664 19.333 80.088 19.619 ;
     RECT  7.8 17.123 8.112 19.621 ;
     RECT  10.032 17.605 10.056 19.811 ;
     RECT  24 17.701 24.504 19.811 ;
     RECT  39.6 18.709 40.92 19.811 ;
     RECT  61.584 18.851 63.048 19.813 ;
     RECT  29.4 17.075 29.712 19.909 ;
     RECT  14.544 18.803 14.856 19.957 ;
     RECT  33.12 18.565 35.208 20.003 ;
     RECT  67.104 18.179 69.048 20.003 ;
     RECT  72.6 18.515 73.896 20.149 ;
     RECT  6.816 19.621 8.112 20.291 ;
     RECT  30.816 20.197 30.84 20.387 ;
     RECT  77.664 19.619 79.512 20.387 ;
     RECT  29.4 19.909 29.832 20.435 ;
     RECT  50.112 17.413 51.528 20.485 ;
     RECT  59.904 18.947 59.928 20.485 ;
     RECT  65.76 18.851 65.784 20.485 ;
     RECT  67.104 20.003 67.608 20.485 ;
     RECT  54.72 18.515 54.744 20.533 ;
     RECT  38.592 17.509 38.616 20.579 ;
     RECT  44.208 17.989 44.232 20.819 ;
     RECT  22.848 16.261 22.872 20.869 ;
     RECT  53.76 20.533 54.744 20.869 ;
     RECT  33.504 20.003 35.208 21.011 ;
     RECT  22.608 20.869 22.872 21.013 ;
     RECT  6.576 20.965 6.6 21.107 ;
     RECT  75.888 20.197 75.912 21.107 ;
     RECT  53.28 20.869 54.744 21.155 ;
     RECT  17.088 21.013 17.112 21.203 ;
     RECT  27.36 19.381 27.528 21.203 ;
     RECT  59.904 20.485 59.976 21.203 ;
     RECT  22.032 21.013 22.872 21.299 ;
     RECT  72.6 20.149 73.992 21.299 ;
     RECT  80.928 21.301 80.952 21.443 ;
     RECT  22.848 21.299 22.872 21.587 ;
     RECT  18.6 17.699 18.912 21.637 ;
     RECT  29.4 20.435 29.712 21.637 ;
     RECT  77.664 20.387 78.84 21.637 ;
     RECT  41.808 20.965 41.832 21.683 ;
     RECT  13.2 19.523 13.512 21.685 ;
     RECT  14.544 19.957 15.144 21.685 ;
     RECT  53.28 21.155 53.784 21.685 ;
     RECT  45.6 16.931 46.152 21.781 ;
     RECT  50.064 20.485 51.528 21.781 ;
     RECT  52.512 21.685 53.784 21.781 ;
     RECT  13.2 21.685 15.144 21.827 ;
     RECT  14.544 21.827 15.144 21.973 ;
     RECT  0.144 21.589 0.168 22.069 ;
     RECT  33.888 21.011 35.208 22.069 ;
     RECT  14.544 21.973 15.384 22.117 ;
     RECT  18.432 21.637 18.912 22.163 ;
     RECT  59.904 21.203 59.928 22.165 ;
     RECT  61.2 19.813 63.048 22.165 ;
     RECT  64.176 18.851 64.488 22.165 ;
     RECT  72.6 21.299 73.416 22.211 ;
     RECT  77.568 21.637 78.84 22.211 ;
     RECT  39.6 19.811 40.512 22.213 ;
     RECT  0.144 22.069 0.264 22.259 ;
     RECT  45.36 21.781 46.152 22.259 ;
     RECT  0.144 22.259 0.168 22.307 ;
     RECT  27.504 21.203 27.528 22.357 ;
     RECT  29.28 21.637 29.712 22.357 ;
     RECT  85.488 16.261 85.512 22.405 ;
     RECT  4.8 19.475 4.824 22.451 ;
     RECT  85.488 22.405 85.608 22.451 ;
     RECT  50.064 21.781 53.784 22.499 ;
     RECT  10.848 22.405 10.872 22.547 ;
     RECT  50.064 22.499 53.304 22.597 ;
     RECT  9.36 20.725 9.384 22.787 ;
     RECT  31.872 21.109 31.896 22.787 ;
     RECT  56.4 19.379 56.712 22.789 ;
     RECT  14.544 22.117 15.672 22.835 ;
     RECT  33.888 22.069 35.352 22.835 ;
     RECT  65.76 20.485 67.608 22.835 ;
     RECT  75.264 22.069 75.288 22.835 ;
     RECT  56.4 22.789 57.048 22.931 ;
     RECT  25.68 22.501 25.704 23.123 ;
     RECT  2.4 19.475 2.712 23.125 ;
     RECT  39.6 22.213 41.064 23.267 ;
     RECT  58.656 19.427 58.68 23.317 ;
     RECT  88.8 19.235 89.112 23.317 ;
     RECT  14.544 22.835 15.384 23.411 ;
     RECT  49.536 22.597 53.304 23.411 ;
     RECT  45.36 22.259 45.912 23.509 ;
     RECT  38.4 22.117 38.424 23.555 ;
     RECT  27.504 22.357 29.712 23.557 ;
     RECT  61.2 22.165 64.488 23.603 ;
     RECT  61.8 23.603 64.488 23.701 ;
     RECT  61.8 23.701 64.68 23.795 ;
     RECT  45.36 23.509 46.776 23.845 ;
     RECT  78 22.211 78.84 23.845 ;
     RECT  59.904 22.165 59.976 23.891 ;
     RECT  14.544 23.411 14.808 23.987 ;
     RECT  88.416 23.317 89.112 23.987 ;
     RECT  10.176 23.029 10.2 24.083 ;
     RECT  39.6 23.267 40.512 24.131 ;
     RECT  56.4 22.931 56.712 24.421 ;
     RECT  57.744 23.317 58.68 24.421 ;
     RECT  65.76 22.835 67.512 24.421 ;
     RECT  64.176 23.795 64.68 24.467 ;
     RECT  80.88 23.893 80.904 24.467 ;
     RECT  72.6 22.211 73.128 24.469 ;
     RECT  45.264 23.845 46.776 24.515 ;
     RECT  50.784 23.411 52.728 24.515 ;
     RECT  27.36 23.557 29.712 24.563 ;
     RECT  37.488 23.701 37.512 24.563 ;
     RECT  45.264 24.515 45.912 24.611 ;
     RECT  2.304 23.125 2.712 24.659 ;
     RECT  20.352 22.789 20.376 24.659 ;
     RECT  51 24.515 52.728 24.899 ;
     RECT  52.704 24.899 52.728 24.901 ;
     RECT  56.4 24.421 58.68 24.947 ;
     RECT  69.648 21.109 69.672 24.947 ;
     RECT  52.704 24.901 53.064 25.043 ;
     RECT  61.8 23.795 63.048 25.045 ;
     RECT  56.4 24.947 57.768 25.091 ;
     RECT  65.76 24.421 67.608 25.093 ;
     RECT  77.568 23.845 78.84 25.139 ;
     RECT  4.704 24.469 4.728 25.187 ;
     RECT  76.368 23.893 76.392 25.187 ;
     RECT  16.032 24.805 16.056 25.235 ;
     RECT  56.4 25.091 57.528 25.235 ;
     RECT  61.488 25.045 63.048 25.283 ;
     RECT  22.224 23.893 22.248 25.427 ;
     RECT  56.4 25.235 57.048 25.477 ;
     RECT  27.36 24.563 27.384 25.573 ;
     RECT  28.464 24.563 29.712 25.573 ;
     RECT  27.36 25.573 29.712 25.619 ;
     RECT  64.176 24.467 64.2 25.669 ;
     RECT  65.76 25.093 67.704 25.715 ;
     RECT  67.2 25.715 67.704 25.859 ;
     RECT  27.648 25.619 29.712 25.861 ;
     RECT  2.4 24.659 2.712 26.005 ;
     RECT  31.296 24.949 31.32 26.099 ;
     RECT  45.6 24.611 45.912 26.101 ;
     RECT  56.016 25.477 57.048 26.101 ;
     RECT  90.576 26.005 90.6 26.147 ;
     RECT  27.648 25.861 29.832 26.243 ;
     RECT  52.704 25.043 52.728 26.291 ;
     RECT  72.6 24.469 73.8 26.291 ;
     RECT  28.464 26.243 29.832 26.341 ;
     RECT  22.704 25.573 22.728 26.531 ;
     RECT  85.584 22.451 85.608 26.531 ;
     RECT  24 19.811 24.312 26.533 ;
     RECT  77.856 25.139 78.84 26.581 ;
     RECT  63.6 25.669 64.2 26.677 ;
     RECT  65.76 25.715 65.784 26.677 ;
     RECT  14.544 23.987 14.568 26.725 ;
     RECT  45.024 26.101 45.912 26.725 ;
     RECT  49.872 26.293 49.896 26.917 ;
     RECT  38.736 25.669 38.76 27.013 ;
     RECT  38.208 27.013 38.76 27.059 ;
     RECT  33.888 22.835 35.112 27.205 ;
     RECT  54.48 26.677 54.504 27.205 ;
     RECT  63.6 26.677 65.784 27.299 ;
     RECT  70.56 25.237 70.584 27.299 ;
     RECT  45.024 26.725 46.872 27.395 ;
     RECT  64.848 27.299 65.784 27.395 ;
     RECT  55.632 26.101 57.048 27.443 ;
     RECT  49.824 26.917 49.896 27.637 ;
     RECT  2.304 26.005 2.712 27.685 ;
     RECT  11.952 26.389 11.976 27.685 ;
     RECT  13.2 21.827 13.512 27.685 ;
     RECT  2.304 27.685 2.808 27.731 ;
     RECT  11.952 27.685 13.512 27.781 ;
     RECT  20.544 27.205 20.568 27.877 ;
     RECT  40.2 24.131 40.512 27.877 ;
     RECT  49.584 27.637 49.896 27.877 ;
     RECT  51 24.899 51.312 27.877 ;
     RECT  14.544 26.725 15.48 27.923 ;
     RECT  38.208 27.059 38.232 27.925 ;
     RECT  37.728 27.925 38.232 27.971 ;
     RECT  11.424 27.781 13.512 28.115 ;
     RECT  75.84 27.301 75.864 28.115 ;
     RECT  20.544 27.877 21.096 28.259 ;
     RECT  7.8 20.291 8.112 28.261 ;
     RECT  24 26.533 24.456 28.261 ;
     RECT  28.464 26.341 30.216 28.261 ;
     RECT  65.76 27.395 65.784 28.261 ;
     RECT  33.888 27.205 35.352 28.357 ;
     RECT  58.368 26.725 58.392 28.405 ;
     RECT  58.368 28.405 58.488 28.451 ;
     RECT  45.6 27.395 45.912 28.453 ;
     RECT  59.904 23.891 59.928 28.453 ;
     RECT  77.856 26.581 79.224 28.453 ;
     RECT  27.744 28.261 30.216 28.499 ;
     RECT  84.96 27.877 84.984 28.643 ;
     RECT  37.728 27.971 37.752 28.691 ;
     RECT  40.2 27.877 40.872 28.691 ;
     RECT  49.584 27.877 51.312 28.691 ;
     RECT  6.24 27.877 6.264 28.835 ;
     RECT  33.6 28.357 35.352 28.835 ;
     RECT  43.152 27.877 43.176 28.835 ;
     RECT  65.76 28.261 66.168 28.837 ;
     RECT  67.2 25.859 67.608 28.837 ;
     RECT  11.424 28.115 11.976 28.979 ;
     RECT  16.992 28.789 17.016 28.981 ;
     RECT  45.6 28.453 46.104 28.981 ;
     RECT  16.992 28.981 17.112 29.027 ;
     RECT  56.4 27.443 57.048 29.029 ;
     RECT  70.704 27.349 70.728 29.029 ;
     RECT  83.4 19.379 83.712 29.029 ;
     RECT  7.392 28.261 8.112 29.075 ;
     RECT  20.544 28.259 20.808 29.075 ;
     RECT  70.704 29.029 71.256 29.075 ;
     RECT  17.088 29.027 17.112 29.077 ;
     RECT  59.76 28.453 59.928 29.123 ;
     RECT  2.4 27.731 2.808 29.219 ;
     RECT  17.088 29.077 17.208 29.219 ;
     RECT  71.232 29.075 71.256 29.219 ;
     RECT  53.952 27.205 54.504 29.507 ;
     RECT  13.2 28.115 13.512 29.605 ;
     RECT  14.544 27.923 14.568 29.605 ;
     RECT  38.736 28.405 38.76 29.651 ;
     RECT  59.904 29.123 59.928 29.699 ;
     RECT  65.76 28.837 67.608 29.699 ;
     RECT  86.112 27.205 86.136 29.699 ;
     RECT  32.448 27.301 32.472 29.747 ;
     RECT  72.6 26.291 73.464 29.749 ;
     RECT  45.024 28.981 46.104 29.795 ;
     RECT  33.888 28.835 35.112 29.797 ;
     RECT  40.2 28.691 40.512 29.893 ;
     RECT  66.384 29.699 67.608 29.941 ;
     RECT  68.736 27.301 68.76 29.941 ;
     RECT  66.384 29.941 68.76 29.987 ;
     RECT  33.888 29.797 35.352 29.989 ;
     RECT  33.648 29.989 35.352 30.035 ;
     RECT  18.6 22.163 18.912 30.037 ;
     RECT  20.784 29.075 20.808 30.037 ;
     RECT  24 28.261 25.128 30.085 ;
     RECT  49.872 28.691 51.312 30.085 ;
     RECT  24 30.085 26.088 30.131 ;
     RECT  53.04 29.749 53.064 30.131 ;
     RECT  71.904 29.749 73.464 30.131 ;
     RECT  13.104 29.605 14.568 30.133 ;
     RECT  49.872 30.085 51.576 30.133 ;
     RECT  18.6 30.037 19.128 30.179 ;
     RECT  20.784 30.037 21.24 30.179 ;
     RECT  49.344 30.133 51.576 30.181 ;
     RECT  55.872 29.029 57.048 30.181 ;
     RECT  49.344 30.181 52.44 30.275 ;
     RECT  82.128 29.413 82.152 30.515 ;
     RECT  10.8 29.029 10.824 30.517 ;
     RECT  10.656 30.517 10.824 30.563 ;
     RECT  27.744 28.499 29.712 30.563 ;
     RECT  37.632 29.605 37.656 30.613 ;
     RECT  71.904 30.131 72.912 30.757 ;
     RECT  22.32 30.181 22.344 30.803 ;
     RECT  25.536 30.131 26.088 30.851 ;
     RECT  31.296 29.605 31.32 30.851 ;
     RECT  45.504 29.795 46.104 30.899 ;
     RECT  58.464 28.451 58.488 30.949 ;
     RECT  13.104 30.133 14.712 31.043 ;
     RECT  77.472 28.453 79.224 31.091 ;
     RECT  63.6 27.299 63.864 31.093 ;
     RECT  58.464 30.949 58.68 31.189 ;
     RECT  91.344 28.933 91.368 31.237 ;
     RECT  5.04 29.029 5.064 31.285 ;
     RECT  24 30.131 24.312 31.285 ;
     RECT  37.632 30.613 38.04 31.331 ;
     RECT  52.416 30.275 52.44 31.379 ;
     RECT  0.288 31.141 0.312 31.427 ;
     RECT  61.488 25.283 62.112 31.525 ;
     RECT  55.776 30.181 57.048 31.667 ;
     RECT  2.4 29.219 2.712 31.669 ;
     RECT  39.6 29.893 40.512 31.669 ;
     RECT  49.344 30.275 51.312 31.669 ;
     RECT  66.384 29.987 68.424 31.813 ;
     RECT  1.968 31.669 2.712 31.859 ;
     RECT  33.648 30.035 33.672 31.861 ;
     RECT  34.8 30.035 35.352 31.861 ;
     RECT  59.952 30.181 59.976 31.861 ;
     RECT  60.96 31.525 62.112 31.861 ;
     RECT  94.2 2.151 94.512 31.861 ;
     RECT  33.648 31.861 35.352 31.907 ;
     RECT  39.6 31.669 40.632 31.907 ;
     RECT  45.6 30.899 46.104 31.907 ;
     RECT  58.128 31.189 58.68 31.907 ;
     RECT  54.48 29.507 54.504 31.955 ;
     RECT  77.856 31.091 79.224 31.955 ;
     RECT  66.384 31.813 68.952 32.003 ;
     RECT  66.384 32.003 68.424 32.051 ;
     RECT  14.688 31.043 14.712 32.101 ;
     RECT  10.656 30.563 10.68 32.195 ;
     RECT  11.952 28.979 11.976 32.195 ;
     RECT  43.968 29.989 43.992 32.195 ;
     RECT  74.88 31.285 74.904 32.197 ;
     RECT  2.304 31.859 2.712 32.437 ;
     RECT  88.8 23.987 89.112 32.437 ;
     RECT  5.04 31.285 5.736 32.483 ;
     RECT  90.48 31.237 91.368 32.531 ;
     RECT  59.952 31.861 62.112 32.675 ;
     RECT  71.808 30.757 72.912 32.677 ;
     RECT  83.232 29.029 83.712 32.771 ;
     RECT  24 31.285 24.408 32.773 ;
     RECT  71.232 32.677 72.912 32.819 ;
     RECT  7.8 29.075 8.112 32.869 ;
     RECT  28.176 30.563 29.712 33.011 ;
     RECT  56.4 31.667 57.048 33.011 ;
     RECT  55.248 32.197 55.272 33.061 ;
     RECT  55.056 33.061 55.272 33.107 ;
     RECT  81.504 31.861 81.528 33.107 ;
     RECT  14.688 32.101 15.384 33.251 ;
     RECT  66.384 32.051 67.512 33.301 ;
     RECT  58.128 31.907 58.488 33.347 ;
     RECT  91.344 32.531 91.368 33.493 ;
     RECT  49.344 31.669 52.152 33.539 ;
     RECT  74.88 32.197 75.384 33.539 ;
     RECT  79.776 32.437 79.8 33.539 ;
     RECT  77.856 31.955 78.696 33.541 ;
     RECT  71.808 32.819 72.912 33.587 ;
     RECT  63.6 31.093 64.392 33.589 ;
     RECT  53.136 32.437 53.16 33.635 ;
     RECT  25.536 30.851 25.56 33.637 ;
     RECT  6.816 32.869 8.112 33.683 ;
     RECT  58.128 33.347 58.152 33.683 ;
     RECT  25.488 33.637 25.56 33.779 ;
     RECT  42.144 33.013 42.168 33.827 ;
     RECT  90.72 33.493 91.368 33.925 ;
     RECT  65.52 33.301 67.512 34.021 ;
     RECT  25.536 33.779 25.56 34.067 ;
     RECT  31.872 33.541 31.896 34.115 ;
     RECT  39.6 31.907 40.512 34.117 ;
     RECT  55.056 33.107 55.08 34.117 ;
     RECT  86.496 31.717 86.52 34.117 ;
     RECT  93.936 31.861 94.512 34.117 ;
     RECT  27.072 31.573 27.096 34.163 ;
     RECT  14.688 33.251 14.712 34.213 ;
     RECT  34.416 31.907 35.208 34.213 ;
     RECT  2.304 32.437 3.432 34.355 ;
     RECT  56.4 33.011 56.712 34.357 ;
     RECT  34.416 34.213 35.928 34.403 ;
     RECT  77.376 33.541 78.696 34.403 ;
     RECT  56.4 34.357 57.576 34.499 ;
     RECT  77.376 34.403 78.408 34.595 ;
     RECT  37.632 31.331 37.656 34.739 ;
     RECT  28.176 33.011 28.2 34.741 ;
     RECT  60.912 32.675 62.112 34.741 ;
     RECT  63.216 33.589 64.392 34.741 ;
     RECT  24 32.773 24.504 34.787 ;
     RECT  90.72 33.925 91.416 34.787 ;
     RECT  7.8 33.683 8.112 34.789 ;
     RECT  49.344 33.539 49.368 34.789 ;
     RECT  59.856 32.917 59.88 34.789 ;
     RECT  51 33.539 52.152 34.835 ;
     RECT  65.472 34.021 67.512 34.835 ;
     RECT  86.064 34.117 86.52 34.835 ;
     RECT  87.936 32.437 89.112 34.835 ;
     RECT  90.72 34.787 91.032 34.835 ;
     RECT  59.28 34.789 59.88 34.885 ;
     RECT  60.912 34.741 64.392 34.885 ;
     RECT  59.28 34.885 64.392 34.979 ;
     RECT  77.52 34.595 78.408 34.979 ;
     RECT  93.552 34.117 94.512 35.075 ;
     RECT  39.6 34.117 41.304 35.171 ;
     RECT  83.4 32.771 83.712 35.173 ;
     RECT  54.72 34.117 55.08 35.269 ;
     RECT  67.2 34.835 67.512 35.269 ;
     RECT  59.856 34.979 64.392 35.315 ;
     RECT  72.384 33.587 72.912 35.315 ;
     RECT  27.312 34.741 28.2 35.317 ;
     RECT  29.4 33.011 29.712 35.317 ;
     RECT  14.688 34.213 15.048 35.363 ;
     RECT  20.784 30.179 20.808 35.363 ;
     RECT  32.88 34.501 32.904 35.363 ;
     RECT  43.92 34.021 43.944 35.363 ;
     RECT  53.808 35.269 55.08 35.363 ;
     RECT  63.6 35.315 64.392 35.363 ;
     RECT  65.472 34.835 65.496 35.459 ;
     RECT  51 34.835 51.312 35.461 ;
     RECT  2.304 34.355 2.712 35.509 ;
     RECT  13.104 31.043 13.512 35.555 ;
     RECT  59.856 35.315 62.424 35.555 ;
     RECT  72.48 35.315 72.912 35.557 ;
     RECT  78 34.979 78.408 35.701 ;
     RECT  7.8 34.789 8.808 35.795 ;
     RECT  5.04 32.483 5.064 35.845 ;
     RECT  72.48 35.557 73.032 35.845 ;
     RECT  88.704 34.835 89.112 35.845 ;
     RECT  93.888 35.075 94.512 35.891 ;
     RECT  48.48 34.789 49.368 35.939 ;
     RECT  50.4 35.461 51.312 35.939 ;
     RECT  5.04 35.845 5.688 35.989 ;
     RECT  39.6 35.171 41.16 36.035 ;
     RECT  72.48 35.845 73.608 36.035 ;
     RECT  91.008 34.835 91.032 36.131 ;
     RECT  47.328 33.445 47.352 36.179 ;
     RECT  2.304 35.509 2.904 36.275 ;
     RECT  27.312 35.317 29.712 36.275 ;
     RECT  82.464 35.173 83.712 36.275 ;
     RECT  83.4 36.275 83.712 36.421 ;
     RECT  84.864 35.605 84.888 36.421 ;
     RECT  36.336 35.317 36.36 36.515 ;
     RECT  53.808 35.363 53.832 36.515 ;
     RECT  70.224 35.557 70.248 36.515 ;
     RECT  86.496 34.835 86.52 36.515 ;
     RECT  45.6 31.907 45.912 36.517 ;
     RECT  64.368 35.363 64.392 36.517 ;
     RECT  72.6 36.035 73.608 36.563 ;
     RECT  63.744 36.517 64.392 36.659 ;
     RECT  83.4 36.421 84.888 36.659 ;
     RECT  78 35.701 78.456 36.707 ;
     RECT  67.2 35.269 67.848 36.755 ;
     RECT  27.312 36.275 28.2 36.803 ;
     RECT  27.888 36.803 28.2 36.899 ;
     RECT  60.528 35.555 62.424 36.947 ;
     RECT  78 36.707 78.408 36.947 ;
     RECT  60.912 36.947 62.424 36.949 ;
     RECT  24 34.787 24.312 36.997 ;
     RECT  67.2 36.755 67.512 36.997 ;
     RECT  88.704 35.845 89.496 36.997 ;
     RECT  39.6 36.035 40.728 37.043 ;
     RECT  45.6 36.517 46.056 37.045 ;
     RECT  44.448 37.045 46.056 37.235 ;
     RECT  7.8 35.795 8.112 37.333 ;
     RECT  7.584 37.333 8.112 37.381 ;
     RECT  45.6 37.235 46.056 37.429 ;
     RECT  67.056 36.997 67.512 37.477 ;
     RECT  4.896 35.989 5.688 37.573 ;
     RECT  7.008 37.381 8.112 37.573 ;
     RECT  49.344 35.939 49.368 37.573 ;
     RECT  55.056 35.363 55.08 37.573 ;
     RECT  87.6 37.429 87.624 37.573 ;
     RECT  28.176 36.899 28.2 37.619 ;
     RECT  4.896 37.573 8.112 37.667 ;
     RECT  60.912 36.949 62.664 37.667 ;
     RECT  88.704 36.997 90.216 37.667 ;
     RECT  17.232 37.669 17.256 37.861 ;
     RECT  66.336 37.477 67.512 37.907 ;
     RECT  4.896 37.667 4.92 38.005 ;
     RECT  83.4 36.659 84.456 38.099 ;
     RECT  13.2 35.555 13.512 38.101 ;
     RECT  14.688 35.363 14.712 38.101 ;
     RECT  78 36.947 78.312 38.101 ;
     RECT  9.888 33.829 9.912 38.147 ;
     RECT  91.824 37.189 91.848 38.147 ;
     RECT  18.6 30.179 18.912 38.149 ;
     RECT  22.752 37.045 22.776 38.149 ;
     RECT  60.912 37.667 62.232 38.149 ;
     RECT  70.752 36.997 70.776 38.149 ;
     RECT  72.6 36.563 72.912 38.149 ;
     RECT  75.36 33.539 75.384 38.149 ;
     RECT  31.536 37.573 31.56 38.195 ;
     RECT  55.056 37.573 55.176 38.197 ;
     RECT  56.4 34.499 56.712 38.197 ;
     RECT  87.408 37.573 87.624 38.197 ;
     RECT  88.704 37.667 89.496 38.197 ;
     RECT  2.304 36.275 2.808 38.243 ;
     RECT  12.048 35.989 12.072 38.243 ;
     RECT  48.96 37.573 49.368 38.243 ;
     RECT  24 36.997 24.408 38.339 ;
     RECT  87.408 38.197 89.496 38.339 ;
     RECT  52.704 37.621 52.728 38.389 ;
     RECT  45.6 37.429 46.152 38.435 ;
     RECT  52.464 38.389 52.728 38.435 ;
     RECT  26.544 37.525 26.568 38.437 ;
     RECT  51 35.939 51.312 38.629 ;
     RECT  22.656 38.149 22.776 38.675 ;
     RECT  70.752 38.149 72.912 38.675 ;
     RECT  87.408 38.339 87.624 38.675 ;
     RECT  13.2 38.101 14.712 38.677 ;
     RECT  13.2 38.677 15.144 38.723 ;
     RECT  25.68 38.437 26.568 38.723 ;
     RECT  29.28 36.275 29.712 38.723 ;
     RECT  50.736 38.629 51.312 38.771 ;
     RECT  29.4 38.723 29.712 38.773 ;
     RECT  30.768 38.677 30.792 38.773 ;
     RECT  29.4 38.773 30.792 38.819 ;
     RECT  79.92 38.053 79.944 38.819 ;
     RECT  52.464 38.435 52.488 39.059 ;
     RECT  60.432 38.149 62.232 39.059 ;
     RECT  82.32 38.149 82.344 39.061 ;
     RECT  81.36 39.061 82.344 39.107 ;
     RECT  16.704 37.861 17.256 39.205 ;
     RECT  16.512 39.205 17.256 39.251 ;
     RECT  39.6 37.043 40.512 39.253 ;
     RECT  78 38.101 78.504 39.253 ;
     RECT  37.728 36.085 37.752 39.299 ;
     RECT  16.512 39.251 16.92 39.443 ;
     RECT  86.352 38.725 86.376 39.541 ;
     RECT  87.408 38.675 87.432 39.541 ;
     RECT  67.056 37.907 67.512 39.589 ;
     RECT  44.448 37.235 44.472 39.635 ;
     RECT  71.664 38.675 72.912 39.637 ;
     RECT  71.424 39.637 72.912 39.683 ;
     RECT  45.6 38.435 46.056 39.733 ;
     RECT  49.344 38.243 49.368 39.733 ;
     RECT  51 38.771 51.312 39.733 ;
     RECT  64.368 36.659 64.392 39.733 ;
     RECT  38.976 39.253 40.512 39.781 ;
     RECT  74.4 38.149 75.384 39.829 ;
     RECT  88.8 38.339 89.496 39.875 ;
     RECT  74.4 39.829 75.768 39.971 ;
     RECT  20.976 38.437 21 40.019 ;
     RECT  45.6 39.733 46.248 40.069 ;
     RECT  78 39.253 78.648 40.115 ;
     RECT  34.416 34.403 35.112 40.117 ;
     RECT  36.432 39.877 36.456 40.117 ;
     RECT  32.112 38.917 32.136 40.163 ;
     RECT  86.352 39.541 87.432 40.163 ;
     RECT  4.176 38.005 4.92 40.165 ;
     RECT  55.056 38.197 56.712 40.213 ;
     RECT  54.96 40.213 56.712 40.259 ;
     RECT  6.48 37.667 8.112 40.309 ;
     RECT  87.216 40.163 87.432 40.403 ;
     RECT  14.688 38.723 15.144 40.405 ;
     RECT  19.968 39.589 19.992 40.405 ;
     RECT  6.48 40.309 8.28 40.499 ;
     RECT  54.96 40.259 55.272 40.499 ;
     RECT  63.408 39.733 64.392 40.499 ;
     RECT  71.424 39.683 71.448 40.499 ;
     RECT  10.848 40.405 10.872 40.547 ;
     RECT  38.976 39.781 41.016 40.547 ;
     RECT  54.96 40.499 55.08 40.547 ;
     RECT  13.2 38.723 13.512 40.549 ;
     RECT  45.504 40.069 46.248 40.549 ;
     RECT  58.128 39.877 58.152 40.549 ;
     RECT  29.4 38.819 30.696 40.595 ;
     RECT  57.744 40.549 58.152 40.595 ;
     RECT  52.992 39.877 53.016 40.645 ;
     RECT  29.4 40.595 29.712 40.693 ;
     RECT  34.416 40.117 36.456 40.741 ;
     RECT  13.2 40.549 13.656 40.787 ;
     RECT  56.4 40.259 56.712 40.837 ;
     RECT  57.744 40.595 57.768 40.837 ;
     RECT  39.6 40.547 41.016 40.883 ;
     RECT  52.848 40.645 53.016 40.883 ;
     RECT  60.432 39.059 62.112 40.883 ;
     RECT  64.368 40.499 64.392 40.981 ;
     RECT  66.096 39.589 67.512 40.981 ;
     RECT  69.264 39.589 69.288 40.981 ;
     RECT  52.992 40.883 53.016 41.027 ;
     RECT  14.688 40.405 15.384 41.075 ;
     RECT  39.888 40.883 41.016 41.075 ;
     RECT  54.96 40.547 54.984 41.075 ;
     RECT  66.096 40.981 69.288 41.075 ;
     RECT  75.744 39.971 75.768 41.075 ;
     RECT  0.144 38.533 0.168 41.077 ;
     RECT  0.144 41.077 0.36 41.123 ;
     RECT  56.4 40.837 57.768 41.123 ;
     RECT  45.312 40.549 46.248 41.125 ;
     RECT  18.48 38.149 18.912 41.171 ;
     RECT  6.864 40.499 8.28 41.315 ;
     RECT  39.888 41.075 40.512 41.363 ;
     RECT  45.024 41.125 46.248 41.363 ;
     RECT  81.36 39.107 81.384 41.365 ;
     RECT  34.224 40.741 36.456 41.411 ;
     RECT  48.192 40.405 48.216 41.605 ;
     RECT  49.344 39.733 51.312 41.605 ;
     RECT  2.4 38.243 2.808 41.651 ;
     RECT  15.36 41.075 15.384 41.651 ;
     RECT  19.968 40.405 20.424 41.651 ;
     RECT  48.192 41.605 51.312 41.651 ;
     RECT  60.912 40.883 62.112 41.651 ;
     RECT  61.536 41.651 62.112 41.701 ;
     RECT  61.536 41.701 62.232 41.747 ;
     RECT  0.192 41.123 0.36 41.749 ;
     RECT  45.312 41.363 46.248 41.891 ;
     RECT  76.752 40.837 76.776 41.939 ;
     RECT  64.368 40.981 64.776 41.941 ;
     RECT  64.368 41.941 65.304 41.987 ;
     RECT  36.432 41.411 36.456 42.037 ;
     RECT  37.92 41.557 37.944 42.037 ;
     RECT  36.432 42.037 37.944 42.083 ;
     RECT  7.008 41.315 8.28 42.133 ;
     RECT  9.696 39.637 9.72 42.133 ;
     RECT  41.76 41.221 41.784 42.227 ;
     RECT  64.752 41.987 65.304 42.227 ;
     RECT  74.4 39.971 74.424 42.227 ;
     RECT  80.4 41.365 81.384 42.227 ;
     RECT  83.4 38.099 83.712 42.229 ;
     RECT  24 38.339 24.312 42.277 ;
     RECT  78 40.115 78.504 42.325 ;
     RECT  4.176 40.165 5.112 42.371 ;
     RECT  34.224 41.411 35.112 42.373 ;
     RECT  40.032 41.363 40.512 42.373 ;
     RECT  24 42.277 24.408 42.419 ;
     RECT  81.36 42.227 81.384 42.467 ;
     RECT  83.4 42.229 84.072 42.515 ;
     RECT  34.224 42.373 35.208 42.563 ;
     RECT  88.8 39.875 89.112 42.565 ;
     RECT  94.2 35.891 94.512 42.565 ;
     RECT  54.864 42.133 54.888 42.613 ;
     RECT  54.72 42.613 54.888 42.659 ;
     RECT  94.2 42.565 95.4 42.707 ;
     RECT  16.512 39.443 16.728 42.709 ;
     RECT  18.6 41.171 18.912 42.709 ;
     RECT  87.408 40.403 87.432 42.709 ;
     RECT  88.8 42.565 90.072 42.709 ;
     RECT  7.008 42.133 11.544 42.755 ;
     RECT  65.28 42.227 65.304 42.755 ;
     RECT  66.912 41.075 69.288 42.755 ;
     RECT  87.408 42.709 90.072 42.755 ;
     RECT  61.8 41.747 62.232 42.757 ;
     RECT  36.432 42.083 37.224 42.803 ;
     RECT  7.008 42.755 10.584 42.851 ;
     RECT  34.224 42.563 35.112 42.851 ;
     RECT  48.72 41.651 51.312 42.851 ;
     RECT  13.2 40.787 13.512 42.901 ;
     RECT  20.16 41.651 20.424 42.995 ;
     RECT  36.432 42.803 37.032 42.995 ;
     RECT  27.408 40.117 27.432 42.997 ;
     RECT  28.56 40.693 29.712 42.997 ;
     RECT  7.056 42.851 10.584 43.043 ;
     RECT  16.512 42.709 17.016 43.045 ;
     RECT  72.6 39.683 72.912 43.189 ;
     RECT  78 42.325 78.696 43.285 ;
     RECT  72.6 43.189 73.704 43.331 ;
     RECT  61.584 42.757 62.232 43.379 ;
     RECT  81.696 42.469 81.72 43.379 ;
     RECT  56.4 41.123 57.336 43.429 ;
     RECT  61.584 43.379 62.112 43.475 ;
     RECT  67.056 42.755 69.288 43.475 ;
     RECT  4.176 42.371 4.632 43.523 ;
     RECT  54.72 42.659 54.744 43.621 ;
     RECT  13.008 42.901 13.512 43.669 ;
     RECT  78 43.285 78.84 43.717 ;
     RECT  37.008 42.995 37.032 43.859 ;
     RECT  51 42.851 51.312 43.861 ;
     RECT  67.2 43.475 69.288 43.861 ;
     RECT  78 43.717 79.128 43.861 ;
     RECT  11.664 42.997 11.688 43.907 ;
     RECT  16.416 43.045 17.016 43.909 ;
     RECT  27.408 42.997 29.712 43.909 ;
     RECT  7.056 43.043 8.376 44.051 ;
     RECT  21.6 43.285 21.624 44.099 ;
     RECT  83.4 42.515 83.712 44.149 ;
     RECT  67.2 43.861 69.816 44.197 ;
     RECT  27.168 43.909 29.712 44.291 ;
     RECT  54.48 43.621 54.744 44.293 ;
     RECT  27.168 44.291 28.296 44.339 ;
     RECT  84.912 44.197 84.936 44.339 ;
     RECT  2.4 41.651 2.712 44.341 ;
     RECT  7.8 44.051 8.376 44.341 ;
     RECT  53.568 44.293 54.744 44.341 ;
     RECT  82.992 44.149 83.712 44.341 ;
     RECT  88.128 42.755 89.112 44.341 ;
     RECT  2.304 44.341 2.712 44.389 ;
     RECT  82.896 44.341 83.712 44.483 ;
     RECT  78 43.861 79.224 44.485 ;
     RECT  4.608 43.523 4.632 44.531 ;
     RECT  39.36 42.373 40.512 44.531 ;
     RECT  9.648 43.043 10.584 44.627 ;
     RECT  27.168 44.339 27.432 44.627 ;
     RECT  45.6 41.891 46.248 44.629 ;
     RECT  2.304 44.389 2.904 44.725 ;
     RECT  45.024 44.629 46.248 44.867 ;
     RECT  24 42.419 24.312 44.869 ;
     RECT  50.88 43.861 51.312 44.915 ;
     RECT  24 44.869 24.456 45.011 ;
     RECT  76.704 43.669 76.728 45.059 ;
     RECT  53.568 44.341 54.84 45.155 ;
     RECT  81.408 44.725 81.432 45.155 ;
     RECT  29.4 44.291 29.712 45.253 ;
     RECT  67.2 44.197 70.248 45.347 ;
     RECT  60.672 44.629 60.696 45.395 ;
     RECT  7.8 44.341 8.568 45.445 ;
     RECT  6.144 44.341 6.168 45.541 ;
     RECT  12.816 43.669 13.512 45.541 ;
     RECT  29.28 45.253 29.712 45.541 ;
     RECT  47.52 43.813 47.544 45.587 ;
     RECT  64.56 44.965 64.584 45.587 ;
     RECT  2.304 44.725 3.432 45.635 ;
     RECT  10.368 44.627 10.584 45.635 ;
     RECT  45.6 44.867 46.248 45.635 ;
     RECT  34.56 42.851 35.112 45.683 ;
     RECT  40.08 44.531 40.512 45.685 ;
     RECT  29.088 45.541 29.712 45.731 ;
     RECT  30.72 44.629 30.744 45.731 ;
     RECT  37.92 44.629 37.944 45.731 ;
     RECT  7.536 45.445 8.568 45.877 ;
     RECT  16.416 43.909 17.256 46.067 ;
     RECT  0.192 41.749 0.408 46.069 ;
     RECT  6.144 45.541 6.264 46.069 ;
     RECT  27.408 44.627 27.432 46.069 ;
     RECT  61.8 43.475 62.112 46.069 ;
     RECT  63.408 45.301 63.432 46.069 ;
     RECT  72.6 43.331 72.912 46.069 ;
     RECT  67.2 45.347 67.752 46.115 ;
     RECT  56.4 43.429 57.48 46.117 ;
     RECT  61.8 46.069 63.432 46.117 ;
     RECT  53.568 45.155 54.792 46.163 ;
     RECT  0.192 46.069 0.504 46.165 ;
     RECT  22.656 38.675 22.68 46.211 ;
     RECT  80.4 43.669 80.424 46.211 ;
     RECT  2.304 45.635 3.144 46.259 ;
     RECT  21.456 45.541 21.48 46.259 ;
     RECT  40.08 45.685 41.016 46.259 ;
     RECT  61.632 46.117 63.432 46.643 ;
     RECT  90.624 46.117 90.648 46.643 ;
     RECT  10.368 45.635 10.392 46.645 ;
     RECT  82.992 44.483 83.712 46.645 ;
     RECT  12.528 45.541 13.512 46.691 ;
     RECT  29.28 45.731 29.712 46.739 ;
     RECT  27.408 46.069 27.48 46.787 ;
     RECT  53.568 46.163 54.504 46.787 ;
     RECT  34.8 45.683 35.112 46.789 ;
     RECT  45.6 45.635 45.912 46.789 ;
     RECT  72.6 46.069 73.56 46.789 ;
     RECT  7.536 45.877 9.096 46.837 ;
     RECT  45.024 46.789 45.912 46.931 ;
     RECT  24 45.011 24.312 47.029 ;
     RECT  43.392 44.245 43.416 47.029 ;
     RECT  16.512 46.067 17.256 47.075 ;
     RECT  61.632 46.643 62.76 47.075 ;
     RECT  18.6 42.709 19.032 47.173 ;
     RECT  20.4 42.995 20.424 47.173 ;
     RECT  10.368 46.645 10.632 47.221 ;
     RECT  10.368 47.221 10.824 47.267 ;
     RECT  54.48 46.787 54.504 47.269 ;
     RECT  5.952 46.069 6.264 47.317 ;
     RECT  69.264 45.347 69.96 47.363 ;
     RECT  43.392 47.029 43.848 47.365 ;
     RECT  7.392 46.837 9.096 47.411 ;
     RECT  10.608 47.267 10.824 47.411 ;
     RECT  72.048 46.789 73.56 47.459 ;
     RECT  13.2 46.691 13.512 47.509 ;
     RECT  14.688 45.541 15.432 47.509 ;
     RECT  72.048 47.459 72.912 47.555 ;
     RECT  13.2 47.509 15.432 47.651 ;
     RECT  16.512 47.075 16.536 47.651 ;
     RECT  37.392 46.069 37.416 47.699 ;
     RECT  43.344 47.365 43.848 47.843 ;
     RECT  29.4 46.739 29.712 47.845 ;
     RECT  48.72 42.851 49.368 47.845 ;
     RECT  51 44.915 51.312 47.845 ;
     RECT  10.608 47.411 10.632 47.891 ;
     RECT  14.688 47.651 15.432 47.891 ;
     RECT  25.68 38.723 25.704 47.891 ;
     RECT  34.8 46.789 35.928 47.891 ;
     RECT  56.4 46.117 57.528 47.891 ;
     RECT  24 47.029 24.456 47.893 ;
     RECT  45.6 46.931 45.912 47.893 ;
     RECT  48.72 47.845 51.312 47.939 ;
     RECT  82.032 46.645 83.712 47.939 ;
     RECT  0.144 46.165 0.504 47.987 ;
     RECT  45.504 47.893 45.912 48.035 ;
     RECT  0.192 47.987 0.504 48.083 ;
     RECT  78 44.485 79.368 48.083 ;
     RECT  84.864 46.645 84.888 48.083 ;
     RECT  33.504 46.693 33.528 48.131 ;
     RECT  54.48 47.269 55.176 48.133 ;
     RECT  54.48 48.133 55.272 48.275 ;
     RECT  2.304 46.259 2.712 48.371 ;
     RECT  5.664 47.317 6.264 48.371 ;
     RECT  7.8 47.411 9.096 48.371 ;
     RECT  27.456 46.787 27.48 48.371 ;
     RECT  34.8 47.891 35.208 48.467 ;
     RECT  42.144 48.277 42.168 48.467 ;
     RECT  61.8 47.075 62.76 48.515 ;
     RECT  0.384 48.083 0.504 48.563 ;
     RECT  5.664 48.371 6.216 48.661 ;
     RECT  91.584 47.845 91.608 48.803 ;
     RECT  38.448 47.749 38.472 48.805 ;
     RECT  5.136 48.661 6.216 48.851 ;
     RECT  18.6 47.173 20.424 48.901 ;
     RECT  72.6 47.555 72.912 48.901 ;
     RECT  14.688 47.891 14.712 48.949 ;
     RECT  24 47.893 24.504 48.949 ;
     RECT  82.368 47.939 83.712 48.949 ;
     RECT  5.664 48.851 6.216 48.995 ;
     RECT  23.04 48.949 24.504 48.995 ;
     RECT  16.896 48.901 16.92 48.997 ;
     RECT  68.496 48.949 68.52 48.997 ;
     RECT  69.792 47.363 69.96 48.997 ;
     RECT  0.48 48.563 0.504 49.043 ;
     RECT  18.48 48.901 21.048 49.043 ;
     RECT  87.984 44.341 89.112 49.043 ;
     RECT  16.08 48.997 16.92 49.091 ;
     RECT  48.96 47.939 51.312 49.091 ;
     RECT  16.08 49.091 16.344 49.139 ;
     RECT  68.496 48.997 69.96 49.139 ;
     RECT  67.2 46.115 67.512 49.141 ;
     RECT  64.896 48.997 64.92 49.187 ;
     RECT  78 48.083 78.312 49.381 ;
     RECT  16.32 49.139 16.344 49.427 ;
     RECT  7.8 48.371 8.424 49.525 ;
     RECT  61.8 48.515 62.712 49.525 ;
     RECT  18.48 49.043 20.424 49.571 ;
     RECT  26.736 48.949 26.76 49.571 ;
     RECT  48.96 49.091 49.368 49.573 ;
     RECT  23.04 48.995 24.456 49.619 ;
     RECT  66.816 49.141 67.512 49.619 ;
     RECT  68.496 49.139 68.52 49.619 ;
     RECT  31.056 48.949 31.08 49.765 ;
     RECT  6.192 48.995 6.216 49.811 ;
     RECT  86.592 48.901 86.616 49.811 ;
     RECT  54.48 48.275 54.504 49.909 ;
     RECT  91.776 49.525 91.8 49.909 ;
     RECT  61.8 49.525 62.952 49.957 ;
     RECT  80.352 47.845 80.376 50.003 ;
     RECT  31.056 49.765 31.656 50.051 ;
     RECT  29.28 47.845 29.712 50.053 ;
     RECT  34.8 48.467 35.112 50.053 ;
     RECT  42.144 49.525 42.168 50.053 ;
     RECT  82.32 48.949 83.712 50.053 ;
     RECT  40.08 46.259 40.512 50.099 ;
     RECT  60.864 49.957 62.952 50.099 ;
     RECT  82.32 50.053 84.648 50.099 ;
     RECT  40.2 50.099 40.512 50.101 ;
     RECT  88.8 49.043 89.112 50.101 ;
     RECT  11.376 49.333 11.4 50.195 ;
     RECT  41.616 50.053 42.168 50.243 ;
     RECT  69.792 49.139 69.96 50.293 ;
     RECT  52.464 48.949 52.488 50.341 ;
     RECT  91.152 49.909 91.8 50.387 ;
     RECT  52.464 50.341 52.584 50.435 ;
     RECT  68.928 50.293 69.96 50.435 ;
     RECT  58.944 50.005 58.968 50.485 ;
     RECT  67.2 49.619 67.512 50.533 ;
     RECT  79.344 48.083 79.368 50.533 ;
     RECT  7.8 49.525 9.144 50.581 ;
     RECT  58.8 50.485 58.968 50.629 ;
     RECT  88.8 50.101 89.784 50.629 ;
     RECT  91.152 50.387 91.176 50.629 ;
     RECT  57.888 50.629 58.968 50.675 ;
     RECT  43.344 47.843 43.368 50.677 ;
     RECT  27.168 50.533 27.192 50.723 ;
     RECT  7.8 50.581 9.576 50.771 ;
     RECT  43.344 50.677 44.184 50.819 ;
     RECT  47.28 48.229 47.304 50.819 ;
     RECT  48.432 49.573 49.368 50.819 ;
     RECT  88.8 50.629 91.176 50.819 ;
     RECT  69.744 50.435 69.96 50.867 ;
     RECT  53.808 49.909 54.504 50.915 ;
     RECT  18.6 49.571 20.424 51.059 ;
     RECT  31.872 50.533 31.896 51.061 ;
     RECT  29.28 50.053 30.648 51.107 ;
     RECT  40.2 50.101 40.632 51.109 ;
     RECT  90.24 50.819 91.176 51.155 ;
     RECT  37.728 48.805 38.472 51.203 ;
     RECT  77.904 49.381 78.312 51.205 ;
     RECT  79.344 50.533 79.608 51.205 ;
     RECT  86.64 50.869 86.664 51.251 ;
     RECT  67.2 50.533 67.608 51.253 ;
     RECT  72.048 48.901 72.912 51.253 ;
     RECT  72.048 51.253 73.512 51.301 ;
     RECT  9.552 50.771 9.576 51.347 ;
     RECT  29.28 51.107 29.712 51.443 ;
     RECT  90.288 51.155 91.176 51.493 ;
     RECT  92.208 51.205 92.232 51.493 ;
     RECT  21.696 50.629 21.72 51.635 ;
     RECT  14.688 48.949 14.856 51.637 ;
     RECT  15.936 51.445 15.96 51.637 ;
     RECT  20.4 51.059 20.424 51.637 ;
     RECT  53.808 50.915 54.264 51.637 ;
     RECT  76.656 50.533 76.68 51.637 ;
     RECT  77.904 51.205 79.608 51.637 ;
     RECT  14.688 51.637 15.96 51.683 ;
     RECT  48.96 50.819 49.368 51.683 ;
     RECT  56.4 47.891 56.856 51.781 ;
     RECT  57.888 50.675 57.912 51.781 ;
     RECT  38.448 51.203 38.472 51.829 ;
     RECT  49.344 51.683 49.368 51.829 ;
     RECT  51 49.091 51.312 51.829 ;
     RECT  38.448 51.829 38.76 51.875 ;
     RECT  6.576 51.205 6.6 51.923 ;
     RECT  7.8 50.771 8.424 51.923 ;
     RECT  14.688 51.683 15.768 51.923 ;
     RECT  31.872 51.061 32.328 51.923 ;
     RECT  76.656 51.637 79.608 51.923 ;
     RECT  90.288 51.493 92.232 51.923 ;
     RECT  24 49.619 24.456 51.973 ;
     RECT  76.656 51.923 78.312 52.019 ;
     RECT  79.584 51.923 79.608 52.163 ;
     RECT  7.8 51.923 8.328 52.211 ;
     RECT  71.808 51.301 73.512 52.355 ;
     RECT  2.4 48.371 2.712 52.405 ;
     RECT  6.288 52.165 6.312 52.405 ;
     RECT  26.064 50.677 26.088 52.451 ;
     RECT  14.688 51.923 14.712 52.499 ;
     RECT  20.4 51.637 20.568 52.499 ;
     RECT  40.2 51.109 41.592 52.499 ;
     RECT  24 51.973 24.504 52.693 ;
     RECT  76.656 52.019 76.92 52.739 ;
     RECT  49.344 51.829 51.312 52.931 ;
     RECT  56.4 51.781 57.912 52.931 ;
     RECT  69.744 50.867 69.768 52.979 ;
     RECT  71.808 52.355 72.912 52.979 ;
     RECT  15.744 51.923 15.768 52.981 ;
     RECT  22.128 52.405 22.152 52.981 ;
     RECT  45.6 48.035 45.912 52.981 ;
     RECT  53.568 51.637 54.264 53.027 ;
     RECT  90.288 51.923 91.368 53.075 ;
     RECT  80.928 52.981 80.952 53.077 ;
     RECT  88.8 50.819 89.112 53.077 ;
     RECT  80.928 53.077 81.048 53.123 ;
     RECT  43.344 50.819 43.368 53.507 ;
     RECT  88.8 53.077 89.544 53.507 ;
     RECT  40.2 52.499 40.632 53.509 ;
     RECT  45.6 52.981 46.728 53.509 ;
     RECT  24 52.693 24.648 53.557 ;
     RECT  11.376 51.781 11.4 53.603 ;
     RECT  44.976 53.509 46.728 53.603 ;
     RECT  53.664 53.027 54.264 53.603 ;
     RECT  29.4 51.443 29.712 53.605 ;
     RECT  2.4 52.405 2.856 53.747 ;
     RECT  20.4 52.499 20.424 53.797 ;
     RECT  22.128 52.981 22.248 53.843 ;
     RECT  72.384 52.979 72.912 54.035 ;
     RECT  14.832 52.981 15.768 54.085 ;
     RECT  31.872 51.923 31.896 54.085 ;
     RECT  82.896 50.099 84.648 54.085 ;
     RECT  88.8 53.507 89.448 54.133 ;
     RECT  86.592 53.317 86.616 54.179 ;
     RECT  27.936 52.789 27.96 54.325 ;
     RECT  29.088 53.605 29.712 54.325 ;
     RECT  14.832 54.085 16.008 54.371 ;
     RECT  13.2 47.651 13.512 54.469 ;
     RECT  82.032 54.085 84.648 54.611 ;
     RECT  33.888 50.053 35.112 54.613 ;
     RECT  31.872 54.085 32.28 54.659 ;
     RECT  31.872 54.659 31.896 54.755 ;
     RECT  88.08 54.133 89.448 54.755 ;
     RECT  22.224 53.843 22.248 55.045 ;
     RECT  67.2 51.253 68.328 55.045 ;
     RECT  81.024 53.123 81.048 55.045 ;
     RECT  80.928 55.045 81.048 55.091 ;
     RECT  80.928 55.091 80.952 55.187 ;
     RECT  18.6 51.059 19.416 55.189 ;
     RECT  12.72 54.469 13.512 55.235 ;
     RECT  18.48 55.189 19.416 55.235 ;
     RECT  56.4 52.931 57.768 55.237 ;
     RECT  52.56 50.435 52.584 55.331 ;
     RECT  91.248 53.075 91.272 55.331 ;
     RECT  56.4 55.237 58.008 55.333 ;
     RECT  56.4 55.333 58.152 55.379 ;
     RECT  56.4 55.379 56.856 55.475 ;
     RECT  72.432 54.035 72.912 55.667 ;
     RECT  39.984 53.509 41.016 55.669 ;
     RECT  79.872 54.517 79.896 55.669 ;
     RECT  37.008 55.429 37.032 55.715 ;
     RECT  39.888 55.669 41.016 55.715 ;
     RECT  79.872 55.669 80.328 55.717 ;
     RECT  7.8 52.211 8.112 55.813 ;
     RECT  38.736 51.875 38.76 55.813 ;
     RECT  54.24 53.603 54.264 55.813 ;
     RECT  76.896 52.739 76.92 55.813 ;
     RECT  33.552 54.613 35.112 55.859 ;
     RECT  15.744 54.371 16.008 55.861 ;
     RECT  5.568 52.405 6.312 55.907 ;
     RECT  86.544 55.237 86.568 55.907 ;
     RECT  22.176 55.045 22.248 55.955 ;
     RECT  27.936 54.325 29.712 55.955 ;
     RECT  50.688 52.931 51.312 55.955 ;
     RECT  57.984 55.379 58.152 55.955 ;
     RECT  59.808 54.565 59.832 55.955 ;
     RECT  66.192 55.285 66.216 55.955 ;
     RECT  82.032 54.611 83.712 55.955 ;
     RECT  53.04 55.861 53.064 56.003 ;
     RECT  18.48 55.235 19.032 56.147 ;
     RECT  82.896 55.955 83.712 56.149 ;
     RECT  70.944 55.045 70.968 56.195 ;
     RECT  29.4 55.955 29.712 56.341 ;
     RECT  5.568 55.907 5.592 56.389 ;
     RECT  61.8 50.099 62.952 56.389 ;
     RECT  79.776 55.717 80.328 56.389 ;
     RECT  61.8 56.389 63.24 56.435 ;
     RECT  15.744 55.861 16.584 56.483 ;
     RECT  67.2 55.045 68.568 56.483 ;
     RECT  76.368 55.813 76.92 56.483 ;
     RECT  54.24 55.813 54.696 56.531 ;
     RECT  24 53.557 25.128 56.579 ;
     RECT  79.536 56.389 80.328 56.579 ;
     RECT  82.896 56.149 84.552 56.723 ;
     RECT  11.04 55.429 11.064 56.771 ;
     RECT  42.768 55.237 42.792 56.771 ;
     RECT  36.576 56.389 36.6 56.773 ;
     RECT  72.6 55.667 72.912 56.869 ;
     RECT  77.904 52.019 78.312 56.869 ;
     RECT  36.576 56.773 36.84 56.963 ;
     RECT  18.48 56.147 18.912 57.013 ;
     RECT  76.896 56.483 76.92 57.013 ;
     RECT  77.904 56.869 78.408 57.013 ;
     RECT  7.68 55.813 8.112 57.059 ;
     RECT  22.176 55.955 22.2 57.059 ;
     RECT  38.208 55.813 38.76 57.059 ;
     RECT  44.976 53.603 45.912 57.059 ;
     RECT  67.2 56.483 68.328 57.059 ;
     RECT  76.896 57.013 78.408 57.059 ;
     RECT  15.744 56.483 15.768 57.299 ;
     RECT  31.488 55.813 31.512 57.299 ;
     RECT  56.4 55.475 56.712 57.301 ;
     RECT  29.4 56.341 29.88 57.347 ;
     RECT  58.032 55.955 58.152 57.347 ;
     RECT  9.744 56.245 9.768 57.349 ;
     RECT  4.704 56.389 5.592 57.395 ;
     RECT  27.936 55.955 27.96 57.443 ;
     RECT  34.176 55.859 35.112 57.443 ;
     RECT  55.776 57.301 56.712 57.445 ;
     RECT  88.8 54.755 89.112 57.445 ;
     RECT  17.616 57.013 18.912 57.541 ;
     RECT  24 56.579 24.408 57.541 ;
     RECT  54.24 56.531 54.264 57.541 ;
     RECT  20.4 53.797 21.096 57.635 ;
     RECT  39.888 55.715 40.512 57.635 ;
     RECT  64.992 57.013 65.016 57.635 ;
     RECT  82.896 56.723 83.712 57.635 ;
     RECT  79.536 56.579 79.8 57.971 ;
     RECT  77.472 57.059 78.408 58.021 ;
     RECT  79.536 57.971 79.56 58.021 ;
     RECT  26.688 56.437 26.712 58.115 ;
     RECT  53.52 57.541 54.264 58.117 ;
     RECT  86.16 57.445 86.184 58.117 ;
     RECT  87.168 58.069 87.192 58.117 ;
     RECT  4.704 57.395 4.728 58.163 ;
     RECT  63.216 56.435 63.24 58.163 ;
     RECT  71.856 56.869 72.912 58.163 ;
     RECT  86.16 58.117 87.192 58.163 ;
     RECT  36.576 56.963 36.6 58.165 ;
     RECT  83.4 57.635 83.712 58.213 ;
     RECT  28.272 58.069 28.296 58.259 ;
     RECT  36.576 58.165 37.08 58.307 ;
     RECT  9.696 57.349 9.768 58.355 ;
     RECT  12.096 56.341 12.12 58.355 ;
     RECT  75.312 56.869 75.336 58.355 ;
     RECT  53.04 58.117 54.264 58.403 ;
     RECT  83.4 58.213 84.648 58.501 ;
     RECT  44.16 58.453 44.184 58.595 ;
     RECT  9.744 58.355 9.768 58.597 ;
     RECT  21.072 57.635 21.096 58.597 ;
     RECT  80.976 58.261 81 58.597 ;
     RECT  9.744 58.597 10.2 58.643 ;
     RECT  20.544 58.597 21.096 58.643 ;
     RECT  13.2 55.235 13.512 58.645 ;
     RECT  77.472 58.021 79.56 58.691 ;
     RECT  80.976 58.597 81.144 58.691 ;
     RECT  77.472 58.691 79.224 58.739 ;
     RECT  88.272 57.445 89.112 58.739 ;
     RECT  83.4 58.501 84.936 58.741 ;
     RECT  76.416 57.541 76.44 59.029 ;
     RECT  36.576 58.307 37.032 59.075 ;
     RECT  72.48 58.163 72.912 59.075 ;
     RECT  90.096 58.117 90.36 59.219 ;
     RECT  17.616 57.541 19.176 59.269 ;
     RECT  86.4 58.163 87.192 59.315 ;
     RECT  90.336 59.219 90.36 59.315 ;
     RECT  17.136 59.269 19.176 59.459 ;
     RECT  83.4 58.741 84.984 59.459 ;
     RECT  40.2 57.635 40.512 59.557 ;
     RECT  17.136 59.459 18.912 59.651 ;
     RECT  55.344 57.445 56.712 59.651 ;
     RECT  17.616 59.651 18.912 59.699 ;
     RECT  81.12 58.691 81.144 59.701 ;
     RECT  59.664 58.693 59.688 59.747 ;
     RECT  92.448 57.541 92.472 59.747 ;
     RECT  61.8 56.435 62.112 59.749 ;
     RECT  31.2 58.645 31.224 59.795 ;
     RECT  69.696 58.693 69.72 59.795 ;
     RECT  12.816 58.645 13.512 59.797 ;
     RECT  36.576 59.075 36.6 59.845 ;
     RECT  24 57.541 24.696 59.891 ;
     RECT  42.768 59.029 42.792 59.891 ;
     RECT  53.04 58.403 53.064 59.891 ;
     RECT  86.4 59.315 86.424 59.891 ;
     RECT  78 58.739 79.224 59.939 ;
     RECT  55.776 59.651 56.712 59.987 ;
     RECT  3.888 58.501 3.912 60.035 ;
     RECT  36.528 59.845 36.6 60.035 ;
     RECT  80.352 59.701 81.144 60.085 ;
     RECT  6.384 59.605 6.408 60.373 ;
     RECT  54.24 58.403 54.264 60.373 ;
     RECT  56.4 59.987 56.712 60.373 ;
     RECT  84.96 59.459 84.984 60.373 ;
     RECT  88.8 58.739 89.112 60.373 ;
     RECT  5.664 60.373 6.408 60.419 ;
     RECT  75.792 59.029 76.44 60.419 ;
     RECT  2.4 53.747 2.808 60.467 ;
     RECT  10.176 58.643 10.2 60.515 ;
     RECT  80.352 60.085 81.192 60.517 ;
     RECT  79.824 60.517 81.192 60.563 ;
     RECT  12.816 59.797 14.232 60.659 ;
     RECT  61.68 59.749 62.112 60.707 ;
     RECT  2.4 60.467 2.712 60.853 ;
     RECT  5.664 60.419 5.688 60.899 ;
     RECT  24 59.891 24.408 60.899 ;
     RECT  7.8 57.059 8.112 60.949 ;
     RECT  15.312 57.445 15.336 60.949 ;
     RECT  49.344 52.931 49.368 60.949 ;
     RECT  67.2 57.059 67.512 60.949 ;
     RECT  34.8 57.443 35.112 60.997 ;
     RECT  22.464 60.373 22.488 61.091 ;
     RECT  40.2 59.557 40.968 61.091 ;
     RECT  67.2 60.949 67.608 61.331 ;
     RECT  88.8 60.373 89.544 61.381 ;
     RECT  24 60.899 24.312 61.429 ;
     RECT  84.96 60.373 85.272 61.525 ;
     RECT  74.688 60.277 74.712 61.571 ;
     RECT  34.416 60.997 35.112 61.619 ;
     RECT  48.48 60.949 49.368 61.619 ;
     RECT  53.28 60.373 54.264 61.619 ;
     RECT  56.4 60.373 56.808 61.619 ;
     RECT  14.88 60.949 15.336 61.715 ;
     RECT  91.632 60.949 91.656 61.907 ;
     RECT  88.8 61.381 89.976 62.003 ;
     RECT  2.304 60.853 2.712 62.005 ;
     RECT  54.24 61.619 54.264 62.005 ;
     RECT  54.24 62.005 55.128 62.147 ;
     RECT  27.36 60.949 27.384 62.149 ;
     RECT  68.832 61.093 68.856 62.149 ;
     RECT  2.304 62.005 3.336 62.195 ;
     RECT  72.6 59.075 72.912 62.245 ;
     RECT  6.96 60.949 8.112 62.435 ;
     RECT  27.36 62.149 27.768 62.435 ;
     RECT  79.824 60.563 79.848 62.435 ;
     RECT  84.96 61.525 85.512 62.435 ;
     RECT  61.8 60.707 62.112 62.533 ;
     RECT  34.8 61.619 35.112 62.581 ;
     RECT  15.312 61.715 15.336 62.677 ;
     RECT  20.544 58.643 20.568 62.677 ;
     RECT  21.6 61.333 21.624 62.677 ;
     RECT  78 59.939 78.312 62.677 ;
     RECT  17.568 60.901 17.592 62.723 ;
     RECT  2.4 62.195 3.336 62.771 ;
     RECT  23.376 61.429 24.312 62.771 ;
     RECT  25.776 62.005 25.8 62.771 ;
     RECT  72.6 62.245 73.224 62.963 ;
     RECT  75.168 61.909 75.192 62.963 ;
     RECT  20.16 62.677 21.624 63.011 ;
     RECT  31.248 61.381 31.272 63.059 ;
     RECT  70.944 61.429 70.968 63.061 ;
     RECT  68.688 62.149 68.856 63.107 ;
     RECT  70.944 63.061 71.304 63.157 ;
     RECT  72.6 62.963 73.032 63.157 ;
     RECT  81.168 60.563 81.192 63.157 ;
     RECT  68.688 63.107 68.712 63.203 ;
     RECT  84.96 62.435 84.984 63.203 ;
     RECT  52.608 62.677 52.632 63.205 ;
     RECT  87.792 62.725 87.816 63.205 ;
     RECT  88.8 62.003 89.112 63.205 ;
     RECT  7.44 62.435 8.112 63.299 ;
     RECT  33.072 61.477 33.096 63.299 ;
     RECT  83.4 59.459 83.712 63.301 ;
     RECT  15.312 62.677 15.48 63.539 ;
     RECT  87.792 63.205 89.112 63.539 ;
     RECT  70.944 63.157 73.032 63.683 ;
     RECT  27.744 62.435 27.768 63.685 ;
     RECT  36.576 60.035 36.6 63.685 ;
     RECT  83.088 63.301 83.712 63.779 ;
     RECT  51 55.955 51.312 63.781 ;
     RECT  52.608 63.205 53.064 63.781 ;
     RECT  76.416 60.419 76.44 63.781 ;
     RECT  76.416 63.781 76.92 63.827 ;
     RECT  46.896 60.373 46.92 64.019 ;
     RECT  51 63.781 53.064 64.019 ;
     RECT  20.16 63.011 20.568 64.067 ;
     RECT  34.8 62.581 35.496 64.069 ;
     RECT  61.584 62.533 62.112 64.069 ;
     RECT  78 62.677 78.696 64.069 ;
     RECT  65.664 62.773 65.688 64.115 ;
     RECT  81.168 63.157 82.056 64.115 ;
     RECT  45.6 57.059 45.912 64.165 ;
     RECT  6.24 62.725 6.264 64.309 ;
     RECT  45.456 64.165 45.912 64.357 ;
     RECT  78 64.069 79.272 64.357 ;
     RECT  88.8 63.539 89.112 64.357 ;
     RECT  15.312 63.539 15.336 64.405 ;
     RECT  40.2 61.091 40.512 64.405 ;
     RECT  15.072 64.405 15.336 64.451 ;
     RECT  31.296 63.157 31.32 64.451 ;
     RECT  87.792 63.539 87.816 64.451 ;
     RECT  21.6 63.011 21.624 64.597 ;
     RECT  70.944 63.683 72.912 64.597 ;
     RECT  9.456 62.821 9.48 64.643 ;
     RECT  15.072 64.451 15.096 64.693 ;
     RECT  70.8 64.597 72.912 64.787 ;
     RECT  34.176 64.069 35.496 64.835 ;
     RECT  6.24 64.309 6.648 64.931 ;
     RECT  82.032 64.115 82.056 64.931 ;
     RECT  27.744 63.685 27.912 64.979 ;
     RECT  34.8 64.835 35.496 65.075 ;
     RECT  56.4 61.619 56.712 65.269 ;
     RECT  12.816 60.659 13.512 65.317 ;
     RECT  78 64.357 79.608 65.413 ;
     RECT  24 62.771 24.312 65.461 ;
     RECT  83.28 63.779 83.712 65.507 ;
     RECT  58.032 57.347 58.056 65.509 ;
     RECT  47.328 64.933 47.352 65.603 ;
     RECT  61.584 64.069 62.76 65.603 ;
     RECT  88.8 64.357 89.64 65.699 ;
     RECT  51 64.019 52.632 65.797 ;
     RECT  86.64 65.173 86.664 65.845 ;
     RECT  14.544 64.693 15.096 65.893 ;
     RECT  50.88 65.797 52.632 65.939 ;
     RECT  78 65.413 80.424 65.939 ;
     RECT  14.544 65.893 15.192 65.941 ;
     RECT  52.464 65.939 52.632 65.987 ;
     RECT  75.264 64.837 75.288 65.989 ;
     RECT  20.544 64.067 20.568 66.085 ;
     RECT  21.6 64.597 21.816 66.085 ;
     RECT  67.2 61.331 67.512 66.085 ;
     RECT  70.896 64.787 72.912 66.085 ;
     RECT  20.544 66.085 21.816 66.131 ;
     RECT  40.2 64.405 40.68 66.133 ;
     RECT  42.048 62.101 42.072 66.133 ;
     RECT  74.592 65.989 75.288 66.133 ;
     RECT  27.744 64.979 27.768 66.179 ;
     RECT  40.2 66.133 42.072 66.179 ;
     RECT  7.8 63.299 8.112 66.181 ;
     RECT  12.528 65.317 13.512 66.227 ;
     RECT  6.624 64.931 6.648 66.229 ;
     RECT  7.68 66.181 8.112 66.229 ;
     RECT  45.456 64.357 46.104 66.275 ;
     RECT  14.544 65.941 15.384 66.323 ;
     RECT  6.624 66.229 8.112 66.371 ;
     RECT  34.8 65.075 35.112 66.373 ;
     RECT  56.064 65.269 56.712 66.373 ;
     RECT  88.8 65.699 89.112 66.373 ;
     RECT  36.48 63.685 36.6 66.419 ;
     RECT  52.464 65.987 52.488 66.419 ;
     RECT  55.872 66.373 56.712 66.517 ;
     RECT  57.936 65.509 58.056 66.517 ;
     RECT  55.872 66.517 58.056 66.563 ;
     RECT  83.4 65.507 83.712 66.565 ;
     RECT  86.352 65.845 86.664 66.565 ;
     RECT  87.84 66.373 89.112 66.565 ;
     RECT  54.24 62.147 54.264 66.613 ;
     RECT  76.896 63.827 76.92 66.613 ;
     RECT  78 65.939 79.272 66.613 ;
     RECT  27.984 66.181 28.008 66.661 ;
     RECT  29.4 57.347 29.712 66.661 ;
     RECT  81.84 65.461 81.864 66.661 ;
     RECT  56.064 66.563 58.056 66.707 ;
     RECT  80.4 65.939 80.424 66.707 ;
     RECT  14.544 66.323 15.192 66.755 ;
     RECT  45.456 66.275 46.008 66.755 ;
     RECT  83.4 66.565 84.12 66.755 ;
     RECT  56.304 66.707 58.056 66.803 ;
     RECT  69.504 66.613 69.528 66.853 ;
     RECT  70.896 66.085 73.464 66.853 ;
     RECT  69.504 66.853 73.464 66.899 ;
     RECT  27.984 66.661 29.712 66.995 ;
     RECT  74.496 66.133 75.288 66.995 ;
     RECT  66.72 66.085 67.512 67.043 ;
     RECT  54.24 66.613 54.984 67.141 ;
     RECT  28.416 66.995 29.712 67.235 ;
     RECT  20.88 66.131 21.816 67.237 ;
     RECT  34.8 66.373 35.208 67.237 ;
     RECT  61.584 65.603 62.112 67.237 ;
     RECT  76.896 66.613 79.272 67.283 ;
     RECT  5.52 66.613 5.544 67.331 ;
     RECT  7.68 66.371 8.112 67.379 ;
     RECT  36.576 66.419 36.6 67.379 ;
     RECT  54.144 67.141 54.984 67.571 ;
     RECT  81.504 66.661 81.864 67.667 ;
     RECT  86.352 66.565 89.112 67.667 ;
     RECT  40.2 66.179 41.352 67.717 ;
     RECT  34.8 67.237 35.352 67.765 ;
     RECT  64.032 67.141 64.056 67.765 ;
     RECT  38.16 66.661 38.184 67.811 ;
     RECT  34.704 67.765 35.352 67.859 ;
     RECT  45.6 66.755 46.008 67.859 ;
     RECT  69.504 66.899 72.912 67.859 ;
     RECT  86.352 67.667 86.376 67.859 ;
     RECT  26.784 66.805 26.808 67.907 ;
     RECT  71.664 67.859 72.912 67.907 ;
     RECT  61.584 67.237 63 68.099 ;
     RECT  54.144 67.571 54.264 68.195 ;
     RECT  10.32 65.941 10.344 68.243 ;
     RECT  30.72 67.717 30.744 68.243 ;
     RECT  42.672 68.149 42.696 68.291 ;
     RECT  5.472 67.813 5.496 68.341 ;
     RECT  6.624 66.371 6.648 68.341 ;
     RECT  14.544 66.755 15.096 68.341 ;
     RECT  49.344 61.619 49.368 68.341 ;
     RECT  66.144 67.765 66.168 68.341 ;
     RECT  67.2 67.043 67.512 68.341 ;
     RECT  80.304 67.621 80.328 68.341 ;
     RECT  5.472 68.341 6.648 68.387 ;
     RECT  69.504 67.859 70.248 68.387 ;
     RECT  7.8 67.379 8.112 68.389 ;
     RECT  40.08 67.717 41.352 68.435 ;
     RECT  76.896 67.283 78.408 68.531 ;
     RECT  5.472 68.387 6.36 68.579 ;
     RECT  19.968 67.237 21.816 68.867 ;
     RECT  56.304 66.803 56.712 68.869 ;
     RECT  74.592 66.995 75.288 68.917 ;
     RECT  76.896 68.531 78.312 68.917 ;
     RECT  34.704 67.859 35.208 68.963 ;
     RECT  40.08 68.435 40.512 68.965 ;
     RECT  64.032 67.765 64.44 68.965 ;
     RECT  49.152 68.341 49.368 69.011 ;
     RECT  66.144 68.341 67.512 69.011 ;
     RECT  6.336 68.579 6.36 69.059 ;
     RECT  20.88 68.867 21.816 69.059 ;
     RECT  37.632 68.965 37.656 69.107 ;
     RECT  64.032 68.965 65.016 69.107 ;
     RECT  49.152 69.011 49.176 69.155 ;
     RECT  58.032 66.803 58.056 69.157 ;
     RECT  57.84 69.157 58.056 69.203 ;
     RECT  79.632 68.341 80.328 69.203 ;
     RECT  74.592 68.917 78.312 69.301 ;
     RECT  87.84 67.667 89.112 69.395 ;
     RECT  56.16 68.869 56.712 69.443 ;
     RECT  26.208 68.821 26.232 69.491 ;
     RECT  66.816 69.011 67.512 69.493 ;
     RECT  29.4 67.235 29.712 69.541 ;
     RECT  14.544 68.341 15.432 69.587 ;
     RECT  16.56 66.277 16.584 69.587 ;
     RECT  50.88 65.939 51.312 69.587 ;
     RECT  56.304 69.443 56.712 69.587 ;
     RECT  61.584 68.099 62.112 69.587 ;
     RECT  14.544 69.587 15.24 69.875 ;
     RECT  33.6 68.917 33.624 69.971 ;
     RECT  34.704 68.963 35.112 70.021 ;
     RECT  72.6 67.907 72.912 70.021 ;
     RECT  73.968 69.301 78.312 70.067 ;
     RECT  24 65.461 24.84 70.115 ;
     RECT  7.8 68.389 8.568 70.165 ;
     RECT  0.144 68.293 0.168 70.211 ;
     RECT  6.816 70.165 8.568 70.259 ;
     RECT  66.816 69.493 67.848 70.259 ;
     RECT  21.024 69.059 21.816 70.307 ;
     RECT  6.816 70.259 8.112 70.403 ;
     RECT  2.4 62.771 2.712 70.405 ;
     RECT  34.464 70.021 35.112 70.405 ;
     RECT  15.072 69.875 15.24 70.499 ;
     RECT  74.592 70.067 78.312 70.499 ;
     RECT  18.6 59.699 18.912 70.597 ;
     RECT  45.6 67.859 45.912 70.645 ;
     RECT  87.12 70.069 87.144 70.691 ;
     RECT  42.144 70.069 42.168 70.739 ;
     RECT  72.336 70.021 72.912 70.739 ;
     RECT  74.592 70.499 76.152 70.739 ;
     RECT  21.024 70.307 21.048 70.885 ;
     RECT  76.08 70.739 76.152 71.075 ;
     RECT  80.304 69.203 80.328 71.077 ;
     RECT  34.464 70.405 35.544 71.123 ;
     RECT  5.664 70.213 5.688 71.221 ;
     RECT  80.304 71.077 80.808 71.221 ;
     RECT  52.464 69.877 52.488 71.267 ;
     RECT  20.784 70.885 21.048 71.315 ;
     RECT  55.296 70.069 55.32 71.315 ;
     RECT  10.704 70.069 10.728 71.363 ;
     RECT  2.4 70.405 2.808 71.459 ;
     RECT  2.4 71.459 2.712 71.461 ;
     RECT  12.816 66.227 13.512 71.461 ;
     RECT  56.4 69.587 56.712 71.509 ;
     RECT  0.144 71.365 0.168 71.555 ;
     RECT  45.312 70.645 45.912 71.603 ;
     RECT  5.088 71.221 5.688 71.651 ;
     RECT  29.4 69.541 30.264 71.651 ;
     RECT  2.112 71.461 2.712 71.653 ;
     RECT  1.68 71.653 2.712 71.795 ;
     RECT  27.36 70.021 27.384 71.843 ;
     RECT  74.592 70.739 74.856 71.939 ;
     RECT  39.84 68.965 40.512 71.989 ;
     RECT  88.224 69.395 89.112 72.131 ;
     RECT  83.4 66.755 83.712 72.133 ;
     RECT  20.784 71.315 21 72.179 ;
     RECT  77.472 70.499 78.312 72.179 ;
     RECT  7.8 70.403 8.112 72.181 ;
     RECT  12.816 71.461 13.608 72.325 ;
     RECT  15.072 70.499 15.096 72.325 ;
     RECT  30.864 72.133 30.888 72.325 ;
     RECT  31.92 68.917 31.944 72.325 ;
     RECT  70.224 68.387 70.248 72.325 ;
     RECT  69.264 72.325 70.68 72.419 ;
     RECT  56.304 71.509 56.712 72.469 ;
     RECT  57.84 69.203 57.864 72.469 ;
     RECT  54.144 68.195 54.168 72.515 ;
     RECT  5.088 71.651 5.112 72.707 ;
     RECT  6.864 72.181 8.112 72.709 ;
     RECT  66.816 70.259 67.512 72.757 ;
     RECT  66.384 72.757 67.512 72.805 ;
     RECT  65.904 72.805 67.512 72.901 ;
     RECT  41.568 72.757 41.592 72.947 ;
     RECT  34.704 71.123 35.112 72.949 ;
     RECT  56.304 72.469 57.864 72.949 ;
     RECT  59.04 72.805 59.064 72.949 ;
     RECT  43.776 72.325 43.8 72.995 ;
     RECT  24 70.115 24.312 72.997 ;
     RECT  64.032 69.107 64.056 72.997 ;
     RECT  69.264 72.419 69.288 73.043 ;
     RECT  56.304 72.949 59.064 73.091 ;
     RECT  30.864 72.325 31.944 73.141 ;
     RECT  30.816 73.141 31.944 73.235 ;
     RECT  18.48 70.597 18.912 73.283 ;
     RECT  39.456 71.989 40.512 73.285 ;
     RECT  0.144 73.045 0.168 73.331 ;
     RECT  30.816 73.235 30.936 73.475 ;
     RECT  18.6 73.283 18.912 73.477 ;
     RECT  6.864 72.709 8.568 73.571 ;
     RECT  30.816 73.475 30.888 73.619 ;
     RECT  56.304 73.091 56.712 73.619 ;
     RECT  61.632 69.587 62.112 73.669 ;
     RECT  12.816 72.325 15.768 73.763 ;
     RECT  70.368 72.419 70.68 73.765 ;
     RECT  38.16 72.901 38.184 73.813 ;
     RECT  39.312 73.285 40.512 73.813 ;
     RECT  70.368 73.765 71.4 73.907 ;
     RECT  76.128 71.075 76.152 74.005 ;
     RECT  77.616 72.179 78.312 74.005 ;
     RECT  30.864 73.619 30.888 74.051 ;
     RECT  54.96 72.901 54.984 74.053 ;
     RECT  64.032 72.997 64.44 74.053 ;
     RECT  70.368 73.907 70.68 74.099 ;
     RECT  57.84 73.091 59.064 74.147 ;
     RECT  60.432 73.477 60.456 74.147 ;
     RECT  61.584 73.669 62.112 74.147 ;
     RECT  83.232 72.133 83.712 74.147 ;
     RECT  86.688 73.525 86.712 74.147 ;
     RECT  25.632 73.477 25.656 74.149 ;
     RECT  79.824 71.221 80.808 74.195 ;
     RECT  25.632 74.149 25.848 74.243 ;
     RECT  63.264 74.053 64.44 74.291 ;
     RECT  65.904 72.901 68.28 74.291 ;
     RECT  34.608 72.949 35.112 74.293 ;
     RECT  49.584 73.477 49.608 74.339 ;
     RECT  20.784 72.179 20.808 74.435 ;
     RECT  25.68 74.243 25.848 74.435 ;
     RECT  66.384 74.291 68.28 74.437 ;
     RECT  88.8 72.131 89.112 74.485 ;
     RECT  34.416 74.293 35.112 74.533 ;
     RECT  38.16 73.813 40.512 74.579 ;
     RECT  31.92 73.235 31.944 74.581 ;
     RECT  31.92 74.581 32.184 74.627 ;
     RECT  90.384 74.485 90.408 74.627 ;
     RECT  70.368 74.099 70.392 74.629 ;
     RECT  88.8 74.485 89.304 74.629 ;
     RECT  54.96 74.053 55.08 74.677 ;
     RECT  54.288 74.677 55.08 74.723 ;
     RECT  63.264 74.291 64.056 74.771 ;
     RECT  18.6 73.477 19.368 74.867 ;
     RECT  81.84 67.667 81.864 74.867 ;
     RECT  21.36 74.773 21.384 74.915 ;
     RECT  76.128 74.005 78.312 74.915 ;
     RECT  80.784 74.195 80.808 74.965 ;
     RECT  30.72 75.109 30.744 75.157 ;
     RECT  45.6 71.603 45.912 75.157 ;
     RECT  47.04 74.581 47.064 75.157 ;
     RECT  61.632 74.147 62.112 75.157 ;
     RECT  45.6 75.157 47.064 75.203 ;
     RECT  18.6 74.867 18.912 75.205 ;
     RECT  7.68 73.571 8.112 75.299 ;
     RECT  69.84 74.629 70.392 75.299 ;
     RECT  87.936 74.629 89.304 75.299 ;
     RECT  45.6 75.203 46.776 75.347 ;
     RECT  38.16 74.579 38.184 75.395 ;
     RECT  33.408 73.477 33.432 75.443 ;
     RECT  86.64 75.157 86.664 75.491 ;
     RECT  64.032 74.771 64.056 75.493 ;
     RECT  72.6 70.739 72.912 75.541 ;
     RECT  88.8 75.299 89.304 75.541 ;
     RECT  18.48 75.205 18.912 75.589 ;
     RECT  24 72.997 24.504 75.637 ;
     RECT  17.952 75.589 18.912 75.827 ;
     RECT  5.184 74.629 5.208 75.875 ;
     RECT  34.416 74.533 35.88 75.877 ;
     RECT  36.96 74.053 36.984 75.877 ;
     RECT  14.784 73.763 15.768 75.923 ;
     RECT  18.48 75.827 18.912 75.923 ;
     RECT  25.68 74.435 25.704 75.923 ;
     RECT  34.416 75.877 36.984 75.923 ;
     RECT  26.88 75.541 26.904 75.925 ;
     RECT  76.128 74.915 76.152 75.925 ;
     RECT  77.376 74.915 78.312 75.925 ;
     RECT  12.816 73.763 13.512 75.971 ;
     RECT  39.84 74.579 40.512 76.067 ;
     RECT  26.784 75.925 26.904 76.115 ;
     RECT  54.288 74.723 54.984 76.165 ;
     RECT  34.416 75.923 35.256 76.213 ;
     RECT  32.16 74.627 32.184 76.259 ;
     RECT  54.24 76.165 54.984 76.355 ;
     RECT  45.6 75.347 46.152 76.357 ;
     RECT  56.4 73.619 56.712 76.357 ;
     RECT  57.84 74.147 58.2 76.357 ;
     RECT  24 75.637 24.6 76.403 ;
     RECT  30.72 75.157 30.936 76.403 ;
     RECT  66.384 74.437 68.376 76.403 ;
     RECT  71.808 75.541 72.912 76.451 ;
     RECT  17.088 76.309 17.16 76.499 ;
     RECT  84.912 75.493 84.936 76.499 ;
     RECT  88.8 75.541 89.88 76.645 ;
     RECT  0.288 76.549 0.312 76.787 ;
     RECT  17.136 76.499 17.16 76.787 ;
     RECT  69.84 75.299 69.864 76.789 ;
     RECT  76.128 75.925 78.312 76.835 ;
     RECT  36.432 75.923 36.984 76.885 ;
     RECT  88.224 76.645 89.88 76.885 ;
     RECT  44.688 76.357 46.152 76.931 ;
     RECT  26.88 76.115 26.904 76.979 ;
     RECT  36.432 76.885 37.944 76.979 ;
     RECT  77.04 76.835 78.312 76.979 ;
     RECT  43.584 73.429 43.608 77.029 ;
     RECT  44.688 76.931 46.008 77.029 ;
     RECT  43.584 77.029 46.008 77.075 ;
     RECT  13.056 75.971 13.512 77.077 ;
     RECT  61.584 75.157 62.112 77.123 ;
     RECT  56.4 76.357 58.728 77.171 ;
     RECT  87.792 76.885 89.88 77.173 ;
     RECT  36.96 76.979 37.944 77.267 ;
     RECT  83.28 74.147 83.712 77.315 ;
     RECT  56.4 77.171 58.2 77.363 ;
     RECT  24 76.403 24.504 77.507 ;
     RECT  43.92 77.075 46.008 77.507 ;
     RECT  9.648 76.021 9.672 77.555 ;
     RECT  56.4 77.363 57.864 77.555 ;
     RECT  64.032 75.493 65.016 77.555 ;
     RECT  86.976 77.173 89.88 77.555 ;
     RECT  49.872 75.637 49.896 77.557 ;
     RECT  51 69.587 51.312 77.557 ;
     RECT  69.84 76.789 70.824 77.605 ;
     RECT  13.056 77.077 13.608 77.651 ;
     RECT  45.6 77.507 46.008 77.699 ;
     RECT  64.032 77.555 64.344 77.795 ;
     RECT  67.2 76.403 68.376 77.893 ;
     RECT  69.408 77.605 70.824 77.893 ;
     RECT  6.432 76.357 6.456 77.939 ;
     RECT  18.6 75.923 18.912 77.989 ;
     RECT  29.4 71.651 29.712 78.037 ;
     RECT  21.648 76.357 21.672 78.083 ;
     RECT  43.92 77.507 43.944 78.179 ;
     RECT  86.976 77.555 87 78.323 ;
     RECT  49.872 77.557 51.912 78.371 ;
     RECT  30.72 76.403 30.744 78.419 ;
     RECT  64.32 77.795 64.344 78.467 ;
     RECT  72.6 76.451 72.912 78.565 ;
     RECT  83.4 77.315 83.712 78.565 ;
     RECT  29.184 78.037 29.712 78.611 ;
     RECT  7.8 75.299 8.112 78.613 ;
     RECT  18.6 77.989 19.368 78.613 ;
     RECT  36.96 77.267 36.984 78.613 ;
     RECT  40.2 76.067 40.512 78.613 ;
     RECT  61.68 77.123 62.112 78.613 ;
     RECT  10.752 77.941 10.776 78.659 ;
     RECT  53.088 78.661 53.112 78.803 ;
     RECT  11.856 78.085 11.88 78.853 ;
     RECT  11.856 78.853 12.024 78.899 ;
     RECT  79.392 78.613 79.416 78.899 ;
     RECT  67.2 77.893 70.824 78.947 ;
     RECT  45.6 77.699 45.912 78.997 ;
     RECT  77.376 76.979 78.312 79.045 ;
     RECT  38.928 78.133 38.952 79.141 ;
     RECT  2.4 71.795 2.712 79.189 ;
     RECT  56.4 77.555 56.712 79.189 ;
     RECT  76.896 79.045 78.312 79.189 ;
     RECT  57.84 77.555 57.864 79.235 ;
     RECT  7.8 78.613 8.568 79.283 ;
     RECT  38.736 79.141 38.952 79.283 ;
     RECT  45.456 78.997 45.912 79.331 ;
     RECT  88.224 77.555 89.88 79.427 ;
     RECT  38.784 79.283 38.952 79.475 ;
     RECT  12 78.899 12.024 79.477 ;
     RECT  13.056 77.651 13.512 79.477 ;
     RECT  33.648 76.213 35.256 79.523 ;
     RECT  87.168 78.517 87.192 79.571 ;
     RECT  72.6 78.565 73.512 79.573 ;
     RECT  80.784 74.965 81.768 79.619 ;
     RECT  15.072 75.923 15.768 79.715 ;
     RECT  36.96 78.613 37.32 79.715 ;
     RECT  24 77.507 24.312 79.717 ;
     RECT  64.896 78.805 64.92 79.717 ;
     RECT  67.2 78.947 69.576 79.717 ;
     RECT  74.592 71.939 74.616 79.717 ;
     RECT  15.072 79.715 15.48 79.763 ;
     RECT  64.416 79.717 64.92 79.763 ;
     RECT  88.224 79.427 89.112 79.765 ;
     RECT  48.72 78.037 48.744 79.811 ;
     RECT  74.592 79.717 74.712 79.861 ;
     RECT  47.424 78.565 47.448 79.907 ;
     RECT  12 79.477 13.512 79.955 ;
     RECT  71.808 79.573 73.512 79.955 ;
     RECT  40.2 78.613 41.4 80.003 ;
     RECT  49.872 78.371 51.312 80.147 ;
     RECT  36.96 79.715 37.032 80.149 ;
     RECT  26.544 78.757 26.568 80.197 ;
     RECT  0.144 79.333 0.168 80.243 ;
     RECT  26.544 80.197 26.76 80.243 ;
     RECT  49.872 80.147 49.896 80.243 ;
     RECT  54.96 76.355 54.984 80.291 ;
     RECT  60.864 78.613 62.112 80.341 ;
     RECT  64.416 79.763 64.44 80.387 ;
     RECT  33.648 79.523 35.208 80.483 ;
     RECT  66.384 79.717 69.576 80.483 ;
     RECT  36.768 80.149 37.032 80.725 ;
     RECT  80.784 79.619 81.672 80.725 ;
     RECT  60.24 80.341 62.112 80.771 ;
     RECT  18.6 78.613 20.52 80.819 ;
     RECT  24 79.717 24.936 80.819 ;
     RECT  31.92 79.189 31.944 80.819 ;
     RECT  36.624 80.725 37.032 80.867 ;
     RECT  88.032 79.765 89.112 80.917 ;
     RECT  5.136 80.581 5.16 80.963 ;
     RECT  33.072 80.821 33.096 80.963 ;
     RECT  15.264 79.763 15.48 81.011 ;
     RECT  20.496 80.819 20.52 81.011 ;
     RECT  26.736 80.243 26.76 81.011 ;
     RECT  75.84 79.189 75.864 81.011 ;
     RECT  44.304 79.189 44.328 81.013 ;
     RECT  43.872 81.013 44.328 81.059 ;
     RECT  84.912 80.917 84.936 81.059 ;
     RECT  86.112 80.917 86.136 81.059 ;
     RECT  67.2 80.483 69.576 81.107 ;
     RECT  74.592 79.861 74.76 81.107 ;
     RECT  76.896 79.189 78.696 81.109 ;
     RECT  2.4 79.189 3.672 81.155 ;
     RECT  53.04 80.341 53.064 81.155 ;
     RECT  9.696 79.957 9.72 81.157 ;
     RECT  34.56 80.483 35.208 81.203 ;
     RECT  12.864 79.955 13.512 81.205 ;
     RECT  36.624 80.867 36.792 81.299 ;
     RECT  17.136 80.917 17.16 81.349 ;
     RECT  17.136 81.349 17.352 81.395 ;
     RECT  24 80.819 24.648 81.395 ;
     RECT  60.24 80.771 60.264 81.445 ;
     RECT  71.808 79.955 72.912 81.539 ;
     RECT  80.784 80.725 81.912 81.539 ;
     RECT  87.408 80.917 89.112 81.589 ;
     RECT  76.8 81.109 78.696 81.781 ;
     RECT  36.768 81.299 36.792 81.827 ;
     RECT  59.28 81.445 60.264 81.829 ;
     RECT  61.68 80.771 62.112 81.829 ;
     RECT  9.696 81.157 10.2 81.875 ;
     RECT  55.104 80.533 55.128 81.875 ;
     RECT  40.2 80.003 40.512 81.925 ;
     RECT  67.2 81.107 68.424 81.971 ;
     RECT  59.28 81.829 62.112 82.019 ;
     RECT  31.44 80.965 31.464 82.115 ;
     RECT  59.28 82.019 60.264 82.115 ;
     RECT  85.056 81.445 85.08 82.115 ;
     RECT  87.216 81.589 89.112 82.163 ;
     RECT  61.68 82.019 62.112 82.259 ;
     RECT  12.672 81.205 13.512 82.307 ;
     RECT  80.784 81.539 81.672 82.403 ;
     RECT  2.4 81.155 2.808 82.451 ;
     RECT  48.96 82.069 48.984 82.451 ;
     RECT  17.328 81.395 17.352 82.595 ;
     RECT  10.176 81.875 10.2 82.691 ;
     RECT  24 81.395 24.552 82.691 ;
     RECT  70.8 78.947 70.824 82.691 ;
     RECT  90.144 82.021 90.168 82.739 ;
     RECT  74.592 81.107 74.616 82.789 ;
     RECT  5.088 82.021 5.112 82.835 ;
     RECT  76.8 81.781 78.84 82.835 ;
     RECT  38.976 81.829 39 82.931 ;
     RECT  87.84 82.163 89.112 82.979 ;
     RECT  40.08 81.925 40.512 83.027 ;
     RECT  77.616 82.835 78.84 83.219 ;
     RECT  43.872 81.059 43.896 83.267 ;
     RECT  65.808 82.597 65.832 83.267 ;
     RECT  77.616 83.219 78.696 83.267 ;
     RECT  74.592 82.789 74.808 83.363 ;
     RECT  84.816 82.261 84.84 83.363 ;
     RECT  80.784 82.403 80.952 83.509 ;
     RECT  2.4 82.451 2.712 83.749 ;
     RECT  13.056 82.307 13.512 83.749 ;
     RECT  83.28 78.565 83.712 83.795 ;
     RECT  45.6 79.331 45.912 84.181 ;
     RECT  74.592 83.363 74.616 84.229 ;
     RECT  16.512 83.221 16.536 84.323 ;
     RECT  44.976 84.181 45.912 84.325 ;
     RECT  72.6 81.539 72.912 84.325 ;
     RECT  80.784 83.509 81.672 84.419 ;
     RECT  36.48 83.749 36.504 84.563 ;
     RECT  38.736 83.221 38.76 84.611 ;
     RECT  88.032 82.979 89.112 84.611 ;
     RECT  67.2 81.971 68.376 84.613 ;
     RECT  27.888 83.749 27.912 84.803 ;
     RECT  49.296 83.461 49.32 84.851 ;
     RECT  72 84.325 72.912 84.853 ;
     RECT  74.4 84.229 74.616 84.853 ;
     RECT  7.8 79.283 8.112 84.901 ;
     RECT  24 82.691 24.312 84.901 ;
     RECT  43.296 84.517 43.32 84.901 ;
     RECT  43.296 84.901 43.944 84.947 ;
     RECT  13.056 83.749 13.704 84.995 ;
     RECT  30.72 84.325 30.744 84.995 ;
     RECT  44.976 84.325 46.728 85.139 ;
     RECT  76.368 83.749 76.392 85.139 ;
     RECT  58.704 84.277 58.728 85.283 ;
     RECT  72 84.853 74.616 85.283 ;
     RECT  2.304 83.749 2.712 85.477 ;
     RECT  65.232 83.653 65.256 85.523 ;
     RECT  66.576 84.613 68.376 85.523 ;
     RECT  88.32 84.611 89.112 85.523 ;
     RECT  60.24 82.115 60.264 85.669 ;
     RECT  61.8 82.259 62.112 85.669 ;
     RECT  2.304 85.477 3.624 85.955 ;
     RECT  13.056 84.995 13.656 85.957 ;
     RECT  60.24 85.669 62.112 85.957 ;
     RECT  12.288 85.957 13.656 86.005 ;
     RECT  24 84.901 24.504 86.051 ;
     RECT  7.152 84.901 8.112 86.195 ;
     RECT  44.976 85.139 45.912 86.195 ;
     RECT  88.56 85.523 89.112 86.195 ;
     RECT  54.72 84.277 54.744 86.197 ;
     RECT  4.704 84.709 4.728 86.341 ;
     RECT  4.704 86.341 5.496 86.437 ;
     RECT  60.24 85.957 62.616 86.437 ;
     RECT  59.856 86.437 62.616 86.483 ;
     RECT  49.104 85.429 49.128 86.485 ;
     RECT  2.4 85.955 3.624 86.531 ;
     RECT  15.264 81.011 15.288 86.533 ;
     RECT  15.216 86.533 15.288 86.581 ;
     RECT  56.4 79.189 56.808 86.581 ;
     RECT  49.008 86.485 49.128 86.627 ;
     RECT  77.616 83.267 78.312 86.629 ;
     RECT  77.616 86.629 78.6 86.675 ;
     RECT  64.032 85.141 64.056 86.677 ;
     RECT  64.032 86.677 65.016 86.723 ;
     RECT  18.6 80.819 18.912 86.725 ;
     RECT  19.92 86.005 19.944 86.725 ;
     RECT  21.072 86.485 21.096 86.725 ;
     RECT  72.6 85.283 74.616 86.725 ;
     RECT  17.328 84.325 17.352 86.771 ;
     RECT  18.6 86.725 21.096 86.771 ;
     RECT  60.96 86.483 62.616 86.771 ;
     RECT  90.432 85.957 90.456 86.917 ;
     RECT  54.72 86.197 54.984 87.011 ;
     RECT  78 86.675 78.6 87.109 ;
     RECT  29.4 78.611 29.712 87.157 ;
     RECT  40.2 83.027 40.512 87.157 ;
     RECT  51 80.147 51.312 87.157 ;
     RECT  80.784 84.419 80.808 87.157 ;
     RECT  26.208 84.133 26.232 87.203 ;
     RECT  52.992 85.477 53.016 87.203 ;
     RECT  64.992 86.723 65.016 87.203 ;
     RECT  24 86.051 24.408 87.251 ;
     RECT  54.96 87.011 54.984 87.251 ;
     RECT  56.4 86.581 57.576 87.251 ;
     RECT  80.592 87.157 80.808 87.253 ;
     RECT  80.592 87.253 80.904 87.395 ;
     RECT  12.288 86.005 14.04 87.445 ;
     RECT  20.64 86.771 21.096 87.539 ;
     RECT  84.72 85.957 84.744 87.539 ;
     RECT  34.56 81.203 35.112 87.541 ;
     RECT  31.872 86.005 31.896 87.587 ;
     RECT  67.2 85.523 67.512 87.637 ;
     RECT  61.8 86.771 62.616 87.683 ;
     RECT  78 87.109 78.936 87.779 ;
     RECT  67.2 87.637 68.088 87.781 ;
     RECT  47.088 86.725 47.112 87.827 ;
     RECT  61.8 87.683 62.472 87.827 ;
     RECT  72.288 86.725 74.616 87.827 ;
     RECT  82.032 87.157 82.056 87.827 ;
     RECT  2.4 86.531 2.808 87.875 ;
     RECT  34.56 87.541 35.88 87.875 ;
     RECT  90.432 86.917 90.552 87.971 ;
     RECT  4.704 86.437 5.736 87.973 ;
     RECT  7.8 86.195 8.112 87.973 ;
     RECT  59.856 86.483 59.88 88.069 ;
     RECT  42.144 83.749 42.168 88.115 ;
     RECT  76.608 85.957 76.632 88.115 ;
     RECT  10.848 87.205 10.872 88.211 ;
     RECT  21.072 87.539 21.096 88.211 ;
     RECT  7.2 87.973 8.112 88.213 ;
     RECT  18.6 86.771 19.656 88.213 ;
     RECT  67.2 87.781 68.568 88.213 ;
     RECT  4.176 87.973 5.736 88.261 ;
     RECT  6.816 88.213 8.112 88.261 ;
     RECT  88.8 86.195 89.112 88.261 ;
     RECT  28.56 87.157 29.712 88.307 ;
     RECT  34.704 87.875 35.88 88.355 ;
     RECT  39.792 87.157 40.512 88.403 ;
     RECT  72.6 87.827 74.616 88.403 ;
     RECT  86.016 87.109 86.04 88.403 ;
     RECT  15.216 86.581 15.96 88.451 ;
     RECT  15.216 88.451 15.816 88.499 ;
     RECT  59.856 88.069 60.6 88.595 ;
     RECT  80.592 87.395 80.76 88.645 ;
     RECT  80.592 88.645 81 88.883 ;
     RECT  85.488 88.741 85.512 88.883 ;
     RECT  10.416 88.309 10.44 88.885 ;
     RECT  56.4 87.251 56.952 88.885 ;
     RECT  66.768 88.213 68.568 88.931 ;
     RECT  32.496 88.261 32.52 88.979 ;
     RECT  15.648 88.499 15.816 89.219 ;
     RECT  12 87.445 14.04 89.461 ;
     RECT  17.76 88.213 19.656 89.461 ;
     RECT  24 87.251 24.312 89.461 ;
     RECT  83.4 83.795 83.712 89.461 ;
     RECT  76.368 88.885 76.392 89.843 ;
     RECT  9.696 88.885 10.44 89.845 ;
     RECT  11.616 89.461 14.136 89.845 ;
     RECT  17.76 89.461 19.992 89.891 ;
     RECT  88.32 88.261 89.112 89.987 ;
     RECT  18.6 89.891 19.992 90.083 ;
     RECT  47.856 89.269 47.88 90.083 ;
     RECT  32.736 89.845 32.76 90.421 ;
     RECT  32.736 90.421 33.096 90.467 ;
     RECT  28.128 89.509 28.152 90.515 ;
     RECT  68.544 88.931 68.568 90.517 ;
     RECT  72.6 88.403 73.656 90.517 ;
     RECT  68.544 90.517 68.712 90.563 ;
     RECT  4.176 88.261 8.112 90.565 ;
     RECT  9.264 89.845 14.136 90.565 ;
     RECT  15.168 89.461 15.192 90.565 ;
     RECT  18.6 90.083 19.656 90.611 ;
     RECT  33.072 90.467 33.096 90.803 ;
     RECT  90.432 87.971 90.456 90.805 ;
     RECT  90.432 90.805 90.6 90.851 ;
     RECT  4.176 90.565 15.192 90.899 ;
     RECT  61.8 87.827 62.28 90.901 ;
     RECT  72.6 90.517 73.8 90.949 ;
     RECT  18.6 90.611 19.512 91.141 ;
     RECT  40.2 88.403 40.512 91.189 ;
     RECT  88.8 89.987 89.112 91.189 ;
     RECT  4.176 90.899 8.112 91.235 ;
     RECT  9.264 90.899 15.192 91.235 ;
     RECT  24 89.461 24.552 91.235 ;
     RECT  56.4 88.885 57 91.235 ;
     RECT  78 87.779 78.6 91.235 ;
     RECT  80.64 88.883 80.76 91.379 ;
     RECT  59.856 88.595 59.88 91.429 ;
     RECT  61.44 90.901 62.28 91.429 ;
     RECT  59.856 91.429 62.28 91.475 ;
     RECT  34.8 88.355 35.88 91.619 ;
     RECT  66.768 88.931 67.512 91.621 ;
     RECT  68.688 90.563 68.712 91.621 ;
     RECT  43.92 84.947 43.944 91.717 ;
     RECT  41.568 91.093 41.592 91.763 ;
     RECT  66.768 91.621 68.712 91.811 ;
     RECT  60.672 91.475 62.28 91.859 ;
     RECT  75.936 89.989 75.96 91.859 ;
     RECT  17.616 91.141 19.512 91.955 ;
     RECT  39.888 91.189 40.512 92.099 ;
     RECT  84.912 90.517 84.936 92.099 ;
     RECT  91.632 84.325 91.656 92.099 ;
     RECT  4.176 91.235 5.688 92.387 ;
     RECT  9.264 91.235 14.904 92.387 ;
     RECT  66.768 91.811 67.944 92.387 ;
     RECT  4.224 92.387 5.688 92.435 ;
     RECT  54.864 90.565 54.888 92.435 ;
     RECT  83.28 89.461 83.712 92.435 ;
     RECT  24 91.235 24.312 92.437 ;
     RECT  72.384 90.949 73.8 92.483 ;
     RECT  4.224 92.435 4.968 92.723 ;
     RECT  9.312 92.387 14.904 92.819 ;
     RECT  34.8 91.619 35.112 92.821 ;
     RECT  72.6 92.483 73.8 92.869 ;
     RECT  27.84 91.813 27.864 92.915 ;
     RECT  63.984 91.141 64.008 92.915 ;
     RECT  7.2 91.235 8.112 92.963 ;
     RECT  9.312 92.819 14.856 92.963 ;
     RECT  16.656 92.005 16.68 92.963 ;
     RECT  21.6 91.717 21.624 92.963 ;
     RECT  23.472 92.437 24.312 92.963 ;
     RECT  26.112 92.293 26.136 92.963 ;
     RECT  43.584 91.717 43.944 92.963 ;
     RECT  50.256 87.157 51.312 92.963 ;
     RECT  61.8 91.859 62.28 92.963 ;
     RECT  79.584 91.333 79.608 92.963 ;
     RECT  80.64 91.379 80.664 93.203 ;
     RECT  4.224 92.723 4.728 93.347 ;
     RECT  72.6 92.869 74.04 93.443 ;
     RECT  40.2 92.099 40.512 93.445 ;
     RECT  46.992 91.717 47.016 93.491 ;
     RECT  72.6 93.443 73.8 93.491 ;
     RECT  18.6 91.955 19.512 93.539 ;
     RECT  43.584 92.963 43.608 93.539 ;
     RECT  48.432 92.293 48.456 93.539 ;
     RECT  65.76 90.421 65.784 93.539 ;
     RECT  90.576 90.851 90.6 93.539 ;
     RECT  66.768 92.387 67.512 93.635 ;
     RECT  67.2 93.635 67.512 93.925 ;
     RECT  29.4 88.307 29.712 94.021 ;
     RECT  34.8 92.821 35.352 94.021 ;
     RECT  18.6 93.539 19.08 94.115 ;
     RECT  60.672 91.859 60.696 94.115 ;
     RECT  4.224 93.347 4.248 94.307 ;
     RECT  63.264 93.445 63.288 94.355 ;
     RECT  72.6 93.491 73.176 94.451 ;
     RECT  75.696 93.925 75.72 94.451 ;
     RECT  9.312 92.963 14.808 94.499 ;
     RECT  7.344 92.963 8.112 94.501 ;
     RECT  7.248 94.501 8.112 94.549 ;
     RECT  85.824 93.061 85.848 94.595 ;
     RECT  6.96 94.549 8.112 94.597 ;
     RECT  88.8 91.189 89.544 94.597 ;
     RECT  5.808 94.549 5.832 94.645 ;
     RECT  6.816 94.597 8.112 94.645 ;
     RECT  9.312 94.499 13.992 94.691 ;
     RECT  29.4 94.021 29.832 94.691 ;
     RECT  39.84 93.445 40.512 94.691 ;
     RECT  72.6 94.451 73.128 94.691 ;
     RECT  34.8 94.021 35.88 94.739 ;
     RECT  38.736 94.501 38.76 94.739 ;
     RECT  88.8 94.597 90.072 94.787 ;
     RECT  67.2 93.925 67.848 94.979 ;
     RECT  5.808 94.645 8.328 95.029 ;
     RECT  9.312 94.691 13.512 95.029 ;
     RECT  2.4 87.875 2.712 95.049 ;
     RECT  18.6 94.115 18.912 95.049 ;
     RECT  24 92.963 24.312 95.049 ;
     RECT  29.4 94.691 29.712 95.049 ;
     RECT  34.8 94.739 35.112 95.049 ;
     RECT  40.2 94.691 40.512 95.049 ;
     RECT  45.6 86.195 45.912 95.049 ;
     RECT  51 92.963 51.312 95.049 ;
     RECT  56.4 91.235 56.712 95.049 ;
     RECT  61.8 92.963 62.112 95.049 ;
     RECT  67.2 94.979 67.512 95.049 ;
     RECT  72.6 94.691 72.912 95.049 ;
     RECT  78 91.235 78.312 95.049 ;
     RECT  83.4 92.435 83.712 95.049 ;
     RECT  88.8 94.787 89.112 95.049 ;
     RECT  94.2 42.707 94.512 95.049 ;
     RECT  2.4 95.049 2.52 95.063 ;
     RECT  18.6 95.049 18.72 95.063 ;
     RECT  24 95.049 24.12 95.063 ;
     RECT  29.4 95.049 29.52 95.063 ;
     RECT  34.8 95.049 34.92 95.063 ;
     RECT  40.2 95.049 40.32 95.063 ;
     RECT  45.6 95.049 45.72 95.063 ;
     RECT  51 95.049 51.12 95.063 ;
     RECT  56.4 95.049 56.52 95.063 ;
     RECT  61.8 95.049 61.92 95.063 ;
     RECT  67.2 95.049 67.32 95.063 ;
     RECT  72.6 95.049 72.72 95.063 ;
     RECT  78 95.049 78.12 95.063 ;
     RECT  83.4 95.049 83.52 95.063 ;
     RECT  88.8 95.049 88.92 95.063 ;
     RECT  94.2 95.049 94.32 95.063 ;
     RECT  5.808 95.029 13.512 95.125 ;
     RECT  5.712 95.125 13.512 97.168 ;
  END
END qkd_kv_grp_ctl
END LIBRARY
